VERSION 5.8 ;
BUSBITCHARS "[]" ;
DIVIDERCHAR "/" ;
UNITS
    DATABASE MICRONS 1000 ;
END UNITS

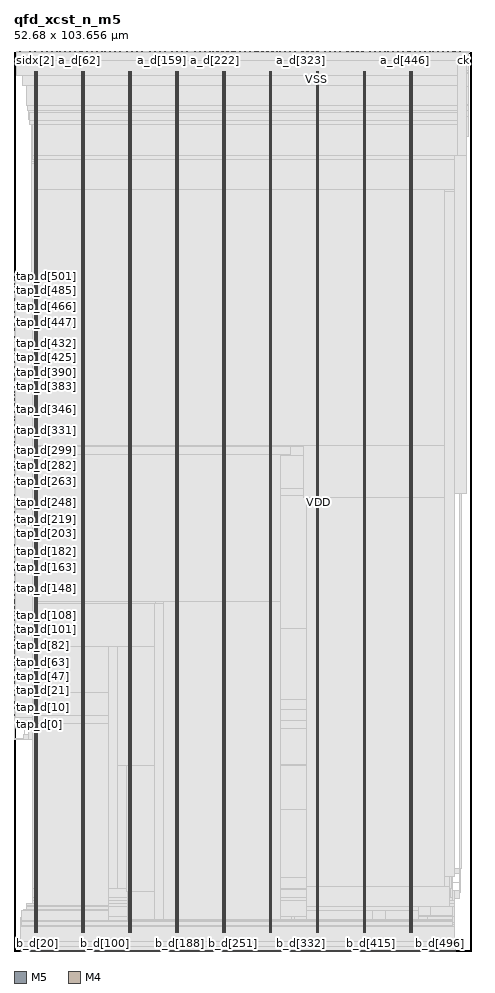
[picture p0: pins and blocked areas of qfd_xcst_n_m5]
MACRO qfd_xcst_n_m5
  FOREIGN qfd_xcst_n_m5 0 0 ;
  CLASS BLOCK ;
  SIZE 52.68 BY 103.656 ;
  PIN a_d[0]
    DIRECTION OUTPUT ;
    USE SIGNAL ;
    PORT
      LAYER M5 ;
        RECT  1.44 103.572 1.464 103.656 ;
    END
  END a_d[0]
  PIN a_d[100]
    DIRECTION OUTPUT ;
    USE SIGNAL ;
    PORT
      LAYER M5 ;
        RECT  11.232 103.572 11.256 103.656 ;
    END
  END a_d[100]
  PIN a_d[101]
    DIRECTION OUTPUT ;
    USE SIGNAL ;
    PORT
      LAYER M5 ;
        RECT  11.328 103.572 11.352 103.656 ;
    END
  END a_d[101]
  PIN a_d[102]
    DIRECTION OUTPUT ;
    USE SIGNAL ;
    PORT
      LAYER M5 ;
        RECT  11.424 103.572 11.448 103.656 ;
    END
  END a_d[102]
  PIN a_d[103]
    DIRECTION OUTPUT ;
    USE SIGNAL ;
    PORT
      LAYER M5 ;
        RECT  11.52 103.572 11.544 103.656 ;
    END
  END a_d[103]
  PIN a_d[104]
    DIRECTION OUTPUT ;
    USE SIGNAL ;
    PORT
      LAYER M5 ;
        RECT  11.616 103.572 11.64 103.656 ;
    END
  END a_d[104]
  PIN a_d[105]
    DIRECTION OUTPUT ;
    USE SIGNAL ;
    PORT
      LAYER M5 ;
        RECT  11.712 103.572 11.736 103.656 ;
    END
  END a_d[105]
  PIN a_d[106]
    DIRECTION OUTPUT ;
    USE SIGNAL ;
    PORT
      LAYER M5 ;
        RECT  11.808 103.572 11.832 103.656 ;
    END
  END a_d[106]
  PIN a_d[107]
    DIRECTION OUTPUT ;
    USE SIGNAL ;
    PORT
      LAYER M5 ;
        RECT  11.904 103.572 11.928 103.656 ;
    END
  END a_d[107]
  PIN a_d[108]
    DIRECTION OUTPUT ;
    USE SIGNAL ;
    PORT
      LAYER M5 ;
        RECT  12 103.572 12.024 103.656 ;
    END
  END a_d[108]
  PIN a_d[109]
    DIRECTION OUTPUT ;
    USE SIGNAL ;
    PORT
      LAYER M5 ;
        RECT  12.096 103.572 12.12 103.656 ;
    END
  END a_d[109]
  PIN a_d[10]
    DIRECTION OUTPUT ;
    USE SIGNAL ;
    PORT
      LAYER M5 ;
        RECT  2.4 103.572 2.424 103.656 ;
    END
  END a_d[10]
  PIN a_d[110]
    DIRECTION OUTPUT ;
    USE SIGNAL ;
    PORT
      LAYER M5 ;
        RECT  12.192 103.572 12.216 103.656 ;
    END
  END a_d[110]
  PIN a_d[111]
    DIRECTION OUTPUT ;
    USE SIGNAL ;
    PORT
      LAYER M5 ;
        RECT  12.288 103.572 12.312 103.656 ;
    END
  END a_d[111]
  PIN a_d[112]
    DIRECTION OUTPUT ;
    USE SIGNAL ;
    PORT
      LAYER M5 ;
        RECT  12.384 103.572 12.408 103.656 ;
    END
  END a_d[112]
  PIN a_d[113]
    DIRECTION OUTPUT ;
    USE SIGNAL ;
    PORT
      LAYER M5 ;
        RECT  12.48 103.572 12.504 103.656 ;
    END
  END a_d[113]
  PIN a_d[114]
    DIRECTION OUTPUT ;
    USE SIGNAL ;
    PORT
      LAYER M5 ;
        RECT  12.576 103.572 12.6 103.656 ;
    END
  END a_d[114]
  PIN a_d[115]
    DIRECTION OUTPUT ;
    USE SIGNAL ;
    PORT
      LAYER M5 ;
        RECT  12.672 103.572 12.696 103.656 ;
    END
  END a_d[115]
  PIN a_d[116]
    DIRECTION OUTPUT ;
    USE SIGNAL ;
    PORT
      LAYER M5 ;
        RECT  12.816 103.572 12.84 103.656 ;
    END
  END a_d[116]
  PIN a_d[117]
    DIRECTION OUTPUT ;
    USE SIGNAL ;
    PORT
      LAYER M5 ;
        RECT  12.912 103.572 12.936 103.656 ;
    END
  END a_d[117]
  PIN a_d[118]
    DIRECTION OUTPUT ;
    USE SIGNAL ;
    PORT
      LAYER M5 ;
        RECT  13.008 103.572 13.032 103.656 ;
    END
  END a_d[118]
  PIN a_d[119]
    DIRECTION OUTPUT ;
    USE SIGNAL ;
    PORT
      LAYER M5 ;
        RECT  13.104 103.572 13.128 103.656 ;
    END
  END a_d[119]
  PIN a_d[11]
    DIRECTION OUTPUT ;
    USE SIGNAL ;
    PORT
      LAYER M5 ;
        RECT  2.496 103.572 2.52 103.656 ;
    END
  END a_d[11]
  PIN a_d[120]
    DIRECTION OUTPUT ;
    USE SIGNAL ;
    PORT
      LAYER M5 ;
        RECT  13.2 103.572 13.224 103.656 ;
    END
  END a_d[120]
  PIN a_d[121]
    DIRECTION OUTPUT ;
    USE SIGNAL ;
    PORT
      LAYER M5 ;
        RECT  13.296 103.572 13.32 103.656 ;
    END
  END a_d[121]
  PIN a_d[122]
    DIRECTION OUTPUT ;
    USE SIGNAL ;
    PORT
      LAYER M5 ;
        RECT  13.392 103.572 13.416 103.656 ;
    END
  END a_d[122]
  PIN a_d[123]
    DIRECTION OUTPUT ;
    USE SIGNAL ;
    PORT
      LAYER M5 ;
        RECT  13.488 103.572 13.512 103.656 ;
    END
  END a_d[123]
  PIN a_d[124]
    DIRECTION OUTPUT ;
    USE SIGNAL ;
    PORT
      LAYER M5 ;
        RECT  13.584 103.572 13.608 103.656 ;
    END
  END a_d[124]
  PIN a_d[125]
    DIRECTION OUTPUT ;
    USE SIGNAL ;
    PORT
      LAYER M5 ;
        RECT  13.68 103.572 13.704 103.656 ;
    END
  END a_d[125]
  PIN a_d[126]
    DIRECTION OUTPUT ;
    USE SIGNAL ;
    PORT
      LAYER M5 ;
        RECT  13.776 103.572 13.8 103.656 ;
    END
  END a_d[126]
  PIN a_d[127]
    DIRECTION OUTPUT ;
    USE SIGNAL ;
    PORT
      LAYER M5 ;
        RECT  13.872 103.572 13.896 103.656 ;
    END
  END a_d[127]
  PIN a_d[128]
    DIRECTION OUTPUT ;
    USE SIGNAL ;
    PORT
      LAYER M5 ;
        RECT  13.968 103.572 13.992 103.656 ;
    END
  END a_d[128]
  PIN a_d[129]
    DIRECTION OUTPUT ;
    USE SIGNAL ;
    PORT
      LAYER M5 ;
        RECT  14.064 103.572 14.088 103.656 ;
    END
  END a_d[129]
  PIN a_d[12]
    DIRECTION OUTPUT ;
    USE SIGNAL ;
    PORT
      LAYER M5 ;
        RECT  2.592 103.572 2.616 103.656 ;
    END
  END a_d[12]
  PIN a_d[130]
    DIRECTION OUTPUT ;
    USE SIGNAL ;
    PORT
      LAYER M5 ;
        RECT  14.16 103.572 14.184 103.656 ;
    END
  END a_d[130]
  PIN a_d[131]
    DIRECTION OUTPUT ;
    USE SIGNAL ;
    PORT
      LAYER M5 ;
        RECT  14.256 103.572 14.28 103.656 ;
    END
  END a_d[131]
  PIN a_d[132]
    DIRECTION OUTPUT ;
    USE SIGNAL ;
    PORT
      LAYER M5 ;
        RECT  14.352 103.572 14.376 103.656 ;
    END
  END a_d[132]
  PIN a_d[133]
    DIRECTION OUTPUT ;
    USE SIGNAL ;
    PORT
      LAYER M5 ;
        RECT  14.448 103.572 14.472 103.656 ;
    END
  END a_d[133]
  PIN a_d[134]
    DIRECTION OUTPUT ;
    USE SIGNAL ;
    PORT
      LAYER M5 ;
        RECT  14.544 103.572 14.568 103.656 ;
    END
  END a_d[134]
  PIN a_d[135]
    DIRECTION OUTPUT ;
    USE SIGNAL ;
    PORT
      LAYER M5 ;
        RECT  14.64 103.572 14.664 103.656 ;
    END
  END a_d[135]
  PIN a_d[136]
    DIRECTION OUTPUT ;
    USE SIGNAL ;
    PORT
      LAYER M5 ;
        RECT  14.736 103.572 14.76 103.656 ;
    END
  END a_d[136]
  PIN a_d[137]
    DIRECTION OUTPUT ;
    USE SIGNAL ;
    PORT
      LAYER M5 ;
        RECT  14.832 103.572 14.856 103.656 ;
    END
  END a_d[137]
  PIN a_d[138]
    DIRECTION OUTPUT ;
    USE SIGNAL ;
    PORT
      LAYER M5 ;
        RECT  14.928 103.572 14.952 103.656 ;
    END
  END a_d[138]
  PIN a_d[139]
    DIRECTION OUTPUT ;
    USE SIGNAL ;
    PORT
      LAYER M5 ;
        RECT  15.024 103.572 15.048 103.656 ;
    END
  END a_d[139]
  PIN a_d[13]
    DIRECTION OUTPUT ;
    USE SIGNAL ;
    PORT
      LAYER M5 ;
        RECT  2.736 103.572 2.76 103.656 ;
    END
  END a_d[13]
  PIN a_d[140]
    DIRECTION OUTPUT ;
    USE SIGNAL ;
    PORT
      LAYER M5 ;
        RECT  15.12 103.572 15.144 103.656 ;
    END
  END a_d[140]
  PIN a_d[141]
    DIRECTION OUTPUT ;
    USE SIGNAL ;
    PORT
      LAYER M5 ;
        RECT  15.216 103.572 15.24 103.656 ;
    END
  END a_d[141]
  PIN a_d[142]
    DIRECTION OUTPUT ;
    USE SIGNAL ;
    PORT
      LAYER M5 ;
        RECT  15.36 103.572 15.384 103.656 ;
    END
  END a_d[142]
  PIN a_d[143]
    DIRECTION OUTPUT ;
    USE SIGNAL ;
    PORT
      LAYER M5 ;
        RECT  15.456 103.572 15.48 103.656 ;
    END
  END a_d[143]
  PIN a_d[144]
    DIRECTION OUTPUT ;
    USE SIGNAL ;
    PORT
      LAYER M5 ;
        RECT  15.552 103.572 15.576 103.656 ;
    END
  END a_d[144]
  PIN a_d[145]
    DIRECTION OUTPUT ;
    USE SIGNAL ;
    PORT
      LAYER M5 ;
        RECT  15.648 103.572 15.672 103.656 ;
    END
  END a_d[145]
  PIN a_d[146]
    DIRECTION OUTPUT ;
    USE SIGNAL ;
    PORT
      LAYER M5 ;
        RECT  15.744 103.572 15.768 103.656 ;
    END
  END a_d[146]
  PIN a_d[147]
    DIRECTION OUTPUT ;
    USE SIGNAL ;
    PORT
      LAYER M5 ;
        RECT  15.84 103.572 15.864 103.656 ;
    END
  END a_d[147]
  PIN a_d[148]
    DIRECTION OUTPUT ;
    USE SIGNAL ;
    PORT
      LAYER M5 ;
        RECT  15.936 103.572 15.96 103.656 ;
    END
  END a_d[148]
  PIN a_d[149]
    DIRECTION OUTPUT ;
    USE SIGNAL ;
    PORT
      LAYER M5 ;
        RECT  16.032 103.572 16.056 103.656 ;
    END
  END a_d[149]
  PIN a_d[14]
    DIRECTION OUTPUT ;
    USE SIGNAL ;
    PORT
      LAYER M5 ;
        RECT  2.832 103.572 2.856 103.656 ;
    END
  END a_d[14]
  PIN a_d[150]
    DIRECTION OUTPUT ;
    USE SIGNAL ;
    PORT
      LAYER M5 ;
        RECT  16.128 103.572 16.152 103.656 ;
    END
  END a_d[150]
  PIN a_d[151]
    DIRECTION OUTPUT ;
    USE SIGNAL ;
    PORT
      LAYER M5 ;
        RECT  16.224 103.572 16.248 103.656 ;
    END
  END a_d[151]
  PIN a_d[152]
    DIRECTION OUTPUT ;
    USE SIGNAL ;
    PORT
      LAYER M5 ;
        RECT  16.32 103.572 16.344 103.656 ;
    END
  END a_d[152]
  PIN a_d[153]
    DIRECTION OUTPUT ;
    USE SIGNAL ;
    PORT
      LAYER M5 ;
        RECT  16.416 103.572 16.44 103.656 ;
    END
  END a_d[153]
  PIN a_d[154]
    DIRECTION OUTPUT ;
    USE SIGNAL ;
    PORT
      LAYER M5 ;
        RECT  16.512 103.572 16.536 103.656 ;
    END
  END a_d[154]
  PIN a_d[155]
    DIRECTION OUTPUT ;
    USE SIGNAL ;
    PORT
      LAYER M5 ;
        RECT  16.608 103.572 16.632 103.656 ;
    END
  END a_d[155]
  PIN a_d[156]
    DIRECTION OUTPUT ;
    USE SIGNAL ;
    PORT
      LAYER M5 ;
        RECT  16.704 103.572 16.728 103.656 ;
    END
  END a_d[156]
  PIN a_d[157]
    DIRECTION OUTPUT ;
    USE SIGNAL ;
    PORT
      LAYER M5 ;
        RECT  16.8 103.572 16.824 103.656 ;
    END
  END a_d[157]
  PIN a_d[158]
    DIRECTION OUTPUT ;
    USE SIGNAL ;
    PORT
      LAYER M5 ;
        RECT  16.896 103.572 16.92 103.656 ;
    END
  END a_d[158]
  PIN a_d[159]
    DIRECTION OUTPUT ;
    USE SIGNAL ;
    PORT
      LAYER M5 ;
        RECT  16.992 103.572 17.016 103.656 ;
    END
  END a_d[159]
  PIN a_d[15]
    DIRECTION OUTPUT ;
    USE SIGNAL ;
    PORT
      LAYER M5 ;
        RECT  2.928 103.572 2.952 103.656 ;
    END
  END a_d[15]
  PIN a_d[160]
    DIRECTION OUTPUT ;
    USE SIGNAL ;
    PORT
      LAYER M5 ;
        RECT  17.088 103.572 17.112 103.656 ;
    END
  END a_d[160]
  PIN a_d[161]
    DIRECTION OUTPUT ;
    USE SIGNAL ;
    PORT
      LAYER M5 ;
        RECT  17.184 103.572 17.208 103.656 ;
    END
  END a_d[161]
  PIN a_d[162]
    DIRECTION OUTPUT ;
    USE SIGNAL ;
    PORT
      LAYER M5 ;
        RECT  17.28 103.572 17.304 103.656 ;
    END
  END a_d[162]
  PIN a_d[163]
    DIRECTION OUTPUT ;
    USE SIGNAL ;
    PORT
      LAYER M5 ;
        RECT  17.376 103.572 17.4 103.656 ;
    END
  END a_d[163]
  PIN a_d[164]
    DIRECTION OUTPUT ;
    USE SIGNAL ;
    PORT
      LAYER M5 ;
        RECT  17.472 103.572 17.496 103.656 ;
    END
  END a_d[164]
  PIN a_d[165]
    DIRECTION OUTPUT ;
    USE SIGNAL ;
    PORT
      LAYER M5 ;
        RECT  17.568 103.572 17.592 103.656 ;
    END
  END a_d[165]
  PIN a_d[166]
    DIRECTION OUTPUT ;
    USE SIGNAL ;
    PORT
      LAYER M5 ;
        RECT  17.664 103.572 17.688 103.656 ;
    END
  END a_d[166]
  PIN a_d[167]
    DIRECTION OUTPUT ;
    USE SIGNAL ;
    PORT
      LAYER M5 ;
        RECT  17.808 103.572 17.832 103.656 ;
    END
  END a_d[167]
  PIN a_d[168]
    DIRECTION OUTPUT ;
    USE SIGNAL ;
    PORT
      LAYER M5 ;
        RECT  17.904 103.572 17.928 103.656 ;
    END
  END a_d[168]
  PIN a_d[169]
    DIRECTION OUTPUT ;
    USE SIGNAL ;
    PORT
      LAYER M5 ;
        RECT  18 103.572 18.024 103.656 ;
    END
  END a_d[169]
  PIN a_d[16]
    DIRECTION OUTPUT ;
    USE SIGNAL ;
    PORT
      LAYER M5 ;
        RECT  3.024 103.572 3.048 103.656 ;
    END
  END a_d[16]
  PIN a_d[170]
    DIRECTION OUTPUT ;
    USE SIGNAL ;
    PORT
      LAYER M5 ;
        RECT  18.096 103.572 18.12 103.656 ;
    END
  END a_d[170]
  PIN a_d[171]
    DIRECTION OUTPUT ;
    USE SIGNAL ;
    PORT
      LAYER M5 ;
        RECT  18.192 103.572 18.216 103.656 ;
    END
  END a_d[171]
  PIN a_d[172]
    DIRECTION OUTPUT ;
    USE SIGNAL ;
    PORT
      LAYER M5 ;
        RECT  18.288 103.572 18.312 103.656 ;
    END
  END a_d[172]
  PIN a_d[173]
    DIRECTION OUTPUT ;
    USE SIGNAL ;
    PORT
      LAYER M5 ;
        RECT  18.384 103.572 18.408 103.656 ;
    END
  END a_d[173]
  PIN a_d[174]
    DIRECTION OUTPUT ;
    USE SIGNAL ;
    PORT
      LAYER M5 ;
        RECT  18.48 103.572 18.504 103.656 ;
    END
  END a_d[174]
  PIN a_d[175]
    DIRECTION OUTPUT ;
    USE SIGNAL ;
    PORT
      LAYER M5 ;
        RECT  18.576 103.572 18.6 103.656 ;
    END
  END a_d[175]
  PIN a_d[176]
    DIRECTION OUTPUT ;
    USE SIGNAL ;
    PORT
      LAYER M5 ;
        RECT  18.672 103.572 18.696 103.656 ;
    END
  END a_d[176]
  PIN a_d[177]
    DIRECTION OUTPUT ;
    USE SIGNAL ;
    PORT
      LAYER M5 ;
        RECT  18.768 103.572 18.792 103.656 ;
    END
  END a_d[177]
  PIN a_d[178]
    DIRECTION OUTPUT ;
    USE SIGNAL ;
    PORT
      LAYER M5 ;
        RECT  18.864 103.572 18.888 103.656 ;
    END
  END a_d[178]
  PIN a_d[179]
    DIRECTION OUTPUT ;
    USE SIGNAL ;
    PORT
      LAYER M5 ;
        RECT  18.96 103.572 18.984 103.656 ;
    END
  END a_d[179]
  PIN a_d[17]
    DIRECTION OUTPUT ;
    USE SIGNAL ;
    PORT
      LAYER M5 ;
        RECT  3.12 103.572 3.144 103.656 ;
    END
  END a_d[17]
  PIN a_d[180]
    DIRECTION OUTPUT ;
    USE SIGNAL ;
    PORT
      LAYER M5 ;
        RECT  19.056 103.572 19.08 103.656 ;
    END
  END a_d[180]
  PIN a_d[181]
    DIRECTION OUTPUT ;
    USE SIGNAL ;
    PORT
      LAYER M5 ;
        RECT  19.152 103.572 19.176 103.656 ;
    END
  END a_d[181]
  PIN a_d[182]
    DIRECTION OUTPUT ;
    USE SIGNAL ;
    PORT
      LAYER M5 ;
        RECT  19.248 103.572 19.272 103.656 ;
    END
  END a_d[182]
  PIN a_d[183]
    DIRECTION OUTPUT ;
    USE SIGNAL ;
    PORT
      LAYER M5 ;
        RECT  19.344 103.572 19.368 103.656 ;
    END
  END a_d[183]
  PIN a_d[184]
    DIRECTION OUTPUT ;
    USE SIGNAL ;
    PORT
      LAYER M5 ;
        RECT  19.44 103.572 19.464 103.656 ;
    END
  END a_d[184]
  PIN a_d[185]
    DIRECTION OUTPUT ;
    USE SIGNAL ;
    PORT
      LAYER M5 ;
        RECT  19.536 103.572 19.56 103.656 ;
    END
  END a_d[185]
  PIN a_d[186]
    DIRECTION OUTPUT ;
    USE SIGNAL ;
    PORT
      LAYER M5 ;
        RECT  19.632 103.572 19.656 103.656 ;
    END
  END a_d[186]
  PIN a_d[187]
    DIRECTION OUTPUT ;
    USE SIGNAL ;
    PORT
      LAYER M5 ;
        RECT  19.728 103.572 19.752 103.656 ;
    END
  END a_d[187]
  PIN a_d[188]
    DIRECTION OUTPUT ;
    USE SIGNAL ;
    PORT
      LAYER M5 ;
        RECT  19.824 103.572 19.848 103.656 ;
    END
  END a_d[188]
  PIN a_d[189]
    DIRECTION OUTPUT ;
    USE SIGNAL ;
    PORT
      LAYER M5 ;
        RECT  19.92 103.572 19.944 103.656 ;
    END
  END a_d[189]
  PIN a_d[18]
    DIRECTION OUTPUT ;
    USE SIGNAL ;
    PORT
      LAYER M5 ;
        RECT  3.216 103.572 3.24 103.656 ;
    END
  END a_d[18]
  PIN a_d[190]
    DIRECTION OUTPUT ;
    USE SIGNAL ;
    PORT
      LAYER M5 ;
        RECT  20.016 103.572 20.04 103.656 ;
    END
  END a_d[190]
  PIN a_d[191]
    DIRECTION OUTPUT ;
    USE SIGNAL ;
    PORT
      LAYER M5 ;
        RECT  20.112 103.572 20.136 103.656 ;
    END
  END a_d[191]
  PIN a_d[192]
    DIRECTION OUTPUT ;
    USE SIGNAL ;
    PORT
      LAYER M5 ;
        RECT  20.208 103.572 20.232 103.656 ;
    END
  END a_d[192]
  PIN a_d[193]
    DIRECTION OUTPUT ;
    USE SIGNAL ;
    PORT
      LAYER M5 ;
        RECT  20.352 103.572 20.376 103.656 ;
    END
  END a_d[193]
  PIN a_d[194]
    DIRECTION OUTPUT ;
    USE SIGNAL ;
    PORT
      LAYER M5 ;
        RECT  20.448 103.572 20.472 103.656 ;
    END
  END a_d[194]
  PIN a_d[195]
    DIRECTION OUTPUT ;
    USE SIGNAL ;
    PORT
      LAYER M5 ;
        RECT  20.544 103.572 20.568 103.656 ;
    END
  END a_d[195]
  PIN a_d[196]
    DIRECTION OUTPUT ;
    USE SIGNAL ;
    PORT
      LAYER M5 ;
        RECT  20.64 103.572 20.664 103.656 ;
    END
  END a_d[196]
  PIN a_d[197]
    DIRECTION OUTPUT ;
    USE SIGNAL ;
    PORT
      LAYER M5 ;
        RECT  20.736 103.572 20.76 103.656 ;
    END
  END a_d[197]
  PIN a_d[198]
    DIRECTION OUTPUT ;
    USE SIGNAL ;
    PORT
      LAYER M5 ;
        RECT  20.832 103.572 20.856 103.656 ;
    END
  END a_d[198]
  PIN a_d[199]
    DIRECTION OUTPUT ;
    USE SIGNAL ;
    PORT
      LAYER M5 ;
        RECT  20.928 103.572 20.952 103.656 ;
    END
  END a_d[199]
  PIN a_d[19]
    DIRECTION OUTPUT ;
    USE SIGNAL ;
    PORT
      LAYER M5 ;
        RECT  3.312 103.572 3.336 103.656 ;
    END
  END a_d[19]
  PIN a_d[1]
    DIRECTION OUTPUT ;
    USE SIGNAL ;
    PORT
      LAYER M5 ;
        RECT  1.536 103.572 1.56 103.656 ;
    END
  END a_d[1]
  PIN a_d[200]
    DIRECTION OUTPUT ;
    USE SIGNAL ;
    PORT
      LAYER M5 ;
        RECT  21.024 103.572 21.048 103.656 ;
    END
  END a_d[200]
  PIN a_d[201]
    DIRECTION OUTPUT ;
    USE SIGNAL ;
    PORT
      LAYER M5 ;
        RECT  21.12 103.572 21.144 103.656 ;
    END
  END a_d[201]
  PIN a_d[202]
    DIRECTION OUTPUT ;
    USE SIGNAL ;
    PORT
      LAYER M5 ;
        RECT  21.216 103.572 21.24 103.656 ;
    END
  END a_d[202]
  PIN a_d[203]
    DIRECTION OUTPUT ;
    USE SIGNAL ;
    PORT
      LAYER M5 ;
        RECT  21.312 103.572 21.336 103.656 ;
    END
  END a_d[203]
  PIN a_d[204]
    DIRECTION OUTPUT ;
    USE SIGNAL ;
    PORT
      LAYER M5 ;
        RECT  21.408 103.572 21.432 103.656 ;
    END
  END a_d[204]
  PIN a_d[205]
    DIRECTION OUTPUT ;
    USE SIGNAL ;
    PORT
      LAYER M5 ;
        RECT  21.504 103.572 21.528 103.656 ;
    END
  END a_d[205]
  PIN a_d[206]
    DIRECTION OUTPUT ;
    USE SIGNAL ;
    PORT
      LAYER M5 ;
        RECT  21.6 103.572 21.624 103.656 ;
    END
  END a_d[206]
  PIN a_d[207]
    DIRECTION OUTPUT ;
    USE SIGNAL ;
    PORT
      LAYER M5 ;
        RECT  21.696 103.572 21.72 103.656 ;
    END
  END a_d[207]
  PIN a_d[208]
    DIRECTION OUTPUT ;
    USE SIGNAL ;
    PORT
      LAYER M5 ;
        RECT  21.792 103.572 21.816 103.656 ;
    END
  END a_d[208]
  PIN a_d[209]
    DIRECTION OUTPUT ;
    USE SIGNAL ;
    PORT
      LAYER M5 ;
        RECT  21.888 103.572 21.912 103.656 ;
    END
  END a_d[209]
  PIN a_d[20]
    DIRECTION OUTPUT ;
    USE SIGNAL ;
    PORT
      LAYER M5 ;
        RECT  3.408 103.572 3.432 103.656 ;
    END
  END a_d[20]
  PIN a_d[210]
    DIRECTION OUTPUT ;
    USE SIGNAL ;
    PORT
      LAYER M5 ;
        RECT  21.984 103.572 22.008 103.656 ;
    END
  END a_d[210]
  PIN a_d[211]
    DIRECTION OUTPUT ;
    USE SIGNAL ;
    PORT
      LAYER M5 ;
        RECT  22.08 103.572 22.104 103.656 ;
    END
  END a_d[211]
  PIN a_d[212]
    DIRECTION OUTPUT ;
    USE SIGNAL ;
    PORT
      LAYER M5 ;
        RECT  22.176 103.572 22.2 103.656 ;
    END
  END a_d[212]
  PIN a_d[213]
    DIRECTION OUTPUT ;
    USE SIGNAL ;
    PORT
      LAYER M5 ;
        RECT  22.272 103.572 22.296 103.656 ;
    END
  END a_d[213]
  PIN a_d[214]
    DIRECTION OUTPUT ;
    USE SIGNAL ;
    PORT
      LAYER M5 ;
        RECT  22.368 103.572 22.392 103.656 ;
    END
  END a_d[214]
  PIN a_d[215]
    DIRECTION OUTPUT ;
    USE SIGNAL ;
    PORT
      LAYER M5 ;
        RECT  22.464 103.572 22.488 103.656 ;
    END
  END a_d[215]
  PIN a_d[216]
    DIRECTION OUTPUT ;
    USE SIGNAL ;
    PORT
      LAYER M5 ;
        RECT  22.56 103.572 22.584 103.656 ;
    END
  END a_d[216]
  PIN a_d[217]
    DIRECTION OUTPUT ;
    USE SIGNAL ;
    PORT
      LAYER M5 ;
        RECT  22.656 103.572 22.68 103.656 ;
    END
  END a_d[217]
  PIN a_d[218]
    DIRECTION OUTPUT ;
    USE SIGNAL ;
    PORT
      LAYER M5 ;
        RECT  22.752 103.572 22.776 103.656 ;
    END
  END a_d[218]
  PIN a_d[219]
    DIRECTION OUTPUT ;
    USE SIGNAL ;
    PORT
      LAYER M5 ;
        RECT  22.896 103.572 22.92 103.656 ;
    END
  END a_d[219]
  PIN a_d[21]
    DIRECTION OUTPUT ;
    USE SIGNAL ;
    PORT
      LAYER M5 ;
        RECT  3.504 103.572 3.528 103.656 ;
    END
  END a_d[21]
  PIN a_d[220]
    DIRECTION OUTPUT ;
    USE SIGNAL ;
    PORT
      LAYER M5 ;
        RECT  22.992 103.572 23.016 103.656 ;
    END
  END a_d[220]
  PIN a_d[221]
    DIRECTION OUTPUT ;
    USE SIGNAL ;
    PORT
      LAYER M5 ;
        RECT  23.088 103.572 23.112 103.656 ;
    END
  END a_d[221]
  PIN a_d[222]
    DIRECTION OUTPUT ;
    USE SIGNAL ;
    PORT
      LAYER M5 ;
        RECT  23.184 103.572 23.208 103.656 ;
    END
  END a_d[222]
  PIN a_d[223]
    DIRECTION OUTPUT ;
    USE SIGNAL ;
    PORT
      LAYER M5 ;
        RECT  23.28 103.572 23.304 103.656 ;
    END
  END a_d[223]
  PIN a_d[224]
    DIRECTION OUTPUT ;
    USE SIGNAL ;
    PORT
      LAYER M5 ;
        RECT  23.376 103.572 23.4 103.656 ;
    END
  END a_d[224]
  PIN a_d[225]
    DIRECTION OUTPUT ;
    USE SIGNAL ;
    PORT
      LAYER M5 ;
        RECT  23.472 103.572 23.496 103.656 ;
    END
  END a_d[225]
  PIN a_d[226]
    DIRECTION OUTPUT ;
    USE SIGNAL ;
    PORT
      LAYER M5 ;
        RECT  23.568 103.572 23.592 103.656 ;
    END
  END a_d[226]
  PIN a_d[227]
    DIRECTION OUTPUT ;
    USE SIGNAL ;
    PORT
      LAYER M5 ;
        RECT  23.664 103.572 23.688 103.656 ;
    END
  END a_d[227]
  PIN a_d[228]
    DIRECTION OUTPUT ;
    USE SIGNAL ;
    PORT
      LAYER M5 ;
        RECT  23.76 103.572 23.784 103.656 ;
    END
  END a_d[228]
  PIN a_d[229]
    DIRECTION OUTPUT ;
    USE SIGNAL ;
    PORT
      LAYER M5 ;
        RECT  23.856 103.572 23.88 103.656 ;
    END
  END a_d[229]
  PIN a_d[22]
    DIRECTION OUTPUT ;
    USE SIGNAL ;
    PORT
      LAYER M5 ;
        RECT  3.6 103.572 3.624 103.656 ;
    END
  END a_d[22]
  PIN a_d[230]
    DIRECTION OUTPUT ;
    USE SIGNAL ;
    PORT
      LAYER M5 ;
        RECT  23.952 103.572 23.976 103.656 ;
    END
  END a_d[230]
  PIN a_d[231]
    DIRECTION OUTPUT ;
    USE SIGNAL ;
    PORT
      LAYER M5 ;
        RECT  24.048 103.572 24.072 103.656 ;
    END
  END a_d[231]
  PIN a_d[232]
    DIRECTION OUTPUT ;
    USE SIGNAL ;
    PORT
      LAYER M5 ;
        RECT  24.144 103.572 24.168 103.656 ;
    END
  END a_d[232]
  PIN a_d[233]
    DIRECTION OUTPUT ;
    USE SIGNAL ;
    PORT
      LAYER M5 ;
        RECT  24.24 103.572 24.264 103.656 ;
    END
  END a_d[233]
  PIN a_d[234]
    DIRECTION OUTPUT ;
    USE SIGNAL ;
    PORT
      LAYER M5 ;
        RECT  24.336 103.572 24.36 103.656 ;
    END
  END a_d[234]
  PIN a_d[235]
    DIRECTION OUTPUT ;
    USE SIGNAL ;
    PORT
      LAYER M5 ;
        RECT  24.432 103.572 24.456 103.656 ;
    END
  END a_d[235]
  PIN a_d[236]
    DIRECTION OUTPUT ;
    USE SIGNAL ;
    PORT
      LAYER M5 ;
        RECT  24.528 103.572 24.552 103.656 ;
    END
  END a_d[236]
  PIN a_d[237]
    DIRECTION OUTPUT ;
    USE SIGNAL ;
    PORT
      LAYER M5 ;
        RECT  24.624 103.572 24.648 103.656 ;
    END
  END a_d[237]
  PIN a_d[238]
    DIRECTION OUTPUT ;
    USE SIGNAL ;
    PORT
      LAYER M5 ;
        RECT  24.72 103.572 24.744 103.656 ;
    END
  END a_d[238]
  PIN a_d[239]
    DIRECTION OUTPUT ;
    USE SIGNAL ;
    PORT
      LAYER M5 ;
        RECT  24.816 103.572 24.84 103.656 ;
    END
  END a_d[239]
  PIN a_d[23]
    DIRECTION OUTPUT ;
    USE SIGNAL ;
    PORT
      LAYER M5 ;
        RECT  3.696 103.572 3.72 103.656 ;
    END
  END a_d[23]
  PIN a_d[240]
    DIRECTION OUTPUT ;
    USE SIGNAL ;
    PORT
      LAYER M5 ;
        RECT  24.912 103.572 24.936 103.656 ;
    END
  END a_d[240]
  PIN a_d[241]
    DIRECTION OUTPUT ;
    USE SIGNAL ;
    PORT
      LAYER M5 ;
        RECT  25.008 103.572 25.032 103.656 ;
    END
  END a_d[241]
  PIN a_d[242]
    DIRECTION OUTPUT ;
    USE SIGNAL ;
    PORT
      LAYER M5 ;
        RECT  25.104 103.572 25.128 103.656 ;
    END
  END a_d[242]
  PIN a_d[243]
    DIRECTION OUTPUT ;
    USE SIGNAL ;
    PORT
      LAYER M5 ;
        RECT  25.2 103.572 25.224 103.656 ;
    END
  END a_d[243]
  PIN a_d[244]
    DIRECTION OUTPUT ;
    USE SIGNAL ;
    PORT
      LAYER M5 ;
        RECT  25.296 103.572 25.32 103.656 ;
    END
  END a_d[244]
  PIN a_d[245]
    DIRECTION OUTPUT ;
    USE SIGNAL ;
    PORT
      LAYER M5 ;
        RECT  25.44 103.572 25.464 103.656 ;
    END
  END a_d[245]
  PIN a_d[246]
    DIRECTION OUTPUT ;
    USE SIGNAL ;
    PORT
      LAYER M5 ;
        RECT  25.536 103.572 25.56 103.656 ;
    END
  END a_d[246]
  PIN a_d[247]
    DIRECTION OUTPUT ;
    USE SIGNAL ;
    PORT
      LAYER M5 ;
        RECT  25.632 103.572 25.656 103.656 ;
    END
  END a_d[247]
  PIN a_d[248]
    DIRECTION OUTPUT ;
    USE SIGNAL ;
    PORT
      LAYER M5 ;
        RECT  25.728 103.572 25.752 103.656 ;
    END
  END a_d[248]
  PIN a_d[249]
    DIRECTION OUTPUT ;
    USE SIGNAL ;
    PORT
      LAYER M5 ;
        RECT  25.824 103.572 25.848 103.656 ;
    END
  END a_d[249]
  PIN a_d[24]
    DIRECTION OUTPUT ;
    USE SIGNAL ;
    PORT
      LAYER M5 ;
        RECT  3.792 103.572 3.816 103.656 ;
    END
  END a_d[24]
  PIN a_d[250]
    DIRECTION OUTPUT ;
    USE SIGNAL ;
    PORT
      LAYER M5 ;
        RECT  25.92 103.572 25.944 103.656 ;
    END
  END a_d[250]
  PIN a_d[251]
    DIRECTION OUTPUT ;
    USE SIGNAL ;
    PORT
      LAYER M5 ;
        RECT  26.016 103.572 26.04 103.656 ;
    END
  END a_d[251]
  PIN a_d[252]
    DIRECTION OUTPUT ;
    USE SIGNAL ;
    PORT
      LAYER M5 ;
        RECT  26.112 103.572 26.136 103.656 ;
    END
  END a_d[252]
  PIN a_d[253]
    DIRECTION OUTPUT ;
    USE SIGNAL ;
    PORT
      LAYER M5 ;
        RECT  26.208 103.572 26.232 103.656 ;
    END
  END a_d[253]
  PIN a_d[254]
    DIRECTION OUTPUT ;
    USE SIGNAL ;
    PORT
      LAYER M5 ;
        RECT  26.304 103.572 26.328 103.656 ;
    END
  END a_d[254]
  PIN a_d[255]
    DIRECTION OUTPUT ;
    USE SIGNAL ;
    PORT
      LAYER M5 ;
        RECT  26.4 103.572 26.424 103.656 ;
    END
  END a_d[255]
  PIN a_d[256]
    DIRECTION OUTPUT ;
    USE SIGNAL ;
    PORT
      LAYER M5 ;
        RECT  26.496 103.572 26.52 103.656 ;
    END
  END a_d[256]
  PIN a_d[257]
    DIRECTION OUTPUT ;
    USE SIGNAL ;
    PORT
      LAYER M5 ;
        RECT  26.592 103.572 26.616 103.656 ;
    END
  END a_d[257]
  PIN a_d[258]
    DIRECTION OUTPUT ;
    USE SIGNAL ;
    PORT
      LAYER M5 ;
        RECT  26.688 103.572 26.712 103.656 ;
    END
  END a_d[258]
  PIN a_d[259]
    DIRECTION OUTPUT ;
    USE SIGNAL ;
    PORT
      LAYER M5 ;
        RECT  26.784 103.572 26.808 103.656 ;
    END
  END a_d[259]
  PIN a_d[25]
    DIRECTION OUTPUT ;
    USE SIGNAL ;
    PORT
      LAYER M5 ;
        RECT  3.888 103.572 3.912 103.656 ;
    END
  END a_d[25]
  PIN a_d[260]
    DIRECTION OUTPUT ;
    USE SIGNAL ;
    PORT
      LAYER M5 ;
        RECT  26.88 103.572 26.904 103.656 ;
    END
  END a_d[260]
  PIN a_d[261]
    DIRECTION OUTPUT ;
    USE SIGNAL ;
    PORT
      LAYER M5 ;
        RECT  26.976 103.572 27 103.656 ;
    END
  END a_d[261]
  PIN a_d[262]
    DIRECTION OUTPUT ;
    USE SIGNAL ;
    PORT
      LAYER M5 ;
        RECT  27.072 103.572 27.096 103.656 ;
    END
  END a_d[262]
  PIN a_d[263]
    DIRECTION OUTPUT ;
    USE SIGNAL ;
    PORT
      LAYER M5 ;
        RECT  27.168 103.572 27.192 103.656 ;
    END
  END a_d[263]
  PIN a_d[264]
    DIRECTION OUTPUT ;
    USE SIGNAL ;
    PORT
      LAYER M5 ;
        RECT  27.264 103.572 27.288 103.656 ;
    END
  END a_d[264]
  PIN a_d[265]
    DIRECTION OUTPUT ;
    USE SIGNAL ;
    PORT
      LAYER M5 ;
        RECT  27.36 103.572 27.384 103.656 ;
    END
  END a_d[265]
  PIN a_d[266]
    DIRECTION OUTPUT ;
    USE SIGNAL ;
    PORT
      LAYER M5 ;
        RECT  27.456 103.572 27.48 103.656 ;
    END
  END a_d[266]
  PIN a_d[267]
    DIRECTION OUTPUT ;
    USE SIGNAL ;
    PORT
      LAYER M5 ;
        RECT  27.552 103.572 27.576 103.656 ;
    END
  END a_d[267]
  PIN a_d[268]
    DIRECTION OUTPUT ;
    USE SIGNAL ;
    PORT
      LAYER M5 ;
        RECT  27.648 103.572 27.672 103.656 ;
    END
  END a_d[268]
  PIN a_d[269]
    DIRECTION OUTPUT ;
    USE SIGNAL ;
    PORT
      LAYER M5 ;
        RECT  27.744 103.572 27.768 103.656 ;
    END
  END a_d[269]
  PIN a_d[26]
    DIRECTION OUTPUT ;
    USE SIGNAL ;
    PORT
      LAYER M5 ;
        RECT  3.984 103.572 4.008 103.656 ;
    END
  END a_d[26]
  PIN a_d[270]
    DIRECTION OUTPUT ;
    USE SIGNAL ;
    PORT
      LAYER M5 ;
        RECT  27.84 103.572 27.864 103.656 ;
    END
  END a_d[270]
  PIN a_d[271]
    DIRECTION OUTPUT ;
    USE SIGNAL ;
    PORT
      LAYER M5 ;
        RECT  27.984 103.572 28.008 103.656 ;
    END
  END a_d[271]
  PIN a_d[272]
    DIRECTION OUTPUT ;
    USE SIGNAL ;
    PORT
      LAYER M5 ;
        RECT  28.08 103.572 28.104 103.656 ;
    END
  END a_d[272]
  PIN a_d[273]
    DIRECTION OUTPUT ;
    USE SIGNAL ;
    PORT
      LAYER M5 ;
        RECT  28.176 103.572 28.2 103.656 ;
    END
  END a_d[273]
  PIN a_d[274]
    DIRECTION OUTPUT ;
    USE SIGNAL ;
    PORT
      LAYER M5 ;
        RECT  28.272 103.572 28.296 103.656 ;
    END
  END a_d[274]
  PIN a_d[275]
    DIRECTION OUTPUT ;
    USE SIGNAL ;
    PORT
      LAYER M5 ;
        RECT  28.368 103.572 28.392 103.656 ;
    END
  END a_d[275]
  PIN a_d[276]
    DIRECTION OUTPUT ;
    USE SIGNAL ;
    PORT
      LAYER M5 ;
        RECT  28.464 103.572 28.488 103.656 ;
    END
  END a_d[276]
  PIN a_d[277]
    DIRECTION OUTPUT ;
    USE SIGNAL ;
    PORT
      LAYER M5 ;
        RECT  28.56 103.572 28.584 103.656 ;
    END
  END a_d[277]
  PIN a_d[278]
    DIRECTION OUTPUT ;
    USE SIGNAL ;
    PORT
      LAYER M5 ;
        RECT  28.656 103.572 28.68 103.656 ;
    END
  END a_d[278]
  PIN a_d[279]
    DIRECTION OUTPUT ;
    USE SIGNAL ;
    PORT
      LAYER M5 ;
        RECT  28.752 103.572 28.776 103.656 ;
    END
  END a_d[279]
  PIN a_d[27]
    DIRECTION OUTPUT ;
    USE SIGNAL ;
    PORT
      LAYER M5 ;
        RECT  4.08 103.572 4.104 103.656 ;
    END
  END a_d[27]
  PIN a_d[280]
    DIRECTION OUTPUT ;
    USE SIGNAL ;
    PORT
      LAYER M5 ;
        RECT  28.848 103.572 28.872 103.656 ;
    END
  END a_d[280]
  PIN a_d[281]
    DIRECTION OUTPUT ;
    USE SIGNAL ;
    PORT
      LAYER M5 ;
        RECT  28.944 103.572 28.968 103.656 ;
    END
  END a_d[281]
  PIN a_d[282]
    DIRECTION OUTPUT ;
    USE SIGNAL ;
    PORT
      LAYER M5 ;
        RECT  29.04 103.572 29.064 103.656 ;
    END
  END a_d[282]
  PIN a_d[283]
    DIRECTION OUTPUT ;
    USE SIGNAL ;
    PORT
      LAYER M5 ;
        RECT  29.136 103.572 29.16 103.656 ;
    END
  END a_d[283]
  PIN a_d[284]
    DIRECTION OUTPUT ;
    USE SIGNAL ;
    PORT
      LAYER M5 ;
        RECT  29.232 103.572 29.256 103.656 ;
    END
  END a_d[284]
  PIN a_d[285]
    DIRECTION OUTPUT ;
    USE SIGNAL ;
    PORT
      LAYER M5 ;
        RECT  29.328 103.572 29.352 103.656 ;
    END
  END a_d[285]
  PIN a_d[286]
    DIRECTION OUTPUT ;
    USE SIGNAL ;
    PORT
      LAYER M5 ;
        RECT  29.424 103.572 29.448 103.656 ;
    END
  END a_d[286]
  PIN a_d[287]
    DIRECTION OUTPUT ;
    USE SIGNAL ;
    PORT
      LAYER M5 ;
        RECT  29.52 103.572 29.544 103.656 ;
    END
  END a_d[287]
  PIN a_d[288]
    DIRECTION OUTPUT ;
    USE SIGNAL ;
    PORT
      LAYER M5 ;
        RECT  29.616 103.572 29.64 103.656 ;
    END
  END a_d[288]
  PIN a_d[289]
    DIRECTION OUTPUT ;
    USE SIGNAL ;
    PORT
      LAYER M5 ;
        RECT  29.712 103.572 29.736 103.656 ;
    END
  END a_d[289]
  PIN a_d[28]
    DIRECTION OUTPUT ;
    USE SIGNAL ;
    PORT
      LAYER M5 ;
        RECT  4.176 103.572 4.2 103.656 ;
    END
  END a_d[28]
  PIN a_d[290]
    DIRECTION OUTPUT ;
    USE SIGNAL ;
    PORT
      LAYER M5 ;
        RECT  29.808 103.572 29.832 103.656 ;
    END
  END a_d[290]
  PIN a_d[291]
    DIRECTION OUTPUT ;
    USE SIGNAL ;
    PORT
      LAYER M5 ;
        RECT  29.904 103.572 29.928 103.656 ;
    END
  END a_d[291]
  PIN a_d[292]
    DIRECTION OUTPUT ;
    USE SIGNAL ;
    PORT
      LAYER M5 ;
        RECT  30 103.572 30.024 103.656 ;
    END
  END a_d[292]
  PIN a_d[293]
    DIRECTION OUTPUT ;
    USE SIGNAL ;
    PORT
      LAYER M5 ;
        RECT  30.096 103.572 30.12 103.656 ;
    END
  END a_d[293]
  PIN a_d[294]
    DIRECTION OUTPUT ;
    USE SIGNAL ;
    PORT
      LAYER M5 ;
        RECT  30.192 103.572 30.216 103.656 ;
    END
  END a_d[294]
  PIN a_d[295]
    DIRECTION OUTPUT ;
    USE SIGNAL ;
    PORT
      LAYER M5 ;
        RECT  30.288 103.572 30.312 103.656 ;
    END
  END a_d[295]
  PIN a_d[296]
    DIRECTION OUTPUT ;
    USE SIGNAL ;
    PORT
      LAYER M5 ;
        RECT  30.432 103.572 30.456 103.656 ;
    END
  END a_d[296]
  PIN a_d[297]
    DIRECTION OUTPUT ;
    USE SIGNAL ;
    PORT
      LAYER M5 ;
        RECT  30.528 103.572 30.552 103.656 ;
    END
  END a_d[297]
  PIN a_d[298]
    DIRECTION OUTPUT ;
    USE SIGNAL ;
    PORT
      LAYER M5 ;
        RECT  30.624 103.572 30.648 103.656 ;
    END
  END a_d[298]
  PIN a_d[299]
    DIRECTION OUTPUT ;
    USE SIGNAL ;
    PORT
      LAYER M5 ;
        RECT  30.72 103.572 30.744 103.656 ;
    END
  END a_d[299]
  PIN a_d[29]
    DIRECTION OUTPUT ;
    USE SIGNAL ;
    PORT
      LAYER M5 ;
        RECT  4.272 103.572 4.296 103.656 ;
    END
  END a_d[29]
  PIN a_d[2]
    DIRECTION OUTPUT ;
    USE SIGNAL ;
    PORT
      LAYER M5 ;
        RECT  1.632 103.572 1.656 103.656 ;
    END
  END a_d[2]
  PIN a_d[300]
    DIRECTION OUTPUT ;
    USE SIGNAL ;
    PORT
      LAYER M5 ;
        RECT  30.816 103.572 30.84 103.656 ;
    END
  END a_d[300]
  PIN a_d[301]
    DIRECTION OUTPUT ;
    USE SIGNAL ;
    PORT
      LAYER M5 ;
        RECT  30.912 103.572 30.936 103.656 ;
    END
  END a_d[301]
  PIN a_d[302]
    DIRECTION OUTPUT ;
    USE SIGNAL ;
    PORT
      LAYER M5 ;
        RECT  31.008 103.572 31.032 103.656 ;
    END
  END a_d[302]
  PIN a_d[303]
    DIRECTION OUTPUT ;
    USE SIGNAL ;
    PORT
      LAYER M5 ;
        RECT  31.104 103.572 31.128 103.656 ;
    END
  END a_d[303]
  PIN a_d[304]
    DIRECTION OUTPUT ;
    USE SIGNAL ;
    PORT
      LAYER M5 ;
        RECT  31.2 103.572 31.224 103.656 ;
    END
  END a_d[304]
  PIN a_d[305]
    DIRECTION OUTPUT ;
    USE SIGNAL ;
    PORT
      LAYER M5 ;
        RECT  31.296 103.572 31.32 103.656 ;
    END
  END a_d[305]
  PIN a_d[306]
    DIRECTION OUTPUT ;
    USE SIGNAL ;
    PORT
      LAYER M5 ;
        RECT  31.392 103.572 31.416 103.656 ;
    END
  END a_d[306]
  PIN a_d[307]
    DIRECTION OUTPUT ;
    USE SIGNAL ;
    PORT
      LAYER M5 ;
        RECT  31.488 103.572 31.512 103.656 ;
    END
  END a_d[307]
  PIN a_d[308]
    DIRECTION OUTPUT ;
    USE SIGNAL ;
    PORT
      LAYER M5 ;
        RECT  31.584 103.572 31.608 103.656 ;
    END
  END a_d[308]
  PIN a_d[309]
    DIRECTION OUTPUT ;
    USE SIGNAL ;
    PORT
      LAYER M5 ;
        RECT  31.68 103.572 31.704 103.656 ;
    END
  END a_d[309]
  PIN a_d[30]
    DIRECTION OUTPUT ;
    USE SIGNAL ;
    PORT
      LAYER M5 ;
        RECT  4.368 103.572 4.392 103.656 ;
    END
  END a_d[30]
  PIN a_d[310]
    DIRECTION OUTPUT ;
    USE SIGNAL ;
    PORT
      LAYER M5 ;
        RECT  31.776 103.572 31.8 103.656 ;
    END
  END a_d[310]
  PIN a_d[311]
    DIRECTION OUTPUT ;
    USE SIGNAL ;
    PORT
      LAYER M5 ;
        RECT  31.872 103.572 31.896 103.656 ;
    END
  END a_d[311]
  PIN a_d[312]
    DIRECTION OUTPUT ;
    USE SIGNAL ;
    PORT
      LAYER M5 ;
        RECT  31.968 103.572 31.992 103.656 ;
    END
  END a_d[312]
  PIN a_d[313]
    DIRECTION OUTPUT ;
    USE SIGNAL ;
    PORT
      LAYER M5 ;
        RECT  32.064 103.572 32.088 103.656 ;
    END
  END a_d[313]
  PIN a_d[314]
    DIRECTION OUTPUT ;
    USE SIGNAL ;
    PORT
      LAYER M5 ;
        RECT  32.16 103.572 32.184 103.656 ;
    END
  END a_d[314]
  PIN a_d[315]
    DIRECTION OUTPUT ;
    USE SIGNAL ;
    PORT
      LAYER M5 ;
        RECT  32.256 103.572 32.28 103.656 ;
    END
  END a_d[315]
  PIN a_d[316]
    DIRECTION OUTPUT ;
    USE SIGNAL ;
    PORT
      LAYER M5 ;
        RECT  32.352 103.572 32.376 103.656 ;
    END
  END a_d[316]
  PIN a_d[317]
    DIRECTION OUTPUT ;
    USE SIGNAL ;
    PORT
      LAYER M5 ;
        RECT  32.448 103.572 32.472 103.656 ;
    END
  END a_d[317]
  PIN a_d[318]
    DIRECTION OUTPUT ;
    USE SIGNAL ;
    PORT
      LAYER M5 ;
        RECT  32.544 103.572 32.568 103.656 ;
    END
  END a_d[318]
  PIN a_d[319]
    DIRECTION OUTPUT ;
    USE SIGNAL ;
    PORT
      LAYER M5 ;
        RECT  32.64 103.572 32.664 103.656 ;
    END
  END a_d[319]
  PIN a_d[31]
    DIRECTION OUTPUT ;
    USE SIGNAL ;
    PORT
      LAYER M5 ;
        RECT  4.464 103.572 4.488 103.656 ;
    END
  END a_d[31]
  PIN a_d[320]
    DIRECTION OUTPUT ;
    USE SIGNAL ;
    PORT
      LAYER M5 ;
        RECT  32.736 103.572 32.76 103.656 ;
    END
  END a_d[320]
  PIN a_d[321]
    DIRECTION OUTPUT ;
    USE SIGNAL ;
    PORT
      LAYER M5 ;
        RECT  32.832 103.572 32.856 103.656 ;
    END
  END a_d[321]
  PIN a_d[322]
    DIRECTION OUTPUT ;
    USE SIGNAL ;
    PORT
      LAYER M5 ;
        RECT  32.976 103.572 33 103.656 ;
    END
  END a_d[322]
  PIN a_d[323]
    DIRECTION OUTPUT ;
    USE SIGNAL ;
    PORT
      LAYER M5 ;
        RECT  33.072 103.572 33.096 103.656 ;
    END
  END a_d[323]
  PIN a_d[324]
    DIRECTION OUTPUT ;
    USE SIGNAL ;
    PORT
      LAYER M5 ;
        RECT  33.168 103.572 33.192 103.656 ;
    END
  END a_d[324]
  PIN a_d[325]
    DIRECTION OUTPUT ;
    USE SIGNAL ;
    PORT
      LAYER M5 ;
        RECT  33.264 103.572 33.288 103.656 ;
    END
  END a_d[325]
  PIN a_d[326]
    DIRECTION OUTPUT ;
    USE SIGNAL ;
    PORT
      LAYER M5 ;
        RECT  33.36 103.572 33.384 103.656 ;
    END
  END a_d[326]
  PIN a_d[327]
    DIRECTION OUTPUT ;
    USE SIGNAL ;
    PORT
      LAYER M5 ;
        RECT  33.456 103.572 33.48 103.656 ;
    END
  END a_d[327]
  PIN a_d[328]
    DIRECTION OUTPUT ;
    USE SIGNAL ;
    PORT
      LAYER M5 ;
        RECT  33.552 103.572 33.576 103.656 ;
    END
  END a_d[328]
  PIN a_d[329]
    DIRECTION OUTPUT ;
    USE SIGNAL ;
    PORT
      LAYER M5 ;
        RECT  33.648 103.572 33.672 103.656 ;
    END
  END a_d[329]
  PIN a_d[32]
    DIRECTION OUTPUT ;
    USE SIGNAL ;
    PORT
      LAYER M5 ;
        RECT  4.56 103.572 4.584 103.656 ;
    END
  END a_d[32]
  PIN a_d[330]
    DIRECTION OUTPUT ;
    USE SIGNAL ;
    PORT
      LAYER M5 ;
        RECT  33.744 103.572 33.768 103.656 ;
    END
  END a_d[330]
  PIN a_d[331]
    DIRECTION OUTPUT ;
    USE SIGNAL ;
    PORT
      LAYER M5 ;
        RECT  33.84 103.572 33.864 103.656 ;
    END
  END a_d[331]
  PIN a_d[332]
    DIRECTION OUTPUT ;
    USE SIGNAL ;
    PORT
      LAYER M5 ;
        RECT  33.936 103.572 33.96 103.656 ;
    END
  END a_d[332]
  PIN a_d[333]
    DIRECTION OUTPUT ;
    USE SIGNAL ;
    PORT
      LAYER M5 ;
        RECT  34.032 103.572 34.056 103.656 ;
    END
  END a_d[333]
  PIN a_d[334]
    DIRECTION OUTPUT ;
    USE SIGNAL ;
    PORT
      LAYER M5 ;
        RECT  34.128 103.572 34.152 103.656 ;
    END
  END a_d[334]
  PIN a_d[335]
    DIRECTION OUTPUT ;
    USE SIGNAL ;
    PORT
      LAYER M5 ;
        RECT  34.224 103.572 34.248 103.656 ;
    END
  END a_d[335]
  PIN a_d[336]
    DIRECTION OUTPUT ;
    USE SIGNAL ;
    PORT
      LAYER M5 ;
        RECT  34.32 103.572 34.344 103.656 ;
    END
  END a_d[336]
  PIN a_d[337]
    DIRECTION OUTPUT ;
    USE SIGNAL ;
    PORT
      LAYER M5 ;
        RECT  34.416 103.572 34.44 103.656 ;
    END
  END a_d[337]
  PIN a_d[338]
    DIRECTION OUTPUT ;
    USE SIGNAL ;
    PORT
      LAYER M5 ;
        RECT  34.512 103.572 34.536 103.656 ;
    END
  END a_d[338]
  PIN a_d[339]
    DIRECTION OUTPUT ;
    USE SIGNAL ;
    PORT
      LAYER M5 ;
        RECT  34.608 103.572 34.632 103.656 ;
    END
  END a_d[339]
  PIN a_d[33]
    DIRECTION OUTPUT ;
    USE SIGNAL ;
    PORT
      LAYER M5 ;
        RECT  4.656 103.572 4.68 103.656 ;
    END
  END a_d[33]
  PIN a_d[340]
    DIRECTION OUTPUT ;
    USE SIGNAL ;
    PORT
      LAYER M5 ;
        RECT  34.704 103.572 34.728 103.656 ;
    END
  END a_d[340]
  PIN a_d[341]
    DIRECTION OUTPUT ;
    USE SIGNAL ;
    PORT
      LAYER M5 ;
        RECT  34.8 103.572 34.824 103.656 ;
    END
  END a_d[341]
  PIN a_d[342]
    DIRECTION OUTPUT ;
    USE SIGNAL ;
    PORT
      LAYER M5 ;
        RECT  34.896 103.572 34.92 103.656 ;
    END
  END a_d[342]
  PIN a_d[343]
    DIRECTION OUTPUT ;
    USE SIGNAL ;
    PORT
      LAYER M5 ;
        RECT  34.992 103.572 35.016 103.656 ;
    END
  END a_d[343]
  PIN a_d[344]
    DIRECTION OUTPUT ;
    USE SIGNAL ;
    PORT
      LAYER M5 ;
        RECT  35.088 103.572 35.112 103.656 ;
    END
  END a_d[344]
  PIN a_d[345]
    DIRECTION OUTPUT ;
    USE SIGNAL ;
    PORT
      LAYER M5 ;
        RECT  35.184 103.572 35.208 103.656 ;
    END
  END a_d[345]
  PIN a_d[346]
    DIRECTION OUTPUT ;
    USE SIGNAL ;
    PORT
      LAYER M5 ;
        RECT  35.28 103.572 35.304 103.656 ;
    END
  END a_d[346]
  PIN a_d[347]
    DIRECTION OUTPUT ;
    USE SIGNAL ;
    PORT
      LAYER M5 ;
        RECT  35.376 103.572 35.4 103.656 ;
    END
  END a_d[347]
  PIN a_d[348]
    DIRECTION OUTPUT ;
    USE SIGNAL ;
    PORT
      LAYER M5 ;
        RECT  35.52 103.572 35.544 103.656 ;
    END
  END a_d[348]
  PIN a_d[349]
    DIRECTION OUTPUT ;
    USE SIGNAL ;
    PORT
      LAYER M5 ;
        RECT  35.616 103.572 35.64 103.656 ;
    END
  END a_d[349]
  PIN a_d[34]
    DIRECTION OUTPUT ;
    USE SIGNAL ;
    PORT
      LAYER M5 ;
        RECT  4.752 103.572 4.776 103.656 ;
    END
  END a_d[34]
  PIN a_d[350]
    DIRECTION OUTPUT ;
    USE SIGNAL ;
    PORT
      LAYER M5 ;
        RECT  35.712 103.572 35.736 103.656 ;
    END
  END a_d[350]
  PIN a_d[351]
    DIRECTION OUTPUT ;
    USE SIGNAL ;
    PORT
      LAYER M5 ;
        RECT  35.808 103.572 35.832 103.656 ;
    END
  END a_d[351]
  PIN a_d[352]
    DIRECTION OUTPUT ;
    USE SIGNAL ;
    PORT
      LAYER M5 ;
        RECT  35.904 103.572 35.928 103.656 ;
    END
  END a_d[352]
  PIN a_d[353]
    DIRECTION OUTPUT ;
    USE SIGNAL ;
    PORT
      LAYER M5 ;
        RECT  36 103.572 36.024 103.656 ;
    END
  END a_d[353]
  PIN a_d[354]
    DIRECTION OUTPUT ;
    USE SIGNAL ;
    PORT
      LAYER M5 ;
        RECT  36.096 103.572 36.12 103.656 ;
    END
  END a_d[354]
  PIN a_d[355]
    DIRECTION OUTPUT ;
    USE SIGNAL ;
    PORT
      LAYER M5 ;
        RECT  36.192 103.572 36.216 103.656 ;
    END
  END a_d[355]
  PIN a_d[356]
    DIRECTION OUTPUT ;
    USE SIGNAL ;
    PORT
      LAYER M5 ;
        RECT  36.288 103.572 36.312 103.656 ;
    END
  END a_d[356]
  PIN a_d[357]
    DIRECTION OUTPUT ;
    USE SIGNAL ;
    PORT
      LAYER M5 ;
        RECT  36.384 103.572 36.408 103.656 ;
    END
  END a_d[357]
  PIN a_d[358]
    DIRECTION OUTPUT ;
    USE SIGNAL ;
    PORT
      LAYER M5 ;
        RECT  36.48 103.572 36.504 103.656 ;
    END
  END a_d[358]
  PIN a_d[359]
    DIRECTION OUTPUT ;
    USE SIGNAL ;
    PORT
      LAYER M5 ;
        RECT  36.576 103.572 36.6 103.656 ;
    END
  END a_d[359]
  PIN a_d[35]
    DIRECTION OUTPUT ;
    USE SIGNAL ;
    PORT
      LAYER M5 ;
        RECT  4.848 103.572 4.872 103.656 ;
    END
  END a_d[35]
  PIN a_d[360]
    DIRECTION OUTPUT ;
    USE SIGNAL ;
    PORT
      LAYER M5 ;
        RECT  36.672 103.572 36.696 103.656 ;
    END
  END a_d[360]
  PIN a_d[361]
    DIRECTION OUTPUT ;
    USE SIGNAL ;
    PORT
      LAYER M5 ;
        RECT  36.768 103.572 36.792 103.656 ;
    END
  END a_d[361]
  PIN a_d[362]
    DIRECTION OUTPUT ;
    USE SIGNAL ;
    PORT
      LAYER M5 ;
        RECT  36.864 103.572 36.888 103.656 ;
    END
  END a_d[362]
  PIN a_d[363]
    DIRECTION OUTPUT ;
    USE SIGNAL ;
    PORT
      LAYER M5 ;
        RECT  36.96 103.572 36.984 103.656 ;
    END
  END a_d[363]
  PIN a_d[364]
    DIRECTION OUTPUT ;
    USE SIGNAL ;
    PORT
      LAYER M5 ;
        RECT  37.056 103.572 37.08 103.656 ;
    END
  END a_d[364]
  PIN a_d[365]
    DIRECTION OUTPUT ;
    USE SIGNAL ;
    PORT
      LAYER M5 ;
        RECT  37.152 103.572 37.176 103.656 ;
    END
  END a_d[365]
  PIN a_d[366]
    DIRECTION OUTPUT ;
    USE SIGNAL ;
    PORT
      LAYER M5 ;
        RECT  37.248 103.572 37.272 103.656 ;
    END
  END a_d[366]
  PIN a_d[367]
    DIRECTION OUTPUT ;
    USE SIGNAL ;
    PORT
      LAYER M5 ;
        RECT  37.344 103.572 37.368 103.656 ;
    END
  END a_d[367]
  PIN a_d[368]
    DIRECTION OUTPUT ;
    USE SIGNAL ;
    PORT
      LAYER M5 ;
        RECT  37.44 103.572 37.464 103.656 ;
    END
  END a_d[368]
  PIN a_d[369]
    DIRECTION OUTPUT ;
    USE SIGNAL ;
    PORT
      LAYER M5 ;
        RECT  37.536 103.572 37.56 103.656 ;
    END
  END a_d[369]
  PIN a_d[36]
    DIRECTION OUTPUT ;
    USE SIGNAL ;
    PORT
      LAYER M5 ;
        RECT  4.944 103.572 4.968 103.656 ;
    END
  END a_d[36]
  PIN a_d[370]
    DIRECTION OUTPUT ;
    USE SIGNAL ;
    PORT
      LAYER M5 ;
        RECT  37.632 103.572 37.656 103.656 ;
    END
  END a_d[370]
  PIN a_d[371]
    DIRECTION OUTPUT ;
    USE SIGNAL ;
    PORT
      LAYER M5 ;
        RECT  37.728 103.572 37.752 103.656 ;
    END
  END a_d[371]
  PIN a_d[372]
    DIRECTION OUTPUT ;
    USE SIGNAL ;
    PORT
      LAYER M5 ;
        RECT  37.824 103.572 37.848 103.656 ;
    END
  END a_d[372]
  PIN a_d[373]
    DIRECTION OUTPUT ;
    USE SIGNAL ;
    PORT
      LAYER M5 ;
        RECT  37.92 103.572 37.944 103.656 ;
    END
  END a_d[373]
  PIN a_d[374]
    DIRECTION OUTPUT ;
    USE SIGNAL ;
    PORT
      LAYER M5 ;
        RECT  38.064 103.572 38.088 103.656 ;
    END
  END a_d[374]
  PIN a_d[375]
    DIRECTION OUTPUT ;
    USE SIGNAL ;
    PORT
      LAYER M5 ;
        RECT  38.16 103.572 38.184 103.656 ;
    END
  END a_d[375]
  PIN a_d[376]
    DIRECTION OUTPUT ;
    USE SIGNAL ;
    PORT
      LAYER M5 ;
        RECT  38.256 103.572 38.28 103.656 ;
    END
  END a_d[376]
  PIN a_d[377]
    DIRECTION OUTPUT ;
    USE SIGNAL ;
    PORT
      LAYER M5 ;
        RECT  38.352 103.572 38.376 103.656 ;
    END
  END a_d[377]
  PIN a_d[378]
    DIRECTION OUTPUT ;
    USE SIGNAL ;
    PORT
      LAYER M5 ;
        RECT  38.448 103.572 38.472 103.656 ;
    END
  END a_d[378]
  PIN a_d[379]
    DIRECTION OUTPUT ;
    USE SIGNAL ;
    PORT
      LAYER M5 ;
        RECT  38.544 103.572 38.568 103.656 ;
    END
  END a_d[379]
  PIN a_d[37]
    DIRECTION OUTPUT ;
    USE SIGNAL ;
    PORT
      LAYER M5 ;
        RECT  5.04 103.572 5.064 103.656 ;
    END
  END a_d[37]
  PIN a_d[380]
    DIRECTION OUTPUT ;
    USE SIGNAL ;
    PORT
      LAYER M5 ;
        RECT  38.64 103.572 38.664 103.656 ;
    END
  END a_d[380]
  PIN a_d[381]
    DIRECTION OUTPUT ;
    USE SIGNAL ;
    PORT
      LAYER M5 ;
        RECT  38.736 103.572 38.76 103.656 ;
    END
  END a_d[381]
  PIN a_d[382]
    DIRECTION OUTPUT ;
    USE SIGNAL ;
    PORT
      LAYER M5 ;
        RECT  38.832 103.572 38.856 103.656 ;
    END
  END a_d[382]
  PIN a_d[383]
    DIRECTION OUTPUT ;
    USE SIGNAL ;
    PORT
      LAYER M5 ;
        RECT  38.928 103.572 38.952 103.656 ;
    END
  END a_d[383]
  PIN a_d[384]
    DIRECTION OUTPUT ;
    USE SIGNAL ;
    PORT
      LAYER M5 ;
        RECT  39.024 103.572 39.048 103.656 ;
    END
  END a_d[384]
  PIN a_d[385]
    DIRECTION OUTPUT ;
    USE SIGNAL ;
    PORT
      LAYER M5 ;
        RECT  39.12 103.572 39.144 103.656 ;
    END
  END a_d[385]
  PIN a_d[386]
    DIRECTION OUTPUT ;
    USE SIGNAL ;
    PORT
      LAYER M5 ;
        RECT  39.216 103.572 39.24 103.656 ;
    END
  END a_d[386]
  PIN a_d[387]
    DIRECTION OUTPUT ;
    USE SIGNAL ;
    PORT
      LAYER M5 ;
        RECT  39.312 103.572 39.336 103.656 ;
    END
  END a_d[387]
  PIN a_d[388]
    DIRECTION OUTPUT ;
    USE SIGNAL ;
    PORT
      LAYER M5 ;
        RECT  39.408 103.572 39.432 103.656 ;
    END
  END a_d[388]
  PIN a_d[389]
    DIRECTION OUTPUT ;
    USE SIGNAL ;
    PORT
      LAYER M5 ;
        RECT  39.504 103.572 39.528 103.656 ;
    END
  END a_d[389]
  PIN a_d[38]
    DIRECTION OUTPUT ;
    USE SIGNAL ;
    PORT
      LAYER M5 ;
        RECT  5.184 103.572 5.208 103.656 ;
    END
  END a_d[38]
  PIN a_d[390]
    DIRECTION OUTPUT ;
    USE SIGNAL ;
    PORT
      LAYER M5 ;
        RECT  39.6 103.572 39.624 103.656 ;
    END
  END a_d[390]
  PIN a_d[391]
    DIRECTION OUTPUT ;
    USE SIGNAL ;
    PORT
      LAYER M5 ;
        RECT  39.696 103.572 39.72 103.656 ;
    END
  END a_d[391]
  PIN a_d[392]
    DIRECTION OUTPUT ;
    USE SIGNAL ;
    PORT
      LAYER M5 ;
        RECT  39.792 103.572 39.816 103.656 ;
    END
  END a_d[392]
  PIN a_d[393]
    DIRECTION OUTPUT ;
    USE SIGNAL ;
    PORT
      LAYER M5 ;
        RECT  39.888 103.572 39.912 103.656 ;
    END
  END a_d[393]
  PIN a_d[394]
    DIRECTION OUTPUT ;
    USE SIGNAL ;
    PORT
      LAYER M5 ;
        RECT  39.984 103.572 40.008 103.656 ;
    END
  END a_d[394]
  PIN a_d[395]
    DIRECTION OUTPUT ;
    USE SIGNAL ;
    PORT
      LAYER M5 ;
        RECT  40.08 103.572 40.104 103.656 ;
    END
  END a_d[395]
  PIN a_d[396]
    DIRECTION OUTPUT ;
    USE SIGNAL ;
    PORT
      LAYER M5 ;
        RECT  40.176 103.572 40.2 103.656 ;
    END
  END a_d[396]
  PIN a_d[397]
    DIRECTION OUTPUT ;
    USE SIGNAL ;
    PORT
      LAYER M5 ;
        RECT  40.272 103.572 40.296 103.656 ;
    END
  END a_d[397]
  PIN a_d[398]
    DIRECTION OUTPUT ;
    USE SIGNAL ;
    PORT
      LAYER M5 ;
        RECT  40.368 103.572 40.392 103.656 ;
    END
  END a_d[398]
  PIN a_d[399]
    DIRECTION OUTPUT ;
    USE SIGNAL ;
    PORT
      LAYER M5 ;
        RECT  40.464 103.572 40.488 103.656 ;
    END
  END a_d[399]
  PIN a_d[39]
    DIRECTION OUTPUT ;
    USE SIGNAL ;
    PORT
      LAYER M5 ;
        RECT  5.28 103.572 5.304 103.656 ;
    END
  END a_d[39]
  PIN a_d[3]
    DIRECTION OUTPUT ;
    USE SIGNAL ;
    PORT
      LAYER M5 ;
        RECT  1.728 103.572 1.752 103.656 ;
    END
  END a_d[3]
  PIN a_d[400]
    DIRECTION OUTPUT ;
    USE SIGNAL ;
    PORT
      LAYER M5 ;
        RECT  40.608 103.572 40.632 103.656 ;
    END
  END a_d[400]
  PIN a_d[401]
    DIRECTION OUTPUT ;
    USE SIGNAL ;
    PORT
      LAYER M5 ;
        RECT  40.704 103.572 40.728 103.656 ;
    END
  END a_d[401]
  PIN a_d[402]
    DIRECTION OUTPUT ;
    USE SIGNAL ;
    PORT
      LAYER M5 ;
        RECT  40.8 103.572 40.824 103.656 ;
    END
  END a_d[402]
  PIN a_d[403]
    DIRECTION OUTPUT ;
    USE SIGNAL ;
    PORT
      LAYER M5 ;
        RECT  40.896 103.572 40.92 103.656 ;
    END
  END a_d[403]
  PIN a_d[404]
    DIRECTION OUTPUT ;
    USE SIGNAL ;
    PORT
      LAYER M5 ;
        RECT  40.992 103.572 41.016 103.656 ;
    END
  END a_d[404]
  PIN a_d[405]
    DIRECTION OUTPUT ;
    USE SIGNAL ;
    PORT
      LAYER M5 ;
        RECT  41.088 103.572 41.112 103.656 ;
    END
  END a_d[405]
  PIN a_d[406]
    DIRECTION OUTPUT ;
    USE SIGNAL ;
    PORT
      LAYER M5 ;
        RECT  41.184 103.572 41.208 103.656 ;
    END
  END a_d[406]
  PIN a_d[407]
    DIRECTION OUTPUT ;
    USE SIGNAL ;
    PORT
      LAYER M5 ;
        RECT  41.28 103.572 41.304 103.656 ;
    END
  END a_d[407]
  PIN a_d[408]
    DIRECTION OUTPUT ;
    USE SIGNAL ;
    PORT
      LAYER M5 ;
        RECT  41.376 103.572 41.4 103.656 ;
    END
  END a_d[408]
  PIN a_d[409]
    DIRECTION OUTPUT ;
    USE SIGNAL ;
    PORT
      LAYER M5 ;
        RECT  41.472 103.572 41.496 103.656 ;
    END
  END a_d[409]
  PIN a_d[40]
    DIRECTION OUTPUT ;
    USE SIGNAL ;
    PORT
      LAYER M5 ;
        RECT  5.376 103.572 5.4 103.656 ;
    END
  END a_d[40]
  PIN a_d[410]
    DIRECTION OUTPUT ;
    USE SIGNAL ;
    PORT
      LAYER M5 ;
        RECT  41.568 103.572 41.592 103.656 ;
    END
  END a_d[410]
  PIN a_d[411]
    DIRECTION OUTPUT ;
    USE SIGNAL ;
    PORT
      LAYER M5 ;
        RECT  41.664 103.572 41.688 103.656 ;
    END
  END a_d[411]
  PIN a_d[412]
    DIRECTION OUTPUT ;
    USE SIGNAL ;
    PORT
      LAYER M5 ;
        RECT  41.76 103.572 41.784 103.656 ;
    END
  END a_d[412]
  PIN a_d[413]
    DIRECTION OUTPUT ;
    USE SIGNAL ;
    PORT
      LAYER M5 ;
        RECT  41.856 103.572 41.88 103.656 ;
    END
  END a_d[413]
  PIN a_d[414]
    DIRECTION OUTPUT ;
    USE SIGNAL ;
    PORT
      LAYER M5 ;
        RECT  41.952 103.572 41.976 103.656 ;
    END
  END a_d[414]
  PIN a_d[415]
    DIRECTION OUTPUT ;
    USE SIGNAL ;
    PORT
      LAYER M5 ;
        RECT  42.048 103.572 42.072 103.656 ;
    END
  END a_d[415]
  PIN a_d[416]
    DIRECTION OUTPUT ;
    USE SIGNAL ;
    PORT
      LAYER M5 ;
        RECT  42.144 103.572 42.168 103.656 ;
    END
  END a_d[416]
  PIN a_d[417]
    DIRECTION OUTPUT ;
    USE SIGNAL ;
    PORT
      LAYER M5 ;
        RECT  42.24 103.572 42.264 103.656 ;
    END
  END a_d[417]
  PIN a_d[418]
    DIRECTION OUTPUT ;
    USE SIGNAL ;
    PORT
      LAYER M5 ;
        RECT  42.336 103.572 42.36 103.656 ;
    END
  END a_d[418]
  PIN a_d[419]
    DIRECTION OUTPUT ;
    USE SIGNAL ;
    PORT
      LAYER M5 ;
        RECT  42.432 103.572 42.456 103.656 ;
    END
  END a_d[419]
  PIN a_d[41]
    DIRECTION OUTPUT ;
    USE SIGNAL ;
    PORT
      LAYER M5 ;
        RECT  5.472 103.572 5.496 103.656 ;
    END
  END a_d[41]
  PIN a_d[420]
    DIRECTION OUTPUT ;
    USE SIGNAL ;
    PORT
      LAYER M5 ;
        RECT  42.528 103.572 42.552 103.656 ;
    END
  END a_d[420]
  PIN a_d[421]
    DIRECTION OUTPUT ;
    USE SIGNAL ;
    PORT
      LAYER M5 ;
        RECT  42.624 103.572 42.648 103.656 ;
    END
  END a_d[421]
  PIN a_d[422]
    DIRECTION OUTPUT ;
    USE SIGNAL ;
    PORT
      LAYER M5 ;
        RECT  42.72 103.572 42.744 103.656 ;
    END
  END a_d[422]
  PIN a_d[423]
    DIRECTION OUTPUT ;
    USE SIGNAL ;
    PORT
      LAYER M5 ;
        RECT  42.816 103.572 42.84 103.656 ;
    END
  END a_d[423]
  PIN a_d[424]
    DIRECTION OUTPUT ;
    USE SIGNAL ;
    PORT
      LAYER M5 ;
        RECT  42.912 103.572 42.936 103.656 ;
    END
  END a_d[424]
  PIN a_d[425]
    DIRECTION OUTPUT ;
    USE SIGNAL ;
    PORT
      LAYER M5 ;
        RECT  43.056 103.572 43.08 103.656 ;
    END
  END a_d[425]
  PIN a_d[426]
    DIRECTION OUTPUT ;
    USE SIGNAL ;
    PORT
      LAYER M5 ;
        RECT  43.152 103.572 43.176 103.656 ;
    END
  END a_d[426]
  PIN a_d[427]
    DIRECTION OUTPUT ;
    USE SIGNAL ;
    PORT
      LAYER M5 ;
        RECT  43.248 103.572 43.272 103.656 ;
    END
  END a_d[427]
  PIN a_d[428]
    DIRECTION OUTPUT ;
    USE SIGNAL ;
    PORT
      LAYER M5 ;
        RECT  43.344 103.572 43.368 103.656 ;
    END
  END a_d[428]
  PIN a_d[429]
    DIRECTION OUTPUT ;
    USE SIGNAL ;
    PORT
      LAYER M5 ;
        RECT  43.44 103.572 43.464 103.656 ;
    END
  END a_d[429]
  PIN a_d[42]
    DIRECTION OUTPUT ;
    USE SIGNAL ;
    PORT
      LAYER M5 ;
        RECT  5.568 103.572 5.592 103.656 ;
    END
  END a_d[42]
  PIN a_d[430]
    DIRECTION OUTPUT ;
    USE SIGNAL ;
    PORT
      LAYER M5 ;
        RECT  43.536 103.572 43.56 103.656 ;
    END
  END a_d[430]
  PIN a_d[431]
    DIRECTION OUTPUT ;
    USE SIGNAL ;
    PORT
      LAYER M5 ;
        RECT  43.632 103.572 43.656 103.656 ;
    END
  END a_d[431]
  PIN a_d[432]
    DIRECTION OUTPUT ;
    USE SIGNAL ;
    PORT
      LAYER M5 ;
        RECT  43.728 103.572 43.752 103.656 ;
    END
  END a_d[432]
  PIN a_d[433]
    DIRECTION OUTPUT ;
    USE SIGNAL ;
    PORT
      LAYER M5 ;
        RECT  43.824 103.572 43.848 103.656 ;
    END
  END a_d[433]
  PIN a_d[434]
    DIRECTION OUTPUT ;
    USE SIGNAL ;
    PORT
      LAYER M5 ;
        RECT  43.92 103.572 43.944 103.656 ;
    END
  END a_d[434]
  PIN a_d[435]
    DIRECTION OUTPUT ;
    USE SIGNAL ;
    PORT
      LAYER M5 ;
        RECT  44.016 103.572 44.04 103.656 ;
    END
  END a_d[435]
  PIN a_d[436]
    DIRECTION OUTPUT ;
    USE SIGNAL ;
    PORT
      LAYER M5 ;
        RECT  44.112 103.572 44.136 103.656 ;
    END
  END a_d[436]
  PIN a_d[437]
    DIRECTION OUTPUT ;
    USE SIGNAL ;
    PORT
      LAYER M5 ;
        RECT  44.208 103.572 44.232 103.656 ;
    END
  END a_d[437]
  PIN a_d[438]
    DIRECTION OUTPUT ;
    USE SIGNAL ;
    PORT
      LAYER M5 ;
        RECT  44.304 103.572 44.328 103.656 ;
    END
  END a_d[438]
  PIN a_d[439]
    DIRECTION OUTPUT ;
    USE SIGNAL ;
    PORT
      LAYER M5 ;
        RECT  44.4 103.572 44.424 103.656 ;
    END
  END a_d[439]
  PIN a_d[43]
    DIRECTION OUTPUT ;
    USE SIGNAL ;
    PORT
      LAYER M5 ;
        RECT  5.664 103.572 5.688 103.656 ;
    END
  END a_d[43]
  PIN a_d[440]
    DIRECTION OUTPUT ;
    USE SIGNAL ;
    PORT
      LAYER M5 ;
        RECT  44.496 103.572 44.52 103.656 ;
    END
  END a_d[440]
  PIN a_d[441]
    DIRECTION OUTPUT ;
    USE SIGNAL ;
    PORT
      LAYER M5 ;
        RECT  44.592 103.572 44.616 103.656 ;
    END
  END a_d[441]
  PIN a_d[442]
    DIRECTION OUTPUT ;
    USE SIGNAL ;
    PORT
      LAYER M5 ;
        RECT  44.688 103.572 44.712 103.656 ;
    END
  END a_d[442]
  PIN a_d[443]
    DIRECTION OUTPUT ;
    USE SIGNAL ;
    PORT
      LAYER M5 ;
        RECT  44.784 103.572 44.808 103.656 ;
    END
  END a_d[443]
  PIN a_d[444]
    DIRECTION OUTPUT ;
    USE SIGNAL ;
    PORT
      LAYER M5 ;
        RECT  44.88 103.572 44.904 103.656 ;
    END
  END a_d[444]
  PIN a_d[445]
    DIRECTION OUTPUT ;
    USE SIGNAL ;
    PORT
      LAYER M5 ;
        RECT  44.976 103.572 45 103.656 ;
    END
  END a_d[445]
  PIN a_d[446]
    DIRECTION OUTPUT ;
    USE SIGNAL ;
    PORT
      LAYER M5 ;
        RECT  45.072 103.572 45.096 103.656 ;
    END
  END a_d[446]
  PIN a_d[447]
    DIRECTION OUTPUT ;
    USE SIGNAL ;
    PORT
      LAYER M5 ;
        RECT  45.168 103.572 45.192 103.656 ;
    END
  END a_d[447]
  PIN a_d[448]
    DIRECTION OUTPUT ;
    USE SIGNAL ;
    PORT
      LAYER M5 ;
        RECT  45.264 103.572 45.288 103.656 ;
    END
  END a_d[448]
  PIN a_d[449]
    DIRECTION OUTPUT ;
    USE SIGNAL ;
    PORT
      LAYER M5 ;
        RECT  45.36 103.572 45.384 103.656 ;
    END
  END a_d[449]
  PIN a_d[44]
    DIRECTION OUTPUT ;
    USE SIGNAL ;
    PORT
      LAYER M5 ;
        RECT  5.76 103.572 5.784 103.656 ;
    END
  END a_d[44]
  PIN a_d[450]
    DIRECTION OUTPUT ;
    USE SIGNAL ;
    PORT
      LAYER M5 ;
        RECT  45.456 103.572 45.48 103.656 ;
    END
  END a_d[450]
  PIN a_d[451]
    DIRECTION OUTPUT ;
    USE SIGNAL ;
    PORT
      LAYER M5 ;
        RECT  45.6 103.572 45.624 103.656 ;
    END
  END a_d[451]
  PIN a_d[452]
    DIRECTION OUTPUT ;
    USE SIGNAL ;
    PORT
      LAYER M5 ;
        RECT  45.696 103.572 45.72 103.656 ;
    END
  END a_d[452]
  PIN a_d[453]
    DIRECTION OUTPUT ;
    USE SIGNAL ;
    PORT
      LAYER M5 ;
        RECT  45.792 103.572 45.816 103.656 ;
    END
  END a_d[453]
  PIN a_d[454]
    DIRECTION OUTPUT ;
    USE SIGNAL ;
    PORT
      LAYER M5 ;
        RECT  45.888 103.572 45.912 103.656 ;
    END
  END a_d[454]
  PIN a_d[455]
    DIRECTION OUTPUT ;
    USE SIGNAL ;
    PORT
      LAYER M5 ;
        RECT  45.984 103.572 46.008 103.656 ;
    END
  END a_d[455]
  PIN a_d[456]
    DIRECTION OUTPUT ;
    USE SIGNAL ;
    PORT
      LAYER M5 ;
        RECT  46.08 103.572 46.104 103.656 ;
    END
  END a_d[456]
  PIN a_d[457]
    DIRECTION OUTPUT ;
    USE SIGNAL ;
    PORT
      LAYER M5 ;
        RECT  46.176 103.572 46.2 103.656 ;
    END
  END a_d[457]
  PIN a_d[458]
    DIRECTION OUTPUT ;
    USE SIGNAL ;
    PORT
      LAYER M5 ;
        RECT  46.272 103.572 46.296 103.656 ;
    END
  END a_d[458]
  PIN a_d[459]
    DIRECTION OUTPUT ;
    USE SIGNAL ;
    PORT
      LAYER M5 ;
        RECT  46.368 103.572 46.392 103.656 ;
    END
  END a_d[459]
  PIN a_d[45]
    DIRECTION OUTPUT ;
    USE SIGNAL ;
    PORT
      LAYER M5 ;
        RECT  5.856 103.572 5.88 103.656 ;
    END
  END a_d[45]
  PIN a_d[460]
    DIRECTION OUTPUT ;
    USE SIGNAL ;
    PORT
      LAYER M5 ;
        RECT  46.464 103.572 46.488 103.656 ;
    END
  END a_d[460]
  PIN a_d[461]
    DIRECTION OUTPUT ;
    USE SIGNAL ;
    PORT
      LAYER M5 ;
        RECT  46.56 103.572 46.584 103.656 ;
    END
  END a_d[461]
  PIN a_d[462]
    DIRECTION OUTPUT ;
    USE SIGNAL ;
    PORT
      LAYER M5 ;
        RECT  46.656 103.572 46.68 103.656 ;
    END
  END a_d[462]
  PIN a_d[463]
    DIRECTION OUTPUT ;
    USE SIGNAL ;
    PORT
      LAYER M5 ;
        RECT  46.752 103.572 46.776 103.656 ;
    END
  END a_d[463]
  PIN a_d[464]
    DIRECTION OUTPUT ;
    USE SIGNAL ;
    PORT
      LAYER M5 ;
        RECT  46.848 103.572 46.872 103.656 ;
    END
  END a_d[464]
  PIN a_d[465]
    DIRECTION OUTPUT ;
    USE SIGNAL ;
    PORT
      LAYER M5 ;
        RECT  46.944 103.572 46.968 103.656 ;
    END
  END a_d[465]
  PIN a_d[466]
    DIRECTION OUTPUT ;
    USE SIGNAL ;
    PORT
      LAYER M5 ;
        RECT  47.04 103.572 47.064 103.656 ;
    END
  END a_d[466]
  PIN a_d[467]
    DIRECTION OUTPUT ;
    USE SIGNAL ;
    PORT
      LAYER M5 ;
        RECT  47.136 103.572 47.16 103.656 ;
    END
  END a_d[467]
  PIN a_d[468]
    DIRECTION OUTPUT ;
    USE SIGNAL ;
    PORT
      LAYER M5 ;
        RECT  47.232 103.572 47.256 103.656 ;
    END
  END a_d[468]
  PIN a_d[469]
    DIRECTION OUTPUT ;
    USE SIGNAL ;
    PORT
      LAYER M5 ;
        RECT  47.328 103.572 47.352 103.656 ;
    END
  END a_d[469]
  PIN a_d[46]
    DIRECTION OUTPUT ;
    USE SIGNAL ;
    PORT
      LAYER M5 ;
        RECT  5.952 103.572 5.976 103.656 ;
    END
  END a_d[46]
  PIN a_d[470]
    DIRECTION OUTPUT ;
    USE SIGNAL ;
    PORT
      LAYER M5 ;
        RECT  47.424 103.572 47.448 103.656 ;
    END
  END a_d[470]
  PIN a_d[471]
    DIRECTION OUTPUT ;
    USE SIGNAL ;
    PORT
      LAYER M5 ;
        RECT  47.52 103.572 47.544 103.656 ;
    END
  END a_d[471]
  PIN a_d[472]
    DIRECTION OUTPUT ;
    USE SIGNAL ;
    PORT
      LAYER M5 ;
        RECT  47.616 103.572 47.64 103.656 ;
    END
  END a_d[472]
  PIN a_d[473]
    DIRECTION OUTPUT ;
    USE SIGNAL ;
    PORT
      LAYER M5 ;
        RECT  47.712 103.572 47.736 103.656 ;
    END
  END a_d[473]
  PIN a_d[474]
    DIRECTION OUTPUT ;
    USE SIGNAL ;
    PORT
      LAYER M5 ;
        RECT  47.808 103.572 47.832 103.656 ;
    END
  END a_d[474]
  PIN a_d[475]
    DIRECTION OUTPUT ;
    USE SIGNAL ;
    PORT
      LAYER M5 ;
        RECT  47.904 103.572 47.928 103.656 ;
    END
  END a_d[475]
  PIN a_d[476]
    DIRECTION OUTPUT ;
    USE SIGNAL ;
    PORT
      LAYER M5 ;
        RECT  48 103.572 48.024 103.656 ;
    END
  END a_d[476]
  PIN a_d[477]
    DIRECTION OUTPUT ;
    USE SIGNAL ;
    PORT
      LAYER M5 ;
        RECT  48.144 103.572 48.168 103.656 ;
    END
  END a_d[477]
  PIN a_d[478]
    DIRECTION OUTPUT ;
    USE SIGNAL ;
    PORT
      LAYER M5 ;
        RECT  48.24 103.572 48.264 103.656 ;
    END
  END a_d[478]
  PIN a_d[479]
    DIRECTION OUTPUT ;
    USE SIGNAL ;
    PORT
      LAYER M5 ;
        RECT  48.336 103.572 48.36 103.656 ;
    END
  END a_d[479]
  PIN a_d[47]
    DIRECTION OUTPUT ;
    USE SIGNAL ;
    PORT
      LAYER M5 ;
        RECT  6.048 103.572 6.072 103.656 ;
    END
  END a_d[47]
  PIN a_d[480]
    DIRECTION OUTPUT ;
    USE SIGNAL ;
    PORT
      LAYER M5 ;
        RECT  48.432 103.572 48.456 103.656 ;
    END
  END a_d[480]
  PIN a_d[481]
    DIRECTION OUTPUT ;
    USE SIGNAL ;
    PORT
      LAYER M5 ;
        RECT  48.528 103.572 48.552 103.656 ;
    END
  END a_d[481]
  PIN a_d[482]
    DIRECTION OUTPUT ;
    USE SIGNAL ;
    PORT
      LAYER M5 ;
        RECT  48.624 103.572 48.648 103.656 ;
    END
  END a_d[482]
  PIN a_d[483]
    DIRECTION OUTPUT ;
    USE SIGNAL ;
    PORT
      LAYER M5 ;
        RECT  48.72 103.572 48.744 103.656 ;
    END
  END a_d[483]
  PIN a_d[484]
    DIRECTION OUTPUT ;
    USE SIGNAL ;
    PORT
      LAYER M5 ;
        RECT  48.816 103.572 48.84 103.656 ;
    END
  END a_d[484]
  PIN a_d[485]
    DIRECTION OUTPUT ;
    USE SIGNAL ;
    PORT
      LAYER M5 ;
        RECT  48.912 103.572 48.936 103.656 ;
    END
  END a_d[485]
  PIN a_d[486]
    DIRECTION OUTPUT ;
    USE SIGNAL ;
    PORT
      LAYER M5 ;
        RECT  49.008 103.572 49.032 103.656 ;
    END
  END a_d[486]
  PIN a_d[487]
    DIRECTION OUTPUT ;
    USE SIGNAL ;
    PORT
      LAYER M5 ;
        RECT  49.104 103.572 49.128 103.656 ;
    END
  END a_d[487]
  PIN a_d[488]
    DIRECTION OUTPUT ;
    USE SIGNAL ;
    PORT
      LAYER M5 ;
        RECT  49.2 103.572 49.224 103.656 ;
    END
  END a_d[488]
  PIN a_d[489]
    DIRECTION OUTPUT ;
    USE SIGNAL ;
    PORT
      LAYER M5 ;
        RECT  49.296 103.572 49.32 103.656 ;
    END
  END a_d[489]
  PIN a_d[48]
    DIRECTION OUTPUT ;
    USE SIGNAL ;
    PORT
      LAYER M5 ;
        RECT  6.144 103.572 6.168 103.656 ;
    END
  END a_d[48]
  PIN a_d[490]
    DIRECTION OUTPUT ;
    USE SIGNAL ;
    PORT
      LAYER M5 ;
        RECT  49.392 103.572 49.416 103.656 ;
    END
  END a_d[490]
  PIN a_d[491]
    DIRECTION OUTPUT ;
    USE SIGNAL ;
    PORT
      LAYER M5 ;
        RECT  49.488 103.572 49.512 103.656 ;
    END
  END a_d[491]
  PIN a_d[492]
    DIRECTION OUTPUT ;
    USE SIGNAL ;
    PORT
      LAYER M5 ;
        RECT  49.584 103.572 49.608 103.656 ;
    END
  END a_d[492]
  PIN a_d[493]
    DIRECTION OUTPUT ;
    USE SIGNAL ;
    PORT
      LAYER M5 ;
        RECT  49.68 103.572 49.704 103.656 ;
    END
  END a_d[493]
  PIN a_d[494]
    DIRECTION OUTPUT ;
    USE SIGNAL ;
    PORT
      LAYER M5 ;
        RECT  49.776 103.572 49.8 103.656 ;
    END
  END a_d[494]
  PIN a_d[495]
    DIRECTION OUTPUT ;
    USE SIGNAL ;
    PORT
      LAYER M5 ;
        RECT  49.872 103.572 49.896 103.656 ;
    END
  END a_d[495]
  PIN a_d[496]
    DIRECTION OUTPUT ;
    USE SIGNAL ;
    PORT
      LAYER M5 ;
        RECT  49.968 103.572 49.992 103.656 ;
    END
  END a_d[496]
  PIN a_d[497]
    DIRECTION OUTPUT ;
    USE SIGNAL ;
    PORT
      LAYER M5 ;
        RECT  50.064 103.572 50.088 103.656 ;
    END
  END a_d[497]
  PIN a_d[498]
    DIRECTION OUTPUT ;
    USE SIGNAL ;
    PORT
      LAYER M5 ;
        RECT  50.16 103.572 50.184 103.656 ;
    END
  END a_d[498]
  PIN a_d[499]
    DIRECTION OUTPUT ;
    USE SIGNAL ;
    PORT
      LAYER M5 ;
        RECT  50.256 103.572 50.28 103.656 ;
    END
  END a_d[499]
  PIN a_d[49]
    DIRECTION OUTPUT ;
    USE SIGNAL ;
    PORT
      LAYER M5 ;
        RECT  6.24 103.572 6.264 103.656 ;
    END
  END a_d[49]
  PIN a_d[4]
    DIRECTION OUTPUT ;
    USE SIGNAL ;
    PORT
      LAYER M5 ;
        RECT  1.824 103.572 1.848 103.656 ;
    END
  END a_d[4]
  PIN a_d[500]
    DIRECTION OUTPUT ;
    USE SIGNAL ;
    PORT
      LAYER M5 ;
        RECT  50.352 103.572 50.376 103.656 ;
    END
  END a_d[500]
  PIN a_d[501]
    DIRECTION OUTPUT ;
    USE SIGNAL ;
    PORT
      LAYER M5 ;
        RECT  50.448 103.572 50.472 103.656 ;
    END
  END a_d[501]
  PIN a_d[502]
    DIRECTION OUTPUT ;
    USE SIGNAL ;
    PORT
      LAYER M5 ;
        RECT  50.544 103.572 50.568 103.656 ;
    END
  END a_d[502]
  PIN a_d[503]
    DIRECTION OUTPUT ;
    USE SIGNAL ;
    PORT
      LAYER M5 ;
        RECT  50.688 103.572 50.712 103.656 ;
    END
  END a_d[503]
  PIN a_d[504]
    DIRECTION OUTPUT ;
    USE SIGNAL ;
    PORT
      LAYER M5 ;
        RECT  50.784 103.572 50.808 103.656 ;
    END
  END a_d[504]
  PIN a_d[505]
    DIRECTION OUTPUT ;
    USE SIGNAL ;
    PORT
      LAYER M5 ;
        RECT  50.88 103.572 50.904 103.656 ;
    END
  END a_d[505]
  PIN a_d[506]
    DIRECTION OUTPUT ;
    USE SIGNAL ;
    PORT
      LAYER M5 ;
        RECT  50.976 103.572 51 103.656 ;
    END
  END a_d[506]
  PIN a_d[507]
    DIRECTION OUTPUT ;
    USE SIGNAL ;
    PORT
      LAYER M5 ;
        RECT  51.072 103.572 51.096 103.656 ;
    END
  END a_d[507]
  PIN a_d[508]
    DIRECTION OUTPUT ;
    USE SIGNAL ;
    PORT
      LAYER M5 ;
        RECT  51.168 103.572 51.192 103.656 ;
    END
  END a_d[508]
  PIN a_d[509]
    DIRECTION OUTPUT ;
    USE SIGNAL ;
    PORT
      LAYER M5 ;
        RECT  51.264 103.572 51.288 103.656 ;
    END
  END a_d[509]
  PIN a_d[50]
    DIRECTION OUTPUT ;
    USE SIGNAL ;
    PORT
      LAYER M5 ;
        RECT  6.336 103.572 6.36 103.656 ;
    END
  END a_d[50]
  PIN a_d[510]
    DIRECTION OUTPUT ;
    USE SIGNAL ;
    PORT
      LAYER M5 ;
        RECT  51.36 103.572 51.384 103.656 ;
    END
  END a_d[510]
  PIN a_d[511]
    DIRECTION OUTPUT ;
    USE SIGNAL ;
    PORT
      LAYER M5 ;
        RECT  51.456 103.572 51.48 103.656 ;
    END
  END a_d[511]
  PIN a_d[512]
    DIRECTION OUTPUT ;
    USE SIGNAL ;
    PORT
      LAYER M5 ;
        RECT  51.552 103.572 51.576 103.656 ;
    END
  END a_d[512]
  PIN a_d[513]
    DIRECTION OUTPUT ;
    USE SIGNAL ;
    PORT
      LAYER M5 ;
        RECT  51.648 103.572 51.672 103.656 ;
    END
  END a_d[513]
  PIN a_d[514]
    DIRECTION OUTPUT ;
    USE SIGNAL ;
    PORT
      LAYER M5 ;
        RECT  51.744 103.572 51.768 103.656 ;
    END
  END a_d[514]
  PIN a_d[515]
    DIRECTION OUTPUT ;
    USE SIGNAL ;
    PORT
      LAYER M5 ;
        RECT  51.84 103.572 51.864 103.656 ;
    END
  END a_d[515]
  PIN a_d[51]
    DIRECTION OUTPUT ;
    USE SIGNAL ;
    PORT
      LAYER M5 ;
        RECT  6.432 103.572 6.456 103.656 ;
    END
  END a_d[51]
  PIN a_d[52]
    DIRECTION OUTPUT ;
    USE SIGNAL ;
    PORT
      LAYER M5 ;
        RECT  6.528 103.572 6.552 103.656 ;
    END
  END a_d[52]
  PIN a_d[53]
    DIRECTION OUTPUT ;
    USE SIGNAL ;
    PORT
      LAYER M5 ;
        RECT  6.624 103.572 6.648 103.656 ;
    END
  END a_d[53]
  PIN a_d[54]
    DIRECTION OUTPUT ;
    USE SIGNAL ;
    PORT
      LAYER M5 ;
        RECT  6.72 103.572 6.744 103.656 ;
    END
  END a_d[54]
  PIN a_d[55]
    DIRECTION OUTPUT ;
    USE SIGNAL ;
    PORT
      LAYER M5 ;
        RECT  6.816 103.572 6.84 103.656 ;
    END
  END a_d[55]
  PIN a_d[56]
    DIRECTION OUTPUT ;
    USE SIGNAL ;
    PORT
      LAYER M5 ;
        RECT  6.912 103.572 6.936 103.656 ;
    END
  END a_d[56]
  PIN a_d[57]
    DIRECTION OUTPUT ;
    USE SIGNAL ;
    PORT
      LAYER M5 ;
        RECT  7.008 103.572 7.032 103.656 ;
    END
  END a_d[57]
  PIN a_d[58]
    DIRECTION OUTPUT ;
    USE SIGNAL ;
    PORT
      LAYER M5 ;
        RECT  7.104 103.572 7.128 103.656 ;
    END
  END a_d[58]
  PIN a_d[59]
    DIRECTION OUTPUT ;
    USE SIGNAL ;
    PORT
      LAYER M5 ;
        RECT  7.2 103.572 7.224 103.656 ;
    END
  END a_d[59]
  PIN a_d[5]
    DIRECTION OUTPUT ;
    USE SIGNAL ;
    PORT
      LAYER M5 ;
        RECT  1.92 103.572 1.944 103.656 ;
    END
  END a_d[5]
  PIN a_d[60]
    DIRECTION OUTPUT ;
    USE SIGNAL ;
    PORT
      LAYER M5 ;
        RECT  7.296 103.572 7.32 103.656 ;
    END
  END a_d[60]
  PIN a_d[61]
    DIRECTION OUTPUT ;
    USE SIGNAL ;
    PORT
      LAYER M5 ;
        RECT  7.392 103.572 7.416 103.656 ;
    END
  END a_d[61]
  PIN a_d[62]
    DIRECTION OUTPUT ;
    USE SIGNAL ;
    PORT
      LAYER M5 ;
        RECT  7.488 103.572 7.512 103.656 ;
    END
  END a_d[62]
  PIN a_d[63]
    DIRECTION OUTPUT ;
    USE SIGNAL ;
    PORT
      LAYER M5 ;
        RECT  7.584 103.572 7.608 103.656 ;
    END
  END a_d[63]
  PIN a_d[64]
    DIRECTION OUTPUT ;
    USE SIGNAL ;
    PORT
      LAYER M5 ;
        RECT  7.728 103.572 7.752 103.656 ;
    END
  END a_d[64]
  PIN a_d[65]
    DIRECTION OUTPUT ;
    USE SIGNAL ;
    PORT
      LAYER M5 ;
        RECT  7.824 103.572 7.848 103.656 ;
    END
  END a_d[65]
  PIN a_d[66]
    DIRECTION OUTPUT ;
    USE SIGNAL ;
    PORT
      LAYER M5 ;
        RECT  7.92 103.572 7.944 103.656 ;
    END
  END a_d[66]
  PIN a_d[67]
    DIRECTION OUTPUT ;
    USE SIGNAL ;
    PORT
      LAYER M5 ;
        RECT  8.016 103.572 8.04 103.656 ;
    END
  END a_d[67]
  PIN a_d[68]
    DIRECTION OUTPUT ;
    USE SIGNAL ;
    PORT
      LAYER M5 ;
        RECT  8.112 103.572 8.136 103.656 ;
    END
  END a_d[68]
  PIN a_d[69]
    DIRECTION OUTPUT ;
    USE SIGNAL ;
    PORT
      LAYER M5 ;
        RECT  8.208 103.572 8.232 103.656 ;
    END
  END a_d[69]
  PIN a_d[6]
    DIRECTION OUTPUT ;
    USE SIGNAL ;
    PORT
      LAYER M5 ;
        RECT  2.016 103.572 2.04 103.656 ;
    END
  END a_d[6]
  PIN a_d[70]
    DIRECTION OUTPUT ;
    USE SIGNAL ;
    PORT
      LAYER M5 ;
        RECT  8.304 103.572 8.328 103.656 ;
    END
  END a_d[70]
  PIN a_d[71]
    DIRECTION OUTPUT ;
    USE SIGNAL ;
    PORT
      LAYER M5 ;
        RECT  8.4 103.572 8.424 103.656 ;
    END
  END a_d[71]
  PIN a_d[72]
    DIRECTION OUTPUT ;
    USE SIGNAL ;
    PORT
      LAYER M5 ;
        RECT  8.496 103.572 8.52 103.656 ;
    END
  END a_d[72]
  PIN a_d[73]
    DIRECTION OUTPUT ;
    USE SIGNAL ;
    PORT
      LAYER M5 ;
        RECT  8.592 103.572 8.616 103.656 ;
    END
  END a_d[73]
  PIN a_d[74]
    DIRECTION OUTPUT ;
    USE SIGNAL ;
    PORT
      LAYER M5 ;
        RECT  8.688 103.572 8.712 103.656 ;
    END
  END a_d[74]
  PIN a_d[75]
    DIRECTION OUTPUT ;
    USE SIGNAL ;
    PORT
      LAYER M5 ;
        RECT  8.784 103.572 8.808 103.656 ;
    END
  END a_d[75]
  PIN a_d[76]
    DIRECTION OUTPUT ;
    USE SIGNAL ;
    PORT
      LAYER M5 ;
        RECT  8.88 103.572 8.904 103.656 ;
    END
  END a_d[76]
  PIN a_d[77]
    DIRECTION OUTPUT ;
    USE SIGNAL ;
    PORT
      LAYER M5 ;
        RECT  8.976 103.572 9 103.656 ;
    END
  END a_d[77]
  PIN a_d[78]
    DIRECTION OUTPUT ;
    USE SIGNAL ;
    PORT
      LAYER M5 ;
        RECT  9.072 103.572 9.096 103.656 ;
    END
  END a_d[78]
  PIN a_d[79]
    DIRECTION OUTPUT ;
    USE SIGNAL ;
    PORT
      LAYER M5 ;
        RECT  9.168 103.572 9.192 103.656 ;
    END
  END a_d[79]
  PIN a_d[7]
    DIRECTION OUTPUT ;
    USE SIGNAL ;
    PORT
      LAYER M5 ;
        RECT  2.112 103.572 2.136 103.656 ;
    END
  END a_d[7]
  PIN a_d[80]
    DIRECTION OUTPUT ;
    USE SIGNAL ;
    PORT
      LAYER M5 ;
        RECT  9.264 103.572 9.288 103.656 ;
    END
  END a_d[80]
  PIN a_d[81]
    DIRECTION OUTPUT ;
    USE SIGNAL ;
    PORT
      LAYER M5 ;
        RECT  9.36 103.572 9.384 103.656 ;
    END
  END a_d[81]
  PIN a_d[82]
    DIRECTION OUTPUT ;
    USE SIGNAL ;
    PORT
      LAYER M5 ;
        RECT  9.456 103.572 9.48 103.656 ;
    END
  END a_d[82]
  PIN a_d[83]
    DIRECTION OUTPUT ;
    USE SIGNAL ;
    PORT
      LAYER M5 ;
        RECT  9.552 103.572 9.576 103.656 ;
    END
  END a_d[83]
  PIN a_d[84]
    DIRECTION OUTPUT ;
    USE SIGNAL ;
    PORT
      LAYER M5 ;
        RECT  9.648 103.572 9.672 103.656 ;
    END
  END a_d[84]
  PIN a_d[85]
    DIRECTION OUTPUT ;
    USE SIGNAL ;
    PORT
      LAYER M5 ;
        RECT  9.744 103.572 9.768 103.656 ;
    END
  END a_d[85]
  PIN a_d[86]
    DIRECTION OUTPUT ;
    USE SIGNAL ;
    PORT
      LAYER M5 ;
        RECT  9.84 103.572 9.864 103.656 ;
    END
  END a_d[86]
  PIN a_d[87]
    DIRECTION OUTPUT ;
    USE SIGNAL ;
    PORT
      LAYER M5 ;
        RECT  9.936 103.572 9.96 103.656 ;
    END
  END a_d[87]
  PIN a_d[88]
    DIRECTION OUTPUT ;
    USE SIGNAL ;
    PORT
      LAYER M5 ;
        RECT  10.032 103.572 10.056 103.656 ;
    END
  END a_d[88]
  PIN a_d[89]
    DIRECTION OUTPUT ;
    USE SIGNAL ;
    PORT
      LAYER M5 ;
        RECT  10.128 103.572 10.152 103.656 ;
    END
  END a_d[89]
  PIN a_d[8]
    DIRECTION OUTPUT ;
    USE SIGNAL ;
    PORT
      LAYER M5 ;
        RECT  2.208 103.572 2.232 103.656 ;
    END
  END a_d[8]
  PIN a_d[90]
    DIRECTION OUTPUT ;
    USE SIGNAL ;
    PORT
      LAYER M5 ;
        RECT  10.272 103.572 10.296 103.656 ;
    END
  END a_d[90]
  PIN a_d[91]
    DIRECTION OUTPUT ;
    USE SIGNAL ;
    PORT
      LAYER M5 ;
        RECT  10.368 103.572 10.392 103.656 ;
    END
  END a_d[91]
  PIN a_d[92]
    DIRECTION OUTPUT ;
    USE SIGNAL ;
    PORT
      LAYER M5 ;
        RECT  10.464 103.572 10.488 103.656 ;
    END
  END a_d[92]
  PIN a_d[93]
    DIRECTION OUTPUT ;
    USE SIGNAL ;
    PORT
      LAYER M5 ;
        RECT  10.56 103.572 10.584 103.656 ;
    END
  END a_d[93]
  PIN a_d[94]
    DIRECTION OUTPUT ;
    USE SIGNAL ;
    PORT
      LAYER M5 ;
        RECT  10.656 103.572 10.68 103.656 ;
    END
  END a_d[94]
  PIN a_d[95]
    DIRECTION OUTPUT ;
    USE SIGNAL ;
    PORT
      LAYER M5 ;
        RECT  10.752 103.572 10.776 103.656 ;
    END
  END a_d[95]
  PIN a_d[96]
    DIRECTION OUTPUT ;
    USE SIGNAL ;
    PORT
      LAYER M5 ;
        RECT  10.848 103.572 10.872 103.656 ;
    END
  END a_d[96]
  PIN a_d[97]
    DIRECTION OUTPUT ;
    USE SIGNAL ;
    PORT
      LAYER M5 ;
        RECT  10.944 103.572 10.968 103.656 ;
    END
  END a_d[97]
  PIN a_d[98]
    DIRECTION OUTPUT ;
    USE SIGNAL ;
    PORT
      LAYER M5 ;
        RECT  11.04 103.572 11.064 103.656 ;
    END
  END a_d[98]
  PIN a_d[99]
    DIRECTION OUTPUT ;
    USE SIGNAL ;
    PORT
      LAYER M5 ;
        RECT  11.136 103.572 11.16 103.656 ;
    END
  END a_d[99]
  PIN a_d[9]
    DIRECTION OUTPUT ;
    USE SIGNAL ;
    PORT
      LAYER M5 ;
        RECT  2.304 103.572 2.328 103.656 ;
    END
  END a_d[9]
  PIN b_d[0]
    DIRECTION INPUT ;
    USE SIGNAL ;
    PORT
      LAYER M5 ;
        RECT  0.768 0 0.792 0.084 ;
    END
  END b_d[0]
  PIN b_d[100]
    DIRECTION INPUT ;
    USE SIGNAL ;
    PORT
      LAYER M5 ;
        RECT  10.512 0 10.536 0.084 ;
    END
  END b_d[100]
  PIN b_d[101]
    DIRECTION INPUT ;
    USE SIGNAL ;
    PORT
      LAYER M5 ;
        RECT  10.608 0 10.632 0.084 ;
    END
  END b_d[101]
  PIN b_d[102]
    DIRECTION INPUT ;
    USE SIGNAL ;
    PORT
      LAYER M5 ;
        RECT  10.704 0 10.728 0.084 ;
    END
  END b_d[102]
  PIN b_d[103]
    DIRECTION INPUT ;
    USE SIGNAL ;
    PORT
      LAYER M5 ;
        RECT  10.8 0 10.824 0.084 ;
    END
  END b_d[103]
  PIN b_d[104]
    DIRECTION INPUT ;
    USE SIGNAL ;
    PORT
      LAYER M5 ;
        RECT  10.896 0 10.92 0.084 ;
    END
  END b_d[104]
  PIN b_d[105]
    DIRECTION INPUT ;
    USE SIGNAL ;
    PORT
      LAYER M5 ;
        RECT  10.992 0 11.016 0.084 ;
    END
  END b_d[105]
  PIN b_d[106]
    DIRECTION INPUT ;
    USE SIGNAL ;
    PORT
      LAYER M5 ;
        RECT  11.088 0 11.112 0.084 ;
    END
  END b_d[106]
  PIN b_d[107]
    DIRECTION INPUT ;
    USE SIGNAL ;
    PORT
      LAYER M5 ;
        RECT  11.184 0 11.208 0.084 ;
    END
  END b_d[107]
  PIN b_d[108]
    DIRECTION INPUT ;
    USE SIGNAL ;
    PORT
      LAYER M5 ;
        RECT  11.28 0 11.304 0.084 ;
    END
  END b_d[108]
  PIN b_d[109]
    DIRECTION INPUT ;
    USE SIGNAL ;
    PORT
      LAYER M5 ;
        RECT  11.376 0 11.4 0.084 ;
    END
  END b_d[109]
  PIN b_d[10]
    DIRECTION INPUT ;
    USE SIGNAL ;
    PORT
      LAYER M5 ;
        RECT  1.728 0 1.752 0.084 ;
    END
  END b_d[10]
  PIN b_d[110]
    DIRECTION INPUT ;
    USE SIGNAL ;
    PORT
      LAYER M5 ;
        RECT  11.472 0 11.496 0.084 ;
    END
  END b_d[110]
  PIN b_d[111]
    DIRECTION INPUT ;
    USE SIGNAL ;
    PORT
      LAYER M5 ;
        RECT  11.568 0 11.592 0.084 ;
    END
  END b_d[111]
  PIN b_d[112]
    DIRECTION INPUT ;
    USE SIGNAL ;
    PORT
      LAYER M5 ;
        RECT  11.664 0 11.688 0.084 ;
    END
  END b_d[112]
  PIN b_d[113]
    DIRECTION INPUT ;
    USE SIGNAL ;
    PORT
      LAYER M5 ;
        RECT  11.76 0 11.784 0.084 ;
    END
  END b_d[113]
  PIN b_d[114]
    DIRECTION INPUT ;
    USE SIGNAL ;
    PORT
      LAYER M5 ;
        RECT  11.856 0 11.88 0.084 ;
    END
  END b_d[114]
  PIN b_d[115]
    DIRECTION INPUT ;
    USE SIGNAL ;
    PORT
      LAYER M5 ;
        RECT  11.952 0 11.976 0.084 ;
    END
  END b_d[115]
  PIN b_d[116]
    DIRECTION INPUT ;
    USE SIGNAL ;
    PORT
      LAYER M5 ;
        RECT  12.048 0 12.072 0.084 ;
    END
  END b_d[116]
  PIN b_d[117]
    DIRECTION INPUT ;
    USE SIGNAL ;
    PORT
      LAYER M5 ;
        RECT  12.144 0 12.168 0.084 ;
    END
  END b_d[117]
  PIN b_d[118]
    DIRECTION INPUT ;
    USE SIGNAL ;
    PORT
      LAYER M5 ;
        RECT  12.24 0 12.264 0.084 ;
    END
  END b_d[118]
  PIN b_d[119]
    DIRECTION INPUT ;
    USE SIGNAL ;
    PORT
      LAYER M5 ;
        RECT  12.336 0 12.36 0.084 ;
    END
  END b_d[119]
  PIN b_d[11]
    DIRECTION INPUT ;
    USE SIGNAL ;
    PORT
      LAYER M5 ;
        RECT  1.824 0 1.848 0.084 ;
    END
  END b_d[11]
  PIN b_d[120]
    DIRECTION INPUT ;
    USE SIGNAL ;
    PORT
      LAYER M5 ;
        RECT  12.432 0 12.456 0.084 ;
    END
  END b_d[120]
  PIN b_d[121]
    DIRECTION INPUT ;
    USE SIGNAL ;
    PORT
      LAYER M5 ;
        RECT  12.528 0 12.552 0.084 ;
    END
  END b_d[121]
  PIN b_d[122]
    DIRECTION INPUT ;
    USE SIGNAL ;
    PORT
      LAYER M5 ;
        RECT  12.624 0 12.648 0.084 ;
    END
  END b_d[122]
  PIN b_d[123]
    DIRECTION INPUT ;
    USE SIGNAL ;
    PORT
      LAYER M5 ;
        RECT  12.72 0 12.744 0.084 ;
    END
  END b_d[123]
  PIN b_d[124]
    DIRECTION INPUT ;
    USE SIGNAL ;
    PORT
      LAYER M5 ;
        RECT  12.816 0 12.84 0.084 ;
    END
  END b_d[124]
  PIN b_d[125]
    DIRECTION INPUT ;
    USE SIGNAL ;
    PORT
      LAYER M5 ;
        RECT  12.912 0 12.936 0.084 ;
    END
  END b_d[125]
  PIN b_d[126]
    DIRECTION INPUT ;
    USE SIGNAL ;
    PORT
      LAYER M5 ;
        RECT  13.008 0 13.032 0.084 ;
    END
  END b_d[126]
  PIN b_d[127]
    DIRECTION INPUT ;
    USE SIGNAL ;
    PORT
      LAYER M5 ;
        RECT  13.104 0 13.128 0.084 ;
    END
  END b_d[127]
  PIN b_d[128]
    DIRECTION INPUT ;
    USE SIGNAL ;
    PORT
      LAYER M5 ;
        RECT  13.2 0 13.224 0.084 ;
    END
  END b_d[128]
  PIN b_d[129]
    DIRECTION INPUT ;
    USE SIGNAL ;
    PORT
      LAYER M5 ;
        RECT  13.344 0 13.368 0.084 ;
    END
  END b_d[129]
  PIN b_d[12]
    DIRECTION INPUT ;
    USE SIGNAL ;
    PORT
      LAYER M5 ;
        RECT  1.92 0 1.944 0.084 ;
    END
  END b_d[12]
  PIN b_d[130]
    DIRECTION INPUT ;
    USE SIGNAL ;
    PORT
      LAYER M5 ;
        RECT  13.44 0 13.464 0.084 ;
    END
  END b_d[130]
  PIN b_d[131]
    DIRECTION INPUT ;
    USE SIGNAL ;
    PORT
      LAYER M5 ;
        RECT  13.536 0 13.56 0.084 ;
    END
  END b_d[131]
  PIN b_d[132]
    DIRECTION INPUT ;
    USE SIGNAL ;
    PORT
      LAYER M5 ;
        RECT  13.632 0 13.656 0.084 ;
    END
  END b_d[132]
  PIN b_d[133]
    DIRECTION INPUT ;
    USE SIGNAL ;
    PORT
      LAYER M5 ;
        RECT  13.728 0 13.752 0.084 ;
    END
  END b_d[133]
  PIN b_d[134]
    DIRECTION INPUT ;
    USE SIGNAL ;
    PORT
      LAYER M5 ;
        RECT  13.824 0 13.848 0.084 ;
    END
  END b_d[134]
  PIN b_d[135]
    DIRECTION INPUT ;
    USE SIGNAL ;
    PORT
      LAYER M5 ;
        RECT  13.92 0 13.944 0.084 ;
    END
  END b_d[135]
  PIN b_d[136]
    DIRECTION INPUT ;
    USE SIGNAL ;
    PORT
      LAYER M5 ;
        RECT  14.016 0 14.04 0.084 ;
    END
  END b_d[136]
  PIN b_d[137]
    DIRECTION INPUT ;
    USE SIGNAL ;
    PORT
      LAYER M5 ;
        RECT  14.112 0 14.136 0.084 ;
    END
  END b_d[137]
  PIN b_d[138]
    DIRECTION INPUT ;
    USE SIGNAL ;
    PORT
      LAYER M5 ;
        RECT  14.208 0 14.232 0.084 ;
    END
  END b_d[138]
  PIN b_d[139]
    DIRECTION INPUT ;
    USE SIGNAL ;
    PORT
      LAYER M5 ;
        RECT  14.304 0 14.328 0.084 ;
    END
  END b_d[139]
  PIN b_d[13]
    DIRECTION INPUT ;
    USE SIGNAL ;
    PORT
      LAYER M5 ;
        RECT  2.016 0 2.04 0.084 ;
    END
  END b_d[13]
  PIN b_d[140]
    DIRECTION INPUT ;
    USE SIGNAL ;
    PORT
      LAYER M5 ;
        RECT  14.4 0 14.424 0.084 ;
    END
  END b_d[140]
  PIN b_d[141]
    DIRECTION INPUT ;
    USE SIGNAL ;
    PORT
      LAYER M5 ;
        RECT  14.496 0 14.52 0.084 ;
    END
  END b_d[141]
  PIN b_d[142]
    DIRECTION INPUT ;
    USE SIGNAL ;
    PORT
      LAYER M5 ;
        RECT  14.592 0 14.616 0.084 ;
    END
  END b_d[142]
  PIN b_d[143]
    DIRECTION INPUT ;
    USE SIGNAL ;
    PORT
      LAYER M5 ;
        RECT  14.688 0 14.712 0.084 ;
    END
  END b_d[143]
  PIN b_d[144]
    DIRECTION INPUT ;
    USE SIGNAL ;
    PORT
      LAYER M5 ;
        RECT  14.784 0 14.808 0.084 ;
    END
  END b_d[144]
  PIN b_d[145]
    DIRECTION INPUT ;
    USE SIGNAL ;
    PORT
      LAYER M5 ;
        RECT  14.88 0 14.904 0.084 ;
    END
  END b_d[145]
  PIN b_d[146]
    DIRECTION INPUT ;
    USE SIGNAL ;
    PORT
      LAYER M5 ;
        RECT  14.976 0 15 0.084 ;
    END
  END b_d[146]
  PIN b_d[147]
    DIRECTION INPUT ;
    USE SIGNAL ;
    PORT
      LAYER M5 ;
        RECT  15.072 0 15.096 0.084 ;
    END
  END b_d[147]
  PIN b_d[148]
    DIRECTION INPUT ;
    USE SIGNAL ;
    PORT
      LAYER M5 ;
        RECT  15.168 0 15.192 0.084 ;
    END
  END b_d[148]
  PIN b_d[149]
    DIRECTION INPUT ;
    USE SIGNAL ;
    PORT
      LAYER M5 ;
        RECT  15.264 0 15.288 0.084 ;
    END
  END b_d[149]
  PIN b_d[14]
    DIRECTION INPUT ;
    USE SIGNAL ;
    PORT
      LAYER M5 ;
        RECT  2.112 0 2.136 0.084 ;
    END
  END b_d[14]
  PIN b_d[150]
    DIRECTION INPUT ;
    USE SIGNAL ;
    PORT
      LAYER M5 ;
        RECT  15.36 0 15.384 0.084 ;
    END
  END b_d[150]
  PIN b_d[151]
    DIRECTION INPUT ;
    USE SIGNAL ;
    PORT
      LAYER M5 ;
        RECT  15.456 0 15.48 0.084 ;
    END
  END b_d[151]
  PIN b_d[152]
    DIRECTION INPUT ;
    USE SIGNAL ;
    PORT
      LAYER M5 ;
        RECT  15.552 0 15.576 0.084 ;
    END
  END b_d[152]
  PIN b_d[153]
    DIRECTION INPUT ;
    USE SIGNAL ;
    PORT
      LAYER M5 ;
        RECT  15.648 0 15.672 0.084 ;
    END
  END b_d[153]
  PIN b_d[154]
    DIRECTION INPUT ;
    USE SIGNAL ;
    PORT
      LAYER M5 ;
        RECT  15.744 0 15.768 0.084 ;
    END
  END b_d[154]
  PIN b_d[155]
    DIRECTION INPUT ;
    USE SIGNAL ;
    PORT
      LAYER M5 ;
        RECT  15.84 0 15.864 0.084 ;
    END
  END b_d[155]
  PIN b_d[156]
    DIRECTION INPUT ;
    USE SIGNAL ;
    PORT
      LAYER M5 ;
        RECT  15.936 0 15.96 0.084 ;
    END
  END b_d[156]
  PIN b_d[157]
    DIRECTION INPUT ;
    USE SIGNAL ;
    PORT
      LAYER M5 ;
        RECT  16.032 0 16.056 0.084 ;
    END
  END b_d[157]
  PIN b_d[158]
    DIRECTION INPUT ;
    USE SIGNAL ;
    PORT
      LAYER M5 ;
        RECT  16.128 0 16.152 0.084 ;
    END
  END b_d[158]
  PIN b_d[159]
    DIRECTION INPUT ;
    USE SIGNAL ;
    PORT
      LAYER M5 ;
        RECT  16.224 0 16.248 0.084 ;
    END
  END b_d[159]
  PIN b_d[15]
    DIRECTION INPUT ;
    USE SIGNAL ;
    PORT
      LAYER M5 ;
        RECT  2.208 0 2.232 0.084 ;
    END
  END b_d[15]
  PIN b_d[160]
    DIRECTION INPUT ;
    USE SIGNAL ;
    PORT
      LAYER M5 ;
        RECT  16.32 0 16.344 0.084 ;
    END
  END b_d[160]
  PIN b_d[161]
    DIRECTION INPUT ;
    USE SIGNAL ;
    PORT
      LAYER M5 ;
        RECT  16.416 0 16.44 0.084 ;
    END
  END b_d[161]
  PIN b_d[162]
    DIRECTION INPUT ;
    USE SIGNAL ;
    PORT
      LAYER M5 ;
        RECT  16.512 0 16.536 0.084 ;
    END
  END b_d[162]
  PIN b_d[163]
    DIRECTION INPUT ;
    USE SIGNAL ;
    PORT
      LAYER M5 ;
        RECT  16.608 0 16.632 0.084 ;
    END
  END b_d[163]
  PIN b_d[164]
    DIRECTION INPUT ;
    USE SIGNAL ;
    PORT
      LAYER M5 ;
        RECT  16.704 0 16.728 0.084 ;
    END
  END b_d[164]
  PIN b_d[165]
    DIRECTION INPUT ;
    USE SIGNAL ;
    PORT
      LAYER M5 ;
        RECT  16.848 0 16.872 0.084 ;
    END
  END b_d[165]
  PIN b_d[166]
    DIRECTION INPUT ;
    USE SIGNAL ;
    PORT
      LAYER M5 ;
        RECT  16.944 0 16.968 0.084 ;
    END
  END b_d[166]
  PIN b_d[167]
    DIRECTION INPUT ;
    USE SIGNAL ;
    PORT
      LAYER M5 ;
        RECT  17.04 0 17.064 0.084 ;
    END
  END b_d[167]
  PIN b_d[168]
    DIRECTION INPUT ;
    USE SIGNAL ;
    PORT
      LAYER M5 ;
        RECT  17.136 0 17.16 0.084 ;
    END
  END b_d[168]
  PIN b_d[169]
    DIRECTION INPUT ;
    USE SIGNAL ;
    PORT
      LAYER M5 ;
        RECT  17.232 0 17.256 0.084 ;
    END
  END b_d[169]
  PIN b_d[16]
    DIRECTION INPUT ;
    USE SIGNAL ;
    PORT
      LAYER M5 ;
        RECT  2.304 0 2.328 0.084 ;
    END
  END b_d[16]
  PIN b_d[170]
    DIRECTION INPUT ;
    USE SIGNAL ;
    PORT
      LAYER M5 ;
        RECT  17.328 0 17.352 0.084 ;
    END
  END b_d[170]
  PIN b_d[171]
    DIRECTION INPUT ;
    USE SIGNAL ;
    PORT
      LAYER M5 ;
        RECT  17.424 0 17.448 0.084 ;
    END
  END b_d[171]
  PIN b_d[172]
    DIRECTION INPUT ;
    USE SIGNAL ;
    PORT
      LAYER M5 ;
        RECT  17.52 0 17.544 0.084 ;
    END
  END b_d[172]
  PIN b_d[173]
    DIRECTION INPUT ;
    USE SIGNAL ;
    PORT
      LAYER M5 ;
        RECT  17.616 0 17.64 0.084 ;
    END
  END b_d[173]
  PIN b_d[174]
    DIRECTION INPUT ;
    USE SIGNAL ;
    PORT
      LAYER M5 ;
        RECT  17.712 0 17.736 0.084 ;
    END
  END b_d[174]
  PIN b_d[175]
    DIRECTION INPUT ;
    USE SIGNAL ;
    PORT
      LAYER M5 ;
        RECT  17.808 0 17.832 0.084 ;
    END
  END b_d[175]
  PIN b_d[176]
    DIRECTION INPUT ;
    USE SIGNAL ;
    PORT
      LAYER M5 ;
        RECT  17.904 0 17.928 0.084 ;
    END
  END b_d[176]
  PIN b_d[177]
    DIRECTION INPUT ;
    USE SIGNAL ;
    PORT
      LAYER M5 ;
        RECT  18 0 18.024 0.084 ;
    END
  END b_d[177]
  PIN b_d[178]
    DIRECTION INPUT ;
    USE SIGNAL ;
    PORT
      LAYER M5 ;
        RECT  18.096 0 18.12 0.084 ;
    END
  END b_d[178]
  PIN b_d[179]
    DIRECTION INPUT ;
    USE SIGNAL ;
    PORT
      LAYER M5 ;
        RECT  18.192 0 18.216 0.084 ;
    END
  END b_d[179]
  PIN b_d[17]
    DIRECTION INPUT ;
    USE SIGNAL ;
    PORT
      LAYER M5 ;
        RECT  2.4 0 2.424 0.084 ;
    END
  END b_d[17]
  PIN b_d[180]
    DIRECTION INPUT ;
    USE SIGNAL ;
    PORT
      LAYER M5 ;
        RECT  18.288 0 18.312 0.084 ;
    END
  END b_d[180]
  PIN b_d[181]
    DIRECTION INPUT ;
    USE SIGNAL ;
    PORT
      LAYER M5 ;
        RECT  18.384 0 18.408 0.084 ;
    END
  END b_d[181]
  PIN b_d[182]
    DIRECTION INPUT ;
    USE SIGNAL ;
    PORT
      LAYER M5 ;
        RECT  18.48 0 18.504 0.084 ;
    END
  END b_d[182]
  PIN b_d[183]
    DIRECTION INPUT ;
    USE SIGNAL ;
    PORT
      LAYER M5 ;
        RECT  18.576 0 18.6 0.084 ;
    END
  END b_d[183]
  PIN b_d[184]
    DIRECTION INPUT ;
    USE SIGNAL ;
    PORT
      LAYER M5 ;
        RECT  18.672 0 18.696 0.084 ;
    END
  END b_d[184]
  PIN b_d[185]
    DIRECTION INPUT ;
    USE SIGNAL ;
    PORT
      LAYER M5 ;
        RECT  18.768 0 18.792 0.084 ;
    END
  END b_d[185]
  PIN b_d[186]
    DIRECTION INPUT ;
    USE SIGNAL ;
    PORT
      LAYER M5 ;
        RECT  18.864 0 18.888 0.084 ;
    END
  END b_d[186]
  PIN b_d[187]
    DIRECTION INPUT ;
    USE SIGNAL ;
    PORT
      LAYER M5 ;
        RECT  18.96 0 18.984 0.084 ;
    END
  END b_d[187]
  PIN b_d[188]
    DIRECTION INPUT ;
    USE SIGNAL ;
    PORT
      LAYER M5 ;
        RECT  19.056 0 19.08 0.084 ;
    END
  END b_d[188]
  PIN b_d[189]
    DIRECTION INPUT ;
    USE SIGNAL ;
    PORT
      LAYER M5 ;
        RECT  19.152 0 19.176 0.084 ;
    END
  END b_d[189]
  PIN b_d[18]
    DIRECTION INPUT ;
    USE SIGNAL ;
    PORT
      LAYER M5 ;
        RECT  2.544 0 2.568 0.084 ;
    END
  END b_d[18]
  PIN b_d[190]
    DIRECTION INPUT ;
    USE SIGNAL ;
    PORT
      LAYER M5 ;
        RECT  19.248 0 19.272 0.084 ;
    END
  END b_d[190]
  PIN b_d[191]
    DIRECTION INPUT ;
    USE SIGNAL ;
    PORT
      LAYER M5 ;
        RECT  19.344 0 19.368 0.084 ;
    END
  END b_d[191]
  PIN b_d[192]
    DIRECTION INPUT ;
    USE SIGNAL ;
    PORT
      LAYER M5 ;
        RECT  19.44 0 19.464 0.084 ;
    END
  END b_d[192]
  PIN b_d[193]
    DIRECTION INPUT ;
    USE SIGNAL ;
    PORT
      LAYER M5 ;
        RECT  19.536 0 19.56 0.084 ;
    END
  END b_d[193]
  PIN b_d[194]
    DIRECTION INPUT ;
    USE SIGNAL ;
    PORT
      LAYER M5 ;
        RECT  19.632 0 19.656 0.084 ;
    END
  END b_d[194]
  PIN b_d[195]
    DIRECTION INPUT ;
    USE SIGNAL ;
    PORT
      LAYER M5 ;
        RECT  19.728 0 19.752 0.084 ;
    END
  END b_d[195]
  PIN b_d[196]
    DIRECTION INPUT ;
    USE SIGNAL ;
    PORT
      LAYER M5 ;
        RECT  19.824 0 19.848 0.084 ;
    END
  END b_d[196]
  PIN b_d[197]
    DIRECTION INPUT ;
    USE SIGNAL ;
    PORT
      LAYER M5 ;
        RECT  19.92 0 19.944 0.084 ;
    END
  END b_d[197]
  PIN b_d[198]
    DIRECTION INPUT ;
    USE SIGNAL ;
    PORT
      LAYER M5 ;
        RECT  20.016 0 20.04 0.084 ;
    END
  END b_d[198]
  PIN b_d[199]
    DIRECTION INPUT ;
    USE SIGNAL ;
    PORT
      LAYER M5 ;
        RECT  20.112 0 20.136 0.084 ;
    END
  END b_d[199]
  PIN b_d[19]
    DIRECTION INPUT ;
    USE SIGNAL ;
    PORT
      LAYER M5 ;
        RECT  2.64 0 2.664 0.084 ;
    END
  END b_d[19]
  PIN b_d[1]
    DIRECTION INPUT ;
    USE SIGNAL ;
    PORT
      LAYER M5 ;
        RECT  0.864 0 0.888 0.084 ;
    END
  END b_d[1]
  PIN b_d[200]
    DIRECTION INPUT ;
    USE SIGNAL ;
    PORT
      LAYER M5 ;
        RECT  20.208 0 20.232 0.084 ;
    END
  END b_d[200]
  PIN b_d[201]
    DIRECTION INPUT ;
    USE SIGNAL ;
    PORT
      LAYER M5 ;
        RECT  20.304 0 20.328 0.084 ;
    END
  END b_d[201]
  PIN b_d[202]
    DIRECTION INPUT ;
    USE SIGNAL ;
    PORT
      LAYER M5 ;
        RECT  20.448 0 20.472 0.084 ;
    END
  END b_d[202]
  PIN b_d[203]
    DIRECTION INPUT ;
    USE SIGNAL ;
    PORT
      LAYER M5 ;
        RECT  20.544 0 20.568 0.084 ;
    END
  END b_d[203]
  PIN b_d[204]
    DIRECTION INPUT ;
    USE SIGNAL ;
    PORT
      LAYER M5 ;
        RECT  20.64 0 20.664 0.084 ;
    END
  END b_d[204]
  PIN b_d[205]
    DIRECTION INPUT ;
    USE SIGNAL ;
    PORT
      LAYER M5 ;
        RECT  20.736 0 20.76 0.084 ;
    END
  END b_d[205]
  PIN b_d[206]
    DIRECTION INPUT ;
    USE SIGNAL ;
    PORT
      LAYER M5 ;
        RECT  20.832 0 20.856 0.084 ;
    END
  END b_d[206]
  PIN b_d[207]
    DIRECTION INPUT ;
    USE SIGNAL ;
    PORT
      LAYER M5 ;
        RECT  20.928 0 20.952 0.084 ;
    END
  END b_d[207]
  PIN b_d[208]
    DIRECTION INPUT ;
    USE SIGNAL ;
    PORT
      LAYER M5 ;
        RECT  21.024 0 21.048 0.084 ;
    END
  END b_d[208]
  PIN b_d[209]
    DIRECTION INPUT ;
    USE SIGNAL ;
    PORT
      LAYER M5 ;
        RECT  21.12 0 21.144 0.084 ;
    END
  END b_d[209]
  PIN b_d[20]
    DIRECTION INPUT ;
    USE SIGNAL ;
    PORT
      LAYER M5 ;
        RECT  2.736 0 2.76 0.084 ;
    END
  END b_d[20]
  PIN b_d[210]
    DIRECTION INPUT ;
    USE SIGNAL ;
    PORT
      LAYER M5 ;
        RECT  21.216 0 21.24 0.084 ;
    END
  END b_d[210]
  PIN b_d[211]
    DIRECTION INPUT ;
    USE SIGNAL ;
    PORT
      LAYER M5 ;
        RECT  21.312 0 21.336 0.084 ;
    END
  END b_d[211]
  PIN b_d[212]
    DIRECTION INPUT ;
    USE SIGNAL ;
    PORT
      LAYER M5 ;
        RECT  21.408 0 21.432 0.084 ;
    END
  END b_d[212]
  PIN b_d[213]
    DIRECTION INPUT ;
    USE SIGNAL ;
    PORT
      LAYER M5 ;
        RECT  21.504 0 21.528 0.084 ;
    END
  END b_d[213]
  PIN b_d[214]
    DIRECTION INPUT ;
    USE SIGNAL ;
    PORT
      LAYER M5 ;
        RECT  21.6 0 21.624 0.084 ;
    END
  END b_d[214]
  PIN b_d[215]
    DIRECTION INPUT ;
    USE SIGNAL ;
    PORT
      LAYER M5 ;
        RECT  21.696 0 21.72 0.084 ;
    END
  END b_d[215]
  PIN b_d[216]
    DIRECTION INPUT ;
    USE SIGNAL ;
    PORT
      LAYER M5 ;
        RECT  21.792 0 21.816 0.084 ;
    END
  END b_d[216]
  PIN b_d[217]
    DIRECTION INPUT ;
    USE SIGNAL ;
    PORT
      LAYER M5 ;
        RECT  21.888 0 21.912 0.084 ;
    END
  END b_d[217]
  PIN b_d[218]
    DIRECTION INPUT ;
    USE SIGNAL ;
    PORT
      LAYER M5 ;
        RECT  21.984 0 22.008 0.084 ;
    END
  END b_d[218]
  PIN b_d[219]
    DIRECTION INPUT ;
    USE SIGNAL ;
    PORT
      LAYER M5 ;
        RECT  22.08 0 22.104 0.084 ;
    END
  END b_d[219]
  PIN b_d[21]
    DIRECTION INPUT ;
    USE SIGNAL ;
    PORT
      LAYER M5 ;
        RECT  2.832 0 2.856 0.084 ;
    END
  END b_d[21]
  PIN b_d[220]
    DIRECTION INPUT ;
    USE SIGNAL ;
    PORT
      LAYER M5 ;
        RECT  22.176 0 22.2 0.084 ;
    END
  END b_d[220]
  PIN b_d[221]
    DIRECTION INPUT ;
    USE SIGNAL ;
    PORT
      LAYER M5 ;
        RECT  22.272 0 22.296 0.084 ;
    END
  END b_d[221]
  PIN b_d[222]
    DIRECTION INPUT ;
    USE SIGNAL ;
    PORT
      LAYER M5 ;
        RECT  22.368 0 22.392 0.084 ;
    END
  END b_d[222]
  PIN b_d[223]
    DIRECTION INPUT ;
    USE SIGNAL ;
    PORT
      LAYER M5 ;
        RECT  22.464 0 22.488 0.084 ;
    END
  END b_d[223]
  PIN b_d[224]
    DIRECTION INPUT ;
    USE SIGNAL ;
    PORT
      LAYER M5 ;
        RECT  22.56 0 22.584 0.084 ;
    END
  END b_d[224]
  PIN b_d[225]
    DIRECTION INPUT ;
    USE SIGNAL ;
    PORT
      LAYER M5 ;
        RECT  22.656 0 22.68 0.084 ;
    END
  END b_d[225]
  PIN b_d[226]
    DIRECTION INPUT ;
    USE SIGNAL ;
    PORT
      LAYER M5 ;
        RECT  22.752 0 22.776 0.084 ;
    END
  END b_d[226]
  PIN b_d[227]
    DIRECTION INPUT ;
    USE SIGNAL ;
    PORT
      LAYER M5 ;
        RECT  22.848 0 22.872 0.084 ;
    END
  END b_d[227]
  PIN b_d[228]
    DIRECTION INPUT ;
    USE SIGNAL ;
    PORT
      LAYER M5 ;
        RECT  22.944 0 22.968 0.084 ;
    END
  END b_d[228]
  PIN b_d[229]
    DIRECTION INPUT ;
    USE SIGNAL ;
    PORT
      LAYER M5 ;
        RECT  23.04 0 23.064 0.084 ;
    END
  END b_d[229]
  PIN b_d[22]
    DIRECTION INPUT ;
    USE SIGNAL ;
    PORT
      LAYER M5 ;
        RECT  2.928 0 2.952 0.084 ;
    END
  END b_d[22]
  PIN b_d[230]
    DIRECTION INPUT ;
    USE SIGNAL ;
    PORT
      LAYER M5 ;
        RECT  23.136 0 23.16 0.084 ;
    END
  END b_d[230]
  PIN b_d[231]
    DIRECTION INPUT ;
    USE SIGNAL ;
    PORT
      LAYER M5 ;
        RECT  23.232 0 23.256 0.084 ;
    END
  END b_d[231]
  PIN b_d[232]
    DIRECTION INPUT ;
    USE SIGNAL ;
    PORT
      LAYER M5 ;
        RECT  23.328 0 23.352 0.084 ;
    END
  END b_d[232]
  PIN b_d[233]
    DIRECTION INPUT ;
    USE SIGNAL ;
    PORT
      LAYER M5 ;
        RECT  23.424 0 23.448 0.084 ;
    END
  END b_d[233]
  PIN b_d[234]
    DIRECTION INPUT ;
    USE SIGNAL ;
    PORT
      LAYER M5 ;
        RECT  23.52 0 23.544 0.084 ;
    END
  END b_d[234]
  PIN b_d[235]
    DIRECTION INPUT ;
    USE SIGNAL ;
    PORT
      LAYER M5 ;
        RECT  23.616 0 23.64 0.084 ;
    END
  END b_d[235]
  PIN b_d[236]
    DIRECTION INPUT ;
    USE SIGNAL ;
    PORT
      LAYER M5 ;
        RECT  23.712 0 23.736 0.084 ;
    END
  END b_d[236]
  PIN b_d[237]
    DIRECTION INPUT ;
    USE SIGNAL ;
    PORT
      LAYER M5 ;
        RECT  23.808 0 23.832 0.084 ;
    END
  END b_d[237]
  PIN b_d[238]
    DIRECTION INPUT ;
    USE SIGNAL ;
    PORT
      LAYER M5 ;
        RECT  23.904 0 23.928 0.084 ;
    END
  END b_d[238]
  PIN b_d[239]
    DIRECTION INPUT ;
    USE SIGNAL ;
    PORT
      LAYER M5 ;
        RECT  24.048 0 24.072 0.084 ;
    END
  END b_d[239]
  PIN b_d[23]
    DIRECTION INPUT ;
    USE SIGNAL ;
    PORT
      LAYER M5 ;
        RECT  3.024 0 3.048 0.084 ;
    END
  END b_d[23]
  PIN b_d[240]
    DIRECTION INPUT ;
    USE SIGNAL ;
    PORT
      LAYER M5 ;
        RECT  24.144 0 24.168 0.084 ;
    END
  END b_d[240]
  PIN b_d[241]
    DIRECTION INPUT ;
    USE SIGNAL ;
    PORT
      LAYER M5 ;
        RECT  24.24 0 24.264 0.084 ;
    END
  END b_d[241]
  PIN b_d[242]
    DIRECTION INPUT ;
    USE SIGNAL ;
    PORT
      LAYER M5 ;
        RECT  24.336 0 24.36 0.084 ;
    END
  END b_d[242]
  PIN b_d[243]
    DIRECTION INPUT ;
    USE SIGNAL ;
    PORT
      LAYER M5 ;
        RECT  24.432 0 24.456 0.084 ;
    END
  END b_d[243]
  PIN b_d[244]
    DIRECTION INPUT ;
    USE SIGNAL ;
    PORT
      LAYER M5 ;
        RECT  24.528 0 24.552 0.084 ;
    END
  END b_d[244]
  PIN b_d[245]
    DIRECTION INPUT ;
    USE SIGNAL ;
    PORT
      LAYER M5 ;
        RECT  24.624 0 24.648 0.084 ;
    END
  END b_d[245]
  PIN b_d[246]
    DIRECTION INPUT ;
    USE SIGNAL ;
    PORT
      LAYER M5 ;
        RECT  24.72 0 24.744 0.084 ;
    END
  END b_d[246]
  PIN b_d[247]
    DIRECTION INPUT ;
    USE SIGNAL ;
    PORT
      LAYER M5 ;
        RECT  24.816 0 24.84 0.084 ;
    END
  END b_d[247]
  PIN b_d[248]
    DIRECTION INPUT ;
    USE SIGNAL ;
    PORT
      LAYER M5 ;
        RECT  24.912 0 24.936 0.084 ;
    END
  END b_d[248]
  PIN b_d[249]
    DIRECTION INPUT ;
    USE SIGNAL ;
    PORT
      LAYER M5 ;
        RECT  25.008 0 25.032 0.084 ;
    END
  END b_d[249]
  PIN b_d[24]
    DIRECTION INPUT ;
    USE SIGNAL ;
    PORT
      LAYER M5 ;
        RECT  3.12 0 3.144 0.084 ;
    END
  END b_d[24]
  PIN b_d[250]
    DIRECTION INPUT ;
    USE SIGNAL ;
    PORT
      LAYER M5 ;
        RECT  25.104 0 25.128 0.084 ;
    END
  END b_d[250]
  PIN b_d[251]
    DIRECTION INPUT ;
    USE SIGNAL ;
    PORT
      LAYER M5 ;
        RECT  25.2 0 25.224 0.084 ;
    END
  END b_d[251]
  PIN b_d[252]
    DIRECTION INPUT ;
    USE SIGNAL ;
    PORT
      LAYER M5 ;
        RECT  25.296 0 25.32 0.084 ;
    END
  END b_d[252]
  PIN b_d[253]
    DIRECTION INPUT ;
    USE SIGNAL ;
    PORT
      LAYER M5 ;
        RECT  25.392 0 25.416 0.084 ;
    END
  END b_d[253]
  PIN b_d[254]
    DIRECTION INPUT ;
    USE SIGNAL ;
    PORT
      LAYER M5 ;
        RECT  25.488 0 25.512 0.084 ;
    END
  END b_d[254]
  PIN b_d[255]
    DIRECTION INPUT ;
    USE SIGNAL ;
    PORT
      LAYER M5 ;
        RECT  25.584 0 25.608 0.084 ;
    END
  END b_d[255]
  PIN b_d[256]
    DIRECTION INPUT ;
    USE SIGNAL ;
    PORT
      LAYER M5 ;
        RECT  25.68 0 25.704 0.084 ;
    END
  END b_d[256]
  PIN b_d[257]
    DIRECTION INPUT ;
    USE SIGNAL ;
    PORT
      LAYER M5 ;
        RECT  25.776 0 25.8 0.084 ;
    END
  END b_d[257]
  PIN b_d[258]
    DIRECTION INPUT ;
    USE SIGNAL ;
    PORT
      LAYER M5 ;
        RECT  25.872 0 25.896 0.084 ;
    END
  END b_d[258]
  PIN b_d[259]
    DIRECTION INPUT ;
    USE SIGNAL ;
    PORT
      LAYER M5 ;
        RECT  25.968 0 25.992 0.084 ;
    END
  END b_d[259]
  PIN b_d[25]
    DIRECTION INPUT ;
    USE SIGNAL ;
    PORT
      LAYER M5 ;
        RECT  3.216 0 3.24 0.084 ;
    END
  END b_d[25]
  PIN b_d[260]
    DIRECTION INPUT ;
    USE SIGNAL ;
    PORT
      LAYER M5 ;
        RECT  26.064 0 26.088 0.084 ;
    END
  END b_d[260]
  PIN b_d[261]
    DIRECTION INPUT ;
    USE SIGNAL ;
    PORT
      LAYER M5 ;
        RECT  26.16 0 26.184 0.084 ;
    END
  END b_d[261]
  PIN b_d[262]
    DIRECTION INPUT ;
    USE SIGNAL ;
    PORT
      LAYER M5 ;
        RECT  26.256 0 26.28 0.084 ;
    END
  END b_d[262]
  PIN b_d[263]
    DIRECTION INPUT ;
    USE SIGNAL ;
    PORT
      LAYER M5 ;
        RECT  26.352 0 26.376 0.084 ;
    END
  END b_d[263]
  PIN b_d[264]
    DIRECTION INPUT ;
    USE SIGNAL ;
    PORT
      LAYER M5 ;
        RECT  26.448 0 26.472 0.084 ;
    END
  END b_d[264]
  PIN b_d[265]
    DIRECTION INPUT ;
    USE SIGNAL ;
    PORT
      LAYER M5 ;
        RECT  26.544 0 26.568 0.084 ;
    END
  END b_d[265]
  PIN b_d[266]
    DIRECTION INPUT ;
    USE SIGNAL ;
    PORT
      LAYER M5 ;
        RECT  26.64 0 26.664 0.084 ;
    END
  END b_d[266]
  PIN b_d[267]
    DIRECTION INPUT ;
    USE SIGNAL ;
    PORT
      LAYER M5 ;
        RECT  26.736 0 26.76 0.084 ;
    END
  END b_d[267]
  PIN b_d[268]
    DIRECTION INPUT ;
    USE SIGNAL ;
    PORT
      LAYER M5 ;
        RECT  26.832 0 26.856 0.084 ;
    END
  END b_d[268]
  PIN b_d[269]
    DIRECTION INPUT ;
    USE SIGNAL ;
    PORT
      LAYER M5 ;
        RECT  26.928 0 26.952 0.084 ;
    END
  END b_d[269]
  PIN b_d[26]
    DIRECTION INPUT ;
    USE SIGNAL ;
    PORT
      LAYER M5 ;
        RECT  3.312 0 3.336 0.084 ;
    END
  END b_d[26]
  PIN b_d[270]
    DIRECTION INPUT ;
    USE SIGNAL ;
    PORT
      LAYER M5 ;
        RECT  27.024 0 27.048 0.084 ;
    END
  END b_d[270]
  PIN b_d[271]
    DIRECTION INPUT ;
    USE SIGNAL ;
    PORT
      LAYER M5 ;
        RECT  27.12 0 27.144 0.084 ;
    END
  END b_d[271]
  PIN b_d[272]
    DIRECTION INPUT ;
    USE SIGNAL ;
    PORT
      LAYER M5 ;
        RECT  27.216 0 27.24 0.084 ;
    END
  END b_d[272]
  PIN b_d[273]
    DIRECTION INPUT ;
    USE SIGNAL ;
    PORT
      LAYER M5 ;
        RECT  27.312 0 27.336 0.084 ;
    END
  END b_d[273]
  PIN b_d[274]
    DIRECTION INPUT ;
    USE SIGNAL ;
    PORT
      LAYER M5 ;
        RECT  27.408 0 27.432 0.084 ;
    END
  END b_d[274]
  PIN b_d[275]
    DIRECTION INPUT ;
    USE SIGNAL ;
    PORT
      LAYER M5 ;
        RECT  27.504 0 27.528 0.084 ;
    END
  END b_d[275]
  PIN b_d[276]
    DIRECTION INPUT ;
    USE SIGNAL ;
    PORT
      LAYER M5 ;
        RECT  27.648 0 27.672 0.084 ;
    END
  END b_d[276]
  PIN b_d[277]
    DIRECTION INPUT ;
    USE SIGNAL ;
    PORT
      LAYER M5 ;
        RECT  27.744 0 27.768 0.084 ;
    END
  END b_d[277]
  PIN b_d[278]
    DIRECTION INPUT ;
    USE SIGNAL ;
    PORT
      LAYER M5 ;
        RECT  27.84 0 27.864 0.084 ;
    END
  END b_d[278]
  PIN b_d[279]
    DIRECTION INPUT ;
    USE SIGNAL ;
    PORT
      LAYER M5 ;
        RECT  27.936 0 27.96 0.084 ;
    END
  END b_d[279]
  PIN b_d[27]
    DIRECTION INPUT ;
    USE SIGNAL ;
    PORT
      LAYER M5 ;
        RECT  3.408 0 3.432 0.084 ;
    END
  END b_d[27]
  PIN b_d[280]
    DIRECTION INPUT ;
    USE SIGNAL ;
    PORT
      LAYER M5 ;
        RECT  28.032 0 28.056 0.084 ;
    END
  END b_d[280]
  PIN b_d[281]
    DIRECTION INPUT ;
    USE SIGNAL ;
    PORT
      LAYER M5 ;
        RECT  28.128 0 28.152 0.084 ;
    END
  END b_d[281]
  PIN b_d[282]
    DIRECTION INPUT ;
    USE SIGNAL ;
    PORT
      LAYER M5 ;
        RECT  28.224 0 28.248 0.084 ;
    END
  END b_d[282]
  PIN b_d[283]
    DIRECTION INPUT ;
    USE SIGNAL ;
    PORT
      LAYER M5 ;
        RECT  28.32 0 28.344 0.084 ;
    END
  END b_d[283]
  PIN b_d[284]
    DIRECTION INPUT ;
    USE SIGNAL ;
    PORT
      LAYER M5 ;
        RECT  28.416 0 28.44 0.084 ;
    END
  END b_d[284]
  PIN b_d[285]
    DIRECTION INPUT ;
    USE SIGNAL ;
    PORT
      LAYER M5 ;
        RECT  28.512 0 28.536 0.084 ;
    END
  END b_d[285]
  PIN b_d[286]
    DIRECTION INPUT ;
    USE SIGNAL ;
    PORT
      LAYER M5 ;
        RECT  28.608 0 28.632 0.084 ;
    END
  END b_d[286]
  PIN b_d[287]
    DIRECTION INPUT ;
    USE SIGNAL ;
    PORT
      LAYER M5 ;
        RECT  28.704 0 28.728 0.084 ;
    END
  END b_d[287]
  PIN b_d[288]
    DIRECTION INPUT ;
    USE SIGNAL ;
    PORT
      LAYER M5 ;
        RECT  28.8 0 28.824 0.084 ;
    END
  END b_d[288]
  PIN b_d[289]
    DIRECTION INPUT ;
    USE SIGNAL ;
    PORT
      LAYER M5 ;
        RECT  28.896 0 28.92 0.084 ;
    END
  END b_d[289]
  PIN b_d[28]
    DIRECTION INPUT ;
    USE SIGNAL ;
    PORT
      LAYER M5 ;
        RECT  3.504 0 3.528 0.084 ;
    END
  END b_d[28]
  PIN b_d[290]
    DIRECTION INPUT ;
    USE SIGNAL ;
    PORT
      LAYER M5 ;
        RECT  28.992 0 29.016 0.084 ;
    END
  END b_d[290]
  PIN b_d[291]
    DIRECTION INPUT ;
    USE SIGNAL ;
    PORT
      LAYER M5 ;
        RECT  29.088 0 29.112 0.084 ;
    END
  END b_d[291]
  PIN b_d[292]
    DIRECTION INPUT ;
    USE SIGNAL ;
    PORT
      LAYER M5 ;
        RECT  29.184 0 29.208 0.084 ;
    END
  END b_d[292]
  PIN b_d[293]
    DIRECTION INPUT ;
    USE SIGNAL ;
    PORT
      LAYER M5 ;
        RECT  29.28 0 29.304 0.084 ;
    END
  END b_d[293]
  PIN b_d[294]
    DIRECTION INPUT ;
    USE SIGNAL ;
    PORT
      LAYER M5 ;
        RECT  29.376 0 29.4 0.084 ;
    END
  END b_d[294]
  PIN b_d[295]
    DIRECTION INPUT ;
    USE SIGNAL ;
    PORT
      LAYER M5 ;
        RECT  29.472 0 29.496 0.084 ;
    END
  END b_d[295]
  PIN b_d[296]
    DIRECTION INPUT ;
    USE SIGNAL ;
    PORT
      LAYER M5 ;
        RECT  29.568 0 29.592 0.084 ;
    END
  END b_d[296]
  PIN b_d[297]
    DIRECTION INPUT ;
    USE SIGNAL ;
    PORT
      LAYER M5 ;
        RECT  29.664 0 29.688 0.084 ;
    END
  END b_d[297]
  PIN b_d[298]
    DIRECTION INPUT ;
    USE SIGNAL ;
    PORT
      LAYER M5 ;
        RECT  29.76 0 29.784 0.084 ;
    END
  END b_d[298]
  PIN b_d[299]
    DIRECTION INPUT ;
    USE SIGNAL ;
    PORT
      LAYER M5 ;
        RECT  29.856 0 29.88 0.084 ;
    END
  END b_d[299]
  PIN b_d[29]
    DIRECTION INPUT ;
    USE SIGNAL ;
    PORT
      LAYER M5 ;
        RECT  3.6 0 3.624 0.084 ;
    END
  END b_d[29]
  PIN b_d[2]
    DIRECTION INPUT ;
    USE SIGNAL ;
    PORT
      LAYER M5 ;
        RECT  0.96 0 0.984 0.084 ;
    END
  END b_d[2]
  PIN b_d[300]
    DIRECTION INPUT ;
    USE SIGNAL ;
    PORT
      LAYER M5 ;
        RECT  29.952 0 29.976 0.084 ;
    END
  END b_d[300]
  PIN b_d[301]
    DIRECTION INPUT ;
    USE SIGNAL ;
    PORT
      LAYER M5 ;
        RECT  30.048 0 30.072 0.084 ;
    END
  END b_d[301]
  PIN b_d[302]
    DIRECTION INPUT ;
    USE SIGNAL ;
    PORT
      LAYER M5 ;
        RECT  30.144 0 30.168 0.084 ;
    END
  END b_d[302]
  PIN b_d[303]
    DIRECTION INPUT ;
    USE SIGNAL ;
    PORT
      LAYER M5 ;
        RECT  30.24 0 30.264 0.084 ;
    END
  END b_d[303]
  PIN b_d[304]
    DIRECTION INPUT ;
    USE SIGNAL ;
    PORT
      LAYER M5 ;
        RECT  30.336 0 30.36 0.084 ;
    END
  END b_d[304]
  PIN b_d[305]
    DIRECTION INPUT ;
    USE SIGNAL ;
    PORT
      LAYER M5 ;
        RECT  30.432 0 30.456 0.084 ;
    END
  END b_d[305]
  PIN b_d[306]
    DIRECTION INPUT ;
    USE SIGNAL ;
    PORT
      LAYER M5 ;
        RECT  30.528 0 30.552 0.084 ;
    END
  END b_d[306]
  PIN b_d[307]
    DIRECTION INPUT ;
    USE SIGNAL ;
    PORT
      LAYER M5 ;
        RECT  30.624 0 30.648 0.084 ;
    END
  END b_d[307]
  PIN b_d[308]
    DIRECTION INPUT ;
    USE SIGNAL ;
    PORT
      LAYER M5 ;
        RECT  30.72 0 30.744 0.084 ;
    END
  END b_d[308]
  PIN b_d[309]
    DIRECTION INPUT ;
    USE SIGNAL ;
    PORT
      LAYER M5 ;
        RECT  30.816 0 30.84 0.084 ;
    END
  END b_d[309]
  PIN b_d[30]
    DIRECTION INPUT ;
    USE SIGNAL ;
    PORT
      LAYER M5 ;
        RECT  3.696 0 3.72 0.084 ;
    END
  END b_d[30]
  PIN b_d[310]
    DIRECTION INPUT ;
    USE SIGNAL ;
    PORT
      LAYER M5 ;
        RECT  30.912 0 30.936 0.084 ;
    END
  END b_d[310]
  PIN b_d[311]
    DIRECTION INPUT ;
    USE SIGNAL ;
    PORT
      LAYER M5 ;
        RECT  31.008 0 31.032 0.084 ;
    END
  END b_d[311]
  PIN b_d[312]
    DIRECTION INPUT ;
    USE SIGNAL ;
    PORT
      LAYER M5 ;
        RECT  31.104 0 31.128 0.084 ;
    END
  END b_d[312]
  PIN b_d[313]
    DIRECTION INPUT ;
    USE SIGNAL ;
    PORT
      LAYER M5 ;
        RECT  31.248 0 31.272 0.084 ;
    END
  END b_d[313]
  PIN b_d[314]
    DIRECTION INPUT ;
    USE SIGNAL ;
    PORT
      LAYER M5 ;
        RECT  31.344 0 31.368 0.084 ;
    END
  END b_d[314]
  PIN b_d[315]
    DIRECTION INPUT ;
    USE SIGNAL ;
    PORT
      LAYER M5 ;
        RECT  31.44 0 31.464 0.084 ;
    END
  END b_d[315]
  PIN b_d[316]
    DIRECTION INPUT ;
    USE SIGNAL ;
    PORT
      LAYER M5 ;
        RECT  31.536 0 31.56 0.084 ;
    END
  END b_d[316]
  PIN b_d[317]
    DIRECTION INPUT ;
    USE SIGNAL ;
    PORT
      LAYER M5 ;
        RECT  31.632 0 31.656 0.084 ;
    END
  END b_d[317]
  PIN b_d[318]
    DIRECTION INPUT ;
    USE SIGNAL ;
    PORT
      LAYER M5 ;
        RECT  31.728 0 31.752 0.084 ;
    END
  END b_d[318]
  PIN b_d[319]
    DIRECTION INPUT ;
    USE SIGNAL ;
    PORT
      LAYER M5 ;
        RECT  31.824 0 31.848 0.084 ;
    END
  END b_d[319]
  PIN b_d[31]
    DIRECTION INPUT ;
    USE SIGNAL ;
    PORT
      LAYER M5 ;
        RECT  3.792 0 3.816 0.084 ;
    END
  END b_d[31]
  PIN b_d[320]
    DIRECTION INPUT ;
    USE SIGNAL ;
    PORT
      LAYER M5 ;
        RECT  31.92 0 31.944 0.084 ;
    END
  END b_d[320]
  PIN b_d[321]
    DIRECTION INPUT ;
    USE SIGNAL ;
    PORT
      LAYER M5 ;
        RECT  32.016 0 32.04 0.084 ;
    END
  END b_d[321]
  PIN b_d[322]
    DIRECTION INPUT ;
    USE SIGNAL ;
    PORT
      LAYER M5 ;
        RECT  32.112 0 32.136 0.084 ;
    END
  END b_d[322]
  PIN b_d[323]
    DIRECTION INPUT ;
    USE SIGNAL ;
    PORT
      LAYER M5 ;
        RECT  32.208 0 32.232 0.084 ;
    END
  END b_d[323]
  PIN b_d[324]
    DIRECTION INPUT ;
    USE SIGNAL ;
    PORT
      LAYER M5 ;
        RECT  32.304 0 32.328 0.084 ;
    END
  END b_d[324]
  PIN b_d[325]
    DIRECTION INPUT ;
    USE SIGNAL ;
    PORT
      LAYER M5 ;
        RECT  32.4 0 32.424 0.084 ;
    END
  END b_d[325]
  PIN b_d[326]
    DIRECTION INPUT ;
    USE SIGNAL ;
    PORT
      LAYER M5 ;
        RECT  32.496 0 32.52 0.084 ;
    END
  END b_d[326]
  PIN b_d[327]
    DIRECTION INPUT ;
    USE SIGNAL ;
    PORT
      LAYER M5 ;
        RECT  32.592 0 32.616 0.084 ;
    END
  END b_d[327]
  PIN b_d[328]
    DIRECTION INPUT ;
    USE SIGNAL ;
    PORT
      LAYER M5 ;
        RECT  32.688 0 32.712 0.084 ;
    END
  END b_d[328]
  PIN b_d[329]
    DIRECTION INPUT ;
    USE SIGNAL ;
    PORT
      LAYER M5 ;
        RECT  32.784 0 32.808 0.084 ;
    END
  END b_d[329]
  PIN b_d[32]
    DIRECTION INPUT ;
    USE SIGNAL ;
    PORT
      LAYER M5 ;
        RECT  3.888 0 3.912 0.084 ;
    END
  END b_d[32]
  PIN b_d[330]
    DIRECTION INPUT ;
    USE SIGNAL ;
    PORT
      LAYER M5 ;
        RECT  32.88 0 32.904 0.084 ;
    END
  END b_d[330]
  PIN b_d[331]
    DIRECTION INPUT ;
    USE SIGNAL ;
    PORT
      LAYER M5 ;
        RECT  32.976 0 33 0.084 ;
    END
  END b_d[331]
  PIN b_d[332]
    DIRECTION INPUT ;
    USE SIGNAL ;
    PORT
      LAYER M5 ;
        RECT  33.072 0 33.096 0.084 ;
    END
  END b_d[332]
  PIN b_d[333]
    DIRECTION INPUT ;
    USE SIGNAL ;
    PORT
      LAYER M5 ;
        RECT  33.168 0 33.192 0.084 ;
    END
  END b_d[333]
  PIN b_d[334]
    DIRECTION INPUT ;
    USE SIGNAL ;
    PORT
      LAYER M5 ;
        RECT  33.264 0 33.288 0.084 ;
    END
  END b_d[334]
  PIN b_d[335]
    DIRECTION INPUT ;
    USE SIGNAL ;
    PORT
      LAYER M5 ;
        RECT  33.36 0 33.384 0.084 ;
    END
  END b_d[335]
  PIN b_d[336]
    DIRECTION INPUT ;
    USE SIGNAL ;
    PORT
      LAYER M5 ;
        RECT  33.456 0 33.48 0.084 ;
    END
  END b_d[336]
  PIN b_d[337]
    DIRECTION INPUT ;
    USE SIGNAL ;
    PORT
      LAYER M5 ;
        RECT  33.552 0 33.576 0.084 ;
    END
  END b_d[337]
  PIN b_d[338]
    DIRECTION INPUT ;
    USE SIGNAL ;
    PORT
      LAYER M5 ;
        RECT  33.648 0 33.672 0.084 ;
    END
  END b_d[338]
  PIN b_d[339]
    DIRECTION INPUT ;
    USE SIGNAL ;
    PORT
      LAYER M5 ;
        RECT  33.744 0 33.768 0.084 ;
    END
  END b_d[339]
  PIN b_d[33]
    DIRECTION INPUT ;
    USE SIGNAL ;
    PORT
      LAYER M5 ;
        RECT  3.984 0 4.008 0.084 ;
    END
  END b_d[33]
  PIN b_d[340]
    DIRECTION INPUT ;
    USE SIGNAL ;
    PORT
      LAYER M5 ;
        RECT  33.84 0 33.864 0.084 ;
    END
  END b_d[340]
  PIN b_d[341]
    DIRECTION INPUT ;
    USE SIGNAL ;
    PORT
      LAYER M5 ;
        RECT  33.936 0 33.96 0.084 ;
    END
  END b_d[341]
  PIN b_d[342]
    DIRECTION INPUT ;
    USE SIGNAL ;
    PORT
      LAYER M5 ;
        RECT  34.032 0 34.056 0.084 ;
    END
  END b_d[342]
  PIN b_d[343]
    DIRECTION INPUT ;
    USE SIGNAL ;
    PORT
      LAYER M5 ;
        RECT  34.128 0 34.152 0.084 ;
    END
  END b_d[343]
  PIN b_d[344]
    DIRECTION INPUT ;
    USE SIGNAL ;
    PORT
      LAYER M5 ;
        RECT  34.224 0 34.248 0.084 ;
    END
  END b_d[344]
  PIN b_d[345]
    DIRECTION INPUT ;
    USE SIGNAL ;
    PORT
      LAYER M5 ;
        RECT  34.32 0 34.344 0.084 ;
    END
  END b_d[345]
  PIN b_d[346]
    DIRECTION INPUT ;
    USE SIGNAL ;
    PORT
      LAYER M5 ;
        RECT  34.416 0 34.44 0.084 ;
    END
  END b_d[346]
  PIN b_d[347]
    DIRECTION INPUT ;
    USE SIGNAL ;
    PORT
      LAYER M5 ;
        RECT  34.512 0 34.536 0.084 ;
    END
  END b_d[347]
  PIN b_d[348]
    DIRECTION INPUT ;
    USE SIGNAL ;
    PORT
      LAYER M5 ;
        RECT  34.608 0 34.632 0.084 ;
    END
  END b_d[348]
  PIN b_d[349]
    DIRECTION INPUT ;
    USE SIGNAL ;
    PORT
      LAYER M5 ;
        RECT  34.704 0 34.728 0.084 ;
    END
  END b_d[349]
  PIN b_d[34]
    DIRECTION INPUT ;
    USE SIGNAL ;
    PORT
      LAYER M5 ;
        RECT  4.08 0 4.104 0.084 ;
    END
  END b_d[34]
  PIN b_d[350]
    DIRECTION INPUT ;
    USE SIGNAL ;
    PORT
      LAYER M5 ;
        RECT  34.848 0 34.872 0.084 ;
    END
  END b_d[350]
  PIN b_d[351]
    DIRECTION INPUT ;
    USE SIGNAL ;
    PORT
      LAYER M5 ;
        RECT  34.944 0 34.968 0.084 ;
    END
  END b_d[351]
  PIN b_d[352]
    DIRECTION INPUT ;
    USE SIGNAL ;
    PORT
      LAYER M5 ;
        RECT  35.04 0 35.064 0.084 ;
    END
  END b_d[352]
  PIN b_d[353]
    DIRECTION INPUT ;
    USE SIGNAL ;
    PORT
      LAYER M5 ;
        RECT  35.136 0 35.16 0.084 ;
    END
  END b_d[353]
  PIN b_d[354]
    DIRECTION INPUT ;
    USE SIGNAL ;
    PORT
      LAYER M5 ;
        RECT  35.232 0 35.256 0.084 ;
    END
  END b_d[354]
  PIN b_d[355]
    DIRECTION INPUT ;
    USE SIGNAL ;
    PORT
      LAYER M5 ;
        RECT  35.328 0 35.352 0.084 ;
    END
  END b_d[355]
  PIN b_d[356]
    DIRECTION INPUT ;
    USE SIGNAL ;
    PORT
      LAYER M5 ;
        RECT  35.424 0 35.448 0.084 ;
    END
  END b_d[356]
  PIN b_d[357]
    DIRECTION INPUT ;
    USE SIGNAL ;
    PORT
      LAYER M5 ;
        RECT  35.52 0 35.544 0.084 ;
    END
  END b_d[357]
  PIN b_d[358]
    DIRECTION INPUT ;
    USE SIGNAL ;
    PORT
      LAYER M5 ;
        RECT  35.616 0 35.64 0.084 ;
    END
  END b_d[358]
  PIN b_d[359]
    DIRECTION INPUT ;
    USE SIGNAL ;
    PORT
      LAYER M5 ;
        RECT  35.712 0 35.736 0.084 ;
    END
  END b_d[359]
  PIN b_d[35]
    DIRECTION INPUT ;
    USE SIGNAL ;
    PORT
      LAYER M5 ;
        RECT  4.176 0 4.2 0.084 ;
    END
  END b_d[35]
  PIN b_d[360]
    DIRECTION INPUT ;
    USE SIGNAL ;
    PORT
      LAYER M5 ;
        RECT  35.808 0 35.832 0.084 ;
    END
  END b_d[360]
  PIN b_d[361]
    DIRECTION INPUT ;
    USE SIGNAL ;
    PORT
      LAYER M5 ;
        RECT  35.904 0 35.928 0.084 ;
    END
  END b_d[361]
  PIN b_d[362]
    DIRECTION INPUT ;
    USE SIGNAL ;
    PORT
      LAYER M5 ;
        RECT  36 0 36.024 0.084 ;
    END
  END b_d[362]
  PIN b_d[363]
    DIRECTION INPUT ;
    USE SIGNAL ;
    PORT
      LAYER M5 ;
        RECT  36.096 0 36.12 0.084 ;
    END
  END b_d[363]
  PIN b_d[364]
    DIRECTION INPUT ;
    USE SIGNAL ;
    PORT
      LAYER M5 ;
        RECT  36.192 0 36.216 0.084 ;
    END
  END b_d[364]
  PIN b_d[365]
    DIRECTION INPUT ;
    USE SIGNAL ;
    PORT
      LAYER M5 ;
        RECT  36.288 0 36.312 0.084 ;
    END
  END b_d[365]
  PIN b_d[366]
    DIRECTION INPUT ;
    USE SIGNAL ;
    PORT
      LAYER M5 ;
        RECT  36.384 0 36.408 0.084 ;
    END
  END b_d[366]
  PIN b_d[367]
    DIRECTION INPUT ;
    USE SIGNAL ;
    PORT
      LAYER M5 ;
        RECT  36.48 0 36.504 0.084 ;
    END
  END b_d[367]
  PIN b_d[368]
    DIRECTION INPUT ;
    USE SIGNAL ;
    PORT
      LAYER M5 ;
        RECT  36.576 0 36.6 0.084 ;
    END
  END b_d[368]
  PIN b_d[369]
    DIRECTION INPUT ;
    USE SIGNAL ;
    PORT
      LAYER M5 ;
        RECT  36.672 0 36.696 0.084 ;
    END
  END b_d[369]
  PIN b_d[36]
    DIRECTION INPUT ;
    USE SIGNAL ;
    PORT
      LAYER M5 ;
        RECT  4.272 0 4.296 0.084 ;
    END
  END b_d[36]
  PIN b_d[370]
    DIRECTION INPUT ;
    USE SIGNAL ;
    PORT
      LAYER M5 ;
        RECT  36.768 0 36.792 0.084 ;
    END
  END b_d[370]
  PIN b_d[371]
    DIRECTION INPUT ;
    USE SIGNAL ;
    PORT
      LAYER M5 ;
        RECT  36.864 0 36.888 0.084 ;
    END
  END b_d[371]
  PIN b_d[372]
    DIRECTION INPUT ;
    USE SIGNAL ;
    PORT
      LAYER M5 ;
        RECT  36.96 0 36.984 0.084 ;
    END
  END b_d[372]
  PIN b_d[373]
    DIRECTION INPUT ;
    USE SIGNAL ;
    PORT
      LAYER M5 ;
        RECT  37.056 0 37.08 0.084 ;
    END
  END b_d[373]
  PIN b_d[374]
    DIRECTION INPUT ;
    USE SIGNAL ;
    PORT
      LAYER M5 ;
        RECT  37.152 0 37.176 0.084 ;
    END
  END b_d[374]
  PIN b_d[375]
    DIRECTION INPUT ;
    USE SIGNAL ;
    PORT
      LAYER M5 ;
        RECT  37.248 0 37.272 0.084 ;
    END
  END b_d[375]
  PIN b_d[376]
    DIRECTION INPUT ;
    USE SIGNAL ;
    PORT
      LAYER M5 ;
        RECT  37.344 0 37.368 0.084 ;
    END
  END b_d[376]
  PIN b_d[377]
    DIRECTION INPUT ;
    USE SIGNAL ;
    PORT
      LAYER M5 ;
        RECT  37.44 0 37.464 0.084 ;
    END
  END b_d[377]
  PIN b_d[378]
    DIRECTION INPUT ;
    USE SIGNAL ;
    PORT
      LAYER M5 ;
        RECT  37.536 0 37.56 0.084 ;
    END
  END b_d[378]
  PIN b_d[379]
    DIRECTION INPUT ;
    USE SIGNAL ;
    PORT
      LAYER M5 ;
        RECT  37.632 0 37.656 0.084 ;
    END
  END b_d[379]
  PIN b_d[37]
    DIRECTION INPUT ;
    USE SIGNAL ;
    PORT
      LAYER M5 ;
        RECT  4.368 0 4.392 0.084 ;
    END
  END b_d[37]
  PIN b_d[380]
    DIRECTION INPUT ;
    USE SIGNAL ;
    PORT
      LAYER M5 ;
        RECT  37.728 0 37.752 0.084 ;
    END
  END b_d[380]
  PIN b_d[381]
    DIRECTION INPUT ;
    USE SIGNAL ;
    PORT
      LAYER M5 ;
        RECT  37.824 0 37.848 0.084 ;
    END
  END b_d[381]
  PIN b_d[382]
    DIRECTION INPUT ;
    USE SIGNAL ;
    PORT
      LAYER M5 ;
        RECT  37.92 0 37.944 0.084 ;
    END
  END b_d[382]
  PIN b_d[383]
    DIRECTION INPUT ;
    USE SIGNAL ;
    PORT
      LAYER M5 ;
        RECT  38.016 0 38.04 0.084 ;
    END
  END b_d[383]
  PIN b_d[384]
    DIRECTION INPUT ;
    USE SIGNAL ;
    PORT
      LAYER M5 ;
        RECT  38.112 0 38.136 0.084 ;
    END
  END b_d[384]
  PIN b_d[385]
    DIRECTION INPUT ;
    USE SIGNAL ;
    PORT
      LAYER M5 ;
        RECT  38.208 0 38.232 0.084 ;
    END
  END b_d[385]
  PIN b_d[386]
    DIRECTION INPUT ;
    USE SIGNAL ;
    PORT
      LAYER M5 ;
        RECT  38.304 0 38.328 0.084 ;
    END
  END b_d[386]
  PIN b_d[387]
    DIRECTION INPUT ;
    USE SIGNAL ;
    PORT
      LAYER M5 ;
        RECT  38.448 0 38.472 0.084 ;
    END
  END b_d[387]
  PIN b_d[388]
    DIRECTION INPUT ;
    USE SIGNAL ;
    PORT
      LAYER M5 ;
        RECT  38.544 0 38.568 0.084 ;
    END
  END b_d[388]
  PIN b_d[389]
    DIRECTION INPUT ;
    USE SIGNAL ;
    PORT
      LAYER M5 ;
        RECT  38.64 0 38.664 0.084 ;
    END
  END b_d[389]
  PIN b_d[38]
    DIRECTION INPUT ;
    USE SIGNAL ;
    PORT
      LAYER M5 ;
        RECT  4.464 0 4.488 0.084 ;
    END
  END b_d[38]
  PIN b_d[390]
    DIRECTION INPUT ;
    USE SIGNAL ;
    PORT
      LAYER M5 ;
        RECT  38.736 0 38.76 0.084 ;
    END
  END b_d[390]
  PIN b_d[391]
    DIRECTION INPUT ;
    USE SIGNAL ;
    PORT
      LAYER M5 ;
        RECT  38.832 0 38.856 0.084 ;
    END
  END b_d[391]
  PIN b_d[392]
    DIRECTION INPUT ;
    USE SIGNAL ;
    PORT
      LAYER M5 ;
        RECT  38.928 0 38.952 0.084 ;
    END
  END b_d[392]
  PIN b_d[393]
    DIRECTION INPUT ;
    USE SIGNAL ;
    PORT
      LAYER M5 ;
        RECT  39.024 0 39.048 0.084 ;
    END
  END b_d[393]
  PIN b_d[394]
    DIRECTION INPUT ;
    USE SIGNAL ;
    PORT
      LAYER M5 ;
        RECT  39.12 0 39.144 0.084 ;
    END
  END b_d[394]
  PIN b_d[395]
    DIRECTION INPUT ;
    USE SIGNAL ;
    PORT
      LAYER M5 ;
        RECT  39.216 0 39.24 0.084 ;
    END
  END b_d[395]
  PIN b_d[396]
    DIRECTION INPUT ;
    USE SIGNAL ;
    PORT
      LAYER M5 ;
        RECT  39.312 0 39.336 0.084 ;
    END
  END b_d[396]
  PIN b_d[397]
    DIRECTION INPUT ;
    USE SIGNAL ;
    PORT
      LAYER M5 ;
        RECT  39.408 0 39.432 0.084 ;
    END
  END b_d[397]
  PIN b_d[398]
    DIRECTION INPUT ;
    USE SIGNAL ;
    PORT
      LAYER M5 ;
        RECT  39.504 0 39.528 0.084 ;
    END
  END b_d[398]
  PIN b_d[399]
    DIRECTION INPUT ;
    USE SIGNAL ;
    PORT
      LAYER M5 ;
        RECT  39.6 0 39.624 0.084 ;
    END
  END b_d[399]
  PIN b_d[39]
    DIRECTION INPUT ;
    USE SIGNAL ;
    PORT
      LAYER M5 ;
        RECT  4.56 0 4.584 0.084 ;
    END
  END b_d[39]
  PIN b_d[3]
    DIRECTION INPUT ;
    USE SIGNAL ;
    PORT
      LAYER M5 ;
        RECT  1.056 0 1.08 0.084 ;
    END
  END b_d[3]
  PIN b_d[400]
    DIRECTION INPUT ;
    USE SIGNAL ;
    PORT
      LAYER M5 ;
        RECT  39.696 0 39.72 0.084 ;
    END
  END b_d[400]
  PIN b_d[401]
    DIRECTION INPUT ;
    USE SIGNAL ;
    PORT
      LAYER M5 ;
        RECT  39.792 0 39.816 0.084 ;
    END
  END b_d[401]
  PIN b_d[402]
    DIRECTION INPUT ;
    USE SIGNAL ;
    PORT
      LAYER M5 ;
        RECT  39.888 0 39.912 0.084 ;
    END
  END b_d[402]
  PIN b_d[403]
    DIRECTION INPUT ;
    USE SIGNAL ;
    PORT
      LAYER M5 ;
        RECT  39.984 0 40.008 0.084 ;
    END
  END b_d[403]
  PIN b_d[404]
    DIRECTION INPUT ;
    USE SIGNAL ;
    PORT
      LAYER M5 ;
        RECT  40.08 0 40.104 0.084 ;
    END
  END b_d[404]
  PIN b_d[405]
    DIRECTION INPUT ;
    USE SIGNAL ;
    PORT
      LAYER M5 ;
        RECT  40.176 0 40.2 0.084 ;
    END
  END b_d[405]
  PIN b_d[406]
    DIRECTION INPUT ;
    USE SIGNAL ;
    PORT
      LAYER M5 ;
        RECT  40.272 0 40.296 0.084 ;
    END
  END b_d[406]
  PIN b_d[407]
    DIRECTION INPUT ;
    USE SIGNAL ;
    PORT
      LAYER M5 ;
        RECT  40.368 0 40.392 0.084 ;
    END
  END b_d[407]
  PIN b_d[408]
    DIRECTION INPUT ;
    USE SIGNAL ;
    PORT
      LAYER M5 ;
        RECT  40.464 0 40.488 0.084 ;
    END
  END b_d[408]
  PIN b_d[409]
    DIRECTION INPUT ;
    USE SIGNAL ;
    PORT
      LAYER M5 ;
        RECT  40.56 0 40.584 0.084 ;
    END
  END b_d[409]
  PIN b_d[40]
    DIRECTION INPUT ;
    USE SIGNAL ;
    PORT
      LAYER M5 ;
        RECT  4.656 0 4.68 0.084 ;
    END
  END b_d[40]
  PIN b_d[410]
    DIRECTION INPUT ;
    USE SIGNAL ;
    PORT
      LAYER M5 ;
        RECT  40.656 0 40.68 0.084 ;
    END
  END b_d[410]
  PIN b_d[411]
    DIRECTION INPUT ;
    USE SIGNAL ;
    PORT
      LAYER M5 ;
        RECT  40.752 0 40.776 0.084 ;
    END
  END b_d[411]
  PIN b_d[412]
    DIRECTION INPUT ;
    USE SIGNAL ;
    PORT
      LAYER M5 ;
        RECT  40.848 0 40.872 0.084 ;
    END
  END b_d[412]
  PIN b_d[413]
    DIRECTION INPUT ;
    USE SIGNAL ;
    PORT
      LAYER M5 ;
        RECT  40.944 0 40.968 0.084 ;
    END
  END b_d[413]
  PIN b_d[414]
    DIRECTION INPUT ;
    USE SIGNAL ;
    PORT
      LAYER M5 ;
        RECT  41.04 0 41.064 0.084 ;
    END
  END b_d[414]
  PIN b_d[415]
    DIRECTION INPUT ;
    USE SIGNAL ;
    PORT
      LAYER M5 ;
        RECT  41.136 0 41.16 0.084 ;
    END
  END b_d[415]
  PIN b_d[416]
    DIRECTION INPUT ;
    USE SIGNAL ;
    PORT
      LAYER M5 ;
        RECT  41.232 0 41.256 0.084 ;
    END
  END b_d[416]
  PIN b_d[417]
    DIRECTION INPUT ;
    USE SIGNAL ;
    PORT
      LAYER M5 ;
        RECT  41.328 0 41.352 0.084 ;
    END
  END b_d[417]
  PIN b_d[418]
    DIRECTION INPUT ;
    USE SIGNAL ;
    PORT
      LAYER M5 ;
        RECT  41.424 0 41.448 0.084 ;
    END
  END b_d[418]
  PIN b_d[419]
    DIRECTION INPUT ;
    USE SIGNAL ;
    PORT
      LAYER M5 ;
        RECT  41.52 0 41.544 0.084 ;
    END
  END b_d[419]
  PIN b_d[41]
    DIRECTION INPUT ;
    USE SIGNAL ;
    PORT
      LAYER M5 ;
        RECT  4.752 0 4.776 0.084 ;
    END
  END b_d[41]
  PIN b_d[420]
    DIRECTION INPUT ;
    USE SIGNAL ;
    PORT
      LAYER M5 ;
        RECT  41.616 0 41.64 0.084 ;
    END
  END b_d[420]
  PIN b_d[421]
    DIRECTION INPUT ;
    USE SIGNAL ;
    PORT
      LAYER M5 ;
        RECT  41.712 0 41.736 0.084 ;
    END
  END b_d[421]
  PIN b_d[422]
    DIRECTION INPUT ;
    USE SIGNAL ;
    PORT
      LAYER M5 ;
        RECT  41.808 0 41.832 0.084 ;
    END
  END b_d[422]
  PIN b_d[423]
    DIRECTION INPUT ;
    USE SIGNAL ;
    PORT
      LAYER M5 ;
        RECT  41.952 0 41.976 0.084 ;
    END
  END b_d[423]
  PIN b_d[424]
    DIRECTION INPUT ;
    USE SIGNAL ;
    PORT
      LAYER M5 ;
        RECT  42.048 0 42.072 0.084 ;
    END
  END b_d[424]
  PIN b_d[425]
    DIRECTION INPUT ;
    USE SIGNAL ;
    PORT
      LAYER M5 ;
        RECT  42.144 0 42.168 0.084 ;
    END
  END b_d[425]
  PIN b_d[426]
    DIRECTION INPUT ;
    USE SIGNAL ;
    PORT
      LAYER M5 ;
        RECT  42.24 0 42.264 0.084 ;
    END
  END b_d[426]
  PIN b_d[427]
    DIRECTION INPUT ;
    USE SIGNAL ;
    PORT
      LAYER M5 ;
        RECT  42.336 0 42.36 0.084 ;
    END
  END b_d[427]
  PIN b_d[428]
    DIRECTION INPUT ;
    USE SIGNAL ;
    PORT
      LAYER M5 ;
        RECT  42.432 0 42.456 0.084 ;
    END
  END b_d[428]
  PIN b_d[429]
    DIRECTION INPUT ;
    USE SIGNAL ;
    PORT
      LAYER M5 ;
        RECT  42.528 0 42.552 0.084 ;
    END
  END b_d[429]
  PIN b_d[42]
    DIRECTION INPUT ;
    USE SIGNAL ;
    PORT
      LAYER M5 ;
        RECT  4.848 0 4.872 0.084 ;
    END
  END b_d[42]
  PIN b_d[430]
    DIRECTION INPUT ;
    USE SIGNAL ;
    PORT
      LAYER M5 ;
        RECT  42.624 0 42.648 0.084 ;
    END
  END b_d[430]
  PIN b_d[431]
    DIRECTION INPUT ;
    USE SIGNAL ;
    PORT
      LAYER M5 ;
        RECT  42.72 0 42.744 0.084 ;
    END
  END b_d[431]
  PIN b_d[432]
    DIRECTION INPUT ;
    USE SIGNAL ;
    PORT
      LAYER M5 ;
        RECT  42.816 0 42.84 0.084 ;
    END
  END b_d[432]
  PIN b_d[433]
    DIRECTION INPUT ;
    USE SIGNAL ;
    PORT
      LAYER M5 ;
        RECT  42.912 0 42.936 0.084 ;
    END
  END b_d[433]
  PIN b_d[434]
    DIRECTION INPUT ;
    USE SIGNAL ;
    PORT
      LAYER M5 ;
        RECT  43.008 0 43.032 0.084 ;
    END
  END b_d[434]
  PIN b_d[435]
    DIRECTION INPUT ;
    USE SIGNAL ;
    PORT
      LAYER M5 ;
        RECT  43.104 0 43.128 0.084 ;
    END
  END b_d[435]
  PIN b_d[436]
    DIRECTION INPUT ;
    USE SIGNAL ;
    PORT
      LAYER M5 ;
        RECT  43.2 0 43.224 0.084 ;
    END
  END b_d[436]
  PIN b_d[437]
    DIRECTION INPUT ;
    USE SIGNAL ;
    PORT
      LAYER M5 ;
        RECT  43.296 0 43.32 0.084 ;
    END
  END b_d[437]
  PIN b_d[438]
    DIRECTION INPUT ;
    USE SIGNAL ;
    PORT
      LAYER M5 ;
        RECT  43.392 0 43.416 0.084 ;
    END
  END b_d[438]
  PIN b_d[439]
    DIRECTION INPUT ;
    USE SIGNAL ;
    PORT
      LAYER M5 ;
        RECT  43.488 0 43.512 0.084 ;
    END
  END b_d[439]
  PIN b_d[43]
    DIRECTION INPUT ;
    USE SIGNAL ;
    PORT
      LAYER M5 ;
        RECT  4.944 0 4.968 0.084 ;
    END
  END b_d[43]
  PIN b_d[440]
    DIRECTION INPUT ;
    USE SIGNAL ;
    PORT
      LAYER M5 ;
        RECT  43.584 0 43.608 0.084 ;
    END
  END b_d[440]
  PIN b_d[441]
    DIRECTION INPUT ;
    USE SIGNAL ;
    PORT
      LAYER M5 ;
        RECT  43.68 0 43.704 0.084 ;
    END
  END b_d[441]
  PIN b_d[442]
    DIRECTION INPUT ;
    USE SIGNAL ;
    PORT
      LAYER M5 ;
        RECT  43.776 0 43.8 0.084 ;
    END
  END b_d[442]
  PIN b_d[443]
    DIRECTION INPUT ;
    USE SIGNAL ;
    PORT
      LAYER M5 ;
        RECT  43.872 0 43.896 0.084 ;
    END
  END b_d[443]
  PIN b_d[444]
    DIRECTION INPUT ;
    USE SIGNAL ;
    PORT
      LAYER M5 ;
        RECT  43.968 0 43.992 0.084 ;
    END
  END b_d[444]
  PIN b_d[445]
    DIRECTION INPUT ;
    USE SIGNAL ;
    PORT
      LAYER M5 ;
        RECT  44.064 0 44.088 0.084 ;
    END
  END b_d[445]
  PIN b_d[446]
    DIRECTION INPUT ;
    USE SIGNAL ;
    PORT
      LAYER M5 ;
        RECT  44.16 0 44.184 0.084 ;
    END
  END b_d[446]
  PIN b_d[447]
    DIRECTION INPUT ;
    USE SIGNAL ;
    PORT
      LAYER M5 ;
        RECT  44.256 0 44.28 0.084 ;
    END
  END b_d[447]
  PIN b_d[448]
    DIRECTION INPUT ;
    USE SIGNAL ;
    PORT
      LAYER M5 ;
        RECT  44.352 0 44.376 0.084 ;
    END
  END b_d[448]
  PIN b_d[449]
    DIRECTION INPUT ;
    USE SIGNAL ;
    PORT
      LAYER M5 ;
        RECT  44.448 0 44.472 0.084 ;
    END
  END b_d[449]
  PIN b_d[44]
    DIRECTION INPUT ;
    USE SIGNAL ;
    PORT
      LAYER M5 ;
        RECT  5.04 0 5.064 0.084 ;
    END
  END b_d[44]
  PIN b_d[450]
    DIRECTION INPUT ;
    USE SIGNAL ;
    PORT
      LAYER M5 ;
        RECT  44.544 0 44.568 0.084 ;
    END
  END b_d[450]
  PIN b_d[451]
    DIRECTION INPUT ;
    USE SIGNAL ;
    PORT
      LAYER M5 ;
        RECT  44.64 0 44.664 0.084 ;
    END
  END b_d[451]
  PIN b_d[452]
    DIRECTION INPUT ;
    USE SIGNAL ;
    PORT
      LAYER M5 ;
        RECT  44.736 0 44.76 0.084 ;
    END
  END b_d[452]
  PIN b_d[453]
    DIRECTION INPUT ;
    USE SIGNAL ;
    PORT
      LAYER M5 ;
        RECT  44.832 0 44.856 0.084 ;
    END
  END b_d[453]
  PIN b_d[454]
    DIRECTION INPUT ;
    USE SIGNAL ;
    PORT
      LAYER M5 ;
        RECT  44.928 0 44.952 0.084 ;
    END
  END b_d[454]
  PIN b_d[455]
    DIRECTION INPUT ;
    USE SIGNAL ;
    PORT
      LAYER M5 ;
        RECT  45.024 0 45.048 0.084 ;
    END
  END b_d[455]
  PIN b_d[456]
    DIRECTION INPUT ;
    USE SIGNAL ;
    PORT
      LAYER M5 ;
        RECT  45.12 0 45.144 0.084 ;
    END
  END b_d[456]
  PIN b_d[457]
    DIRECTION INPUT ;
    USE SIGNAL ;
    PORT
      LAYER M5 ;
        RECT  45.216 0 45.24 0.084 ;
    END
  END b_d[457]
  PIN b_d[458]
    DIRECTION INPUT ;
    USE SIGNAL ;
    PORT
      LAYER M5 ;
        RECT  45.312 0 45.336 0.084 ;
    END
  END b_d[458]
  PIN b_d[459]
    DIRECTION INPUT ;
    USE SIGNAL ;
    PORT
      LAYER M5 ;
        RECT  45.408 0 45.432 0.084 ;
    END
  END b_d[459]
  PIN b_d[45]
    DIRECTION INPUT ;
    USE SIGNAL ;
    PORT
      LAYER M5 ;
        RECT  5.136 0 5.16 0.084 ;
    END
  END b_d[45]
  PIN b_d[460]
    DIRECTION INPUT ;
    USE SIGNAL ;
    PORT
      LAYER M5 ;
        RECT  45.552 0 45.576 0.084 ;
    END
  END b_d[460]
  PIN b_d[461]
    DIRECTION INPUT ;
    USE SIGNAL ;
    PORT
      LAYER M5 ;
        RECT  45.648 0 45.672 0.084 ;
    END
  END b_d[461]
  PIN b_d[462]
    DIRECTION INPUT ;
    USE SIGNAL ;
    PORT
      LAYER M5 ;
        RECT  45.744 0 45.768 0.084 ;
    END
  END b_d[462]
  PIN b_d[463]
    DIRECTION INPUT ;
    USE SIGNAL ;
    PORT
      LAYER M5 ;
        RECT  45.84 0 45.864 0.084 ;
    END
  END b_d[463]
  PIN b_d[464]
    DIRECTION INPUT ;
    USE SIGNAL ;
    PORT
      LAYER M5 ;
        RECT  45.936 0 45.96 0.084 ;
    END
  END b_d[464]
  PIN b_d[465]
    DIRECTION INPUT ;
    USE SIGNAL ;
    PORT
      LAYER M5 ;
        RECT  46.032 0 46.056 0.084 ;
    END
  END b_d[465]
  PIN b_d[466]
    DIRECTION INPUT ;
    USE SIGNAL ;
    PORT
      LAYER M5 ;
        RECT  46.128 0 46.152 0.084 ;
    END
  END b_d[466]
  PIN b_d[467]
    DIRECTION INPUT ;
    USE SIGNAL ;
    PORT
      LAYER M5 ;
        RECT  46.224 0 46.248 0.084 ;
    END
  END b_d[467]
  PIN b_d[468]
    DIRECTION INPUT ;
    USE SIGNAL ;
    PORT
      LAYER M5 ;
        RECT  46.32 0 46.344 0.084 ;
    END
  END b_d[468]
  PIN b_d[469]
    DIRECTION INPUT ;
    USE SIGNAL ;
    PORT
      LAYER M5 ;
        RECT  46.416 0 46.44 0.084 ;
    END
  END b_d[469]
  PIN b_d[46]
    DIRECTION INPUT ;
    USE SIGNAL ;
    PORT
      LAYER M5 ;
        RECT  5.232 0 5.256 0.084 ;
    END
  END b_d[46]
  PIN b_d[470]
    DIRECTION INPUT ;
    USE SIGNAL ;
    PORT
      LAYER M5 ;
        RECT  46.512 0 46.536 0.084 ;
    END
  END b_d[470]
  PIN b_d[471]
    DIRECTION INPUT ;
    USE SIGNAL ;
    PORT
      LAYER M5 ;
        RECT  46.608 0 46.632 0.084 ;
    END
  END b_d[471]
  PIN b_d[472]
    DIRECTION INPUT ;
    USE SIGNAL ;
    PORT
      LAYER M5 ;
        RECT  46.704 0 46.728 0.084 ;
    END
  END b_d[472]
  PIN b_d[473]
    DIRECTION INPUT ;
    USE SIGNAL ;
    PORT
      LAYER M5 ;
        RECT  46.8 0 46.824 0.084 ;
    END
  END b_d[473]
  PIN b_d[474]
    DIRECTION INPUT ;
    USE SIGNAL ;
    PORT
      LAYER M5 ;
        RECT  46.896 0 46.92 0.084 ;
    END
  END b_d[474]
  PIN b_d[475]
    DIRECTION INPUT ;
    USE SIGNAL ;
    PORT
      LAYER M5 ;
        RECT  46.992 0 47.016 0.084 ;
    END
  END b_d[475]
  PIN b_d[476]
    DIRECTION INPUT ;
    USE SIGNAL ;
    PORT
      LAYER M5 ;
        RECT  47.088 0 47.112 0.084 ;
    END
  END b_d[476]
  PIN b_d[477]
    DIRECTION INPUT ;
    USE SIGNAL ;
    PORT
      LAYER M5 ;
        RECT  47.184 0 47.208 0.084 ;
    END
  END b_d[477]
  PIN b_d[478]
    DIRECTION INPUT ;
    USE SIGNAL ;
    PORT
      LAYER M5 ;
        RECT  47.28 0 47.304 0.084 ;
    END
  END b_d[478]
  PIN b_d[479]
    DIRECTION INPUT ;
    USE SIGNAL ;
    PORT
      LAYER M5 ;
        RECT  47.376 0 47.4 0.084 ;
    END
  END b_d[479]
  PIN b_d[47]
    DIRECTION INPUT ;
    USE SIGNAL ;
    PORT
      LAYER M5 ;
        RECT  5.328 0 5.352 0.084 ;
    END
  END b_d[47]
  PIN b_d[480]
    DIRECTION INPUT ;
    USE SIGNAL ;
    PORT
      LAYER M5 ;
        RECT  47.472 0 47.496 0.084 ;
    END
  END b_d[480]
  PIN b_d[481]
    DIRECTION INPUT ;
    USE SIGNAL ;
    PORT
      LAYER M5 ;
        RECT  47.568 0 47.592 0.084 ;
    END
  END b_d[481]
  PIN b_d[482]
    DIRECTION INPUT ;
    USE SIGNAL ;
    PORT
      LAYER M5 ;
        RECT  47.664 0 47.688 0.084 ;
    END
  END b_d[482]
  PIN b_d[483]
    DIRECTION INPUT ;
    USE SIGNAL ;
    PORT
      LAYER M5 ;
        RECT  47.76 0 47.784 0.084 ;
    END
  END b_d[483]
  PIN b_d[484]
    DIRECTION INPUT ;
    USE SIGNAL ;
    PORT
      LAYER M5 ;
        RECT  47.856 0 47.88 0.084 ;
    END
  END b_d[484]
  PIN b_d[485]
    DIRECTION INPUT ;
    USE SIGNAL ;
    PORT
      LAYER M5 ;
        RECT  47.952 0 47.976 0.084 ;
    END
  END b_d[485]
  PIN b_d[486]
    DIRECTION INPUT ;
    USE SIGNAL ;
    PORT
      LAYER M5 ;
        RECT  48.048 0 48.072 0.084 ;
    END
  END b_d[486]
  PIN b_d[487]
    DIRECTION INPUT ;
    USE SIGNAL ;
    PORT
      LAYER M5 ;
        RECT  48.144 0 48.168 0.084 ;
    END
  END b_d[487]
  PIN b_d[488]
    DIRECTION INPUT ;
    USE SIGNAL ;
    PORT
      LAYER M5 ;
        RECT  48.24 0 48.264 0.084 ;
    END
  END b_d[488]
  PIN b_d[489]
    DIRECTION INPUT ;
    USE SIGNAL ;
    PORT
      LAYER M5 ;
        RECT  48.336 0 48.36 0.084 ;
    END
  END b_d[489]
  PIN b_d[48]
    DIRECTION INPUT ;
    USE SIGNAL ;
    PORT
      LAYER M5 ;
        RECT  5.424 0 5.448 0.084 ;
    END
  END b_d[48]
  PIN b_d[490]
    DIRECTION INPUT ;
    USE SIGNAL ;
    PORT
      LAYER M5 ;
        RECT  48.432 0 48.456 0.084 ;
    END
  END b_d[490]
  PIN b_d[491]
    DIRECTION INPUT ;
    USE SIGNAL ;
    PORT
      LAYER M5 ;
        RECT  48.528 0 48.552 0.084 ;
    END
  END b_d[491]
  PIN b_d[492]
    DIRECTION INPUT ;
    USE SIGNAL ;
    PORT
      LAYER M5 ;
        RECT  48.624 0 48.648 0.084 ;
    END
  END b_d[492]
  PIN b_d[493]
    DIRECTION INPUT ;
    USE SIGNAL ;
    PORT
      LAYER M5 ;
        RECT  48.72 0 48.744 0.084 ;
    END
  END b_d[493]
  PIN b_d[494]
    DIRECTION INPUT ;
    USE SIGNAL ;
    PORT
      LAYER M5 ;
        RECT  48.816 0 48.84 0.084 ;
    END
  END b_d[494]
  PIN b_d[495]
    DIRECTION INPUT ;
    USE SIGNAL ;
    PORT
      LAYER M5 ;
        RECT  48.912 0 48.936 0.084 ;
    END
  END b_d[495]
  PIN b_d[496]
    DIRECTION INPUT ;
    USE SIGNAL ;
    PORT
      LAYER M5 ;
        RECT  49.008 0 49.032 0.084 ;
    END
  END b_d[496]
  PIN b_d[497]
    DIRECTION INPUT ;
    USE SIGNAL ;
    PORT
      LAYER M5 ;
        RECT  49.152 0 49.176 0.084 ;
    END
  END b_d[497]
  PIN b_d[498]
    DIRECTION INPUT ;
    USE SIGNAL ;
    PORT
      LAYER M5 ;
        RECT  49.248 0 49.272 0.084 ;
    END
  END b_d[498]
  PIN b_d[499]
    DIRECTION INPUT ;
    USE SIGNAL ;
    PORT
      LAYER M5 ;
        RECT  49.344 0 49.368 0.084 ;
    END
  END b_d[499]
  PIN b_d[49]
    DIRECTION INPUT ;
    USE SIGNAL ;
    PORT
      LAYER M5 ;
        RECT  5.52 0 5.544 0.084 ;
    END
  END b_d[49]
  PIN b_d[4]
    DIRECTION INPUT ;
    USE SIGNAL ;
    PORT
      LAYER M5 ;
        RECT  1.152 0 1.176 0.084 ;
    END
  END b_d[4]
  PIN b_d[500]
    DIRECTION INPUT ;
    USE SIGNAL ;
    PORT
      LAYER M5 ;
        RECT  49.44 0 49.464 0.084 ;
    END
  END b_d[500]
  PIN b_d[501]
    DIRECTION INPUT ;
    USE SIGNAL ;
    PORT
      LAYER M5 ;
        RECT  49.536 0 49.56 0.084 ;
    END
  END b_d[501]
  PIN b_d[502]
    DIRECTION INPUT ;
    USE SIGNAL ;
    PORT
      LAYER M5 ;
        RECT  49.632 0 49.656 0.084 ;
    END
  END b_d[502]
  PIN b_d[503]
    DIRECTION INPUT ;
    USE SIGNAL ;
    PORT
      LAYER M5 ;
        RECT  49.728 0 49.752 0.084 ;
    END
  END b_d[503]
  PIN b_d[504]
    DIRECTION INPUT ;
    USE SIGNAL ;
    PORT
      LAYER M5 ;
        RECT  49.824 0 49.848 0.084 ;
    END
  END b_d[504]
  PIN b_d[505]
    DIRECTION INPUT ;
    USE SIGNAL ;
    PORT
      LAYER M5 ;
        RECT  49.92 0 49.944 0.084 ;
    END
  END b_d[505]
  PIN b_d[506]
    DIRECTION INPUT ;
    USE SIGNAL ;
    PORT
      LAYER M5 ;
        RECT  50.016 0 50.04 0.084 ;
    END
  END b_d[506]
  PIN b_d[507]
    DIRECTION INPUT ;
    USE SIGNAL ;
    PORT
      LAYER M5 ;
        RECT  50.112 0 50.136 0.084 ;
    END
  END b_d[507]
  PIN b_d[508]
    DIRECTION INPUT ;
    USE SIGNAL ;
    PORT
      LAYER M5 ;
        RECT  50.208 0 50.232 0.084 ;
    END
  END b_d[508]
  PIN b_d[509]
    DIRECTION INPUT ;
    USE SIGNAL ;
    PORT
      LAYER M5 ;
        RECT  50.304 0 50.328 0.084 ;
    END
  END b_d[509]
  PIN b_d[50]
    DIRECTION INPUT ;
    USE SIGNAL ;
    PORT
      LAYER M5 ;
        RECT  5.616 0 5.64 0.084 ;
    END
  END b_d[50]
  PIN b_d[510]
    DIRECTION INPUT ;
    USE SIGNAL ;
    PORT
      LAYER M5 ;
        RECT  50.4 0 50.424 0.084 ;
    END
  END b_d[510]
  PIN b_d[511]
    DIRECTION INPUT ;
    USE SIGNAL ;
    PORT
      LAYER M5 ;
        RECT  50.496 0 50.52 0.084 ;
    END
  END b_d[511]
  PIN b_d[512]
    DIRECTION INPUT ;
    USE SIGNAL ;
    PORT
      LAYER M5 ;
        RECT  50.592 0 50.616 0.084 ;
    END
  END b_d[512]
  PIN b_d[513]
    DIRECTION INPUT ;
    USE SIGNAL ;
    PORT
      LAYER M5 ;
        RECT  50.688 0 50.712 0.084 ;
    END
  END b_d[513]
  PIN b_d[514]
    DIRECTION INPUT ;
    USE SIGNAL ;
    PORT
      LAYER M5 ;
        RECT  50.784 0 50.808 0.084 ;
    END
  END b_d[514]
  PIN b_d[515]
    DIRECTION INPUT ;
    USE SIGNAL ;
    PORT
      LAYER M5 ;
        RECT  50.88 0 50.904 0.084 ;
    END
  END b_d[515]
  PIN b_d[51]
    DIRECTION INPUT ;
    USE SIGNAL ;
    PORT
      LAYER M5 ;
        RECT  5.712 0 5.736 0.084 ;
    END
  END b_d[51]
  PIN b_d[52]
    DIRECTION INPUT ;
    USE SIGNAL ;
    PORT
      LAYER M5 ;
        RECT  5.808 0 5.832 0.084 ;
    END
  END b_d[52]
  PIN b_d[53]
    DIRECTION INPUT ;
    USE SIGNAL ;
    PORT
      LAYER M5 ;
        RECT  5.904 0 5.928 0.084 ;
    END
  END b_d[53]
  PIN b_d[54]
    DIRECTION INPUT ;
    USE SIGNAL ;
    PORT
      LAYER M5 ;
        RECT  6 0 6.024 0.084 ;
    END
  END b_d[54]
  PIN b_d[55]
    DIRECTION INPUT ;
    USE SIGNAL ;
    PORT
      LAYER M5 ;
        RECT  6.144 0 6.168 0.084 ;
    END
  END b_d[55]
  PIN b_d[56]
    DIRECTION INPUT ;
    USE SIGNAL ;
    PORT
      LAYER M5 ;
        RECT  6.24 0 6.264 0.084 ;
    END
  END b_d[56]
  PIN b_d[57]
    DIRECTION INPUT ;
    USE SIGNAL ;
    PORT
      LAYER M5 ;
        RECT  6.336 0 6.36 0.084 ;
    END
  END b_d[57]
  PIN b_d[58]
    DIRECTION INPUT ;
    USE SIGNAL ;
    PORT
      LAYER M5 ;
        RECT  6.432 0 6.456 0.084 ;
    END
  END b_d[58]
  PIN b_d[59]
    DIRECTION INPUT ;
    USE SIGNAL ;
    PORT
      LAYER M5 ;
        RECT  6.528 0 6.552 0.084 ;
    END
  END b_d[59]
  PIN b_d[5]
    DIRECTION INPUT ;
    USE SIGNAL ;
    PORT
      LAYER M5 ;
        RECT  1.248 0 1.272 0.084 ;
    END
  END b_d[5]
  PIN b_d[60]
    DIRECTION INPUT ;
    USE SIGNAL ;
    PORT
      LAYER M5 ;
        RECT  6.624 0 6.648 0.084 ;
    END
  END b_d[60]
  PIN b_d[61]
    DIRECTION INPUT ;
    USE SIGNAL ;
    PORT
      LAYER M5 ;
        RECT  6.72 0 6.744 0.084 ;
    END
  END b_d[61]
  PIN b_d[62]
    DIRECTION INPUT ;
    USE SIGNAL ;
    PORT
      LAYER M5 ;
        RECT  6.816 0 6.84 0.084 ;
    END
  END b_d[62]
  PIN b_d[63]
    DIRECTION INPUT ;
    USE SIGNAL ;
    PORT
      LAYER M5 ;
        RECT  6.912 0 6.936 0.084 ;
    END
  END b_d[63]
  PIN b_d[64]
    DIRECTION INPUT ;
    USE SIGNAL ;
    PORT
      LAYER M5 ;
        RECT  7.008 0 7.032 0.084 ;
    END
  END b_d[64]
  PIN b_d[65]
    DIRECTION INPUT ;
    USE SIGNAL ;
    PORT
      LAYER M5 ;
        RECT  7.104 0 7.128 0.084 ;
    END
  END b_d[65]
  PIN b_d[66]
    DIRECTION INPUT ;
    USE SIGNAL ;
    PORT
      LAYER M5 ;
        RECT  7.2 0 7.224 0.084 ;
    END
  END b_d[66]
  PIN b_d[67]
    DIRECTION INPUT ;
    USE SIGNAL ;
    PORT
      LAYER M5 ;
        RECT  7.296 0 7.32 0.084 ;
    END
  END b_d[67]
  PIN b_d[68]
    DIRECTION INPUT ;
    USE SIGNAL ;
    PORT
      LAYER M5 ;
        RECT  7.392 0 7.416 0.084 ;
    END
  END b_d[68]
  PIN b_d[69]
    DIRECTION INPUT ;
    USE SIGNAL ;
    PORT
      LAYER M5 ;
        RECT  7.488 0 7.512 0.084 ;
    END
  END b_d[69]
  PIN b_d[6]
    DIRECTION INPUT ;
    USE SIGNAL ;
    PORT
      LAYER M5 ;
        RECT  1.344 0 1.368 0.084 ;
    END
  END b_d[6]
  PIN b_d[70]
    DIRECTION INPUT ;
    USE SIGNAL ;
    PORT
      LAYER M5 ;
        RECT  7.584 0 7.608 0.084 ;
    END
  END b_d[70]
  PIN b_d[71]
    DIRECTION INPUT ;
    USE SIGNAL ;
    PORT
      LAYER M5 ;
        RECT  7.68 0 7.704 0.084 ;
    END
  END b_d[71]
  PIN b_d[72]
    DIRECTION INPUT ;
    USE SIGNAL ;
    PORT
      LAYER M5 ;
        RECT  7.776 0 7.8 0.084 ;
    END
  END b_d[72]
  PIN b_d[73]
    DIRECTION INPUT ;
    USE SIGNAL ;
    PORT
      LAYER M5 ;
        RECT  7.872 0 7.896 0.084 ;
    END
  END b_d[73]
  PIN b_d[74]
    DIRECTION INPUT ;
    USE SIGNAL ;
    PORT
      LAYER M5 ;
        RECT  7.968 0 7.992 0.084 ;
    END
  END b_d[74]
  PIN b_d[75]
    DIRECTION INPUT ;
    USE SIGNAL ;
    PORT
      LAYER M5 ;
        RECT  8.064 0 8.088 0.084 ;
    END
  END b_d[75]
  PIN b_d[76]
    DIRECTION INPUT ;
    USE SIGNAL ;
    PORT
      LAYER M5 ;
        RECT  8.16 0 8.184 0.084 ;
    END
  END b_d[76]
  PIN b_d[77]
    DIRECTION INPUT ;
    USE SIGNAL ;
    PORT
      LAYER M5 ;
        RECT  8.256 0 8.28 0.084 ;
    END
  END b_d[77]
  PIN b_d[78]
    DIRECTION INPUT ;
    USE SIGNAL ;
    PORT
      LAYER M5 ;
        RECT  8.352 0 8.376 0.084 ;
    END
  END b_d[78]
  PIN b_d[79]
    DIRECTION INPUT ;
    USE SIGNAL ;
    PORT
      LAYER M5 ;
        RECT  8.448 0 8.472 0.084 ;
    END
  END b_d[79]
  PIN b_d[7]
    DIRECTION INPUT ;
    USE SIGNAL ;
    PORT
      LAYER M5 ;
        RECT  1.44 0 1.464 0.084 ;
    END
  END b_d[7]
  PIN b_d[80]
    DIRECTION INPUT ;
    USE SIGNAL ;
    PORT
      LAYER M5 ;
        RECT  8.544 0 8.568 0.084 ;
    END
  END b_d[80]
  PIN b_d[81]
    DIRECTION INPUT ;
    USE SIGNAL ;
    PORT
      LAYER M5 ;
        RECT  8.64 0 8.664 0.084 ;
    END
  END b_d[81]
  PIN b_d[82]
    DIRECTION INPUT ;
    USE SIGNAL ;
    PORT
      LAYER M5 ;
        RECT  8.736 0 8.76 0.084 ;
    END
  END b_d[82]
  PIN b_d[83]
    DIRECTION INPUT ;
    USE SIGNAL ;
    PORT
      LAYER M5 ;
        RECT  8.832 0 8.856 0.084 ;
    END
  END b_d[83]
  PIN b_d[84]
    DIRECTION INPUT ;
    USE SIGNAL ;
    PORT
      LAYER M5 ;
        RECT  8.928 0 8.952 0.084 ;
    END
  END b_d[84]
  PIN b_d[85]
    DIRECTION INPUT ;
    USE SIGNAL ;
    PORT
      LAYER M5 ;
        RECT  9.024 0 9.048 0.084 ;
    END
  END b_d[85]
  PIN b_d[86]
    DIRECTION INPUT ;
    USE SIGNAL ;
    PORT
      LAYER M5 ;
        RECT  9.12 0 9.144 0.084 ;
    END
  END b_d[86]
  PIN b_d[87]
    DIRECTION INPUT ;
    USE SIGNAL ;
    PORT
      LAYER M5 ;
        RECT  9.216 0 9.24 0.084 ;
    END
  END b_d[87]
  PIN b_d[88]
    DIRECTION INPUT ;
    USE SIGNAL ;
    PORT
      LAYER M5 ;
        RECT  9.312 0 9.336 0.084 ;
    END
  END b_d[88]
  PIN b_d[89]
    DIRECTION INPUT ;
    USE SIGNAL ;
    PORT
      LAYER M5 ;
        RECT  9.408 0 9.432 0.084 ;
    END
  END b_d[89]
  PIN b_d[8]
    DIRECTION INPUT ;
    USE SIGNAL ;
    PORT
      LAYER M5 ;
        RECT  1.536 0 1.56 0.084 ;
    END
  END b_d[8]
  PIN b_d[90]
    DIRECTION INPUT ;
    USE SIGNAL ;
    PORT
      LAYER M5 ;
        RECT  9.504 0 9.528 0.084 ;
    END
  END b_d[90]
  PIN b_d[91]
    DIRECTION INPUT ;
    USE SIGNAL ;
    PORT
      LAYER M5 ;
        RECT  9.6 0 9.624 0.084 ;
    END
  END b_d[91]
  PIN b_d[92]
    DIRECTION INPUT ;
    USE SIGNAL ;
    PORT
      LAYER M5 ;
        RECT  9.744 0 9.768 0.084 ;
    END
  END b_d[92]
  PIN b_d[93]
    DIRECTION INPUT ;
    USE SIGNAL ;
    PORT
      LAYER M5 ;
        RECT  9.84 0 9.864 0.084 ;
    END
  END b_d[93]
  PIN b_d[94]
    DIRECTION INPUT ;
    USE SIGNAL ;
    PORT
      LAYER M5 ;
        RECT  9.936 0 9.96 0.084 ;
    END
  END b_d[94]
  PIN b_d[95]
    DIRECTION INPUT ;
    USE SIGNAL ;
    PORT
      LAYER M5 ;
        RECT  10.032 0 10.056 0.084 ;
    END
  END b_d[95]
  PIN b_d[96]
    DIRECTION INPUT ;
    USE SIGNAL ;
    PORT
      LAYER M5 ;
        RECT  10.128 0 10.152 0.084 ;
    END
  END b_d[96]
  PIN b_d[97]
    DIRECTION INPUT ;
    USE SIGNAL ;
    PORT
      LAYER M5 ;
        RECT  10.224 0 10.248 0.084 ;
    END
  END b_d[97]
  PIN b_d[98]
    DIRECTION INPUT ;
    USE SIGNAL ;
    PORT
      LAYER M5 ;
        RECT  10.32 0 10.344 0.084 ;
    END
  END b_d[98]
  PIN b_d[99]
    DIRECTION INPUT ;
    USE SIGNAL ;
    PORT
      LAYER M5 ;
        RECT  10.416 0 10.44 0.084 ;
    END
  END b_d[99]
  PIN b_d[9]
    DIRECTION INPUT ;
    USE SIGNAL ;
    PORT
      LAYER M5 ;
        RECT  1.632 0 1.656 0.084 ;
    END
  END b_d[9]
  PIN ck
    DIRECTION INPUT ;
    USE SIGNAL ;
    PORT
      LAYER M5 ;
        RECT  52.08 103.572 52.104 103.656 ;
    END
  END ck
  PIN rst_n
    DIRECTION INPUT ;
    USE SIGNAL ;
    PORT
      LAYER M5 ;
        RECT  52.368 103.572 52.392 103.656 ;
    END
  END rst_n
  PIN sidx[0]
    DIRECTION INPUT ;
    USE SIGNAL ;
    PORT
      LAYER M5 ;
        RECT  0.288 103.572 0.312 103.656 ;
    END
  END sidx[0]
  PIN sidx[1]
    DIRECTION INPUT ;
    USE SIGNAL ;
    PORT
      LAYER M5 ;
        RECT  0.48 103.572 0.504 103.656 ;
    END
  END sidx[1]
  PIN sidx[2]
    DIRECTION INPUT ;
    USE SIGNAL ;
    PORT
      LAYER M5 ;
        RECT  0.672 103.572 0.696 103.656 ;
    END
  END sidx[2]
  PIN tap_d[0]
    DIRECTION OUTPUT ;
    USE SIGNAL ;
    PORT
      LAYER M4 ;
        RECT  0 26.976 0.084 27 ;
    END
  END tap_d[0]
  PIN tap_d[100]
    DIRECTION OUTPUT ;
    USE SIGNAL ;
    PORT
      LAYER M4 ;
        RECT  0 36.912 0.084 36.936 ;
    END
  END tap_d[100]
  PIN tap_d[101]
    DIRECTION OUTPUT ;
    USE SIGNAL ;
    PORT
      LAYER M4 ;
        RECT  0 37.008 0.084 37.032 ;
    END
  END tap_d[101]
  PIN tap_d[102]
    DIRECTION OUTPUT ;
    USE SIGNAL ;
    PORT
      LAYER M4 ;
        RECT  0 37.104 0.084 37.128 ;
    END
  END tap_d[102]
  PIN tap_d[103]
    DIRECTION OUTPUT ;
    USE SIGNAL ;
    PORT
      LAYER M4 ;
        RECT  0 37.2 0.084 37.224 ;
    END
  END tap_d[103]
  PIN tap_d[104]
    DIRECTION OUTPUT ;
    USE SIGNAL ;
    PORT
      LAYER M4 ;
        RECT  0 37.296 0.084 37.32 ;
    END
  END tap_d[104]
  PIN tap_d[105]
    DIRECTION OUTPUT ;
    USE SIGNAL ;
    PORT
      LAYER M4 ;
        RECT  0 37.392 0.084 37.416 ;
    END
  END tap_d[105]
  PIN tap_d[106]
    DIRECTION OUTPUT ;
    USE SIGNAL ;
    PORT
      LAYER M4 ;
        RECT  0 37.536 0.084 37.56 ;
    END
  END tap_d[106]
  PIN tap_d[107]
    DIRECTION OUTPUT ;
    USE SIGNAL ;
    PORT
      LAYER M4 ;
        RECT  0 37.632 0.084 37.656 ;
    END
  END tap_d[107]
  PIN tap_d[108]
    DIRECTION OUTPUT ;
    USE SIGNAL ;
    PORT
      LAYER M4 ;
        RECT  0 37.728 0.084 37.752 ;
    END
  END tap_d[108]
  PIN tap_d[109]
    DIRECTION OUTPUT ;
    USE SIGNAL ;
    PORT
      LAYER M4 ;
        RECT  0 37.824 0.084 37.848 ;
    END
  END tap_d[109]
  PIN tap_d[10]
    DIRECTION OUTPUT ;
    USE SIGNAL ;
    PORT
      LAYER M4 ;
        RECT  0 27.984 0.084 28.008 ;
    END
  END tap_d[10]
  PIN tap_d[110]
    DIRECTION OUTPUT ;
    USE SIGNAL ;
    PORT
      LAYER M4 ;
        RECT  0 37.92 0.084 37.944 ;
    END
  END tap_d[110]
  PIN tap_d[111]
    DIRECTION OUTPUT ;
    USE SIGNAL ;
    PORT
      LAYER M4 ;
        RECT  0 38.016 0.084 38.04 ;
    END
  END tap_d[111]
  PIN tap_d[112]
    DIRECTION OUTPUT ;
    USE SIGNAL ;
    PORT
      LAYER M4 ;
        RECT  0 38.112 0.084 38.136 ;
    END
  END tap_d[112]
  PIN tap_d[113]
    DIRECTION OUTPUT ;
    USE SIGNAL ;
    PORT
      LAYER M4 ;
        RECT  0 38.208 0.084 38.232 ;
    END
  END tap_d[113]
  PIN tap_d[114]
    DIRECTION OUTPUT ;
    USE SIGNAL ;
    PORT
      LAYER M4 ;
        RECT  0 38.304 0.084 38.328 ;
    END
  END tap_d[114]
  PIN tap_d[115]
    DIRECTION OUTPUT ;
    USE SIGNAL ;
    PORT
      LAYER M4 ;
        RECT  0 38.4 0.084 38.424 ;
    END
  END tap_d[115]
  PIN tap_d[116]
    DIRECTION OUTPUT ;
    USE SIGNAL ;
    PORT
      LAYER M4 ;
        RECT  0 38.496 0.084 38.52 ;
    END
  END tap_d[116]
  PIN tap_d[117]
    DIRECTION OUTPUT ;
    USE SIGNAL ;
    PORT
      LAYER M4 ;
        RECT  0 38.592 0.084 38.616 ;
    END
  END tap_d[117]
  PIN tap_d[118]
    DIRECTION OUTPUT ;
    USE SIGNAL ;
    PORT
      LAYER M4 ;
        RECT  0 38.688 0.084 38.712 ;
    END
  END tap_d[118]
  PIN tap_d[119]
    DIRECTION OUTPUT ;
    USE SIGNAL ;
    PORT
      LAYER M4 ;
        RECT  0 38.784 0.084 38.808 ;
    END
  END tap_d[119]
  PIN tap_d[11]
    DIRECTION OUTPUT ;
    USE SIGNAL ;
    PORT
      LAYER M4 ;
        RECT  0 28.08 0.084 28.104 ;
    END
  END tap_d[11]
  PIN tap_d[120]
    DIRECTION OUTPUT ;
    USE SIGNAL ;
    PORT
      LAYER M4 ;
        RECT  0 38.928 0.084 38.952 ;
    END
  END tap_d[120]
  PIN tap_d[121]
    DIRECTION OUTPUT ;
    USE SIGNAL ;
    PORT
      LAYER M4 ;
        RECT  0 39.024 0.084 39.048 ;
    END
  END tap_d[121]
  PIN tap_d[122]
    DIRECTION OUTPUT ;
    USE SIGNAL ;
    PORT
      LAYER M4 ;
        RECT  0 39.12 0.084 39.144 ;
    END
  END tap_d[122]
  PIN tap_d[123]
    DIRECTION OUTPUT ;
    USE SIGNAL ;
    PORT
      LAYER M4 ;
        RECT  0 39.216 0.084 39.24 ;
    END
  END tap_d[123]
  PIN tap_d[124]
    DIRECTION OUTPUT ;
    USE SIGNAL ;
    PORT
      LAYER M4 ;
        RECT  0 39.312 0.084 39.336 ;
    END
  END tap_d[124]
  PIN tap_d[125]
    DIRECTION OUTPUT ;
    USE SIGNAL ;
    PORT
      LAYER M4 ;
        RECT  0 39.408 0.084 39.432 ;
    END
  END tap_d[125]
  PIN tap_d[126]
    DIRECTION OUTPUT ;
    USE SIGNAL ;
    PORT
      LAYER M4 ;
        RECT  0 39.504 0.084 39.528 ;
    END
  END tap_d[126]
  PIN tap_d[127]
    DIRECTION OUTPUT ;
    USE SIGNAL ;
    PORT
      LAYER M4 ;
        RECT  0 39.6 0.084 39.624 ;
    END
  END tap_d[127]
  PIN tap_d[128]
    DIRECTION OUTPUT ;
    USE SIGNAL ;
    PORT
      LAYER M4 ;
        RECT  0 39.696 0.084 39.72 ;
    END
  END tap_d[128]
  PIN tap_d[129]
    DIRECTION OUTPUT ;
    USE SIGNAL ;
    PORT
      LAYER M4 ;
        RECT  0 39.792 0.084 39.816 ;
    END
  END tap_d[129]
  PIN tap_d[12]
    DIRECTION OUTPUT ;
    USE SIGNAL ;
    PORT
      LAYER M4 ;
        RECT  0 28.176 0.084 28.2 ;
    END
  END tap_d[12]
  PIN tap_d[130]
    DIRECTION OUTPUT ;
    USE SIGNAL ;
    PORT
      LAYER M4 ;
        RECT  0 39.888 0.084 39.912 ;
    END
  END tap_d[130]
  PIN tap_d[131]
    DIRECTION OUTPUT ;
    USE SIGNAL ;
    PORT
      LAYER M4 ;
        RECT  0 39.984 0.084 40.008 ;
    END
  END tap_d[131]
  PIN tap_d[132]
    DIRECTION OUTPUT ;
    USE SIGNAL ;
    PORT
      LAYER M4 ;
        RECT  0 40.08 0.084 40.104 ;
    END
  END tap_d[132]
  PIN tap_d[133]
    DIRECTION OUTPUT ;
    USE SIGNAL ;
    PORT
      LAYER M4 ;
        RECT  0 40.176 0.084 40.2 ;
    END
  END tap_d[133]
  PIN tap_d[134]
    DIRECTION OUTPUT ;
    USE SIGNAL ;
    PORT
      LAYER M4 ;
        RECT  0 40.32 0.084 40.344 ;
    END
  END tap_d[134]
  PIN tap_d[135]
    DIRECTION OUTPUT ;
    USE SIGNAL ;
    PORT
      LAYER M4 ;
        RECT  0 40.416 0.084 40.44 ;
    END
  END tap_d[135]
  PIN tap_d[136]
    DIRECTION OUTPUT ;
    USE SIGNAL ;
    PORT
      LAYER M4 ;
        RECT  0 40.512 0.084 40.536 ;
    END
  END tap_d[136]
  PIN tap_d[137]
    DIRECTION OUTPUT ;
    USE SIGNAL ;
    PORT
      LAYER M4 ;
        RECT  0 40.608 0.084 40.632 ;
    END
  END tap_d[137]
  PIN tap_d[138]
    DIRECTION OUTPUT ;
    USE SIGNAL ;
    PORT
      LAYER M4 ;
        RECT  0 40.704 0.084 40.728 ;
    END
  END tap_d[138]
  PIN tap_d[139]
    DIRECTION OUTPUT ;
    USE SIGNAL ;
    PORT
      LAYER M4 ;
        RECT  0 40.8 0.084 40.824 ;
    END
  END tap_d[139]
  PIN tap_d[13]
    DIRECTION OUTPUT ;
    USE SIGNAL ;
    PORT
      LAYER M4 ;
        RECT  0 28.272 0.084 28.296 ;
    END
  END tap_d[13]
  PIN tap_d[140]
    DIRECTION OUTPUT ;
    USE SIGNAL ;
    PORT
      LAYER M4 ;
        RECT  0 40.896 0.084 40.92 ;
    END
  END tap_d[140]
  PIN tap_d[141]
    DIRECTION OUTPUT ;
    USE SIGNAL ;
    PORT
      LAYER M4 ;
        RECT  0 40.992 0.084 41.016 ;
    END
  END tap_d[141]
  PIN tap_d[142]
    DIRECTION OUTPUT ;
    USE SIGNAL ;
    PORT
      LAYER M4 ;
        RECT  0 41.088 0.084 41.112 ;
    END
  END tap_d[142]
  PIN tap_d[143]
    DIRECTION OUTPUT ;
    USE SIGNAL ;
    PORT
      LAYER M4 ;
        RECT  0 41.184 0.084 41.208 ;
    END
  END tap_d[143]
  PIN tap_d[144]
    DIRECTION OUTPUT ;
    USE SIGNAL ;
    PORT
      LAYER M4 ;
        RECT  0 41.28 0.084 41.304 ;
    END
  END tap_d[144]
  PIN tap_d[145]
    DIRECTION OUTPUT ;
    USE SIGNAL ;
    PORT
      LAYER M4 ;
        RECT  0 41.376 0.084 41.4 ;
    END
  END tap_d[145]
  PIN tap_d[146]
    DIRECTION OUTPUT ;
    USE SIGNAL ;
    PORT
      LAYER M4 ;
        RECT  0 41.472 0.084 41.496 ;
    END
  END tap_d[146]
  PIN tap_d[147]
    DIRECTION OUTPUT ;
    USE SIGNAL ;
    PORT
      LAYER M4 ;
        RECT  0 41.568 0.084 41.592 ;
    END
  END tap_d[147]
  PIN tap_d[148]
    DIRECTION OUTPUT ;
    USE SIGNAL ;
    PORT
      LAYER M4 ;
        RECT  0 41.712 0.084 41.736 ;
    END
  END tap_d[148]
  PIN tap_d[149]
    DIRECTION OUTPUT ;
    USE SIGNAL ;
    PORT
      LAYER M4 ;
        RECT  0 41.808 0.084 41.832 ;
    END
  END tap_d[149]
  PIN tap_d[14]
    DIRECTION OUTPUT ;
    USE SIGNAL ;
    PORT
      LAYER M4 ;
        RECT  0 28.368 0.084 28.392 ;
    END
  END tap_d[14]
  PIN tap_d[150]
    DIRECTION OUTPUT ;
    USE SIGNAL ;
    PORT
      LAYER M4 ;
        RECT  0 41.904 0.084 41.928 ;
    END
  END tap_d[150]
  PIN tap_d[151]
    DIRECTION OUTPUT ;
    USE SIGNAL ;
    PORT
      LAYER M4 ;
        RECT  0 42 0.084 42.024 ;
    END
  END tap_d[151]
  PIN tap_d[152]
    DIRECTION OUTPUT ;
    USE SIGNAL ;
    PORT
      LAYER M4 ;
        RECT  0 42.096 0.084 42.12 ;
    END
  END tap_d[152]
  PIN tap_d[153]
    DIRECTION OUTPUT ;
    USE SIGNAL ;
    PORT
      LAYER M4 ;
        RECT  0 42.192 0.084 42.216 ;
    END
  END tap_d[153]
  PIN tap_d[154]
    DIRECTION OUTPUT ;
    USE SIGNAL ;
    PORT
      LAYER M4 ;
        RECT  0 42.288 0.084 42.312 ;
    END
  END tap_d[154]
  PIN tap_d[155]
    DIRECTION OUTPUT ;
    USE SIGNAL ;
    PORT
      LAYER M4 ;
        RECT  0 42.384 0.084 42.408 ;
    END
  END tap_d[155]
  PIN tap_d[156]
    DIRECTION OUTPUT ;
    USE SIGNAL ;
    PORT
      LAYER M4 ;
        RECT  0 42.48 0.084 42.504 ;
    END
  END tap_d[156]
  PIN tap_d[157]
    DIRECTION OUTPUT ;
    USE SIGNAL ;
    PORT
      LAYER M4 ;
        RECT  0 42.576 0.084 42.6 ;
    END
  END tap_d[157]
  PIN tap_d[158]
    DIRECTION OUTPUT ;
    USE SIGNAL ;
    PORT
      LAYER M4 ;
        RECT  0 42.672 0.084 42.696 ;
    END
  END tap_d[158]
  PIN tap_d[159]
    DIRECTION OUTPUT ;
    USE SIGNAL ;
    PORT
      LAYER M4 ;
        RECT  0 42.768 0.084 42.792 ;
    END
  END tap_d[159]
  PIN tap_d[15]
    DIRECTION OUTPUT ;
    USE SIGNAL ;
    PORT
      LAYER M4 ;
        RECT  0 28.464 0.084 28.488 ;
    END
  END tap_d[15]
  PIN tap_d[160]
    DIRECTION OUTPUT ;
    USE SIGNAL ;
    PORT
      LAYER M4 ;
        RECT  0 42.864 0.084 42.888 ;
    END
  END tap_d[160]
  PIN tap_d[161]
    DIRECTION OUTPUT ;
    USE SIGNAL ;
    PORT
      LAYER M4 ;
        RECT  0 42.96 0.084 42.984 ;
    END
  END tap_d[161]
  PIN tap_d[162]
    DIRECTION OUTPUT ;
    USE SIGNAL ;
    PORT
      LAYER M4 ;
        RECT  0 43.104 0.084 43.128 ;
    END
  END tap_d[162]
  PIN tap_d[163]
    DIRECTION OUTPUT ;
    USE SIGNAL ;
    PORT
      LAYER M4 ;
        RECT  0 43.2 0.084 43.224 ;
    END
  END tap_d[163]
  PIN tap_d[164]
    DIRECTION OUTPUT ;
    USE SIGNAL ;
    PORT
      LAYER M4 ;
        RECT  0 43.296 0.084 43.32 ;
    END
  END tap_d[164]
  PIN tap_d[165]
    DIRECTION OUTPUT ;
    USE SIGNAL ;
    PORT
      LAYER M4 ;
        RECT  0 43.392 0.084 43.416 ;
    END
  END tap_d[165]
  PIN tap_d[166]
    DIRECTION OUTPUT ;
    USE SIGNAL ;
    PORT
      LAYER M4 ;
        RECT  0 43.488 0.084 43.512 ;
    END
  END tap_d[166]
  PIN tap_d[167]
    DIRECTION OUTPUT ;
    USE SIGNAL ;
    PORT
      LAYER M4 ;
        RECT  0 43.584 0.084 43.608 ;
    END
  END tap_d[167]
  PIN tap_d[168]
    DIRECTION OUTPUT ;
    USE SIGNAL ;
    PORT
      LAYER M4 ;
        RECT  0 43.68 0.084 43.704 ;
    END
  END tap_d[168]
  PIN tap_d[169]
    DIRECTION OUTPUT ;
    USE SIGNAL ;
    PORT
      LAYER M4 ;
        RECT  0 43.776 0.084 43.8 ;
    END
  END tap_d[169]
  PIN tap_d[16]
    DIRECTION OUTPUT ;
    USE SIGNAL ;
    PORT
      LAYER M4 ;
        RECT  0 28.56 0.084 28.584 ;
    END
  END tap_d[16]
  PIN tap_d[170]
    DIRECTION OUTPUT ;
    USE SIGNAL ;
    PORT
      LAYER M4 ;
        RECT  0 43.872 0.084 43.896 ;
    END
  END tap_d[170]
  PIN tap_d[171]
    DIRECTION OUTPUT ;
    USE SIGNAL ;
    PORT
      LAYER M4 ;
        RECT  0 43.968 0.084 43.992 ;
    END
  END tap_d[171]
  PIN tap_d[172]
    DIRECTION OUTPUT ;
    USE SIGNAL ;
    PORT
      LAYER M4 ;
        RECT  0 44.064 0.084 44.088 ;
    END
  END tap_d[172]
  PIN tap_d[173]
    DIRECTION OUTPUT ;
    USE SIGNAL ;
    PORT
      LAYER M4 ;
        RECT  0 44.16 0.084 44.184 ;
    END
  END tap_d[173]
  PIN tap_d[174]
    DIRECTION OUTPUT ;
    USE SIGNAL ;
    PORT
      LAYER M4 ;
        RECT  0 44.256 0.084 44.28 ;
    END
  END tap_d[174]
  PIN tap_d[175]
    DIRECTION OUTPUT ;
    USE SIGNAL ;
    PORT
      LAYER M4 ;
        RECT  0 44.352 0.084 44.376 ;
    END
  END tap_d[175]
  PIN tap_d[176]
    DIRECTION OUTPUT ;
    USE SIGNAL ;
    PORT
      LAYER M4 ;
        RECT  0 44.496 0.084 44.52 ;
    END
  END tap_d[176]
  PIN tap_d[177]
    DIRECTION OUTPUT ;
    USE SIGNAL ;
    PORT
      LAYER M4 ;
        RECT  0 44.592 0.084 44.616 ;
    END
  END tap_d[177]
  PIN tap_d[178]
    DIRECTION OUTPUT ;
    USE SIGNAL ;
    PORT
      LAYER M4 ;
        RECT  0 44.688 0.084 44.712 ;
    END
  END tap_d[178]
  PIN tap_d[179]
    DIRECTION OUTPUT ;
    USE SIGNAL ;
    PORT
      LAYER M4 ;
        RECT  0 44.784 0.084 44.808 ;
    END
  END tap_d[179]
  PIN tap_d[17]
    DIRECTION OUTPUT ;
    USE SIGNAL ;
    PORT
      LAYER M4 ;
        RECT  0 28.656 0.084 28.68 ;
    END
  END tap_d[17]
  PIN tap_d[180]
    DIRECTION OUTPUT ;
    USE SIGNAL ;
    PORT
      LAYER M4 ;
        RECT  0 44.88 0.084 44.904 ;
    END
  END tap_d[180]
  PIN tap_d[181]
    DIRECTION OUTPUT ;
    USE SIGNAL ;
    PORT
      LAYER M4 ;
        RECT  0 44.976 0.084 45 ;
    END
  END tap_d[181]
  PIN tap_d[182]
    DIRECTION OUTPUT ;
    USE SIGNAL ;
    PORT
      LAYER M4 ;
        RECT  0 45.072 0.084 45.096 ;
    END
  END tap_d[182]
  PIN tap_d[183]
    DIRECTION OUTPUT ;
    USE SIGNAL ;
    PORT
      LAYER M4 ;
        RECT  0 45.168 0.084 45.192 ;
    END
  END tap_d[183]
  PIN tap_d[184]
    DIRECTION OUTPUT ;
    USE SIGNAL ;
    PORT
      LAYER M4 ;
        RECT  0 45.264 0.084 45.288 ;
    END
  END tap_d[184]
  PIN tap_d[185]
    DIRECTION OUTPUT ;
    USE SIGNAL ;
    PORT
      LAYER M4 ;
        RECT  0 45.36 0.084 45.384 ;
    END
  END tap_d[185]
  PIN tap_d[186]
    DIRECTION OUTPUT ;
    USE SIGNAL ;
    PORT
      LAYER M4 ;
        RECT  0 45.456 0.084 45.48 ;
    END
  END tap_d[186]
  PIN tap_d[187]
    DIRECTION OUTPUT ;
    USE SIGNAL ;
    PORT
      LAYER M4 ;
        RECT  0 45.552 0.084 45.576 ;
    END
  END tap_d[187]
  PIN tap_d[188]
    DIRECTION OUTPUT ;
    USE SIGNAL ;
    PORT
      LAYER M4 ;
        RECT  0 45.648 0.084 45.672 ;
    END
  END tap_d[188]
  PIN tap_d[189]
    DIRECTION OUTPUT ;
    USE SIGNAL ;
    PORT
      LAYER M4 ;
        RECT  0 45.744 0.084 45.768 ;
    END
  END tap_d[189]
  PIN tap_d[18]
    DIRECTION OUTPUT ;
    USE SIGNAL ;
    PORT
      LAYER M4 ;
        RECT  0 28.752 0.084 28.776 ;
    END
  END tap_d[18]
  PIN tap_d[190]
    DIRECTION OUTPUT ;
    USE SIGNAL ;
    PORT
      LAYER M4 ;
        RECT  0 45.888 0.084 45.912 ;
    END
  END tap_d[190]
  PIN tap_d[191]
    DIRECTION OUTPUT ;
    USE SIGNAL ;
    PORT
      LAYER M4 ;
        RECT  0 45.984 0.084 46.008 ;
    END
  END tap_d[191]
  PIN tap_d[192]
    DIRECTION OUTPUT ;
    USE SIGNAL ;
    PORT
      LAYER M4 ;
        RECT  0 46.08 0.084 46.104 ;
    END
  END tap_d[192]
  PIN tap_d[193]
    DIRECTION OUTPUT ;
    USE SIGNAL ;
    PORT
      LAYER M4 ;
        RECT  0 46.176 0.084 46.2 ;
    END
  END tap_d[193]
  PIN tap_d[194]
    DIRECTION OUTPUT ;
    USE SIGNAL ;
    PORT
      LAYER M4 ;
        RECT  0 46.272 0.084 46.296 ;
    END
  END tap_d[194]
  PIN tap_d[195]
    DIRECTION OUTPUT ;
    USE SIGNAL ;
    PORT
      LAYER M4 ;
        RECT  0 46.368 0.084 46.392 ;
    END
  END tap_d[195]
  PIN tap_d[196]
    DIRECTION OUTPUT ;
    USE SIGNAL ;
    PORT
      LAYER M4 ;
        RECT  0 46.464 0.084 46.488 ;
    END
  END tap_d[196]
  PIN tap_d[197]
    DIRECTION OUTPUT ;
    USE SIGNAL ;
    PORT
      LAYER M4 ;
        RECT  0 46.56 0.084 46.584 ;
    END
  END tap_d[197]
  PIN tap_d[198]
    DIRECTION OUTPUT ;
    USE SIGNAL ;
    PORT
      LAYER M4 ;
        RECT  0 46.656 0.084 46.68 ;
    END
  END tap_d[198]
  PIN tap_d[199]
    DIRECTION OUTPUT ;
    USE SIGNAL ;
    PORT
      LAYER M4 ;
        RECT  0 46.752 0.084 46.776 ;
    END
  END tap_d[199]
  PIN tap_d[19]
    DIRECTION OUTPUT ;
    USE SIGNAL ;
    PORT
      LAYER M4 ;
        RECT  0 28.848 0.084 28.872 ;
    END
  END tap_d[19]
  PIN tap_d[1]
    DIRECTION OUTPUT ;
    USE SIGNAL ;
    PORT
      LAYER M4 ;
        RECT  0 27.072 0.084 27.096 ;
    END
  END tap_d[1]
  PIN tap_d[200]
    DIRECTION OUTPUT ;
    USE SIGNAL ;
    PORT
      LAYER M4 ;
        RECT  0 46.848 0.084 46.872 ;
    END
  END tap_d[200]
  PIN tap_d[201]
    DIRECTION OUTPUT ;
    USE SIGNAL ;
    PORT
      LAYER M4 ;
        RECT  0 46.944 0.084 46.968 ;
    END
  END tap_d[201]
  PIN tap_d[202]
    DIRECTION OUTPUT ;
    USE SIGNAL ;
    PORT
      LAYER M4 ;
        RECT  0 47.04 0.084 47.064 ;
    END
  END tap_d[202]
  PIN tap_d[203]
    DIRECTION OUTPUT ;
    USE SIGNAL ;
    PORT
      LAYER M4 ;
        RECT  0 47.136 0.084 47.16 ;
    END
  END tap_d[203]
  PIN tap_d[204]
    DIRECTION OUTPUT ;
    USE SIGNAL ;
    PORT
      LAYER M4 ;
        RECT  0 47.28 0.084 47.304 ;
    END
  END tap_d[204]
  PIN tap_d[205]
    DIRECTION OUTPUT ;
    USE SIGNAL ;
    PORT
      LAYER M4 ;
        RECT  0 47.376 0.084 47.4 ;
    END
  END tap_d[205]
  PIN tap_d[206]
    DIRECTION OUTPUT ;
    USE SIGNAL ;
    PORT
      LAYER M4 ;
        RECT  0 47.472 0.084 47.496 ;
    END
  END tap_d[206]
  PIN tap_d[207]
    DIRECTION OUTPUT ;
    USE SIGNAL ;
    PORT
      LAYER M4 ;
        RECT  0 47.568 0.084 47.592 ;
    END
  END tap_d[207]
  PIN tap_d[208]
    DIRECTION OUTPUT ;
    USE SIGNAL ;
    PORT
      LAYER M4 ;
        RECT  0 47.664 0.084 47.688 ;
    END
  END tap_d[208]
  PIN tap_d[209]
    DIRECTION OUTPUT ;
    USE SIGNAL ;
    PORT
      LAYER M4 ;
        RECT  0 47.76 0.084 47.784 ;
    END
  END tap_d[209]
  PIN tap_d[20]
    DIRECTION OUTPUT ;
    USE SIGNAL ;
    PORT
      LAYER M4 ;
        RECT  0 28.944 0.084 28.968 ;
    END
  END tap_d[20]
  PIN tap_d[210]
    DIRECTION OUTPUT ;
    USE SIGNAL ;
    PORT
      LAYER M4 ;
        RECT  0 47.856 0.084 47.88 ;
    END
  END tap_d[210]
  PIN tap_d[211]
    DIRECTION OUTPUT ;
    USE SIGNAL ;
    PORT
      LAYER M4 ;
        RECT  0 47.952 0.084 47.976 ;
    END
  END tap_d[211]
  PIN tap_d[212]
    DIRECTION OUTPUT ;
    USE SIGNAL ;
    PORT
      LAYER M4 ;
        RECT  0 48.048 0.084 48.072 ;
    END
  END tap_d[212]
  PIN tap_d[213]
    DIRECTION OUTPUT ;
    USE SIGNAL ;
    PORT
      LAYER M4 ;
        RECT  0 48.144 0.084 48.168 ;
    END
  END tap_d[213]
  PIN tap_d[214]
    DIRECTION OUTPUT ;
    USE SIGNAL ;
    PORT
      LAYER M4 ;
        RECT  0 48.24 0.084 48.264 ;
    END
  END tap_d[214]
  PIN tap_d[215]
    DIRECTION OUTPUT ;
    USE SIGNAL ;
    PORT
      LAYER M4 ;
        RECT  0 48.336 0.084 48.36 ;
    END
  END tap_d[215]
  PIN tap_d[216]
    DIRECTION OUTPUT ;
    USE SIGNAL ;
    PORT
      LAYER M4 ;
        RECT  0 48.432 0.084 48.456 ;
    END
  END tap_d[216]
  PIN tap_d[217]
    DIRECTION OUTPUT ;
    USE SIGNAL ;
    PORT
      LAYER M4 ;
        RECT  0 48.528 0.084 48.552 ;
    END
  END tap_d[217]
  PIN tap_d[218]
    DIRECTION OUTPUT ;
    USE SIGNAL ;
    PORT
      LAYER M4 ;
        RECT  0 48.624 0.084 48.648 ;
    END
  END tap_d[218]
  PIN tap_d[219]
    DIRECTION OUTPUT ;
    USE SIGNAL ;
    PORT
      LAYER M4 ;
        RECT  0 48.768 0.084 48.792 ;
    END
  END tap_d[219]
  PIN tap_d[21]
    DIRECTION OUTPUT ;
    USE SIGNAL ;
    PORT
      LAYER M4 ;
        RECT  0 29.088 0.084 29.112 ;
    END
  END tap_d[21]
  PIN tap_d[220]
    DIRECTION OUTPUT ;
    USE SIGNAL ;
    PORT
      LAYER M4 ;
        RECT  0 48.864 0.084 48.888 ;
    END
  END tap_d[220]
  PIN tap_d[221]
    DIRECTION OUTPUT ;
    USE SIGNAL ;
    PORT
      LAYER M4 ;
        RECT  0 48.96 0.084 48.984 ;
    END
  END tap_d[221]
  PIN tap_d[222]
    DIRECTION OUTPUT ;
    USE SIGNAL ;
    PORT
      LAYER M4 ;
        RECT  0 49.056 0.084 49.08 ;
    END
  END tap_d[222]
  PIN tap_d[223]
    DIRECTION OUTPUT ;
    USE SIGNAL ;
    PORT
      LAYER M4 ;
        RECT  0 49.152 0.084 49.176 ;
    END
  END tap_d[223]
  PIN tap_d[224]
    DIRECTION OUTPUT ;
    USE SIGNAL ;
    PORT
      LAYER M4 ;
        RECT  0 49.248 0.084 49.272 ;
    END
  END tap_d[224]
  PIN tap_d[225]
    DIRECTION OUTPUT ;
    USE SIGNAL ;
    PORT
      LAYER M4 ;
        RECT  0 49.344 0.084 49.368 ;
    END
  END tap_d[225]
  PIN tap_d[226]
    DIRECTION OUTPUT ;
    USE SIGNAL ;
    PORT
      LAYER M4 ;
        RECT  0 49.44 0.084 49.464 ;
    END
  END tap_d[226]
  PIN tap_d[227]
    DIRECTION OUTPUT ;
    USE SIGNAL ;
    PORT
      LAYER M4 ;
        RECT  0 49.536 0.084 49.56 ;
    END
  END tap_d[227]
  PIN tap_d[228]
    DIRECTION OUTPUT ;
    USE SIGNAL ;
    PORT
      LAYER M4 ;
        RECT  0 49.632 0.084 49.656 ;
    END
  END tap_d[228]
  PIN tap_d[229]
    DIRECTION OUTPUT ;
    USE SIGNAL ;
    PORT
      LAYER M4 ;
        RECT  0 49.728 0.084 49.752 ;
    END
  END tap_d[229]
  PIN tap_d[22]
    DIRECTION OUTPUT ;
    USE SIGNAL ;
    PORT
      LAYER M4 ;
        RECT  0 29.184 0.084 29.208 ;
    END
  END tap_d[22]
  PIN tap_d[230]
    DIRECTION OUTPUT ;
    USE SIGNAL ;
    PORT
      LAYER M4 ;
        RECT  0 49.824 0.084 49.848 ;
    END
  END tap_d[230]
  PIN tap_d[231]
    DIRECTION OUTPUT ;
    USE SIGNAL ;
    PORT
      LAYER M4 ;
        RECT  0 49.92 0.084 49.944 ;
    END
  END tap_d[231]
  PIN tap_d[232]
    DIRECTION OUTPUT ;
    USE SIGNAL ;
    PORT
      LAYER M4 ;
        RECT  0 50.016 0.084 50.04 ;
    END
  END tap_d[232]
  PIN tap_d[233]
    DIRECTION OUTPUT ;
    USE SIGNAL ;
    PORT
      LAYER M4 ;
        RECT  0 50.16 0.084 50.184 ;
    END
  END tap_d[233]
  PIN tap_d[234]
    DIRECTION OUTPUT ;
    USE SIGNAL ;
    PORT
      LAYER M4 ;
        RECT  0 50.256 0.084 50.28 ;
    END
  END tap_d[234]
  PIN tap_d[235]
    DIRECTION OUTPUT ;
    USE SIGNAL ;
    PORT
      LAYER M4 ;
        RECT  0 50.352 0.084 50.376 ;
    END
  END tap_d[235]
  PIN tap_d[236]
    DIRECTION OUTPUT ;
    USE SIGNAL ;
    PORT
      LAYER M4 ;
        RECT  0 50.448 0.084 50.472 ;
    END
  END tap_d[236]
  PIN tap_d[237]
    DIRECTION OUTPUT ;
    USE SIGNAL ;
    PORT
      LAYER M4 ;
        RECT  0 50.544 0.084 50.568 ;
    END
  END tap_d[237]
  PIN tap_d[238]
    DIRECTION OUTPUT ;
    USE SIGNAL ;
    PORT
      LAYER M4 ;
        RECT  0 50.64 0.084 50.664 ;
    END
  END tap_d[238]
  PIN tap_d[239]
    DIRECTION OUTPUT ;
    USE SIGNAL ;
    PORT
      LAYER M4 ;
        RECT  0 50.736 0.084 50.76 ;
    END
  END tap_d[239]
  PIN tap_d[23]
    DIRECTION OUTPUT ;
    USE SIGNAL ;
    PORT
      LAYER M4 ;
        RECT  0 29.28 0.084 29.304 ;
    END
  END tap_d[23]
  PIN tap_d[240]
    DIRECTION OUTPUT ;
    USE SIGNAL ;
    PORT
      LAYER M4 ;
        RECT  0 50.832 0.084 50.856 ;
    END
  END tap_d[240]
  PIN tap_d[241]
    DIRECTION OUTPUT ;
    USE SIGNAL ;
    PORT
      LAYER M4 ;
        RECT  0 50.928 0.084 50.952 ;
    END
  END tap_d[241]
  PIN tap_d[242]
    DIRECTION OUTPUT ;
    USE SIGNAL ;
    PORT
      LAYER M4 ;
        RECT  0 51.024 0.084 51.048 ;
    END
  END tap_d[242]
  PIN tap_d[243]
    DIRECTION OUTPUT ;
    USE SIGNAL ;
    PORT
      LAYER M4 ;
        RECT  0 51.12 0.084 51.144 ;
    END
  END tap_d[243]
  PIN tap_d[244]
    DIRECTION OUTPUT ;
    USE SIGNAL ;
    PORT
      LAYER M4 ;
        RECT  0 51.216 0.084 51.24 ;
    END
  END tap_d[244]
  PIN tap_d[245]
    DIRECTION OUTPUT ;
    USE SIGNAL ;
    PORT
      LAYER M4 ;
        RECT  0 51.312 0.084 51.336 ;
    END
  END tap_d[245]
  PIN tap_d[246]
    DIRECTION OUTPUT ;
    USE SIGNAL ;
    PORT
      LAYER M4 ;
        RECT  0 51.408 0.084 51.432 ;
    END
  END tap_d[246]
  PIN tap_d[247]
    DIRECTION OUTPUT ;
    USE SIGNAL ;
    PORT
      LAYER M4 ;
        RECT  0 51.552 0.084 51.576 ;
    END
  END tap_d[247]
  PIN tap_d[248]
    DIRECTION OUTPUT ;
    USE SIGNAL ;
    PORT
      LAYER M4 ;
        RECT  0 51.648 0.084 51.672 ;
    END
  END tap_d[248]
  PIN tap_d[249]
    DIRECTION OUTPUT ;
    USE SIGNAL ;
    PORT
      LAYER M4 ;
        RECT  0 51.744 0.084 51.768 ;
    END
  END tap_d[249]
  PIN tap_d[24]
    DIRECTION OUTPUT ;
    USE SIGNAL ;
    PORT
      LAYER M4 ;
        RECT  0 29.376 0.084 29.4 ;
    END
  END tap_d[24]
  PIN tap_d[250]
    DIRECTION OUTPUT ;
    USE SIGNAL ;
    PORT
      LAYER M4 ;
        RECT  0 51.84 0.084 51.864 ;
    END
  END tap_d[250]
  PIN tap_d[251]
    DIRECTION OUTPUT ;
    USE SIGNAL ;
    PORT
      LAYER M4 ;
        RECT  0 51.936 0.084 51.96 ;
    END
  END tap_d[251]
  PIN tap_d[252]
    DIRECTION OUTPUT ;
    USE SIGNAL ;
    PORT
      LAYER M4 ;
        RECT  0 52.032 0.084 52.056 ;
    END
  END tap_d[252]
  PIN tap_d[253]
    DIRECTION OUTPUT ;
    USE SIGNAL ;
    PORT
      LAYER M4 ;
        RECT  0 52.128 0.084 52.152 ;
    END
  END tap_d[253]
  PIN tap_d[254]
    DIRECTION OUTPUT ;
    USE SIGNAL ;
    PORT
      LAYER M4 ;
        RECT  0 52.224 0.084 52.248 ;
    END
  END tap_d[254]
  PIN tap_d[255]
    DIRECTION OUTPUT ;
    USE SIGNAL ;
    PORT
      LAYER M4 ;
        RECT  0 52.32 0.084 52.344 ;
    END
  END tap_d[255]
  PIN tap_d[256]
    DIRECTION OUTPUT ;
    USE SIGNAL ;
    PORT
      LAYER M4 ;
        RECT  0 52.416 0.084 52.44 ;
    END
  END tap_d[256]
  PIN tap_d[257]
    DIRECTION OUTPUT ;
    USE SIGNAL ;
    PORT
      LAYER M4 ;
        RECT  0 52.512 0.084 52.536 ;
    END
  END tap_d[257]
  PIN tap_d[258]
    DIRECTION OUTPUT ;
    USE SIGNAL ;
    PORT
      LAYER M4 ;
        RECT  0 52.608 0.084 52.632 ;
    END
  END tap_d[258]
  PIN tap_d[259]
    DIRECTION OUTPUT ;
    USE SIGNAL ;
    PORT
      LAYER M4 ;
        RECT  0 52.704 0.084 52.728 ;
    END
  END tap_d[259]
  PIN tap_d[25]
    DIRECTION OUTPUT ;
    USE SIGNAL ;
    PORT
      LAYER M4 ;
        RECT  0 29.472 0.084 29.496 ;
    END
  END tap_d[25]
  PIN tap_d[260]
    DIRECTION OUTPUT ;
    USE SIGNAL ;
    PORT
      LAYER M4 ;
        RECT  0 52.8 0.084 52.824 ;
    END
  END tap_d[260]
  PIN tap_d[261]
    DIRECTION OUTPUT ;
    USE SIGNAL ;
    PORT
      LAYER M4 ;
        RECT  0 52.944 0.084 52.968 ;
    END
  END tap_d[261]
  PIN tap_d[262]
    DIRECTION OUTPUT ;
    USE SIGNAL ;
    PORT
      LAYER M4 ;
        RECT  0 53.04 0.084 53.064 ;
    END
  END tap_d[262]
  PIN tap_d[263]
    DIRECTION OUTPUT ;
    USE SIGNAL ;
    PORT
      LAYER M4 ;
        RECT  0 53.136 0.084 53.16 ;
    END
  END tap_d[263]
  PIN tap_d[264]
    DIRECTION OUTPUT ;
    USE SIGNAL ;
    PORT
      LAYER M4 ;
        RECT  0 53.232 0.084 53.256 ;
    END
  END tap_d[264]
  PIN tap_d[265]
    DIRECTION OUTPUT ;
    USE SIGNAL ;
    PORT
      LAYER M4 ;
        RECT  0 53.328 0.084 53.352 ;
    END
  END tap_d[265]
  PIN tap_d[266]
    DIRECTION OUTPUT ;
    USE SIGNAL ;
    PORT
      LAYER M4 ;
        RECT  0 53.424 0.084 53.448 ;
    END
  END tap_d[266]
  PIN tap_d[267]
    DIRECTION OUTPUT ;
    USE SIGNAL ;
    PORT
      LAYER M4 ;
        RECT  0 53.52 0.084 53.544 ;
    END
  END tap_d[267]
  PIN tap_d[268]
    DIRECTION OUTPUT ;
    USE SIGNAL ;
    PORT
      LAYER M4 ;
        RECT  0 53.616 0.084 53.64 ;
    END
  END tap_d[268]
  PIN tap_d[269]
    DIRECTION OUTPUT ;
    USE SIGNAL ;
    PORT
      LAYER M4 ;
        RECT  0 53.712 0.084 53.736 ;
    END
  END tap_d[269]
  PIN tap_d[26]
    DIRECTION OUTPUT ;
    USE SIGNAL ;
    PORT
      LAYER M4 ;
        RECT  0 29.568 0.084 29.592 ;
    END
  END tap_d[26]
  PIN tap_d[270]
    DIRECTION OUTPUT ;
    USE SIGNAL ;
    PORT
      LAYER M4 ;
        RECT  0 53.808 0.084 53.832 ;
    END
  END tap_d[270]
  PIN tap_d[271]
    DIRECTION OUTPUT ;
    USE SIGNAL ;
    PORT
      LAYER M4 ;
        RECT  0 53.904 0.084 53.928 ;
    END
  END tap_d[271]
  PIN tap_d[272]
    DIRECTION OUTPUT ;
    USE SIGNAL ;
    PORT
      LAYER M4 ;
        RECT  0 54 0.084 54.024 ;
    END
  END tap_d[272]
  PIN tap_d[273]
    DIRECTION OUTPUT ;
    USE SIGNAL ;
    PORT
      LAYER M4 ;
        RECT  0 54.096 0.084 54.12 ;
    END
  END tap_d[273]
  PIN tap_d[274]
    DIRECTION OUTPUT ;
    USE SIGNAL ;
    PORT
      LAYER M4 ;
        RECT  0 54.192 0.084 54.216 ;
    END
  END tap_d[274]
  PIN tap_d[275]
    DIRECTION OUTPUT ;
    USE SIGNAL ;
    PORT
      LAYER M4 ;
        RECT  0 54.336 0.084 54.36 ;
    END
  END tap_d[275]
  PIN tap_d[276]
    DIRECTION OUTPUT ;
    USE SIGNAL ;
    PORT
      LAYER M4 ;
        RECT  0 54.432 0.084 54.456 ;
    END
  END tap_d[276]
  PIN tap_d[277]
    DIRECTION OUTPUT ;
    USE SIGNAL ;
    PORT
      LAYER M4 ;
        RECT  0 54.528 0.084 54.552 ;
    END
  END tap_d[277]
  PIN tap_d[278]
    DIRECTION OUTPUT ;
    USE SIGNAL ;
    PORT
      LAYER M4 ;
        RECT  0 54.624 0.084 54.648 ;
    END
  END tap_d[278]
  PIN tap_d[279]
    DIRECTION OUTPUT ;
    USE SIGNAL ;
    PORT
      LAYER M4 ;
        RECT  0 54.72 0.084 54.744 ;
    END
  END tap_d[279]
  PIN tap_d[27]
    DIRECTION OUTPUT ;
    USE SIGNAL ;
    PORT
      LAYER M4 ;
        RECT  0 29.664 0.084 29.688 ;
    END
  END tap_d[27]
  PIN tap_d[280]
    DIRECTION OUTPUT ;
    USE SIGNAL ;
    PORT
      LAYER M4 ;
        RECT  0 54.816 0.084 54.84 ;
    END
  END tap_d[280]
  PIN tap_d[281]
    DIRECTION OUTPUT ;
    USE SIGNAL ;
    PORT
      LAYER M4 ;
        RECT  0 54.912 0.084 54.936 ;
    END
  END tap_d[281]
  PIN tap_d[282]
    DIRECTION OUTPUT ;
    USE SIGNAL ;
    PORT
      LAYER M4 ;
        RECT  0 55.008 0.084 55.032 ;
    END
  END tap_d[282]
  PIN tap_d[283]
    DIRECTION OUTPUT ;
    USE SIGNAL ;
    PORT
      LAYER M4 ;
        RECT  0 55.104 0.084 55.128 ;
    END
  END tap_d[283]
  PIN tap_d[284]
    DIRECTION OUTPUT ;
    USE SIGNAL ;
    PORT
      LAYER M4 ;
        RECT  0 55.2 0.084 55.224 ;
    END
  END tap_d[284]
  PIN tap_d[285]
    DIRECTION OUTPUT ;
    USE SIGNAL ;
    PORT
      LAYER M4 ;
        RECT  0 55.296 0.084 55.32 ;
    END
  END tap_d[285]
  PIN tap_d[286]
    DIRECTION OUTPUT ;
    USE SIGNAL ;
    PORT
      LAYER M4 ;
        RECT  0 55.392 0.084 55.416 ;
    END
  END tap_d[286]
  PIN tap_d[287]
    DIRECTION OUTPUT ;
    USE SIGNAL ;
    PORT
      LAYER M4 ;
        RECT  0 55.488 0.084 55.512 ;
    END
  END tap_d[287]
  PIN tap_d[288]
    DIRECTION OUTPUT ;
    USE SIGNAL ;
    PORT
      LAYER M4 ;
        RECT  0 55.584 0.084 55.608 ;
    END
  END tap_d[288]
  PIN tap_d[289]
    DIRECTION OUTPUT ;
    USE SIGNAL ;
    PORT
      LAYER M4 ;
        RECT  0 55.728 0.084 55.752 ;
    END
  END tap_d[289]
  PIN tap_d[28]
    DIRECTION OUTPUT ;
    USE SIGNAL ;
    PORT
      LAYER M4 ;
        RECT  0 29.76 0.084 29.784 ;
    END
  END tap_d[28]
  PIN tap_d[290]
    DIRECTION OUTPUT ;
    USE SIGNAL ;
    PORT
      LAYER M4 ;
        RECT  0 55.824 0.084 55.848 ;
    END
  END tap_d[290]
  PIN tap_d[291]
    DIRECTION OUTPUT ;
    USE SIGNAL ;
    PORT
      LAYER M4 ;
        RECT  0 55.92 0.084 55.944 ;
    END
  END tap_d[291]
  PIN tap_d[292]
    DIRECTION OUTPUT ;
    USE SIGNAL ;
    PORT
      LAYER M4 ;
        RECT  0 56.016 0.084 56.04 ;
    END
  END tap_d[292]
  PIN tap_d[293]
    DIRECTION OUTPUT ;
    USE SIGNAL ;
    PORT
      LAYER M4 ;
        RECT  0 56.112 0.084 56.136 ;
    END
  END tap_d[293]
  PIN tap_d[294]
    DIRECTION OUTPUT ;
    USE SIGNAL ;
    PORT
      LAYER M4 ;
        RECT  0 56.208 0.084 56.232 ;
    END
  END tap_d[294]
  PIN tap_d[295]
    DIRECTION OUTPUT ;
    USE SIGNAL ;
    PORT
      LAYER M4 ;
        RECT  0 56.304 0.084 56.328 ;
    END
  END tap_d[295]
  PIN tap_d[296]
    DIRECTION OUTPUT ;
    USE SIGNAL ;
    PORT
      LAYER M4 ;
        RECT  0 56.4 0.084 56.424 ;
    END
  END tap_d[296]
  PIN tap_d[297]
    DIRECTION OUTPUT ;
    USE SIGNAL ;
    PORT
      LAYER M4 ;
        RECT  0 56.496 0.084 56.52 ;
    END
  END tap_d[297]
  PIN tap_d[298]
    DIRECTION OUTPUT ;
    USE SIGNAL ;
    PORT
      LAYER M4 ;
        RECT  0 56.592 0.084 56.616 ;
    END
  END tap_d[298]
  PIN tap_d[299]
    DIRECTION OUTPUT ;
    USE SIGNAL ;
    PORT
      LAYER M4 ;
        RECT  0 56.688 0.084 56.712 ;
    END
  END tap_d[299]
  PIN tap_d[29]
    DIRECTION OUTPUT ;
    USE SIGNAL ;
    PORT
      LAYER M4 ;
        RECT  0 29.856 0.084 29.88 ;
    END
  END tap_d[29]
  PIN tap_d[2]
    DIRECTION OUTPUT ;
    USE SIGNAL ;
    PORT
      LAYER M4 ;
        RECT  0 27.168 0.084 27.192 ;
    END
  END tap_d[2]
  PIN tap_d[300]
    DIRECTION OUTPUT ;
    USE SIGNAL ;
    PORT
      LAYER M4 ;
        RECT  0 56.784 0.084 56.808 ;
    END
  END tap_d[300]
  PIN tap_d[301]
    DIRECTION OUTPUT ;
    USE SIGNAL ;
    PORT
      LAYER M4 ;
        RECT  0 56.88 0.084 56.904 ;
    END
  END tap_d[301]
  PIN tap_d[302]
    DIRECTION OUTPUT ;
    USE SIGNAL ;
    PORT
      LAYER M4 ;
        RECT  0 56.976 0.084 57 ;
    END
  END tap_d[302]
  PIN tap_d[303]
    DIRECTION OUTPUT ;
    USE SIGNAL ;
    PORT
      LAYER M4 ;
        RECT  0 57.12 0.084 57.144 ;
    END
  END tap_d[303]
  PIN tap_d[304]
    DIRECTION OUTPUT ;
    USE SIGNAL ;
    PORT
      LAYER M4 ;
        RECT  0 57.216 0.084 57.24 ;
    END
  END tap_d[304]
  PIN tap_d[305]
    DIRECTION OUTPUT ;
    USE SIGNAL ;
    PORT
      LAYER M4 ;
        RECT  0 57.312 0.084 57.336 ;
    END
  END tap_d[305]
  PIN tap_d[306]
    DIRECTION OUTPUT ;
    USE SIGNAL ;
    PORT
      LAYER M4 ;
        RECT  0 57.408 0.084 57.432 ;
    END
  END tap_d[306]
  PIN tap_d[307]
    DIRECTION OUTPUT ;
    USE SIGNAL ;
    PORT
      LAYER M4 ;
        RECT  0 57.504 0.084 57.528 ;
    END
  END tap_d[307]
  PIN tap_d[308]
    DIRECTION OUTPUT ;
    USE SIGNAL ;
    PORT
      LAYER M4 ;
        RECT  0 57.6 0.084 57.624 ;
    END
  END tap_d[308]
  PIN tap_d[309]
    DIRECTION OUTPUT ;
    USE SIGNAL ;
    PORT
      LAYER M4 ;
        RECT  0 57.696 0.084 57.72 ;
    END
  END tap_d[309]
  PIN tap_d[30]
    DIRECTION OUTPUT ;
    USE SIGNAL ;
    PORT
      LAYER M4 ;
        RECT  0 29.952 0.084 29.976 ;
    END
  END tap_d[30]
  PIN tap_d[310]
    DIRECTION OUTPUT ;
    USE SIGNAL ;
    PORT
      LAYER M4 ;
        RECT  0 57.792 0.084 57.816 ;
    END
  END tap_d[310]
  PIN tap_d[311]
    DIRECTION OUTPUT ;
    USE SIGNAL ;
    PORT
      LAYER M4 ;
        RECT  0 57.888 0.084 57.912 ;
    END
  END tap_d[311]
  PIN tap_d[312]
    DIRECTION OUTPUT ;
    USE SIGNAL ;
    PORT
      LAYER M4 ;
        RECT  0 57.984 0.084 58.008 ;
    END
  END tap_d[312]
  PIN tap_d[313]
    DIRECTION OUTPUT ;
    USE SIGNAL ;
    PORT
      LAYER M4 ;
        RECT  0 58.08 0.084 58.104 ;
    END
  END tap_d[313]
  PIN tap_d[314]
    DIRECTION OUTPUT ;
    USE SIGNAL ;
    PORT
      LAYER M4 ;
        RECT  0 58.176 0.084 58.2 ;
    END
  END tap_d[314]
  PIN tap_d[315]
    DIRECTION OUTPUT ;
    USE SIGNAL ;
    PORT
      LAYER M4 ;
        RECT  0 58.272 0.084 58.296 ;
    END
  END tap_d[315]
  PIN tap_d[316]
    DIRECTION OUTPUT ;
    USE SIGNAL ;
    PORT
      LAYER M4 ;
        RECT  0 58.368 0.084 58.392 ;
    END
  END tap_d[316]
  PIN tap_d[317]
    DIRECTION OUTPUT ;
    USE SIGNAL ;
    PORT
      LAYER M4 ;
        RECT  0 58.512 0.084 58.536 ;
    END
  END tap_d[317]
  PIN tap_d[318]
    DIRECTION OUTPUT ;
    USE SIGNAL ;
    PORT
      LAYER M4 ;
        RECT  0 58.608 0.084 58.632 ;
    END
  END tap_d[318]
  PIN tap_d[319]
    DIRECTION OUTPUT ;
    USE SIGNAL ;
    PORT
      LAYER M4 ;
        RECT  0 58.704 0.084 58.728 ;
    END
  END tap_d[319]
  PIN tap_d[31]
    DIRECTION OUTPUT ;
    USE SIGNAL ;
    PORT
      LAYER M4 ;
        RECT  0 30.048 0.084 30.072 ;
    END
  END tap_d[31]
  PIN tap_d[320]
    DIRECTION OUTPUT ;
    USE SIGNAL ;
    PORT
      LAYER M4 ;
        RECT  0 58.8 0.084 58.824 ;
    END
  END tap_d[320]
  PIN tap_d[321]
    DIRECTION OUTPUT ;
    USE SIGNAL ;
    PORT
      LAYER M4 ;
        RECT  0 58.896 0.084 58.92 ;
    END
  END tap_d[321]
  PIN tap_d[322]
    DIRECTION OUTPUT ;
    USE SIGNAL ;
    PORT
      LAYER M4 ;
        RECT  0 58.992 0.084 59.016 ;
    END
  END tap_d[322]
  PIN tap_d[323]
    DIRECTION OUTPUT ;
    USE SIGNAL ;
    PORT
      LAYER M4 ;
        RECT  0 59.088 0.084 59.112 ;
    END
  END tap_d[323]
  PIN tap_d[324]
    DIRECTION OUTPUT ;
    USE SIGNAL ;
    PORT
      LAYER M4 ;
        RECT  0 59.184 0.084 59.208 ;
    END
  END tap_d[324]
  PIN tap_d[325]
    DIRECTION OUTPUT ;
    USE SIGNAL ;
    PORT
      LAYER M4 ;
        RECT  0 59.28 0.084 59.304 ;
    END
  END tap_d[325]
  PIN tap_d[326]
    DIRECTION OUTPUT ;
    USE SIGNAL ;
    PORT
      LAYER M4 ;
        RECT  0 59.376 0.084 59.4 ;
    END
  END tap_d[326]
  PIN tap_d[327]
    DIRECTION OUTPUT ;
    USE SIGNAL ;
    PORT
      LAYER M4 ;
        RECT  0 59.472 0.084 59.496 ;
    END
  END tap_d[327]
  PIN tap_d[328]
    DIRECTION OUTPUT ;
    USE SIGNAL ;
    PORT
      LAYER M4 ;
        RECT  0 59.568 0.084 59.592 ;
    END
  END tap_d[328]
  PIN tap_d[329]
    DIRECTION OUTPUT ;
    USE SIGNAL ;
    PORT
      LAYER M4 ;
        RECT  0 59.664 0.084 59.688 ;
    END
  END tap_d[329]
  PIN tap_d[32]
    DIRECTION OUTPUT ;
    USE SIGNAL ;
    PORT
      LAYER M4 ;
        RECT  0 30.144 0.084 30.168 ;
    END
  END tap_d[32]
  PIN tap_d[330]
    DIRECTION OUTPUT ;
    USE SIGNAL ;
    PORT
      LAYER M4 ;
        RECT  0 59.76 0.084 59.784 ;
    END
  END tap_d[330]
  PIN tap_d[331]
    DIRECTION OUTPUT ;
    USE SIGNAL ;
    PORT
      LAYER M4 ;
        RECT  0 59.904 0.084 59.928 ;
    END
  END tap_d[331]
  PIN tap_d[332]
    DIRECTION OUTPUT ;
    USE SIGNAL ;
    PORT
      LAYER M4 ;
        RECT  0 60 0.084 60.024 ;
    END
  END tap_d[332]
  PIN tap_d[333]
    DIRECTION OUTPUT ;
    USE SIGNAL ;
    PORT
      LAYER M4 ;
        RECT  0 60.096 0.084 60.12 ;
    END
  END tap_d[333]
  PIN tap_d[334]
    DIRECTION OUTPUT ;
    USE SIGNAL ;
    PORT
      LAYER M4 ;
        RECT  0 60.192 0.084 60.216 ;
    END
  END tap_d[334]
  PIN tap_d[335]
    DIRECTION OUTPUT ;
    USE SIGNAL ;
    PORT
      LAYER M4 ;
        RECT  0 60.288 0.084 60.312 ;
    END
  END tap_d[335]
  PIN tap_d[336]
    DIRECTION OUTPUT ;
    USE SIGNAL ;
    PORT
      LAYER M4 ;
        RECT  0 60.384 0.084 60.408 ;
    END
  END tap_d[336]
  PIN tap_d[337]
    DIRECTION OUTPUT ;
    USE SIGNAL ;
    PORT
      LAYER M4 ;
        RECT  0 60.48 0.084 60.504 ;
    END
  END tap_d[337]
  PIN tap_d[338]
    DIRECTION OUTPUT ;
    USE SIGNAL ;
    PORT
      LAYER M4 ;
        RECT  0 60.576 0.084 60.6 ;
    END
  END tap_d[338]
  PIN tap_d[339]
    DIRECTION OUTPUT ;
    USE SIGNAL ;
    PORT
      LAYER M4 ;
        RECT  0 60.672 0.084 60.696 ;
    END
  END tap_d[339]
  PIN tap_d[33]
    DIRECTION OUTPUT ;
    USE SIGNAL ;
    PORT
      LAYER M4 ;
        RECT  0 30.24 0.084 30.264 ;
    END
  END tap_d[33]
  PIN tap_d[340]
    DIRECTION OUTPUT ;
    USE SIGNAL ;
    PORT
      LAYER M4 ;
        RECT  0 60.768 0.084 60.792 ;
    END
  END tap_d[340]
  PIN tap_d[341]
    DIRECTION OUTPUT ;
    USE SIGNAL ;
    PORT
      LAYER M4 ;
        RECT  0 60.864 0.084 60.888 ;
    END
  END tap_d[341]
  PIN tap_d[342]
    DIRECTION OUTPUT ;
    USE SIGNAL ;
    PORT
      LAYER M4 ;
        RECT  0 60.96 0.084 60.984 ;
    END
  END tap_d[342]
  PIN tap_d[343]
    DIRECTION OUTPUT ;
    USE SIGNAL ;
    PORT
      LAYER M4 ;
        RECT  0 61.056 0.084 61.08 ;
    END
  END tap_d[343]
  PIN tap_d[344]
    DIRECTION OUTPUT ;
    USE SIGNAL ;
    PORT
      LAYER M4 ;
        RECT  0 61.152 0.084 61.176 ;
    END
  END tap_d[344]
  PIN tap_d[345]
    DIRECTION OUTPUT ;
    USE SIGNAL ;
    PORT
      LAYER M4 ;
        RECT  0 61.248 0.084 61.272 ;
    END
  END tap_d[345]
  PIN tap_d[346]
    DIRECTION OUTPUT ;
    USE SIGNAL ;
    PORT
      LAYER M4 ;
        RECT  0 61.392 0.084 61.416 ;
    END
  END tap_d[346]
  PIN tap_d[347]
    DIRECTION OUTPUT ;
    USE SIGNAL ;
    PORT
      LAYER M4 ;
        RECT  0 61.488 0.084 61.512 ;
    END
  END tap_d[347]
  PIN tap_d[348]
    DIRECTION OUTPUT ;
    USE SIGNAL ;
    PORT
      LAYER M4 ;
        RECT  0 61.584 0.084 61.608 ;
    END
  END tap_d[348]
  PIN tap_d[349]
    DIRECTION OUTPUT ;
    USE SIGNAL ;
    PORT
      LAYER M4 ;
        RECT  0 61.68 0.084 61.704 ;
    END
  END tap_d[349]
  PIN tap_d[34]
    DIRECTION OUTPUT ;
    USE SIGNAL ;
    PORT
      LAYER M4 ;
        RECT  0 30.336 0.084 30.36 ;
    END
  END tap_d[34]
  PIN tap_d[350]
    DIRECTION OUTPUT ;
    USE SIGNAL ;
    PORT
      LAYER M4 ;
        RECT  0 61.776 0.084 61.8 ;
    END
  END tap_d[350]
  PIN tap_d[351]
    DIRECTION OUTPUT ;
    USE SIGNAL ;
    PORT
      LAYER M4 ;
        RECT  0 61.872 0.084 61.896 ;
    END
  END tap_d[351]
  PIN tap_d[352]
    DIRECTION OUTPUT ;
    USE SIGNAL ;
    PORT
      LAYER M4 ;
        RECT  0 61.968 0.084 61.992 ;
    END
  END tap_d[352]
  PIN tap_d[353]
    DIRECTION OUTPUT ;
    USE SIGNAL ;
    PORT
      LAYER M4 ;
        RECT  0 62.064 0.084 62.088 ;
    END
  END tap_d[353]
  PIN tap_d[354]
    DIRECTION OUTPUT ;
    USE SIGNAL ;
    PORT
      LAYER M4 ;
        RECT  0 62.16 0.084 62.184 ;
    END
  END tap_d[354]
  PIN tap_d[355]
    DIRECTION OUTPUT ;
    USE SIGNAL ;
    PORT
      LAYER M4 ;
        RECT  0 62.256 0.084 62.28 ;
    END
  END tap_d[355]
  PIN tap_d[356]
    DIRECTION OUTPUT ;
    USE SIGNAL ;
    PORT
      LAYER M4 ;
        RECT  0 62.352 0.084 62.376 ;
    END
  END tap_d[356]
  PIN tap_d[357]
    DIRECTION OUTPUT ;
    USE SIGNAL ;
    PORT
      LAYER M4 ;
        RECT  0 62.448 0.084 62.472 ;
    END
  END tap_d[357]
  PIN tap_d[358]
    DIRECTION OUTPUT ;
    USE SIGNAL ;
    PORT
      LAYER M4 ;
        RECT  0 62.544 0.084 62.568 ;
    END
  END tap_d[358]
  PIN tap_d[359]
    DIRECTION OUTPUT ;
    USE SIGNAL ;
    PORT
      LAYER M4 ;
        RECT  0 62.64 0.084 62.664 ;
    END
  END tap_d[359]
  PIN tap_d[35]
    DIRECTION OUTPUT ;
    USE SIGNAL ;
    PORT
      LAYER M4 ;
        RECT  0 30.48 0.084 30.504 ;
    END
  END tap_d[35]
  PIN tap_d[360]
    DIRECTION OUTPUT ;
    USE SIGNAL ;
    PORT
      LAYER M4 ;
        RECT  0 62.784 0.084 62.808 ;
    END
  END tap_d[360]
  PIN tap_d[361]
    DIRECTION OUTPUT ;
    USE SIGNAL ;
    PORT
      LAYER M4 ;
        RECT  0 62.88 0.084 62.904 ;
    END
  END tap_d[361]
  PIN tap_d[362]
    DIRECTION OUTPUT ;
    USE SIGNAL ;
    PORT
      LAYER M4 ;
        RECT  0 62.976 0.084 63 ;
    END
  END tap_d[362]
  PIN tap_d[363]
    DIRECTION OUTPUT ;
    USE SIGNAL ;
    PORT
      LAYER M4 ;
        RECT  0 63.072 0.084 63.096 ;
    END
  END tap_d[363]
  PIN tap_d[364]
    DIRECTION OUTPUT ;
    USE SIGNAL ;
    PORT
      LAYER M4 ;
        RECT  0 63.168 0.084 63.192 ;
    END
  END tap_d[364]
  PIN tap_d[365]
    DIRECTION OUTPUT ;
    USE SIGNAL ;
    PORT
      LAYER M4 ;
        RECT  0 63.264 0.084 63.288 ;
    END
  END tap_d[365]
  PIN tap_d[366]
    DIRECTION OUTPUT ;
    USE SIGNAL ;
    PORT
      LAYER M4 ;
        RECT  0 63.36 0.084 63.384 ;
    END
  END tap_d[366]
  PIN tap_d[367]
    DIRECTION OUTPUT ;
    USE SIGNAL ;
    PORT
      LAYER M4 ;
        RECT  0 63.456 0.084 63.48 ;
    END
  END tap_d[367]
  PIN tap_d[368]
    DIRECTION OUTPUT ;
    USE SIGNAL ;
    PORT
      LAYER M4 ;
        RECT  0 63.552 0.084 63.576 ;
    END
  END tap_d[368]
  PIN tap_d[369]
    DIRECTION OUTPUT ;
    USE SIGNAL ;
    PORT
      LAYER M4 ;
        RECT  0 63.648 0.084 63.672 ;
    END
  END tap_d[369]
  PIN tap_d[36]
    DIRECTION OUTPUT ;
    USE SIGNAL ;
    PORT
      LAYER M4 ;
        RECT  0 30.576 0.084 30.6 ;
    END
  END tap_d[36]
  PIN tap_d[370]
    DIRECTION OUTPUT ;
    USE SIGNAL ;
    PORT
      LAYER M4 ;
        RECT  0 63.744 0.084 63.768 ;
    END
  END tap_d[370]
  PIN tap_d[371]
    DIRECTION OUTPUT ;
    USE SIGNAL ;
    PORT
      LAYER M4 ;
        RECT  0 63.84 0.084 63.864 ;
    END
  END tap_d[371]
  PIN tap_d[372]
    DIRECTION OUTPUT ;
    USE SIGNAL ;
    PORT
      LAYER M4 ;
        RECT  0 63.936 0.084 63.96 ;
    END
  END tap_d[372]
  PIN tap_d[373]
    DIRECTION OUTPUT ;
    USE SIGNAL ;
    PORT
      LAYER M4 ;
        RECT  0 64.032 0.084 64.056 ;
    END
  END tap_d[373]
  PIN tap_d[374]
    DIRECTION OUTPUT ;
    USE SIGNAL ;
    PORT
      LAYER M4 ;
        RECT  0 64.176 0.084 64.2 ;
    END
  END tap_d[374]
  PIN tap_d[375]
    DIRECTION OUTPUT ;
    USE SIGNAL ;
    PORT
      LAYER M4 ;
        RECT  0 64.272 0.084 64.296 ;
    END
  END tap_d[375]
  PIN tap_d[376]
    DIRECTION OUTPUT ;
    USE SIGNAL ;
    PORT
      LAYER M4 ;
        RECT  0 64.368 0.084 64.392 ;
    END
  END tap_d[376]
  PIN tap_d[377]
    DIRECTION OUTPUT ;
    USE SIGNAL ;
    PORT
      LAYER M4 ;
        RECT  0 64.464 0.084 64.488 ;
    END
  END tap_d[377]
  PIN tap_d[378]
    DIRECTION OUTPUT ;
    USE SIGNAL ;
    PORT
      LAYER M4 ;
        RECT  0 64.56 0.084 64.584 ;
    END
  END tap_d[378]
  PIN tap_d[379]
    DIRECTION OUTPUT ;
    USE SIGNAL ;
    PORT
      LAYER M4 ;
        RECT  0 64.656 0.084 64.68 ;
    END
  END tap_d[379]
  PIN tap_d[37]
    DIRECTION OUTPUT ;
    USE SIGNAL ;
    PORT
      LAYER M4 ;
        RECT  0 30.672 0.084 30.696 ;
    END
  END tap_d[37]
  PIN tap_d[380]
    DIRECTION OUTPUT ;
    USE SIGNAL ;
    PORT
      LAYER M4 ;
        RECT  0 64.752 0.084 64.776 ;
    END
  END tap_d[380]
  PIN tap_d[381]
    DIRECTION OUTPUT ;
    USE SIGNAL ;
    PORT
      LAYER M4 ;
        RECT  0 64.848 0.084 64.872 ;
    END
  END tap_d[381]
  PIN tap_d[382]
    DIRECTION OUTPUT ;
    USE SIGNAL ;
    PORT
      LAYER M4 ;
        RECT  0 64.944 0.084 64.968 ;
    END
  END tap_d[382]
  PIN tap_d[383]
    DIRECTION OUTPUT ;
    USE SIGNAL ;
    PORT
      LAYER M4 ;
        RECT  0 65.04 0.084 65.064 ;
    END
  END tap_d[383]
  PIN tap_d[384]
    DIRECTION OUTPUT ;
    USE SIGNAL ;
    PORT
      LAYER M4 ;
        RECT  0 65.136 0.084 65.16 ;
    END
  END tap_d[384]
  PIN tap_d[385]
    DIRECTION OUTPUT ;
    USE SIGNAL ;
    PORT
      LAYER M4 ;
        RECT  0 65.232 0.084 65.256 ;
    END
  END tap_d[385]
  PIN tap_d[386]
    DIRECTION OUTPUT ;
    USE SIGNAL ;
    PORT
      LAYER M4 ;
        RECT  0 65.328 0.084 65.352 ;
    END
  END tap_d[386]
  PIN tap_d[387]
    DIRECTION OUTPUT ;
    USE SIGNAL ;
    PORT
      LAYER M4 ;
        RECT  0 65.424 0.084 65.448 ;
    END
  END tap_d[387]
  PIN tap_d[388]
    DIRECTION OUTPUT ;
    USE SIGNAL ;
    PORT
      LAYER M4 ;
        RECT  0 65.568 0.084 65.592 ;
    END
  END tap_d[388]
  PIN tap_d[389]
    DIRECTION OUTPUT ;
    USE SIGNAL ;
    PORT
      LAYER M4 ;
        RECT  0 65.664 0.084 65.688 ;
    END
  END tap_d[389]
  PIN tap_d[38]
    DIRECTION OUTPUT ;
    USE SIGNAL ;
    PORT
      LAYER M4 ;
        RECT  0 30.768 0.084 30.792 ;
    END
  END tap_d[38]
  PIN tap_d[390]
    DIRECTION OUTPUT ;
    USE SIGNAL ;
    PORT
      LAYER M4 ;
        RECT  0 65.76 0.084 65.784 ;
    END
  END tap_d[390]
  PIN tap_d[391]
    DIRECTION OUTPUT ;
    USE SIGNAL ;
    PORT
      LAYER M4 ;
        RECT  0 65.856 0.084 65.88 ;
    END
  END tap_d[391]
  PIN tap_d[392]
    DIRECTION OUTPUT ;
    USE SIGNAL ;
    PORT
      LAYER M4 ;
        RECT  0 65.952 0.084 65.976 ;
    END
  END tap_d[392]
  PIN tap_d[393]
    DIRECTION OUTPUT ;
    USE SIGNAL ;
    PORT
      LAYER M4 ;
        RECT  0 66.048 0.084 66.072 ;
    END
  END tap_d[393]
  PIN tap_d[394]
    DIRECTION OUTPUT ;
    USE SIGNAL ;
    PORT
      LAYER M4 ;
        RECT  0 66.144 0.084 66.168 ;
    END
  END tap_d[394]
  PIN tap_d[395]
    DIRECTION OUTPUT ;
    USE SIGNAL ;
    PORT
      LAYER M4 ;
        RECT  0 66.24 0.084 66.264 ;
    END
  END tap_d[395]
  PIN tap_d[396]
    DIRECTION OUTPUT ;
    USE SIGNAL ;
    PORT
      LAYER M4 ;
        RECT  0 66.336 0.084 66.36 ;
    END
  END tap_d[396]
  PIN tap_d[397]
    DIRECTION OUTPUT ;
    USE SIGNAL ;
    PORT
      LAYER M4 ;
        RECT  0 66.432 0.084 66.456 ;
    END
  END tap_d[397]
  PIN tap_d[398]
    DIRECTION OUTPUT ;
    USE SIGNAL ;
    PORT
      LAYER M4 ;
        RECT  0 66.528 0.084 66.552 ;
    END
  END tap_d[398]
  PIN tap_d[399]
    DIRECTION OUTPUT ;
    USE SIGNAL ;
    PORT
      LAYER M4 ;
        RECT  0 66.624 0.084 66.648 ;
    END
  END tap_d[399]
  PIN tap_d[39]
    DIRECTION OUTPUT ;
    USE SIGNAL ;
    PORT
      LAYER M4 ;
        RECT  0 30.864 0.084 30.888 ;
    END
  END tap_d[39]
  PIN tap_d[3]
    DIRECTION OUTPUT ;
    USE SIGNAL ;
    PORT
      LAYER M4 ;
        RECT  0 27.264 0.084 27.288 ;
    END
  END tap_d[3]
  PIN tap_d[400]
    DIRECTION OUTPUT ;
    USE SIGNAL ;
    PORT
      LAYER M4 ;
        RECT  0 66.72 0.084 66.744 ;
    END
  END tap_d[400]
  PIN tap_d[401]
    DIRECTION OUTPUT ;
    USE SIGNAL ;
    PORT
      LAYER M4 ;
        RECT  0 66.816 0.084 66.84 ;
    END
  END tap_d[401]
  PIN tap_d[402]
    DIRECTION OUTPUT ;
    USE SIGNAL ;
    PORT
      LAYER M4 ;
        RECT  0 66.96 0.084 66.984 ;
    END
  END tap_d[402]
  PIN tap_d[403]
    DIRECTION OUTPUT ;
    USE SIGNAL ;
    PORT
      LAYER M4 ;
        RECT  0 67.056 0.084 67.08 ;
    END
  END tap_d[403]
  PIN tap_d[404]
    DIRECTION OUTPUT ;
    USE SIGNAL ;
    PORT
      LAYER M4 ;
        RECT  0 67.152 0.084 67.176 ;
    END
  END tap_d[404]
  PIN tap_d[405]
    DIRECTION OUTPUT ;
    USE SIGNAL ;
    PORT
      LAYER M4 ;
        RECT  0 67.248 0.084 67.272 ;
    END
  END tap_d[405]
  PIN tap_d[406]
    DIRECTION OUTPUT ;
    USE SIGNAL ;
    PORT
      LAYER M4 ;
        RECT  0 67.344 0.084 67.368 ;
    END
  END tap_d[406]
  PIN tap_d[407]
    DIRECTION OUTPUT ;
    USE SIGNAL ;
    PORT
      LAYER M4 ;
        RECT  0 67.44 0.084 67.464 ;
    END
  END tap_d[407]
  PIN tap_d[408]
    DIRECTION OUTPUT ;
    USE SIGNAL ;
    PORT
      LAYER M4 ;
        RECT  0 67.536 0.084 67.56 ;
    END
  END tap_d[408]
  PIN tap_d[409]
    DIRECTION OUTPUT ;
    USE SIGNAL ;
    PORT
      LAYER M4 ;
        RECT  0 67.632 0.084 67.656 ;
    END
  END tap_d[409]
  PIN tap_d[40]
    DIRECTION OUTPUT ;
    USE SIGNAL ;
    PORT
      LAYER M4 ;
        RECT  0 30.96 0.084 30.984 ;
    END
  END tap_d[40]
  PIN tap_d[410]
    DIRECTION OUTPUT ;
    USE SIGNAL ;
    PORT
      LAYER M4 ;
        RECT  0 67.728 0.084 67.752 ;
    END
  END tap_d[410]
  PIN tap_d[411]
    DIRECTION OUTPUT ;
    USE SIGNAL ;
    PORT
      LAYER M4 ;
        RECT  0 67.824 0.084 67.848 ;
    END
  END tap_d[411]
  PIN tap_d[412]
    DIRECTION OUTPUT ;
    USE SIGNAL ;
    PORT
      LAYER M4 ;
        RECT  0 67.92 0.084 67.944 ;
    END
  END tap_d[412]
  PIN tap_d[413]
    DIRECTION OUTPUT ;
    USE SIGNAL ;
    PORT
      LAYER M4 ;
        RECT  0 68.016 0.084 68.04 ;
    END
  END tap_d[413]
  PIN tap_d[414]
    DIRECTION OUTPUT ;
    USE SIGNAL ;
    PORT
      LAYER M4 ;
        RECT  0 68.112 0.084 68.136 ;
    END
  END tap_d[414]
  PIN tap_d[415]
    DIRECTION OUTPUT ;
    USE SIGNAL ;
    PORT
      LAYER M4 ;
        RECT  0 68.208 0.084 68.232 ;
    END
  END tap_d[415]
  PIN tap_d[416]
    DIRECTION OUTPUT ;
    USE SIGNAL ;
    PORT
      LAYER M4 ;
        RECT  0 68.352 0.084 68.376 ;
    END
  END tap_d[416]
  PIN tap_d[417]
    DIRECTION OUTPUT ;
    USE SIGNAL ;
    PORT
      LAYER M4 ;
        RECT  0 68.448 0.084 68.472 ;
    END
  END tap_d[417]
  PIN tap_d[418]
    DIRECTION OUTPUT ;
    USE SIGNAL ;
    PORT
      LAYER M4 ;
        RECT  0 68.544 0.084 68.568 ;
    END
  END tap_d[418]
  PIN tap_d[419]
    DIRECTION OUTPUT ;
    USE SIGNAL ;
    PORT
      LAYER M4 ;
        RECT  0 68.64 0.084 68.664 ;
    END
  END tap_d[419]
  PIN tap_d[41]
    DIRECTION OUTPUT ;
    USE SIGNAL ;
    PORT
      LAYER M4 ;
        RECT  0 31.056 0.084 31.08 ;
    END
  END tap_d[41]
  PIN tap_d[420]
    DIRECTION OUTPUT ;
    USE SIGNAL ;
    PORT
      LAYER M4 ;
        RECT  0 68.736 0.084 68.76 ;
    END
  END tap_d[420]
  PIN tap_d[421]
    DIRECTION OUTPUT ;
    USE SIGNAL ;
    PORT
      LAYER M4 ;
        RECT  0 68.832 0.084 68.856 ;
    END
  END tap_d[421]
  PIN tap_d[422]
    DIRECTION OUTPUT ;
    USE SIGNAL ;
    PORT
      LAYER M4 ;
        RECT  0 68.928 0.084 68.952 ;
    END
  END tap_d[422]
  PIN tap_d[423]
    DIRECTION OUTPUT ;
    USE SIGNAL ;
    PORT
      LAYER M4 ;
        RECT  0 69.024 0.084 69.048 ;
    END
  END tap_d[423]
  PIN tap_d[424]
    DIRECTION OUTPUT ;
    USE SIGNAL ;
    PORT
      LAYER M4 ;
        RECT  0 69.12 0.084 69.144 ;
    END
  END tap_d[424]
  PIN tap_d[425]
    DIRECTION OUTPUT ;
    USE SIGNAL ;
    PORT
      LAYER M4 ;
        RECT  0 69.216 0.084 69.24 ;
    END
  END tap_d[425]
  PIN tap_d[426]
    DIRECTION OUTPUT ;
    USE SIGNAL ;
    PORT
      LAYER M4 ;
        RECT  0 69.312 0.084 69.336 ;
    END
  END tap_d[426]
  PIN tap_d[427]
    DIRECTION OUTPUT ;
    USE SIGNAL ;
    PORT
      LAYER M4 ;
        RECT  0 69.408 0.084 69.432 ;
    END
  END tap_d[427]
  PIN tap_d[428]
    DIRECTION OUTPUT ;
    USE SIGNAL ;
    PORT
      LAYER M4 ;
        RECT  0 69.504 0.084 69.528 ;
    END
  END tap_d[428]
  PIN tap_d[429]
    DIRECTION OUTPUT ;
    USE SIGNAL ;
    PORT
      LAYER M4 ;
        RECT  0 69.6 0.084 69.624 ;
    END
  END tap_d[429]
  PIN tap_d[42]
    DIRECTION OUTPUT ;
    USE SIGNAL ;
    PORT
      LAYER M4 ;
        RECT  0 31.152 0.084 31.176 ;
    END
  END tap_d[42]
  PIN tap_d[430]
    DIRECTION OUTPUT ;
    USE SIGNAL ;
    PORT
      LAYER M4 ;
        RECT  0 69.744 0.084 69.768 ;
    END
  END tap_d[430]
  PIN tap_d[431]
    DIRECTION OUTPUT ;
    USE SIGNAL ;
    PORT
      LAYER M4 ;
        RECT  0 69.84 0.084 69.864 ;
    END
  END tap_d[431]
  PIN tap_d[432]
    DIRECTION OUTPUT ;
    USE SIGNAL ;
    PORT
      LAYER M4 ;
        RECT  0 69.936 0.084 69.96 ;
    END
  END tap_d[432]
  PIN tap_d[433]
    DIRECTION OUTPUT ;
    USE SIGNAL ;
    PORT
      LAYER M4 ;
        RECT  0 70.032 0.084 70.056 ;
    END
  END tap_d[433]
  PIN tap_d[434]
    DIRECTION OUTPUT ;
    USE SIGNAL ;
    PORT
      LAYER M4 ;
        RECT  0 70.128 0.084 70.152 ;
    END
  END tap_d[434]
  PIN tap_d[435]
    DIRECTION OUTPUT ;
    USE SIGNAL ;
    PORT
      LAYER M4 ;
        RECT  0 70.224 0.084 70.248 ;
    END
  END tap_d[435]
  PIN tap_d[436]
    DIRECTION OUTPUT ;
    USE SIGNAL ;
    PORT
      LAYER M4 ;
        RECT  0 70.32 0.084 70.344 ;
    END
  END tap_d[436]
  PIN tap_d[437]
    DIRECTION OUTPUT ;
    USE SIGNAL ;
    PORT
      LAYER M4 ;
        RECT  0 70.416 0.084 70.44 ;
    END
  END tap_d[437]
  PIN tap_d[438]
    DIRECTION OUTPUT ;
    USE SIGNAL ;
    PORT
      LAYER M4 ;
        RECT  0 70.512 0.084 70.536 ;
    END
  END tap_d[438]
  PIN tap_d[439]
    DIRECTION OUTPUT ;
    USE SIGNAL ;
    PORT
      LAYER M4 ;
        RECT  0 70.608 0.084 70.632 ;
    END
  END tap_d[439]
  PIN tap_d[43]
    DIRECTION OUTPUT ;
    USE SIGNAL ;
    PORT
      LAYER M4 ;
        RECT  0 31.248 0.084 31.272 ;
    END
  END tap_d[43]
  PIN tap_d[440]
    DIRECTION OUTPUT ;
    USE SIGNAL ;
    PORT
      LAYER M4 ;
        RECT  0 70.704 0.084 70.728 ;
    END
  END tap_d[440]
  PIN tap_d[441]
    DIRECTION OUTPUT ;
    USE SIGNAL ;
    PORT
      LAYER M4 ;
        RECT  0 70.8 0.084 70.824 ;
    END
  END tap_d[441]
  PIN tap_d[442]
    DIRECTION OUTPUT ;
    USE SIGNAL ;
    PORT
      LAYER M4 ;
        RECT  0 70.896 0.084 70.92 ;
    END
  END tap_d[442]
  PIN tap_d[443]
    DIRECTION OUTPUT ;
    USE SIGNAL ;
    PORT
      LAYER M4 ;
        RECT  0 70.992 0.084 71.016 ;
    END
  END tap_d[443]
  PIN tap_d[444]
    DIRECTION OUTPUT ;
    USE SIGNAL ;
    PORT
      LAYER M4 ;
        RECT  0 71.136 0.084 71.16 ;
    END
  END tap_d[444]
  PIN tap_d[445]
    DIRECTION OUTPUT ;
    USE SIGNAL ;
    PORT
      LAYER M4 ;
        RECT  0 71.232 0.084 71.256 ;
    END
  END tap_d[445]
  PIN tap_d[446]
    DIRECTION OUTPUT ;
    USE SIGNAL ;
    PORT
      LAYER M4 ;
        RECT  0 71.328 0.084 71.352 ;
    END
  END tap_d[446]
  PIN tap_d[447]
    DIRECTION OUTPUT ;
    USE SIGNAL ;
    PORT
      LAYER M4 ;
        RECT  0 71.424 0.084 71.448 ;
    END
  END tap_d[447]
  PIN tap_d[448]
    DIRECTION OUTPUT ;
    USE SIGNAL ;
    PORT
      LAYER M4 ;
        RECT  0 71.52 0.084 71.544 ;
    END
  END tap_d[448]
  PIN tap_d[449]
    DIRECTION OUTPUT ;
    USE SIGNAL ;
    PORT
      LAYER M4 ;
        RECT  0 71.616 0.084 71.64 ;
    END
  END tap_d[449]
  PIN tap_d[44]
    DIRECTION OUTPUT ;
    USE SIGNAL ;
    PORT
      LAYER M4 ;
        RECT  0 31.344 0.084 31.368 ;
    END
  END tap_d[44]
  PIN tap_d[450]
    DIRECTION OUTPUT ;
    USE SIGNAL ;
    PORT
      LAYER M4 ;
        RECT  0 71.712 0.084 71.736 ;
    END
  END tap_d[450]
  PIN tap_d[451]
    DIRECTION OUTPUT ;
    USE SIGNAL ;
    PORT
      LAYER M4 ;
        RECT  0 71.808 0.084 71.832 ;
    END
  END tap_d[451]
  PIN tap_d[452]
    DIRECTION OUTPUT ;
    USE SIGNAL ;
    PORT
      LAYER M4 ;
        RECT  0 71.904 0.084 71.928 ;
    END
  END tap_d[452]
  PIN tap_d[453]
    DIRECTION OUTPUT ;
    USE SIGNAL ;
    PORT
      LAYER M4 ;
        RECT  0 72 0.084 72.024 ;
    END
  END tap_d[453]
  PIN tap_d[454]
    DIRECTION OUTPUT ;
    USE SIGNAL ;
    PORT
      LAYER M4 ;
        RECT  0 72.096 0.084 72.12 ;
    END
  END tap_d[454]
  PIN tap_d[455]
    DIRECTION OUTPUT ;
    USE SIGNAL ;
    PORT
      LAYER M4 ;
        RECT  0 72.192 0.084 72.216 ;
    END
  END tap_d[455]
  PIN tap_d[456]
    DIRECTION OUTPUT ;
    USE SIGNAL ;
    PORT
      LAYER M4 ;
        RECT  0 72.288 0.084 72.312 ;
    END
  END tap_d[456]
  PIN tap_d[457]
    DIRECTION OUTPUT ;
    USE SIGNAL ;
    PORT
      LAYER M4 ;
        RECT  0 72.384 0.084 72.408 ;
    END
  END tap_d[457]
  PIN tap_d[458]
    DIRECTION OUTPUT ;
    USE SIGNAL ;
    PORT
      LAYER M4 ;
        RECT  0 72.528 0.084 72.552 ;
    END
  END tap_d[458]
  PIN tap_d[459]
    DIRECTION OUTPUT ;
    USE SIGNAL ;
    PORT
      LAYER M4 ;
        RECT  0 72.624 0.084 72.648 ;
    END
  END tap_d[459]
  PIN tap_d[45]
    DIRECTION OUTPUT ;
    USE SIGNAL ;
    PORT
      LAYER M4 ;
        RECT  0 31.44 0.084 31.464 ;
    END
  END tap_d[45]
  PIN tap_d[460]
    DIRECTION OUTPUT ;
    USE SIGNAL ;
    PORT
      LAYER M4 ;
        RECT  0 72.72 0.084 72.744 ;
    END
  END tap_d[460]
  PIN tap_d[461]
    DIRECTION OUTPUT ;
    USE SIGNAL ;
    PORT
      LAYER M4 ;
        RECT  0 72.816 0.084 72.84 ;
    END
  END tap_d[461]
  PIN tap_d[462]
    DIRECTION OUTPUT ;
    USE SIGNAL ;
    PORT
      LAYER M4 ;
        RECT  0 72.912 0.084 72.936 ;
    END
  END tap_d[462]
  PIN tap_d[463]
    DIRECTION OUTPUT ;
    USE SIGNAL ;
    PORT
      LAYER M4 ;
        RECT  0 73.008 0.084 73.032 ;
    END
  END tap_d[463]
  PIN tap_d[464]
    DIRECTION OUTPUT ;
    USE SIGNAL ;
    PORT
      LAYER M4 ;
        RECT  0 73.104 0.084 73.128 ;
    END
  END tap_d[464]
  PIN tap_d[465]
    DIRECTION OUTPUT ;
    USE SIGNAL ;
    PORT
      LAYER M4 ;
        RECT  0 73.2 0.084 73.224 ;
    END
  END tap_d[465]
  PIN tap_d[466]
    DIRECTION OUTPUT ;
    USE SIGNAL ;
    PORT
      LAYER M4 ;
        RECT  0 73.296 0.084 73.32 ;
    END
  END tap_d[466]
  PIN tap_d[467]
    DIRECTION OUTPUT ;
    USE SIGNAL ;
    PORT
      LAYER M4 ;
        RECT  0 73.392 0.084 73.416 ;
    END
  END tap_d[467]
  PIN tap_d[468]
    DIRECTION OUTPUT ;
    USE SIGNAL ;
    PORT
      LAYER M4 ;
        RECT  0 73.488 0.084 73.512 ;
    END
  END tap_d[468]
  PIN tap_d[469]
    DIRECTION OUTPUT ;
    USE SIGNAL ;
    PORT
      LAYER M4 ;
        RECT  0 73.584 0.084 73.608 ;
    END
  END tap_d[469]
  PIN tap_d[46]
    DIRECTION OUTPUT ;
    USE SIGNAL ;
    PORT
      LAYER M4 ;
        RECT  0 31.536 0.084 31.56 ;
    END
  END tap_d[46]
  PIN tap_d[470]
    DIRECTION OUTPUT ;
    USE SIGNAL ;
    PORT
      LAYER M4 ;
        RECT  0 73.68 0.084 73.704 ;
    END
  END tap_d[470]
  PIN tap_d[471]
    DIRECTION OUTPUT ;
    USE SIGNAL ;
    PORT
      LAYER M4 ;
        RECT  0 73.776 0.084 73.8 ;
    END
  END tap_d[471]
  PIN tap_d[472]
    DIRECTION OUTPUT ;
    USE SIGNAL ;
    PORT
      LAYER M4 ;
        RECT  0 73.872 0.084 73.896 ;
    END
  END tap_d[472]
  PIN tap_d[473]
    DIRECTION OUTPUT ;
    USE SIGNAL ;
    PORT
      LAYER M4 ;
        RECT  0 74.016 0.084 74.04 ;
    END
  END tap_d[473]
  PIN tap_d[474]
    DIRECTION OUTPUT ;
    USE SIGNAL ;
    PORT
      LAYER M4 ;
        RECT  0 74.112 0.084 74.136 ;
    END
  END tap_d[474]
  PIN tap_d[475]
    DIRECTION OUTPUT ;
    USE SIGNAL ;
    PORT
      LAYER M4 ;
        RECT  0 74.208 0.084 74.232 ;
    END
  END tap_d[475]
  PIN tap_d[476]
    DIRECTION OUTPUT ;
    USE SIGNAL ;
    PORT
      LAYER M4 ;
        RECT  0 74.304 0.084 74.328 ;
    END
  END tap_d[476]
  PIN tap_d[477]
    DIRECTION OUTPUT ;
    USE SIGNAL ;
    PORT
      LAYER M4 ;
        RECT  0 74.4 0.084 74.424 ;
    END
  END tap_d[477]
  PIN tap_d[478]
    DIRECTION OUTPUT ;
    USE SIGNAL ;
    PORT
      LAYER M4 ;
        RECT  0 74.496 0.084 74.52 ;
    END
  END tap_d[478]
  PIN tap_d[479]
    DIRECTION OUTPUT ;
    USE SIGNAL ;
    PORT
      LAYER M4 ;
        RECT  0 74.592 0.084 74.616 ;
    END
  END tap_d[479]
  PIN tap_d[47]
    DIRECTION OUTPUT ;
    USE SIGNAL ;
    PORT
      LAYER M4 ;
        RECT  0 31.632 0.084 31.656 ;
    END
  END tap_d[47]
  PIN tap_d[480]
    DIRECTION OUTPUT ;
    USE SIGNAL ;
    PORT
      LAYER M4 ;
        RECT  0 74.688 0.084 74.712 ;
    END
  END tap_d[480]
  PIN tap_d[481]
    DIRECTION OUTPUT ;
    USE SIGNAL ;
    PORT
      LAYER M4 ;
        RECT  0 74.784 0.084 74.808 ;
    END
  END tap_d[481]
  PIN tap_d[482]
    DIRECTION OUTPUT ;
    USE SIGNAL ;
    PORT
      LAYER M4 ;
        RECT  0 74.88 0.084 74.904 ;
    END
  END tap_d[482]
  PIN tap_d[483]
    DIRECTION OUTPUT ;
    USE SIGNAL ;
    PORT
      LAYER M4 ;
        RECT  0 74.976 0.084 75 ;
    END
  END tap_d[483]
  PIN tap_d[484]
    DIRECTION OUTPUT ;
    USE SIGNAL ;
    PORT
      LAYER M4 ;
        RECT  0 75.072 0.084 75.096 ;
    END
  END tap_d[484]
  PIN tap_d[485]
    DIRECTION OUTPUT ;
    USE SIGNAL ;
    PORT
      LAYER M4 ;
        RECT  0 75.168 0.084 75.192 ;
    END
  END tap_d[485]
  PIN tap_d[486]
    DIRECTION OUTPUT ;
    USE SIGNAL ;
    PORT
      LAYER M4 ;
        RECT  0 75.264 0.084 75.288 ;
    END
  END tap_d[486]
  PIN tap_d[487]
    DIRECTION OUTPUT ;
    USE SIGNAL ;
    PORT
      LAYER M4 ;
        RECT  0 75.408 0.084 75.432 ;
    END
  END tap_d[487]
  PIN tap_d[488]
    DIRECTION OUTPUT ;
    USE SIGNAL ;
    PORT
      LAYER M4 ;
        RECT  0 75.504 0.084 75.528 ;
    END
  END tap_d[488]
  PIN tap_d[489]
    DIRECTION OUTPUT ;
    USE SIGNAL ;
    PORT
      LAYER M4 ;
        RECT  0 75.6 0.084 75.624 ;
    END
  END tap_d[489]
  PIN tap_d[48]
    DIRECTION OUTPUT ;
    USE SIGNAL ;
    PORT
      LAYER M4 ;
        RECT  0 31.728 0.084 31.752 ;
    END
  END tap_d[48]
  PIN tap_d[490]
    DIRECTION OUTPUT ;
    USE SIGNAL ;
    PORT
      LAYER M4 ;
        RECT  0 75.696 0.084 75.72 ;
    END
  END tap_d[490]
  PIN tap_d[491]
    DIRECTION OUTPUT ;
    USE SIGNAL ;
    PORT
      LAYER M4 ;
        RECT  0 75.792 0.084 75.816 ;
    END
  END tap_d[491]
  PIN tap_d[492]
    DIRECTION OUTPUT ;
    USE SIGNAL ;
    PORT
      LAYER M4 ;
        RECT  0 75.888 0.084 75.912 ;
    END
  END tap_d[492]
  PIN tap_d[493]
    DIRECTION OUTPUT ;
    USE SIGNAL ;
    PORT
      LAYER M4 ;
        RECT  0 75.984 0.084 76.008 ;
    END
  END tap_d[493]
  PIN tap_d[494]
    DIRECTION OUTPUT ;
    USE SIGNAL ;
    PORT
      LAYER M4 ;
        RECT  0 76.08 0.084 76.104 ;
    END
  END tap_d[494]
  PIN tap_d[495]
    DIRECTION OUTPUT ;
    USE SIGNAL ;
    PORT
      LAYER M4 ;
        RECT  0 76.176 0.084 76.2 ;
    END
  END tap_d[495]
  PIN tap_d[496]
    DIRECTION OUTPUT ;
    USE SIGNAL ;
    PORT
      LAYER M4 ;
        RECT  0 76.272 0.084 76.296 ;
    END
  END tap_d[496]
  PIN tap_d[497]
    DIRECTION OUTPUT ;
    USE SIGNAL ;
    PORT
      LAYER M4 ;
        RECT  0 76.368 0.084 76.392 ;
    END
  END tap_d[497]
  PIN tap_d[498]
    DIRECTION OUTPUT ;
    USE SIGNAL ;
    PORT
      LAYER M4 ;
        RECT  0 76.464 0.084 76.488 ;
    END
  END tap_d[498]
  PIN tap_d[499]
    DIRECTION OUTPUT ;
    USE SIGNAL ;
    PORT
      LAYER M4 ;
        RECT  0 76.56 0.084 76.584 ;
    END
  END tap_d[499]
  PIN tap_d[49]
    DIRECTION OUTPUT ;
    USE SIGNAL ;
    PORT
      LAYER M4 ;
        RECT  0 31.872 0.084 31.896 ;
    END
  END tap_d[49]
  PIN tap_d[4]
    DIRECTION OUTPUT ;
    USE SIGNAL ;
    PORT
      LAYER M4 ;
        RECT  0 27.36 0.084 27.384 ;
    END
  END tap_d[4]
  PIN tap_d[500]
    DIRECTION OUTPUT ;
    USE SIGNAL ;
    PORT
      LAYER M4 ;
        RECT  0 76.656 0.084 76.68 ;
    END
  END tap_d[500]
  PIN tap_d[501]
    DIRECTION OUTPUT ;
    USE SIGNAL ;
    PORT
      LAYER M4 ;
        RECT  0 76.8 0.084 76.824 ;
    END
  END tap_d[501]
  PIN tap_d[502]
    DIRECTION OUTPUT ;
    USE SIGNAL ;
    PORT
      LAYER M4 ;
        RECT  0 76.896 0.084 76.92 ;
    END
  END tap_d[502]
  PIN tap_d[503]
    DIRECTION OUTPUT ;
    USE SIGNAL ;
    PORT
      LAYER M4 ;
        RECT  0 76.992 0.084 77.016 ;
    END
  END tap_d[503]
  PIN tap_d[504]
    DIRECTION OUTPUT ;
    USE SIGNAL ;
    PORT
      LAYER M4 ;
        RECT  0 77.088 0.084 77.112 ;
    END
  END tap_d[504]
  PIN tap_d[505]
    DIRECTION OUTPUT ;
    USE SIGNAL ;
    PORT
      LAYER M4 ;
        RECT  0 77.184 0.084 77.208 ;
    END
  END tap_d[505]
  PIN tap_d[506]
    DIRECTION OUTPUT ;
    USE SIGNAL ;
    PORT
      LAYER M4 ;
        RECT  0 77.28 0.084 77.304 ;
    END
  END tap_d[506]
  PIN tap_d[507]
    DIRECTION OUTPUT ;
    USE SIGNAL ;
    PORT
      LAYER M4 ;
        RECT  0 77.376 0.084 77.4 ;
    END
  END tap_d[507]
  PIN tap_d[50]
    DIRECTION OUTPUT ;
    USE SIGNAL ;
    PORT
      LAYER M4 ;
        RECT  0 31.968 0.084 31.992 ;
    END
  END tap_d[50]
  PIN tap_d[51]
    DIRECTION OUTPUT ;
    USE SIGNAL ;
    PORT
      LAYER M4 ;
        RECT  0 32.064 0.084 32.088 ;
    END
  END tap_d[51]
  PIN tap_d[52]
    DIRECTION OUTPUT ;
    USE SIGNAL ;
    PORT
      LAYER M4 ;
        RECT  0 32.16 0.084 32.184 ;
    END
  END tap_d[52]
  PIN tap_d[53]
    DIRECTION OUTPUT ;
    USE SIGNAL ;
    PORT
      LAYER M4 ;
        RECT  0 32.256 0.084 32.28 ;
    END
  END tap_d[53]
  PIN tap_d[54]
    DIRECTION OUTPUT ;
    USE SIGNAL ;
    PORT
      LAYER M4 ;
        RECT  0 32.352 0.084 32.376 ;
    END
  END tap_d[54]
  PIN tap_d[55]
    DIRECTION OUTPUT ;
    USE SIGNAL ;
    PORT
      LAYER M4 ;
        RECT  0 32.448 0.084 32.472 ;
    END
  END tap_d[55]
  PIN tap_d[56]
    DIRECTION OUTPUT ;
    USE SIGNAL ;
    PORT
      LAYER M4 ;
        RECT  0 32.544 0.084 32.568 ;
    END
  END tap_d[56]
  PIN tap_d[57]
    DIRECTION OUTPUT ;
    USE SIGNAL ;
    PORT
      LAYER M4 ;
        RECT  0 32.64 0.084 32.664 ;
    END
  END tap_d[57]
  PIN tap_d[58]
    DIRECTION OUTPUT ;
    USE SIGNAL ;
    PORT
      LAYER M4 ;
        RECT  0 32.736 0.084 32.76 ;
    END
  END tap_d[58]
  PIN tap_d[59]
    DIRECTION OUTPUT ;
    USE SIGNAL ;
    PORT
      LAYER M4 ;
        RECT  0 32.832 0.084 32.856 ;
    END
  END tap_d[59]
  PIN tap_d[5]
    DIRECTION OUTPUT ;
    USE SIGNAL ;
    PORT
      LAYER M4 ;
        RECT  0 27.456 0.084 27.48 ;
    END
  END tap_d[5]
  PIN tap_d[60]
    DIRECTION OUTPUT ;
    USE SIGNAL ;
    PORT
      LAYER M4 ;
        RECT  0 32.928 0.084 32.952 ;
    END
  END tap_d[60]
  PIN tap_d[61]
    DIRECTION OUTPUT ;
    USE SIGNAL ;
    PORT
      LAYER M4 ;
        RECT  0 33.024 0.084 33.048 ;
    END
  END tap_d[61]
  PIN tap_d[62]
    DIRECTION OUTPUT ;
    USE SIGNAL ;
    PORT
      LAYER M4 ;
        RECT  0 33.12 0.084 33.144 ;
    END
  END tap_d[62]
  PIN tap_d[63]
    DIRECTION OUTPUT ;
    USE SIGNAL ;
    PORT
      LAYER M4 ;
        RECT  0 33.264 0.084 33.288 ;
    END
  END tap_d[63]
  PIN tap_d[64]
    DIRECTION OUTPUT ;
    USE SIGNAL ;
    PORT
      LAYER M4 ;
        RECT  0 33.36 0.084 33.384 ;
    END
  END tap_d[64]
  PIN tap_d[65]
    DIRECTION OUTPUT ;
    USE SIGNAL ;
    PORT
      LAYER M4 ;
        RECT  0 33.456 0.084 33.48 ;
    END
  END tap_d[65]
  PIN tap_d[66]
    DIRECTION OUTPUT ;
    USE SIGNAL ;
    PORT
      LAYER M4 ;
        RECT  0 33.552 0.084 33.576 ;
    END
  END tap_d[66]
  PIN tap_d[67]
    DIRECTION OUTPUT ;
    USE SIGNAL ;
    PORT
      LAYER M4 ;
        RECT  0 33.648 0.084 33.672 ;
    END
  END tap_d[67]
  PIN tap_d[68]
    DIRECTION OUTPUT ;
    USE SIGNAL ;
    PORT
      LAYER M4 ;
        RECT  0 33.744 0.084 33.768 ;
    END
  END tap_d[68]
  PIN tap_d[69]
    DIRECTION OUTPUT ;
    USE SIGNAL ;
    PORT
      LAYER M4 ;
        RECT  0 33.84 0.084 33.864 ;
    END
  END tap_d[69]
  PIN tap_d[6]
    DIRECTION OUTPUT ;
    USE SIGNAL ;
    PORT
      LAYER M4 ;
        RECT  0 27.552 0.084 27.576 ;
    END
  END tap_d[6]
  PIN tap_d[70]
    DIRECTION OUTPUT ;
    USE SIGNAL ;
    PORT
      LAYER M4 ;
        RECT  0 33.936 0.084 33.96 ;
    END
  END tap_d[70]
  PIN tap_d[71]
    DIRECTION OUTPUT ;
    USE SIGNAL ;
    PORT
      LAYER M4 ;
        RECT  0 34.032 0.084 34.056 ;
    END
  END tap_d[71]
  PIN tap_d[72]
    DIRECTION OUTPUT ;
    USE SIGNAL ;
    PORT
      LAYER M4 ;
        RECT  0 34.128 0.084 34.152 ;
    END
  END tap_d[72]
  PIN tap_d[73]
    DIRECTION OUTPUT ;
    USE SIGNAL ;
    PORT
      LAYER M4 ;
        RECT  0 34.224 0.084 34.248 ;
    END
  END tap_d[73]
  PIN tap_d[74]
    DIRECTION OUTPUT ;
    USE SIGNAL ;
    PORT
      LAYER M4 ;
        RECT  0 34.32 0.084 34.344 ;
    END
  END tap_d[74]
  PIN tap_d[75]
    DIRECTION OUTPUT ;
    USE SIGNAL ;
    PORT
      LAYER M4 ;
        RECT  0 34.416 0.084 34.44 ;
    END
  END tap_d[75]
  PIN tap_d[76]
    DIRECTION OUTPUT ;
    USE SIGNAL ;
    PORT
      LAYER M4 ;
        RECT  0 34.512 0.084 34.536 ;
    END
  END tap_d[76]
  PIN tap_d[77]
    DIRECTION OUTPUT ;
    USE SIGNAL ;
    PORT
      LAYER M4 ;
        RECT  0 34.656 0.084 34.68 ;
    END
  END tap_d[77]
  PIN tap_d[78]
    DIRECTION OUTPUT ;
    USE SIGNAL ;
    PORT
      LAYER M4 ;
        RECT  0 34.752 0.084 34.776 ;
    END
  END tap_d[78]
  PIN tap_d[79]
    DIRECTION OUTPUT ;
    USE SIGNAL ;
    PORT
      LAYER M4 ;
        RECT  0 34.848 0.084 34.872 ;
    END
  END tap_d[79]
  PIN tap_d[7]
    DIRECTION OUTPUT ;
    USE SIGNAL ;
    PORT
      LAYER M4 ;
        RECT  0 27.696 0.084 27.72 ;
    END
  END tap_d[7]
  PIN tap_d[80]
    DIRECTION OUTPUT ;
    USE SIGNAL ;
    PORT
      LAYER M4 ;
        RECT  0 34.944 0.084 34.968 ;
    END
  END tap_d[80]
  PIN tap_d[81]
    DIRECTION OUTPUT ;
    USE SIGNAL ;
    PORT
      LAYER M4 ;
        RECT  0 35.04 0.084 35.064 ;
    END
  END tap_d[81]
  PIN tap_d[82]
    DIRECTION OUTPUT ;
    USE SIGNAL ;
    PORT
      LAYER M4 ;
        RECT  0 35.136 0.084 35.16 ;
    END
  END tap_d[82]
  PIN tap_d[83]
    DIRECTION OUTPUT ;
    USE SIGNAL ;
    PORT
      LAYER M4 ;
        RECT  0 35.232 0.084 35.256 ;
    END
  END tap_d[83]
  PIN tap_d[84]
    DIRECTION OUTPUT ;
    USE SIGNAL ;
    PORT
      LAYER M4 ;
        RECT  0 35.328 0.084 35.352 ;
    END
  END tap_d[84]
  PIN tap_d[85]
    DIRECTION OUTPUT ;
    USE SIGNAL ;
    PORT
      LAYER M4 ;
        RECT  0 35.424 0.084 35.448 ;
    END
  END tap_d[85]
  PIN tap_d[86]
    DIRECTION OUTPUT ;
    USE SIGNAL ;
    PORT
      LAYER M4 ;
        RECT  0 35.52 0.084 35.544 ;
    END
  END tap_d[86]
  PIN tap_d[87]
    DIRECTION OUTPUT ;
    USE SIGNAL ;
    PORT
      LAYER M4 ;
        RECT  0 35.616 0.084 35.64 ;
    END
  END tap_d[87]
  PIN tap_d[88]
    DIRECTION OUTPUT ;
    USE SIGNAL ;
    PORT
      LAYER M4 ;
        RECT  0 35.712 0.084 35.736 ;
    END
  END tap_d[88]
  PIN tap_d[89]
    DIRECTION OUTPUT ;
    USE SIGNAL ;
    PORT
      LAYER M4 ;
        RECT  0 35.808 0.084 35.832 ;
    END
  END tap_d[89]
  PIN tap_d[8]
    DIRECTION OUTPUT ;
    USE SIGNAL ;
    PORT
      LAYER M4 ;
        RECT  0 27.792 0.084 27.816 ;
    END
  END tap_d[8]
  PIN tap_d[90]
    DIRECTION OUTPUT ;
    USE SIGNAL ;
    PORT
      LAYER M4 ;
        RECT  0 35.904 0.084 35.928 ;
    END
  END tap_d[90]
  PIN tap_d[91]
    DIRECTION OUTPUT ;
    USE SIGNAL ;
    PORT
      LAYER M4 ;
        RECT  0 36 0.084 36.024 ;
    END
  END tap_d[91]
  PIN tap_d[92]
    DIRECTION OUTPUT ;
    USE SIGNAL ;
    PORT
      LAYER M4 ;
        RECT  0 36.144 0.084 36.168 ;
    END
  END tap_d[92]
  PIN tap_d[93]
    DIRECTION OUTPUT ;
    USE SIGNAL ;
    PORT
      LAYER M4 ;
        RECT  0 36.24 0.084 36.264 ;
    END
  END tap_d[93]
  PIN tap_d[94]
    DIRECTION OUTPUT ;
    USE SIGNAL ;
    PORT
      LAYER M4 ;
        RECT  0 36.336 0.084 36.36 ;
    END
  END tap_d[94]
  PIN tap_d[95]
    DIRECTION OUTPUT ;
    USE SIGNAL ;
    PORT
      LAYER M4 ;
        RECT  0 36.432 0.084 36.456 ;
    END
  END tap_d[95]
  PIN tap_d[96]
    DIRECTION OUTPUT ;
    USE SIGNAL ;
    PORT
      LAYER M4 ;
        RECT  0 36.528 0.084 36.552 ;
    END
  END tap_d[96]
  PIN tap_d[97]
    DIRECTION OUTPUT ;
    USE SIGNAL ;
    PORT
      LAYER M4 ;
        RECT  0 36.624 0.084 36.648 ;
    END
  END tap_d[97]
  PIN tap_d[98]
    DIRECTION OUTPUT ;
    USE SIGNAL ;
    PORT
      LAYER M4 ;
        RECT  0 36.72 0.084 36.744 ;
    END
  END tap_d[98]
  PIN tap_d[99]
    DIRECTION OUTPUT ;
    USE SIGNAL ;
    PORT
      LAYER M4 ;
        RECT  0 36.816 0.084 36.84 ;
    END
  END tap_d[99]
  PIN tap_d[9]
    DIRECTION OUTPUT ;
    USE SIGNAL ;
    PORT
      LAYER M4 ;
        RECT  0 27.888 0.084 27.912 ;
    END
  END tap_d[9]
  PIN tie_hi
    DIRECTION OUTPUT ;
    USE SIGNAL ;
    PORT
      LAYER M5 ;
        RECT  0.96 103.572 0.984 103.656 ;
    END
  END tie_hi
  PIN tie_lo
    DIRECTION OUTPUT ;
    USE SIGNAL ;
    PORT
      LAYER M5 ;
        RECT  1.2 103.572 1.224 103.656 ;
    END
  END tie_lo
  PIN VDD
    DIRECTION INOUT ;
    USE POWER ;
    PORT
      LAYER M5 ;
        RECT  45.792 2.151 45.912 101.273 ;
        RECT  40.392 2.151 40.512 101.273 ;
        RECT  34.992 2.151 35.112 101.273 ;
        RECT  29.592 2.151 29.712 101.273 ;
        RECT  24.192 2.151 24.312 101.273 ;
        RECT  18.792 2.151 18.912 101.273 ;
        RECT  13.392 2.151 13.512 101.273 ;
        RECT  7.992 2.151 8.112 101.273 ;
        RECT  2.592 2.151 2.712 101.273 ;
    END
  END VDD
  PIN VSS
    DIRECTION INOUT ;
    USE GROUND ;
    PORT
      LAYER M5 ;
        RECT  45.6 2.137 45.72 101.259 ;
        RECT  40.2 2.137 40.32 101.259 ;
        RECT  34.8 2.137 34.92 101.259 ;
        RECT  29.4 2.137 29.52 101.259 ;
        RECT  24 2.137 24.12 101.259 ;
        RECT  18.6 2.137 18.72 101.259 ;
        RECT  13.2 2.137 13.32 101.259 ;
        RECT  7.8 2.137 7.92 101.259 ;
        RECT  2.4 2.137 2.52 101.259 ;
    END
  END VSS
  # OT_OBS_CLOSED layer=M5 d_um=1.536 added=26
  OBS
    LAYER RVTN ;
     RECT  2.16 2.16 50.49 2.295 ;
     RECT  2.16 2.565 50.49 2.835 ;
     RECT  2.16 3.105 50.49 3.375 ;
     RECT  2.16 3.645 50.49 3.915 ;
     RECT  2.16 4.185 50.49 4.455 ;
     RECT  2.16 4.725 50.49 4.995 ;
     RECT  2.16 5.265 50.49 5.535 ;
     RECT  2.16 5.805 50.49 6.075 ;
     RECT  2.16 6.345 50.49 6.615 ;
     RECT  2.16 6.885 50.49 7.155 ;
     RECT  2.16 7.425 50.49 7.695 ;
     RECT  2.16 7.965 50.49 8.235 ;
     RECT  2.16 8.505 50.49 8.775 ;
     RECT  2.16 9.045 50.49 9.315 ;
     RECT  2.16 9.585 50.49 9.855 ;
     RECT  2.16 10.125 50.49 10.395 ;
     RECT  2.16 10.665 50.49 10.935 ;
     RECT  2.16 11.205 50.49 11.475 ;
     RECT  2.16 11.745 50.49 12.015 ;
     RECT  2.16 12.285 50.49 12.555 ;
     RECT  2.16 12.825 50.49 13.095 ;
     RECT  2.16 13.365 50.49 13.635 ;
     RECT  2.16 13.905 50.49 14.175 ;
     RECT  2.16 14.445 50.49 14.715 ;
     RECT  2.16 14.985 50.49 15.255 ;
     RECT  2.16 15.525 50.49 15.795 ;
     RECT  2.16 16.065 50.49 16.335 ;
     RECT  2.16 16.605 50.49 16.875 ;
     RECT  2.16 17.145 50.49 17.415 ;
     RECT  2.16 17.685 50.49 17.955 ;
     RECT  2.16 18.225 50.49 18.495 ;
     RECT  2.16 18.765 50.49 19.035 ;
     RECT  2.16 19.305 50.49 19.575 ;
     RECT  2.16 19.845 50.49 20.115 ;
     RECT  2.16 20.385 50.49 20.655 ;
     RECT  2.16 20.925 50.49 21.195 ;
     RECT  2.16 21.465 50.49 21.735 ;
     RECT  2.16 22.005 50.49 22.275 ;
     RECT  2.16 22.545 50.49 22.815 ;
     RECT  2.16 23.085 50.49 23.355 ;
     RECT  2.16 23.625 50.49 23.895 ;
     RECT  2.16 24.165 50.49 24.435 ;
     RECT  2.16 24.705 50.49 24.975 ;
     RECT  2.16 25.245 50.49 25.515 ;
     RECT  2.16 25.785 50.49 26.055 ;
     RECT  2.16 26.325 50.49 26.595 ;
     RECT  2.16 26.865 50.49 27.135 ;
     RECT  2.16 27.405 50.49 27.675 ;
     RECT  2.16 27.945 50.49 28.215 ;
     RECT  2.16 28.485 50.49 28.755 ;
     RECT  2.16 29.025 50.49 29.295 ;
     RECT  2.16 29.565 50.49 29.835 ;
     RECT  2.16 30.105 50.49 30.375 ;
     RECT  2.16 30.645 50.49 30.915 ;
     RECT  2.16 31.185 50.49 31.455 ;
     RECT  2.16 31.725 50.49 31.995 ;
     RECT  2.16 32.265 50.49 32.535 ;
     RECT  2.16 32.805 50.49 33.075 ;
     RECT  2.16 33.345 50.49 33.615 ;
     RECT  2.16 33.885 50.49 34.155 ;
     RECT  2.16 34.425 50.49 34.695 ;
     RECT  2.16 34.965 50.49 35.235 ;
     RECT  2.16 35.505 50.49 35.775 ;
     RECT  2.16 36.045 50.49 36.315 ;
     RECT  2.16 36.585 50.49 36.855 ;
     RECT  2.16 37.125 50.49 37.395 ;
     RECT  2.16 37.665 50.49 37.935 ;
     RECT  2.16 38.205 50.49 38.475 ;
     RECT  2.16 38.745 50.49 39.015 ;
     RECT  2.16 39.285 50.49 39.555 ;
     RECT  2.16 39.825 50.49 40.095 ;
     RECT  2.16 40.365 50.49 40.635 ;
     RECT  2.16 40.905 50.49 41.175 ;
     RECT  2.16 41.445 50.49 41.715 ;
     RECT  2.16 41.985 50.49 42.255 ;
     RECT  2.16 42.525 50.49 42.795 ;
     RECT  2.16 43.065 50.49 43.335 ;
     RECT  2.16 43.605 50.49 43.875 ;
     RECT  2.16 44.145 50.49 44.415 ;
     RECT  2.16 44.685 50.49 44.955 ;
     RECT  2.16 45.225 50.49 45.495 ;
     RECT  2.16 45.765 50.49 46.035 ;
     RECT  2.16 46.305 50.49 46.575 ;
     RECT  2.16 46.845 50.49 47.115 ;
     RECT  2.16 47.385 50.49 47.655 ;
     RECT  2.16 47.925 50.49 48.195 ;
     RECT  2.16 48.465 50.49 48.735 ;
     RECT  2.16 49.005 50.49 49.275 ;
     RECT  2.16 49.545 50.49 49.815 ;
     RECT  2.16 50.085 50.49 50.355 ;
     RECT  2.16 50.625 50.49 50.895 ;
     RECT  2.16 51.165 50.49 51.435 ;
     RECT  2.16 51.705 50.49 51.975 ;
     RECT  2.16 52.245 50.49 52.515 ;
     RECT  2.16 52.785 50.49 53.055 ;
     RECT  2.16 53.325 50.49 53.595 ;
     RECT  2.16 53.865 50.49 54.135 ;
     RECT  2.16 54.405 50.49 54.675 ;
     RECT  2.16 54.945 50.49 55.215 ;
     RECT  2.16 55.485 50.49 55.755 ;
     RECT  2.16 56.025 50.49 56.295 ;
     RECT  2.16 56.565 50.49 56.835 ;
     RECT  2.16 57.105 50.49 57.375 ;
     RECT  2.16 57.645 50.49 57.915 ;
     RECT  2.16 58.185 50.49 58.455 ;
     RECT  2.16 58.725 50.49 58.995 ;
     RECT  2.16 59.265 50.49 59.535 ;
     RECT  2.16 59.805 50.49 60.075 ;
     RECT  2.16 60.345 50.49 60.615 ;
     RECT  2.16 60.885 50.49 61.155 ;
     RECT  2.16 61.425 50.49 61.695 ;
     RECT  2.16 61.965 50.49 62.235 ;
     RECT  2.16 62.505 50.49 62.775 ;
     RECT  2.16 63.045 50.49 63.315 ;
     RECT  2.16 63.585 50.49 63.855 ;
     RECT  2.16 64.125 50.49 64.395 ;
     RECT  2.16 64.665 50.49 64.935 ;
     RECT  2.16 65.205 50.49 65.475 ;
     RECT  2.16 65.745 50.49 66.015 ;
     RECT  2.16 66.285 50.49 66.555 ;
     RECT  2.16 66.825 50.49 67.095 ;
     RECT  2.16 67.365 50.49 67.635 ;
     RECT  2.16 67.905 50.49 68.175 ;
     RECT  2.16 68.445 50.49 68.715 ;
     RECT  2.16 68.985 50.49 69.255 ;
     RECT  2.16 69.525 50.49 69.795 ;
     RECT  2.16 70.065 50.49 70.335 ;
     RECT  2.16 70.605 50.49 70.875 ;
     RECT  2.16 71.145 50.49 71.415 ;
     RECT  2.16 71.685 50.49 71.955 ;
     RECT  2.16 72.225 50.49 72.495 ;
     RECT  2.16 72.765 50.49 73.035 ;
     RECT  2.16 73.305 50.49 73.575 ;
     RECT  2.16 73.845 50.49 74.115 ;
     RECT  2.16 74.385 50.49 74.655 ;
     RECT  2.16 74.925 50.49 75.195 ;
     RECT  2.16 75.465 50.49 75.735 ;
     RECT  2.16 76.005 50.49 76.275 ;
     RECT  2.16 76.545 50.49 76.815 ;
     RECT  2.16 77.085 50.49 77.355 ;
     RECT  2.16 77.625 50.49 77.895 ;
     RECT  2.16 78.165 50.49 78.435 ;
     RECT  2.16 78.705 50.49 78.975 ;
     RECT  2.16 79.245 50.49 79.515 ;
     RECT  2.16 79.785 50.49 80.055 ;
     RECT  2.16 80.325 50.49 80.595 ;
     RECT  2.16 80.865 50.49 81.135 ;
     RECT  2.16 81.405 50.49 81.675 ;
     RECT  2.16 81.945 50.49 82.215 ;
     RECT  2.16 82.485 50.49 82.755 ;
     RECT  2.16 83.025 50.49 83.295 ;
     RECT  2.16 83.565 50.49 83.835 ;
     RECT  2.16 84.105 50.49 84.375 ;
     RECT  2.16 84.645 50.49 84.915 ;
     RECT  2.16 85.185 50.49 85.455 ;
     RECT  2.16 85.725 50.49 85.995 ;
     RECT  2.16 86.265 50.49 86.535 ;
     RECT  2.16 86.805 50.49 87.075 ;
     RECT  2.16 87.345 50.49 87.615 ;
     RECT  2.16 87.885 50.49 88.155 ;
     RECT  2.16 88.425 50.49 88.695 ;
     RECT  2.16 88.965 50.49 89.235 ;
     RECT  2.16 89.505 50.49 89.775 ;
     RECT  2.16 90.045 50.49 90.315 ;
     RECT  2.16 90.585 50.49 90.855 ;
     RECT  2.16 91.125 50.49 91.395 ;
     RECT  2.16 91.665 50.49 91.935 ;
     RECT  2.16 92.205 50.49 92.475 ;
     RECT  2.16 92.745 50.49 93.015 ;
     RECT  2.16 93.285 50.49 93.555 ;
     RECT  2.16 93.825 50.49 94.095 ;
     RECT  2.16 94.365 50.49 94.635 ;
     RECT  2.16 94.905 50.49 95.175 ;
     RECT  2.16 95.445 50.49 95.715 ;
     RECT  2.16 95.985 50.49 96.255 ;
     RECT  2.16 96.525 50.49 96.795 ;
     RECT  2.16 97.065 50.49 97.335 ;
     RECT  2.16 97.605 50.49 97.875 ;
     RECT  2.16 98.145 50.49 98.415 ;
     RECT  2.16 98.685 50.49 98.955 ;
     RECT  2.16 99.225 50.49 99.495 ;
     RECT  2.16 99.765 50.49 100.035 ;
     RECT  2.16 100.305 50.49 100.575 ;
     RECT  2.16 100.845 50.49 101.115 ;
    LAYER RVTP ;
     RECT  2.16 2.295 50.49 2.565 ;
     RECT  2.16 2.835 50.49 3.105 ;
     RECT  2.16 3.375 50.49 3.645 ;
     RECT  2.16 3.915 50.49 4.185 ;
     RECT  2.16 4.455 50.49 4.725 ;
     RECT  2.16 4.995 50.49 5.265 ;
     RECT  2.16 5.535 50.49 5.805 ;
     RECT  2.16 6.075 50.49 6.345 ;
     RECT  2.16 6.615 50.49 6.885 ;
     RECT  2.16 7.155 50.49 7.425 ;
     RECT  2.16 7.695 50.49 7.965 ;
     RECT  2.16 8.235 50.49 8.505 ;
     RECT  2.16 8.775 50.49 9.045 ;
     RECT  2.16 9.315 50.49 9.585 ;
     RECT  2.16 9.855 50.49 10.125 ;
     RECT  2.16 10.395 50.49 10.665 ;
     RECT  2.16 10.935 50.49 11.205 ;
     RECT  2.16 11.475 50.49 11.745 ;
     RECT  2.16 12.015 50.49 12.285 ;
     RECT  2.16 12.555 50.49 12.825 ;
     RECT  2.16 13.095 50.49 13.365 ;
     RECT  2.16 13.635 50.49 13.905 ;
     RECT  2.16 14.175 50.49 14.445 ;
     RECT  2.16 14.715 50.49 14.985 ;
     RECT  2.16 15.255 50.49 15.525 ;
     RECT  2.16 15.795 50.49 16.065 ;
     RECT  2.16 16.335 50.49 16.605 ;
     RECT  2.16 16.875 50.49 17.145 ;
     RECT  2.16 17.415 50.49 17.685 ;
     RECT  2.16 17.955 50.49 18.225 ;
     RECT  2.16 18.495 50.49 18.765 ;
     RECT  2.16 19.035 50.49 19.305 ;
     RECT  2.16 19.575 50.49 19.845 ;
     RECT  2.16 20.115 50.49 20.385 ;
     RECT  2.16 20.655 50.49 20.925 ;
     RECT  2.16 21.195 50.49 21.465 ;
     RECT  2.16 21.735 50.49 22.005 ;
     RECT  2.16 22.275 50.49 22.545 ;
     RECT  2.16 22.815 50.49 23.085 ;
     RECT  2.16 23.355 50.49 23.625 ;
     RECT  2.16 23.895 50.49 24.165 ;
     RECT  2.16 24.435 50.49 24.705 ;
     RECT  2.16 24.975 50.49 25.245 ;
     RECT  2.16 25.515 50.49 25.785 ;
     RECT  2.16 26.055 50.49 26.325 ;
     RECT  2.16 26.595 50.49 26.865 ;
     RECT  2.16 27.135 50.49 27.405 ;
     RECT  2.16 27.675 50.49 27.945 ;
     RECT  2.16 28.215 50.49 28.485 ;
     RECT  2.16 28.755 50.49 29.025 ;
     RECT  2.16 29.295 50.49 29.565 ;
     RECT  2.16 29.835 50.49 30.105 ;
     RECT  2.16 30.375 50.49 30.645 ;
     RECT  2.16 30.915 50.49 31.185 ;
     RECT  2.16 31.455 50.49 31.725 ;
     RECT  2.16 31.995 50.49 32.265 ;
     RECT  2.16 32.535 50.49 32.805 ;
     RECT  2.16 33.075 50.49 33.345 ;
     RECT  2.16 33.615 50.49 33.885 ;
     RECT  2.16 34.155 50.49 34.425 ;
     RECT  2.16 34.695 50.49 34.965 ;
     RECT  2.16 35.235 50.49 35.505 ;
     RECT  2.16 35.775 50.49 36.045 ;
     RECT  2.16 36.315 50.49 36.585 ;
     RECT  2.16 36.855 50.49 37.125 ;
     RECT  2.16 37.395 50.49 37.665 ;
     RECT  2.16 37.935 50.49 38.205 ;
     RECT  2.16 38.475 50.49 38.745 ;
     RECT  2.16 39.015 50.49 39.285 ;
     RECT  2.16 39.555 50.49 39.825 ;
     RECT  2.16 40.095 50.49 40.365 ;
     RECT  2.16 40.635 50.49 40.905 ;
     RECT  2.16 41.175 50.49 41.445 ;
     RECT  2.16 41.715 50.49 41.985 ;
     RECT  2.16 42.255 50.49 42.525 ;
     RECT  2.16 42.795 50.49 43.065 ;
     RECT  2.16 43.335 50.49 43.605 ;
     RECT  2.16 43.875 50.49 44.145 ;
     RECT  2.16 44.415 50.49 44.685 ;
     RECT  2.16 44.955 50.49 45.225 ;
     RECT  2.16 45.495 50.49 45.765 ;
     RECT  2.16 46.035 50.49 46.305 ;
     RECT  2.16 46.575 50.49 46.845 ;
     RECT  2.16 47.115 50.49 47.385 ;
     RECT  2.16 47.655 50.49 47.925 ;
     RECT  2.16 48.195 50.49 48.465 ;
     RECT  2.16 48.735 50.49 49.005 ;
     RECT  2.16 49.275 50.49 49.545 ;
     RECT  2.16 49.815 50.49 50.085 ;
     RECT  2.16 50.355 50.49 50.625 ;
     RECT  2.16 50.895 50.49 51.165 ;
     RECT  2.16 51.435 50.49 51.705 ;
     RECT  2.16 51.975 50.49 52.245 ;
     RECT  2.16 52.515 50.49 52.785 ;
     RECT  2.16 53.055 50.49 53.325 ;
     RECT  2.16 53.595 50.49 53.865 ;
     RECT  2.16 54.135 50.49 54.405 ;
     RECT  2.16 54.675 50.49 54.945 ;
     RECT  2.16 55.215 50.49 55.485 ;
     RECT  2.16 55.755 50.49 56.025 ;
     RECT  2.16 56.295 50.49 56.565 ;
     RECT  2.16 56.835 50.49 57.105 ;
     RECT  2.16 57.375 50.49 57.645 ;
     RECT  2.16 57.915 50.49 58.185 ;
     RECT  2.16 58.455 50.49 58.725 ;
     RECT  2.16 58.995 50.49 59.265 ;
     RECT  2.16 59.535 50.49 59.805 ;
     RECT  2.16 60.075 50.49 60.345 ;
     RECT  2.16 60.615 50.49 60.885 ;
     RECT  2.16 61.155 50.49 61.425 ;
     RECT  2.16 61.695 50.49 61.965 ;
     RECT  2.16 62.235 50.49 62.505 ;
     RECT  2.16 62.775 50.49 63.045 ;
     RECT  2.16 63.315 50.49 63.585 ;
     RECT  2.16 63.855 50.49 64.125 ;
     RECT  2.16 64.395 50.49 64.665 ;
     RECT  2.16 64.935 50.49 65.205 ;
     RECT  2.16 65.475 50.49 65.745 ;
     RECT  2.16 66.015 50.49 66.285 ;
     RECT  2.16 66.555 50.49 66.825 ;
     RECT  2.16 67.095 50.49 67.365 ;
     RECT  2.16 67.635 50.49 67.905 ;
     RECT  2.16 68.175 50.49 68.445 ;
     RECT  2.16 68.715 50.49 68.985 ;
     RECT  2.16 69.255 50.49 69.525 ;
     RECT  2.16 69.795 50.49 70.065 ;
     RECT  2.16 70.335 50.49 70.605 ;
     RECT  2.16 70.875 50.49 71.145 ;
     RECT  2.16 71.415 50.49 71.685 ;
     RECT  2.16 71.955 50.49 72.225 ;
     RECT  2.16 72.495 50.49 72.765 ;
     RECT  2.16 73.035 50.49 73.305 ;
     RECT  2.16 73.575 50.49 73.845 ;
     RECT  2.16 74.115 50.49 74.385 ;
     RECT  2.16 74.655 50.49 74.925 ;
     RECT  2.16 75.195 50.49 75.465 ;
     RECT  2.16 75.735 50.49 76.005 ;
     RECT  2.16 76.275 50.49 76.545 ;
     RECT  2.16 76.815 50.49 77.085 ;
     RECT  2.16 77.355 50.49 77.625 ;
     RECT  2.16 77.895 50.49 78.165 ;
     RECT  2.16 78.435 50.49 78.705 ;
     RECT  2.16 78.975 50.49 79.245 ;
     RECT  2.16 79.515 50.49 79.785 ;
     RECT  2.16 80.055 50.49 80.325 ;
     RECT  2.16 80.595 50.49 80.865 ;
     RECT  2.16 81.135 50.49 81.405 ;
     RECT  2.16 81.675 50.49 81.945 ;
     RECT  2.16 82.215 50.49 82.485 ;
     RECT  2.16 82.755 50.49 83.025 ;
     RECT  2.16 83.295 50.49 83.565 ;
     RECT  2.16 83.835 50.49 84.105 ;
     RECT  2.16 84.375 50.49 84.645 ;
     RECT  2.16 84.915 50.49 85.185 ;
     RECT  2.16 85.455 50.49 85.725 ;
     RECT  2.16 85.995 50.49 86.265 ;
     RECT  2.16 86.535 50.49 86.805 ;
     RECT  2.16 87.075 50.49 87.345 ;
     RECT  2.16 87.615 50.49 87.885 ;
     RECT  2.16 88.155 50.49 88.425 ;
     RECT  2.16 88.695 50.49 88.965 ;
     RECT  2.16 89.235 50.49 89.505 ;
     RECT  2.16 89.775 50.49 90.045 ;
     RECT  2.16 90.315 50.49 90.585 ;
     RECT  2.16 90.855 50.49 91.125 ;
     RECT  2.16 91.395 50.49 91.665 ;
     RECT  2.16 91.935 50.49 92.205 ;
     RECT  2.16 92.475 50.49 92.745 ;
     RECT  2.16 93.015 50.49 93.285 ;
     RECT  2.16 93.555 50.49 93.825 ;
     RECT  2.16 94.095 50.49 94.365 ;
     RECT  2.16 94.635 50.49 94.905 ;
     RECT  2.16 95.175 50.49 95.445 ;
     RECT  2.16 95.715 50.49 95.985 ;
     RECT  2.16 96.255 50.49 96.525 ;
     RECT  2.16 96.795 50.49 97.065 ;
     RECT  2.16 97.335 50.49 97.605 ;
     RECT  2.16 97.875 50.49 98.145 ;
     RECT  2.16 98.415 50.49 98.685 ;
     RECT  2.16 98.955 50.49 99.225 ;
     RECT  2.16 99.495 50.49 99.765 ;
     RECT  2.16 100.035 50.49 100.305 ;
     RECT  2.16 100.575 50.49 100.845 ;
     RECT  2.16 101.115 50.49 101.25 ;
    LAYER M1 ;
     RECT  2.16 2.151 50.49 101.259 ;
    LAYER M2 ;
     RECT  0.031 28.152 0.131 28.17 ;
     RECT  0.103 28.998 0.139 29.754 ;
     RECT  0.103 30.654 0.139 30.672 ;
     RECT  0.103 32.976 0.139 32.994 ;
     RECT  0.103 37.44 0.139 37.458 ;
     RECT  0.103 49.248 0.139 49.266 ;
     RECT  0.139 32.274 0.175 32.994 ;
     RECT  0.139 37.44 0.175 38.034 ;
     RECT  0.103 40.338 0.175 40.86 ;
     RECT  0.175 40.266 0.203 40.86 ;
     RECT  0.103 42.696 0.203 45.054 ;
     RECT  0.103 55.341 0.203 56.394 ;
     RECT  0.103 60.66 0.203 61.299 ;
     RECT  0.103 64.368 0.203 64.386 ;
     RECT  0.103 70.38 0.203 70.398 ;
     RECT  0.103 72.936 0.203 73.674 ;
     RECT  0.103 48.276 0.211 48.294 ;
     RECT  0.139 49.05 0.211 49.266 ;
     RECT  0.103 54.414 0.211 54.432 ;
     RECT  0.103 50.868 0.239 51.264 ;
     RECT  0.203 61.236 0.239 61.254 ;
     RECT  0.103 26.334 0.247 27.054 ;
     RECT  0.203 40.266 0.247 40.356 ;
     RECT  0.103 46.161 0.275 47.304 ;
     RECT  0.175 67.338 0.275 67.356 ;
     RECT  0.103 33.93 0.347 33.948 ;
     RECT  0.211 54.306 0.347 54.432 ;
     RECT  0.247 39.996 0.383 40.356 ;
     RECT  0.103 58.464 0.463 58.482 ;
     RECT  0.463 58.464 0.499 58.518 ;
     RECT  0.463 68.454 0.499 68.472 ;
     RECT  0.175 32.076 0.535 32.994 ;
     RECT  0.103 35.856 0.535 35.874 ;
     RECT  0.175 37.026 0.535 38.034 ;
     RECT  0.383 39.996 0.535 40.284 ;
     RECT  0.203 42.696 0.535 44.442 ;
     RECT  0.275 46.476 0.535 47.304 ;
     RECT  0.211 48.276 0.535 49.266 ;
     RECT  0.239 51.246 0.535 51.264 ;
     RECT  0.499 52.218 0.535 52.236 ;
     RECT  0.347 54.306 0.535 54.324 ;
     RECT  0.499 58.428 0.535 58.518 ;
     RECT  0.499 68.256 0.535 68.706 ;
     RECT  0.535 46.476 0.563 49.464 ;
     RECT  0.535 51.246 0.635 52.614 ;
     RECT  0.031 24.408 1.147 24.426 ;
     RECT  0.139 28.998 1.147 30.672 ;
     RECT  1.147 28.926 1.183 30.672 ;
     RECT  0.535 31.626 1.183 32.994 ;
     RECT  0.635 51.246 1.219 52.344 ;
     RECT  1.183 28.188 1.283 30.672 ;
     RECT  1.219 50.868 1.319 52.344 ;
     RECT  1.471 5.472 1.543 5.49 ;
     RECT  1.147 24.408 1.687 24.966 ;
     RECT  0.247 26.334 1.687 27.324 ;
     RECT  1.687 97.416 1.723 97.434 ;
     RECT  1.543 5.274 1.939 5.49 ;
     RECT  0.787 3.852 2.083 3.87 ;
     RECT  2.083 3.276 2.16 4.248 ;
     RECT  1.939 5.004 2.16 5.49 ;
     RECT  1.687 24.408 2.16 27.324 ;
     RECT  1.283 28.926 2.16 30.672 ;
     RECT  1.183 31.536 2.16 32.994 ;
     RECT  0.535 34.668 2.16 34.686 ;
     RECT  0.535 35.856 2.16 38.034 ;
     RECT  0.211 38.916 2.16 38.934 ;
     RECT  0.535 39.798 2.16 40.284 ;
     RECT  0.535 41.958 2.16 44.442 ;
     RECT  0.535 45.576 2.16 45.594 ;
     RECT  0.563 46.476 2.16 46.494 ;
     RECT  0.563 47.286 2.16 49.464 ;
     RECT  1.319 51.246 2.16 52.344 ;
     RECT  0.535 54.108 2.16 54.324 ;
     RECT  0.203 55.656 2.16 56.394 ;
     RECT  0.535 57.996 2.16 58.518 ;
     RECT  0.103 59.616 2.16 59.634 ;
     RECT  0.535 62.046 2.16 62.064 ;
     RECT  0.535 63.756 2.16 63.774 ;
     RECT  0.535 66.636 2.16 66.654 ;
     RECT  0.535 68.256 2.16 68.814 ;
     RECT  0.203 72.936 2.16 72.954 ;
     RECT  0.535 74.016 2.16 74.646 ;
     RECT  0.535 76.248 2.16 76.266 ;
     RECT  2.155 91.746 2.16 91.764 ;
     RECT  1.939 96.066 2.16 96.084 ;
     RECT  1.723 96.876 2.16 97.434 ;
     RECT  2.047 99.576 2.16 99.594 ;
     RECT  2.875 1.152 2.975 1.17 ;
     RECT  2.16 2.151 41.179 101.259 ;
     RECT  41.179 2.151 42.719 101.304 ;
     RECT  42.719 2.151 43.339 101.259 ;
     RECT  43.339 2.106 43.835 101.259 ;
     RECT  43.835 2.151 50.49 101.259 ;
     RECT  50.49 86.616 50.495 92.772 ;
     RECT  50.49 99.846 50.495 100.674 ;
     RECT  50.495 86.616 50.531 92.196 ;
     RECT  50.49 95.076 50.531 95.634 ;
     RECT  50.531 95.616 50.603 95.634 ;
     RECT  50.531 87.696 50.639 92.196 ;
     RECT  50.49 5.508 50.747 6.984 ;
     RECT  50.639 87.696 50.783 91.692 ;
     RECT  50.783 89.478 50.819 91.692 ;
     RECT  50.819 89.478 50.855 90.774 ;
     RECT  50.819 91.674 50.891 91.692 ;
     RECT  50.855 90.756 51.215 90.774 ;
     RECT  50.783 87.696 51.287 88.722 ;
     RECT  50.747 6.048 51.323 6.984 ;
     RECT  50.495 100.656 51.323 100.674 ;
     RECT  51.323 6.048 51.359 6.714 ;
     RECT  50.49 98.496 51.359 99.054 ;
     RECT  51.359 6.696 51.395 6.714 ;
     RECT  51.359 99.036 51.395 99.054 ;
     RECT  50.49 8.946 51.431 9.504 ;
     RECT  50.495 99.846 51.431 99.864 ;
     RECT  50.49 7.866 51.467 7.884 ;
     RECT  50.49 96.57 51.467 97.128 ;
     RECT  51.431 9.486 51.503 9.504 ;
     RECT  51.467 97.11 51.503 97.128 ;
     RECT  50.531 86.616 51.539 86.904 ;
     RECT  51.539 86.886 51.575 86.904 ;
     RECT  51.287 87.696 51.611 88.182 ;
     RECT  51.611 87.696 51.683 87.714 ;
     RECT  50.855 89.478 51.791 89.964 ;
     RECT  51.791 89.478 51.863 89.496 ;
     RECT  50.49 93.87 52.403 93.888 ;
    LAYER M3 ;
     RECT  35.244 0.091 35.622 0.269 ;
     RECT  19.08 0.091 19.494 0.317 ;
     RECT  35.244 0.269 35.55 0.317 ;
     RECT  40.068 0.091 40.086 0.317 ;
     RECT  35.424 0.317 35.55 0.365 ;
     RECT  24.408 0.091 24.426 0.461 ;
     RECT  35.532 0.365 35.55 0.461 ;
     RECT  46.296 0.235 46.314 0.571 ;
     RECT  50.22 0.091 50.634 0.955 ;
     RECT  49.896 0.955 50.634 1.003 ;
     RECT  19.476 0.317 19.494 1.099 ;
     RECT  35.856 1.003 35.874 1.099 ;
     RECT  49.356 1.003 50.634 1.099 ;
     RECT  2.952 1.099 2.97 1.147 ;
     RECT  49.356 1.099 50.742 1.627 ;
     RECT  2.88 1.147 2.97 1.723 ;
     RECT  13.608 0.091 13.626 1.723 ;
     RECT  19.404 1.099 19.494 1.723 ;
     RECT  35.856 1.099 35.91 1.723 ;
     RECT  46.296 0.571 46.926 1.723 ;
     RECT  2.556 1.723 3.006 1.771 ;
     RECT  4.176 1.723 4.194 1.771 ;
     RECT  5.04 1.723 7.326 1.771 ;
     RECT  8.568 1.723 9.054 1.771 ;
     RECT  9.9 1.723 15.822 1.771 ;
     RECT  16.704 1.723 16.902 1.771 ;
     RECT  17.64 1.723 18.234 1.771 ;
     RECT  19.26 1.723 24.858 1.771 ;
     RECT  25.596 1.723 30.474 1.771 ;
     RECT  31.284 1.723 31.77 1.771 ;
     RECT  32.616 1.723 34.974 1.771 ;
     RECT  35.712 1.723 39.654 1.771 ;
     RECT  40.752 1.723 41.31 1.771 ;
     RECT  42.084 1.723 47.79 1.771 ;
     RECT  48.888 1.627 50.742 1.771 ;
     RECT  32.616 1.771 39.654 2.011 ;
     RECT  40.536 1.771 47.79 2.011 ;
     RECT  2.556 1.771 18.414 2.143 ;
     RECT  19.26 1.771 31.842 2.143 ;
     RECT  2.415 2.143 31.842 2.191 ;
     RECT  32.616 2.011 47.79 2.191 ;
     RECT  48.636 1.771 50.742 2.191 ;
     RECT  2.376 2.191 50.742 2.641 ;
     RECT  2.268 2.641 50.742 3.001 ;
     RECT  2.196 3.001 50.742 3.271 ;
     RECT  0.792 2.875 0.81 3.875 ;
     RECT  2.088 3.271 50.742 4.027 ;
     RECT  1.944 4.027 50.742 5.131 ;
     RECT  1.476 5.131 50.742 5.495 ;
     RECT  2.124 5.495 50.742 5.837 ;
     RECT  2.124 5.837 50.454 6.143 ;
     RECT  51.336 6.043 51.354 6.691 ;
     RECT  51.336 6.691 51.39 6.961 ;
     RECT  2.124 6.143 50.274 7.231 ;
     RECT  51.3 6.961 51.39 7.861 ;
     RECT  51.3 7.861 51.462 9.481 ;
     RECT  1.152 24.943 1.17 25.591 ;
     RECT  2.124 7.231 50.346 25.591 ;
     RECT  0.036 24.403 0.054 26.329 ;
     RECT  0.036 26.329 0.126 26.563 ;
     RECT  1.152 25.591 50.346 26.563 ;
     RECT  0.036 26.563 50.346 27.821 ;
     RECT  0.036 27.821 0.342 28.175 ;
     RECT  0.108 28.175 0.342 28.205 ;
     RECT  1.188 27.821 50.346 28.921 ;
     RECT  1.152 28.921 50.346 28.973 ;
     RECT  0.216 28.205 0.306 28.993 ;
     RECT  1.152 28.973 1.17 29.021 ;
     RECT  0.108 28.993 0.306 29.083 ;
     RECT  0.108 29.083 0.342 29.309 ;
     RECT  0.108 29.309 0.306 30.109 ;
     RECT  1.152 30.001 1.17 30.109 ;
     RECT  0.108 30.109 1.17 30.443 ;
     RECT  0.108 30.443 0.558 30.509 ;
     RECT  1.152 31.435 1.17 31.531 ;
     RECT  0.108 30.509 0.342 31.565 ;
     RECT  0.144 31.565 0.342 31.621 ;
     RECT  1.152 31.531 1.206 31.621 ;
     RECT  0.144 31.621 1.206 31.649 ;
     RECT  0.144 31.649 1.17 31.709 ;
     RECT  0.144 31.709 0.558 31.997 ;
     RECT  1.188 32.728 1.206 32.737 ;
     RECT  1.188 32.737 1.278 32.765 ;
     RECT  1.26 32.765 1.278 32.813 ;
     RECT  0.144 31.997 0.342 32.971 ;
     RECT  0.108 32.971 0.342 33.953 ;
     RECT  0.216 33.953 0.342 33.965 ;
     RECT  0.54 34.663 0.558 34.877 ;
     RECT  0.144 35.611 0.162 35.851 ;
     RECT  0.108 35.851 0.162 35.933 ;
     RECT  0.144 35.933 0.162 36.589 ;
     RECT  0.144 36.589 0.558 37.133 ;
     RECT  0.144 37.133 0.342 37.435 ;
     RECT  0.108 37.435 0.342 37.939 ;
     RECT  0.108 37.939 0.558 37.949 ;
     RECT  0.144 37.949 0.558 38.957 ;
     RECT  0.144 38.957 0.234 39.793 ;
     RECT  0.144 39.793 0.558 39.917 ;
     RECT  0.144 39.917 0.378 40.315 ;
     RECT  0.108 40.315 0.378 40.445 ;
     RECT  0.108 40.445 0.27 40.637 ;
     RECT  0.108 40.637 0.198 40.973 ;
     RECT  0.108 40.973 0.162 41.021 ;
     RECT  0.144 41.021 0.162 41.453 ;
     RECT  0.54 41.953 0.558 42.221 ;
     RECT  0.144 42.235 0.162 42.691 ;
     RECT  0.108 42.691 0.162 43.033 ;
     RECT  0.108 43.033 0.558 43.613 ;
     RECT  0.108 43.613 0.522 43.997 ;
     RECT  0.108 43.997 0.306 44.525 ;
     RECT  0.108 44.525 0.198 45.059 ;
     RECT  0.144 45.059 0.198 45.571 ;
     RECT  0.144 45.571 0.558 45.979 ;
     RECT  0.108 45.979 0.558 47.324 ;
     RECT  0.144 47.324 0.558 48.271 ;
     RECT  0.108 48.271 0.558 48.973 ;
     RECT  0.108 48.973 1.134 49.037 ;
     RECT  0.108 49.037 0.558 49.28 ;
     RECT  0.216 49.28 0.558 49.469 ;
     RECT  0.54 49.469 0.558 49.757 ;
     RECT  0.324 50.251 0.342 50.827 ;
     RECT  1.224 50.827 1.242 50.863 ;
     RECT  1.224 50.863 1.314 50.891 ;
     RECT  1.296 50.891 1.314 50.909 ;
     RECT  0.108 50.827 0.342 51.341 ;
     RECT  0.18 51.341 0.342 51.781 ;
     RECT  0.18 51.781 0.558 51.869 ;
     RECT  0.504 51.869 0.558 52.555 ;
     RECT  0.504 52.555 0.63 52.619 ;
     RECT  0.504 52.619 0.558 52.637 ;
     RECT  0.504 52.637 0.522 52.733 ;
     RECT  0.144 53.131 0.342 53.309 ;
     RECT  0.216 53.309 0.342 54.103 ;
     RECT  0.216 54.103 0.558 54.221 ;
     RECT  0.216 54.221 0.378 54.235 ;
     RECT  0.144 54.235 0.378 54.409 ;
     RECT  0.108 54.409 0.378 54.461 ;
     RECT  0.108 54.461 0.234 55.915 ;
     RECT  0.108 55.915 0.378 55.963 ;
     RECT  0.108 55.963 0.45 56.141 ;
     RECT  0.108 56.141 0.342 56.381 ;
     RECT  0.108 56.381 0.234 56.429 ;
     RECT  0.108 56.429 0.198 56.525 ;
     RECT  0.18 56.525 0.198 56.909 ;
     RECT  0.144 57.355 0.162 57.883 ;
     RECT  0.144 57.883 0.342 57.991 ;
     RECT  0.144 57.991 0.558 58.171 ;
     RECT  0.144 58.171 0.666 58.301 ;
     RECT  0.144 58.301 0.558 58.459 ;
     RECT  0.108 58.459 0.558 58.733 ;
     RECT  0.108 58.733 0.522 58.829 ;
     RECT  0.144 58.829 0.522 58.925 ;
     RECT  0.144 58.925 0.486 59.405 ;
     RECT  0.144 59.405 0.198 59.611 ;
     RECT  0.108 59.611 0.198 61.051 ;
     RECT  0.108 61.051 0.342 61.181 ;
     RECT  0.108 61.181 0.234 61.259 ;
     RECT  0.108 61.259 0.198 61.613 ;
     RECT  0.144 61.613 0.198 62.041 ;
     RECT  0.144 62.041 0.558 62.189 ;
     RECT  0.144 62.189 0.234 63.005 ;
     RECT  0.144 63.005 0.162 63.751 ;
     RECT  0.144 63.751 0.558 63.869 ;
     RECT  0.144 63.869 0.198 64.267 ;
     RECT  0.108 64.267 0.198 64.391 ;
     RECT  0.144 64.391 0.162 64.589 ;
     RECT  0.54 66.631 0.558 66.749 ;
     RECT  0.324 67.243 0.342 67.291 ;
     RECT  0.252 67.291 0.342 67.333 ;
     RECT  0.18 67.333 0.342 67.373 ;
     RECT  0.324 67.373 0.342 67.949 ;
     RECT  0.468 68.251 0.522 68.377 ;
     RECT  2.052 28.973 50.346 68.711 ;
     RECT  0.468 68.377 0.558 69.053 ;
     RECT  0.468 69.053 0.522 69.629 ;
     RECT  0.468 69.629 0.486 69.869 ;
     RECT  0.108 70.219 0.342 70.412 ;
     RECT  0.144 70.412 0.342 70.637 ;
     RECT  2.052 68.711 50.094 70.673 ;
     RECT  0.144 70.637 0.162 71.117 ;
     RECT  26.82 70.673 50.094 72.149 ;
     RECT  0.144 72.763 0.162 72.931 ;
     RECT  0.108 72.931 0.162 73.339 ;
     RECT  0.108 73.339 0.198 73.675 ;
     RECT  0.108 73.675 0.342 73.679 ;
     RECT  0.216 73.679 0.342 74.011 ;
     RECT  0.216 74.011 0.558 74.045 ;
     RECT  2.052 70.673 25.866 74.107 ;
     RECT  26.82 72.149 49.95 74.107 ;
     RECT  2.052 74.107 49.95 74.147 ;
     RECT  23.004 74.147 49.95 74.651 ;
     RECT  0.54 74.045 0.558 74.717 ;
     RECT  23.004 74.651 29.754 75.053 ;
     RECT  30.528 74.651 49.95 75.569 ;
     RECT  37.188 75.569 49.95 76.343 ;
     RECT  0.54 76.243 0.558 76.397 ;
     RECT  0.144 76.651 0.162 76.781 ;
     RECT  0.324 77.179 0.342 77.309 ;
     RECT  37.188 76.343 42.714 77.423 ;
     RECT  43.452 76.343 49.95 85.801 ;
     RECT  51.3 9.481 51.498 86.611 ;
     RECT  51.3 86.611 51.534 86.881 ;
     RECT  43.452 85.801 50.166 87.151 ;
     RECT  51.3 86.881 51.57 87.691 ;
     RECT  51.3 87.691 51.678 88.699 ;
     RECT  43.452 87.151 50.526 88.771 ;
     RECT  51.264 88.699 51.678 88.771 ;
     RECT  42.156 77.423 42.714 89.005 ;
     RECT  43.452 88.771 51.678 89.005 ;
     RECT  42.156 89.005 51.678 89.473 ;
     RECT  37.188 77.423 41.346 89.941 ;
     RECT  42.156 89.473 51.858 89.941 ;
     RECT  30.528 75.569 36.414 90.391 ;
     RECT  37.188 89.941 51.858 90.391 ;
     RECT  26.82 75.053 29.754 90.517 ;
     RECT  30.528 90.391 51.858 90.517 ;
     RECT  2.052 74.147 22.194 90.661 ;
     RECT  23.004 75.053 25.866 90.661 ;
     RECT  26.82 90.517 51.858 90.661 ;
     RECT  2.052 90.661 25.866 90.931 ;
     RECT  26.712 90.661 51.858 90.931 ;
     RECT  2.052 90.931 51.858 93.865 ;
     RECT  2.052 93.865 52.398 96.061 ;
     RECT  1.944 96.061 52.398 96.859 ;
     RECT  1.728 96.859 52.398 97.411 ;
     RECT  1.692 97.411 52.398 97.469 ;
     RECT  2.052 97.469 52.398 99.599 ;
     RECT  2.16 99.599 52.398 101.039 ;
     RECT  29.607 101.039 47.538 101.075 ;
     RECT  14.976 101.039 17.586 101.219 ;
     RECT  29.607 101.075 38.646 101.219 ;
     RECT  50.004 101.039 52.398 101.219 ;
     RECT  2.16 101.039 11.79 101.267 ;
     RECT  18.324 101.039 28.854 101.267 ;
     RECT  29.607 101.219 33.39 101.267 ;
     RECT  39.6 101.075 47.538 101.267 ;
     RECT  2.16 101.267 7.29 101.453 ;
     RECT  8.136 101.267 11.79 101.453 ;
     RECT  18.324 101.267 23.67 101.453 ;
     RECT  24.444 101.267 28.854 101.453 ;
     RECT  30.132 101.267 33.39 101.453 ;
     RECT  50.724 101.219 52.398 101.453 ;
     RECT  8.208 101.453 11.79 101.501 ;
     RECT  15.84 101.219 17.586 101.501 ;
     RECT  24.876 101.453 26.73 101.501 ;
     RECT  31.968 101.453 33.39 101.501 ;
     RECT  36.18 101.219 38.646 101.501 ;
     RECT  48.528 101.039 49.266 101.501 ;
     RECT  12.708 101.039 14.202 101.549 ;
     RECT  39.6 101.267 39.798 101.549 ;
     RECT  2.952 101.453 2.97 102.029 ;
     RECT  5.652 101.453 7.29 102.029 ;
     RECT  8.784 101.501 11.79 102.029 ;
     RECT  15.84 101.501 17.262 102.029 ;
     RECT  22.68 101.453 23.67 102.029 ;
     RECT  24.876 101.501 26.658 102.029 ;
     RECT  31.212 101.453 31.23 102.029 ;
     RECT  32.112 101.501 33.39 102.029 ;
     RECT  40.932 101.267 45.378 102.029 ;
     RECT  2.16 101.453 2.178 102.077 ;
     RECT  3.96 101.453 3.978 102.077 ;
     RECT  6.732 102.029 7.29 102.077 ;
     RECT  8.784 102.029 9.63 102.077 ;
     RECT  11.772 102.029 11.79 102.077 ;
     RECT  18.324 101.453 18.594 102.077 ;
     RECT  27.468 101.453 28.854 102.077 ;
     RECT  46.224 101.267 47.538 102.077 ;
     RECT  37.368 101.501 38.646 102.125 ;
     RECT  36.18 101.501 36.558 102.523 ;
     RECT  20.844 101.453 21.006 102.557 ;
     RECT  38.016 102.125 38.646 102.557 ;
     RECT  10.62 102.029 10.638 102.605 ;
     RECT  13.824 101.549 14.202 102.605 ;
     RECT  18.576 102.077 18.594 102.605 ;
     RECT  20.988 102.557 21.006 102.605 ;
     RECT  25.812 102.029 26.658 102.605 ;
     RECT  27.576 102.077 28.854 102.605 ;
     RECT  38.16 102.557 38.646 102.605 ;
     RECT  39.6 101.549 39.618 102.605 ;
     RECT  40.932 102.029 43.434 102.605 ;
     RECT  50.796 101.453 52.398 102.605 ;
     RECT  14.004 102.605 14.202 102.653 ;
     RECT  15.84 102.029 16.038 102.653 ;
     RECT  17.064 102.029 17.262 102.653 ;
     RECT  25.812 102.605 25.974 102.653 ;
     RECT  32.112 102.029 33.318 102.653 ;
     RECT  36.18 102.523 36.702 102.653 ;
     RECT  44.244 102.029 45.378 102.653 ;
     RECT  47.016 102.077 47.538 102.653 ;
     RECT  46.224 102.077 46.242 103.243 ;
     RECT  8.784 102.077 9.594 103.291 ;
     RECT  21.924 101.453 21.942 103.291 ;
     RECT  34.416 101.219 35.154 103.291 ;
     RECT  8.244 103.291 9.594 103.325 ;
     RECT  34.416 103.291 35.334 103.339 ;
     RECT  2.772 103.195 2.79 103.373 ;
     RECT  47.016 102.653 47.034 103.373 ;
     RECT  19.584 101.453 19.998 103.421 ;
     RECT  21.816 103.291 21.942 103.421 ;
     RECT  46.224 103.243 46.278 103.421 ;
     RECT  23.256 102.029 23.67 103.435 ;
     RECT  21.816 103.421 21.834 103.469 ;
     RECT  34.128 103.339 35.334 103.469 ;
     RECT  41.04 102.605 43.002 103.469 ;
     RECT  12.708 101.549 12.942 103.517 ;
     RECT  41.472 103.469 43.002 103.517 ;
     RECT  4.86 101.453 4.878 103.565 ;
     RECT  5.652 102.029 5.67 103.565 ;
     RECT  7.272 102.077 7.29 103.565 ;
     RECT  8.244 103.325 9.522 103.565 ;
     RECT  12.924 103.517 12.942 103.565 ;
     RECT  14.184 102.653 14.202 103.565 ;
     RECT  14.976 101.219 14.994 103.565 ;
     RECT  15.84 102.653 15.858 103.565 ;
     RECT  17.064 102.653 17.082 103.565 ;
     RECT  19.584 103.421 19.602 103.565 ;
     RECT  23.256 103.435 23.994 103.565 ;
     RECT  24.876 102.029 24.894 103.565 ;
     RECT  28.296 102.605 28.314 103.565 ;
     RECT  30.132 101.453 30.33 103.565 ;
     RECT  32.112 102.653 32.13 103.565 ;
     RECT  33.3 102.653 33.318 103.565 ;
     RECT  34.128 103.469 34.434 103.565 ;
     RECT  35.316 103.469 35.334 103.565 ;
     RECT  36.18 102.653 36.522 103.565 ;
     RECT  38.628 102.605 38.646 103.565 ;
     RECT  41.472 103.517 41.598 103.565 ;
     RECT  42.66 103.517 43.002 103.565 ;
     RECT  44.244 102.653 44.262 103.565 ;
     RECT  45 102.653 45.018 103.565 ;
     RECT  46.224 103.421 46.242 103.565 ;
     RECT  48.492 103.435 48.51 103.565 ;
     RECT  50.184 103.435 50.202 103.565 ;
     RECT  51.192 102.605 52.398 103.565 ;
    LAYER M4 ;
     RECT  0.06 26.976 0.133 77.4 ;
     RECT  0.277 100.896 0.469 100.92 ;
     RECT  0.469 100.896 0.661 101.064 ;
     RECT  0.737 2.88 0.821 2.904 ;
     RECT  0.949 3.648 1.045 3.672 ;
     RECT  0.853 4.656 1.045 4.68 ;
     RECT  1.045 3.648 1.141 4.68 ;
     RECT  0.949 99.744 1.189 99.768 ;
     RECT  1.141 3.648 1.421 4.728 ;
     RECT  1.421 3.648 1.493 5.16 ;
     RECT  1.429 97.44 1.525 97.464 ;
     RECT  1.525 96.864 1.621 97.464 ;
     RECT  1.621 96.624 1.717 97.464 ;
     RECT  1.493 3.648 1.813 5.208 ;
     RECT  1.717 95.712 1.813 97.464 ;
     RECT  0.133 26.88 2.113 77.4 ;
     RECT  0.661 100.896 2.149 101.16 ;
     RECT  2.197 93.072 2.285 93.096 ;
     RECT  2.285 93.072 2.293 93.864 ;
     RECT  2.293 93.072 2.329 94.056 ;
     RECT  1.237 1.104 2.389 1.128 ;
     RECT  1.813 3.408 2.408 5.208 ;
     RECT  2.113 26.208 2.408 77.4 ;
     RECT  2.101 91.152 2.408 91.176 ;
     RECT  2.329 93.072 2.408 94.104 ;
     RECT  1.813 95.184 2.408 97.464 ;
     RECT  1.189 99.744 2.408 99.816 ;
     RECT  2.149 100.896 2.408 102.072 ;
     RECT  2.293 103.296 2.483 103.512 ;
     RECT  2.389 0.336 2.501 1.128 ;
     RECT  2.408 2.148 2.501 102.072 ;
     RECT  2.501 0.336 2.531 102.072 ;
     RECT  2.531 0.336 2.677 102.024 ;
     RECT  2.677 0.144 2.704 102.024 ;
     RECT  2.704 25.632 2.729 71.112 ;
     RECT  2.483 103.296 2.732 103.464 ;
     RECT  2.704 92.88 2.765 94.104 ;
     RECT  2.704 95.328 2.765 95.928 ;
     RECT  2.732 103.2 2.819 103.464 ;
     RECT  2.729 66.336 2.837 71.112 ;
     RECT  2.704 72.72 2.839 74.328 ;
     RECT  2.704 0.144 2.867 5.112 ;
     RECT  2.765 92.88 2.867 94.056 ;
     RECT  2.819 103.296 2.867 103.464 ;
     RECT  2.867 1.104 2.873 5.112 ;
     RECT  2.704 99.456 2.915 99.768 ;
     RECT  2.867 92.928 2.945 94.056 ;
     RECT  2.873 1.104 2.981 4.008 ;
     RECT  2.704 100.896 2.981 102.024 ;
     RECT  2.729 25.632 3.133 64.968 ;
     RECT  2.981 1.728 3.251 4.008 ;
     RECT  2.704 75.552 3.683 77.496 ;
     RECT  2.704 96.912 3.685 98.472 ;
     RECT  2.915 99.456 3.685 99.72 ;
     RECT  2.873 4.992 3.731 5.112 ;
     RECT  2.837 66.528 3.737 71.112 ;
     RECT  3.589 103.488 3.779 103.512 ;
     RECT  2.765 95.328 3.877 95.736 ;
     RECT  3.685 96.912 3.877 99.72 ;
     RECT  3.731 5.088 3.923 5.112 ;
     RECT  2.981 100.896 3.949 101.448 ;
     RECT  2.945 92.928 3.953 93.48 ;
     RECT  2.839 72.768 3.973 74.328 ;
     RECT  3.683 75.552 3.973 77.448 ;
     RECT  3.953 92.928 4.025 93.432 ;
     RECT  4.025 92.928 4.061 92.952 ;
     RECT  3.973 72.768 4.133 77.448 ;
     RECT  3.949 100.896 4.307 102.072 ;
     RECT  3.133 25.632 4.309 64.68 ;
     RECT  3.877 95.328 4.345 99.72 ;
     RECT  4.307 100.896 4.345 101.448 ;
     RECT  3.737 68.976 4.357 71.112 ;
     RECT  4.133 72.768 4.357 74.328 ;
     RECT  4.357 68.976 4.385 74.328 ;
     RECT  4.069 91.152 4.417 91.176 ;
     RECT  4.385 71.808 4.444 74.328 ;
     RECT  4.444 71.904 4.499 74.328 ;
     RECT  3.737 66.528 4.501 67.944 ;
     RECT  4.309 25.44 4.525 65.496 ;
     RECT  4.501 66.48 4.525 67.944 ;
     RECT  4.385 68.976 4.529 70.824 ;
     RECT  4.345 95.328 4.549 101.448 ;
     RECT  4.525 25.44 4.561 67.944 ;
     RECT  4.133 75.552 4.565 77.448 ;
     RECT  4.529 68.976 4.588 70.248 ;
     RECT  4.549 94.608 4.637 101.448 ;
     RECT  4.417 91.152 4.709 91.8 ;
     RECT  4.709 91.776 4.739 91.8 ;
     RECT  4.561 25.104 4.817 67.944 ;
     RECT  4.588 68.976 4.817 69.528 ;
     RECT  3.251 1.728 4.885 3.768 ;
     RECT  4.637 94.608 5.141 95.784 ;
     RECT  4.637 96.912 5.141 101.448 ;
     RECT  4.499 72.432 5.213 74.328 ;
     RECT  4.565 76.176 5.213 77.448 ;
     RECT  5.213 76.464 5.389 77.448 ;
     RECT  5.141 96.912 5.459 100.92 ;
     RECT  4.817 25.248 5.465 67.944 ;
     RECT  4.885 1.728 5.573 4.008 ;
     RECT  5.389 76.464 5.573 78.072 ;
     RECT  5.459 100.848 5.609 100.92 ;
     RECT  5.213 73.776 5.645 74.328 ;
     RECT  4.741 103.536 5.681 103.56 ;
     RECT  5.459 96.912 5.749 99.768 ;
     RECT  5.749 96.864 5.843 99.768 ;
     RECT  4.817 69.312 5.857 69.48 ;
     RECT  5.573 76.56 5.861 78.072 ;
     RECT  5.465 25.44 5.933 67.8 ;
     RECT  5.141 94.608 5.941 95.592 ;
     RECT  5.933 25.44 5.987 25.464 ;
     RECT  5.933 26.496 6.028 67.8 ;
     RECT  5.843 99.744 6.035 99.768 ;
     RECT  5.821 70.704 6.037 70.728 ;
     RECT  5.857 68.976 6.041 69.48 ;
     RECT  5.941 22.8 6.083 22.824 ;
     RECT  5.609 100.848 6.113 100.872 ;
     RECT  5.941 94.464 6.133 95.592 ;
     RECT  5.573 1.728 6.149 3.672 ;
     RECT  6.037 5.088 6.179 5.112 ;
     RECT  6.037 70.704 6.181 71.112 ;
     RECT  6.133 94.368 6.257 95.592 ;
     RECT  6.041 69.312 6.329 69.48 ;
     RECT  6.037 91.488 6.329 91.512 ;
     RECT  6.257 95.136 6.421 95.592 ;
     RECT  6.421 95.136 6.517 95.64 ;
     RECT  5.843 96.864 6.517 98.376 ;
     RECT  6.329 69.312 6.545 69.336 ;
     RECT  6.517 95.136 6.545 98.376 ;
     RECT  5.861 76.56 6.577 77.832 ;
     RECT  6.577 75.84 6.581 77.832 ;
     RECT  5.645 74.304 6.685 74.328 ;
     RECT  6.325 102 6.721 102.024 ;
     RECT  6.433 100.176 6.803 100.344 ;
     RECT  6.545 95.376 6.829 98.376 ;
     RECT  6.181 70.704 6.901 71.16 ;
     RECT  6.721 102 7.225 102.072 ;
     RECT  6.685 74.016 7.261 74.328 ;
     RECT  6.149 1.728 7.369 3.528 ;
     RECT  7.369 1.728 7.372 4.008 ;
     RECT  7.073 93.456 7.381 93.48 ;
     RECT  6.803 100.32 7.429 100.344 ;
     RECT  7.225 101.472 7.429 102.072 ;
     RECT  6.997 103.536 7.525 103.56 ;
     RECT  6.829 95.376 7.573 98.568 ;
     RECT  7.573 95.376 7.621 98.712 ;
     RECT  5.213 72.432 7.657 72.456 ;
     RECT  7.429 100.32 7.763 102.072 ;
     RECT  7.372 1.776 7.808 4.008 ;
     RECT  6.028 26.544 7.808 67.8 ;
     RECT  7.009 68.976 7.808 69 ;
     RECT  6.901 70.704 7.808 71.448 ;
     RECT  7.657 72.432 7.808 72.84 ;
     RECT  7.261 73.824 7.808 74.328 ;
     RECT  6.581 75.84 7.808 77.448 ;
     RECT  7.189 91.584 7.808 91.608 ;
     RECT  7.381 92.928 7.808 93.48 ;
     RECT  7.621 95.376 7.808 99.192 ;
     RECT  7.763 100.32 7.808 101.496 ;
     RECT  7.957 0.144 8.053 0.168 ;
     RECT  7.808 1.776 8.104 101.496 ;
     RECT  8.053 0.144 8.149 0.216 ;
     RECT  7.525 103.392 8.204 103.56 ;
     RECT  8.204 103.296 8.291 103.56 ;
     RECT  8.149 0.144 8.339 0.312 ;
     RECT  8.104 1.776 8.341 4.008 ;
     RECT  8.339 0.144 8.435 0.168 ;
     RECT  8.104 100.896 8.435 101.496 ;
     RECT  8.104 92.88 8.461 93.48 ;
     RECT  8.104 95.04 8.561 95.784 ;
     RECT  8.561 95.04 8.633 95.736 ;
     RECT  8.104 26.544 8.669 26.568 ;
     RECT  8.633 95.136 8.669 95.736 ;
     RECT  8.435 100.896 8.677 100.92 ;
     RECT  8.461 93.456 8.705 93.48 ;
     RECT  8.104 5.088 8.771 5.112 ;
     RECT  8.104 27.936 8.957 65.976 ;
     RECT  8.104 72.432 8.957 74.568 ;
     RECT  8.957 28.512 8.993 65.976 ;
     RECT  8.957 72.432 9.125 74.472 ;
     RECT  8.104 76.128 9.133 76.872 ;
     RECT  8.669 95.184 9.148 95.736 ;
     RECT  8.104 67.008 9.205 71.16 ;
     RECT  8.341 1.728 9.217 4.008 ;
     RECT  8.291 103.44 9.253 103.56 ;
     RECT  8.993 29.52 9.353 65.976 ;
     RECT  9.205 67.008 9.385 71.4 ;
     RECT  9.125 72.384 9.385 74.472 ;
     RECT  8.993 28.512 9.389 28.536 ;
     RECT  9.349 91.152 9.397 91.176 ;
     RECT  8.104 96.816 9.421 99.768 ;
     RECT  9.133 76.128 9.529 77.16 ;
     RECT  9.353 29.568 9.533 65.976 ;
     RECT  9.253 103.296 9.533 103.56 ;
     RECT  9.533 29.568 9.569 33.576 ;
     RECT  9.529 76.128 9.601 77.256 ;
     RECT  8.869 102 9.601 102.024 ;
     RECT  9.569 29.568 9.641 30.36 ;
     RECT  9.421 96.816 9.641 100.44 ;
     RECT  9.533 34.992 9.709 65.976 ;
     RECT  9.385 67.008 9.709 74.472 ;
     RECT  9.569 31.392 9.749 33.576 ;
     RECT  9.749 31.392 9.785 33.336 ;
     RECT  9.785 32.16 9.821 33.144 ;
     RECT  9.397 91.152 9.821 91.272 ;
     RECT  9.821 91.248 9.827 91.272 ;
     RECT  9.601 102 9.853 102.072 ;
     RECT  9.709 34.992 9.932 74.472 ;
     RECT  9.641 96.864 9.997 100.44 ;
     RECT  9.853 101.472 9.997 102.072 ;
     RECT  9.932 34.992 10.019 75.048 ;
     RECT  10.019 34.992 10.115 74.568 ;
     RECT  9.148 95.712 10.213 95.736 ;
     RECT  10.213 95.568 10.253 95.736 ;
     RECT  9.641 30.336 10.289 30.36 ;
     RECT  9.217 3.36 10.357 4.008 ;
     RECT  8.104 78.528 10.361 78.552 ;
     RECT  9.821 32.16 10.433 32.808 ;
     RECT  9.997 96.864 10.453 102.072 ;
     RECT  9.533 103.296 10.453 103.512 ;
     RECT  10.115 35.04 10.505 74.568 ;
     RECT  10.253 95.568 10.541 95.592 ;
     RECT  10.505 35.04 10.577 54.792 ;
     RECT  10.453 96.864 10.649 103.512 ;
     RECT  9.541 94.032 10.693 94.056 ;
     RECT  10.577 50.736 10.739 54.792 ;
     RECT  10.649 103.488 10.739 103.512 ;
     RECT  9.601 76.128 10.789 77.544 ;
     RECT  10.357 3.36 10.793 4.248 ;
     RECT  10.433 32.784 10.793 32.808 ;
     RECT  10.577 35.04 10.793 49.224 ;
     RECT  9.217 1.728 10.825 2.28 ;
     RECT  10.793 3.36 10.825 3.48 ;
     RECT  10.649 96.864 10.829 102.024 ;
     RECT  10.693 93.504 10.837 94.056 ;
     RECT  10.261 91.488 10.865 91.512 ;
     RECT  10.793 35.04 10.937 49.176 ;
     RECT  10.837 92.88 10.937 94.056 ;
     RECT  10.937 35.04 10.973 39.144 ;
     RECT  10.505 55.824 10.973 74.568 ;
     RECT  10.789 75.696 11.009 77.544 ;
     RECT  10.937 92.88 11.009 92.952 ;
     RECT  10.829 96.864 11.045 100.584 ;
     RECT  11.045 97.44 11.053 100.584 ;
     RECT  10.973 60.288 11.149 74.568 ;
     RECT  11.009 75.696 11.149 77.256 ;
     RECT  10.829 101.952 11.189 102.024 ;
     RECT  10.973 35.04 11.219 35.064 ;
     RECT  10.937 94.032 11.221 94.056 ;
     RECT  11.053 97.44 11.225 100.344 ;
     RECT  11.189 102 11.297 102.024 ;
     RECT  10.937 40.272 11.369 49.08 ;
     RECT  11.221 94.032 11.405 94.584 ;
     RECT  11.405 94.08 11.413 94.584 ;
     RECT  11.369 44.4 11.441 49.08 ;
     RECT  11.225 97.44 11.441 97.608 ;
     RECT  11.149 60.288 11.513 77.256 ;
     RECT  10.739 50.736 11.621 54.456 ;
     RECT  10.973 55.824 11.621 59.208 ;
     RECT  11.225 100.32 11.621 100.344 ;
     RECT  11.621 51.024 11.693 54.456 ;
     RECT  11.756 102.048 11.843 102.072 ;
     RECT  11.441 44.592 11.941 49.08 ;
     RECT  10.825 1.728 11.945 3.48 ;
     RECT  11.413 94.08 11.945 94.68 ;
     RECT  11.945 94.512 11.953 94.68 ;
     RECT  10.973 36.288 12.013 39.144 ;
     RECT  11.693 51.024 12.053 54.36 ;
     RECT  11.513 60.336 12.085 77.256 ;
     RECT  12.121 100.896 12.205 100.92 ;
     RECT  11.437 90.624 12.227 91.224 ;
     RECT  11.225 98.64 12.229 99.192 ;
     RECT  11.605 96.336 12.257 96.36 ;
     RECT  11.009 92.928 12.373 92.952 ;
     RECT  11.953 94.608 12.469 94.68 ;
     RECT  12.229 98.64 12.613 99.768 ;
     RECT  12.565 103.536 12.653 103.56 ;
     RECT  11.441 97.584 12.689 97.608 ;
     RECT  11.893 7.152 12.901 7.176 ;
     RECT  12.373 92.832 12.901 92.952 ;
     RECT  11.369 40.272 12.913 43.08 ;
     RECT  12.689 97.488 12.949 97.608 ;
     RECT  12.613 98.64 12.949 100.344 ;
     RECT  12.257 96.288 12.997 96.36 ;
     RECT  12.997 96.192 13.021 96.36 ;
     RECT  12.949 97.488 13.021 100.344 ;
     RECT  12.653 103.488 13.093 103.56 ;
     RECT  11.945 1.728 13.208 3.432 ;
     RECT  11.689 5.76 13.208 5.784 ;
     RECT  12.901 6.816 13.208 7.176 ;
     RECT  12.085 21.408 13.208 21.432 ;
     RECT  12.013 36.288 13.208 39.288 ;
     RECT  12.913 40.272 13.208 43.368 ;
     RECT  11.941 44.592 13.208 49.8 ;
     RECT  12.053 51.12 13.208 54.36 ;
     RECT  11.621 55.968 13.208 59.208 ;
     RECT  12.085 60.336 13.208 77.784 ;
     RECT  12.227 90.624 13.208 91.176 ;
     RECT  12.901 92.832 13.208 93.48 ;
     RECT  12.469 94.608 13.208 95.208 ;
     RECT  13.021 96.192 13.208 100.344 ;
     RECT  13.093 102.48 13.331 103.56 ;
     RECT  13.208 1.728 13.4 100.992 ;
     RECT  13.189 0.336 13.429 0.36 ;
     RECT  13.4 1.728 13.429 101.262 ;
     RECT  13.429 1.728 13.504 101.544 ;
     RECT  13.429 0.24 13.58 0.36 ;
     RECT  13.504 3.312 13.601 3.576 ;
     RECT  13.504 95.616 13.601 101.544 ;
     RECT  13.58 0.096 13.619 0.36 ;
     RECT  13.619 0.096 13.667 0.264 ;
     RECT  13.601 95.616 13.673 101.448 ;
     RECT  13.673 95.616 13.853 100.92 ;
     RECT  13.331 102.576 13.853 103.56 ;
     RECT  13.504 91.152 13.933 91.176 ;
     RECT  13.504 92.832 14.069 92.856 ;
     RECT  13.853 102.624 14.099 103.56 ;
     RECT  13.504 1.728 14.213 2.28 ;
     RECT  13.504 5.088 14.243 5.784 ;
     RECT  13.853 95.616 14.249 95.64 ;
     RECT  13.504 37.056 14.401 42.888 ;
     RECT  14.401 37.056 14.531 38.472 ;
     RECT  13.601 3.408 14.581 3.576 ;
     RECT  14.531 37.056 14.609 38.232 ;
     RECT  14.581 2.832 14.669 3.576 ;
     RECT  13.504 61.872 14.749 77.4 ;
     RECT  14.669 2.832 14.753 4.008 ;
     RECT  13.504 44.592 14.821 49.08 ;
     RECT  14.533 94.032 14.933 94.056 ;
     RECT  13.504 7.056 14.965 7.08 ;
     RECT  13.853 96.624 15.005 100.92 ;
     RECT  14.725 91.632 15.077 91.656 ;
     RECT  14.749 61.872 15.185 77.688 ;
     RECT  14.609 37.056 15.293 37.32 ;
     RECT  14.401 40.272 15.397 42.888 ;
     RECT  15.073 94.272 15.401 95.16 ;
     RECT  13.504 60.336 15.577 60.36 ;
     RECT  15.185 61.872 15.577 77.544 ;
     RECT  15.577 60.336 15.761 77.544 ;
     RECT  15.401 94.272 15.923 94.728 ;
     RECT  14.753 2.832 15.965 3.528 ;
     RECT  14.099 103.536 15.98 103.56 ;
     RECT  15.965 2.832 16.049 3.624 ;
     RECT  15.98 102.624 16.067 103.56 ;
     RECT  16.049 2.832 16.121 3.576 ;
     RECT  15.761 61.872 16.121 77.544 ;
     RECT  15.397 40.032 16.259 42.888 ;
     RECT  14.213 1.728 16.264 1.8 ;
     RECT  15.925 92.256 16.301 92.28 ;
     RECT  15.005 96.816 16.309 100.92 ;
     RECT  16.309 96.816 16.405 101.448 ;
     RECT  16.405 96.816 16.445 102.024 ;
     RECT  16.259 40.272 16.451 42.888 ;
     RECT  16.445 99.888 16.481 102.024 ;
     RECT  15.923 94.56 16.549 94.728 ;
     RECT  16.549 94.56 16.645 94.776 ;
     RECT  16.445 96.816 16.693 98.904 ;
     RECT  16.451 41.232 16.787 42.888 ;
     RECT  16.645 94.56 16.787 94.872 ;
     RECT  14.821 44.448 16.873 49.08 ;
     RECT  16.787 41.76 16.877 42.888 ;
     RECT  16.121 61.872 17.093 76.92 ;
     RECT  16.693 96.288 17.129 98.904 ;
     RECT  16.067 103.536 17.157 103.56 ;
     RECT  16.264 1.728 17.189 1.848 ;
     RECT  16.121 2.88 17.189 3.576 ;
     RECT  16.481 102 17.233 102.024 ;
     RECT  17.233 102 17.237 102.648 ;
     RECT  16.729 92.928 17.267 92.952 ;
     RECT  17.189 1.728 17.273 3.576 ;
     RECT  16.877 41.952 17.309 42.888 ;
     RECT  17.273 3.408 17.341 3.576 ;
     RECT  16.741 78.624 17.411 78.648 ;
     RECT  17.129 97.68 17.413 98.904 ;
     RECT  16.481 99.888 17.413 101.016 ;
     RECT  17.413 97.68 17.459 101.016 ;
     RECT  17.459 100.224 17.516 101.016 ;
     RECT  16.981 94.08 17.525 94.104 ;
     RECT  17.309 42.672 17.701 42.888 ;
     RECT  16.873 43.872 17.701 49.08 ;
     RECT  17.093 67.392 17.737 76.92 ;
     RECT  17.737 67.392 17.917 77.016 ;
     RECT  17.797 95.76 17.989 95.784 ;
     RECT  17.653 93.408 18.229 93.48 ;
     RECT  17.237 102.624 18.229 102.648 ;
     RECT  17.093 61.872 18.241 66.36 ;
     RECT  17.917 67.392 18.241 77.064 ;
     RECT  18.229 93.312 18.277 93.48 ;
     RECT  17.273 1.728 18.305 2.28 ;
     RECT  17.341 3.408 18.305 4.008 ;
     RECT  17.459 97.68 18.313 99 ;
     RECT  17.516 100.224 18.313 101.496 ;
     RECT  18.229 102.624 18.313 103.512 ;
     RECT  17.989 95.664 18.325 95.784 ;
     RECT  18.313 96.912 18.325 99 ;
     RECT  18.313 100.224 18.605 103.512 ;
     RECT  18.305 1.728 18.608 4.008 ;
     RECT  14.243 5.76 18.608 5.784 ;
     RECT  14.965 7.056 18.608 7.128 ;
     RECT  17.845 8.448 18.608 8.472 ;
     RECT  15.013 16.272 18.608 16.296 ;
     RECT  13.504 21.408 18.608 21.432 ;
     RECT  15.293 37.152 18.608 37.32 ;
     RECT  17.701 42.672 18.608 49.08 ;
     RECT  13.504 51.648 18.608 54.36 ;
     RECT  13.504 55.968 18.608 59.208 ;
     RECT  15.761 60.336 18.608 60.36 ;
     RECT  18.241 61.872 18.608 77.064 ;
     RECT  18.385 78.576 18.608 78.6 ;
     RECT  18.181 91.152 18.608 91.176 ;
     RECT  18.277 93.216 18.608 93.48 ;
     RECT  17.852 94.608 18.608 94.632 ;
     RECT  18.325 95.664 18.608 99 ;
     RECT  18.605 100.224 18.608 102.072 ;
     RECT  18.608 1.728 18.611 102.072 ;
     RECT  18.421 0.144 18.757 0.168 ;
     RECT  18.611 1.728 18.757 101.448 ;
     RECT  18.757 0.144 18.904 101.448 ;
     RECT  18.904 61.872 19.001 77.064 ;
     RECT  18.904 0.144 19.042 4.008 ;
     RECT  18.904 94.608 19.043 100.344 ;
     RECT  18.904 5.76 19.139 7.128 ;
     RECT  19.139 6.816 19.235 7.128 ;
     RECT  19.042 0.096 19.283 4.008 ;
     RECT  19.283 0.096 19.325 3.48 ;
     RECT  18.904 101.376 19.325 101.448 ;
     RECT  19.325 0.096 19.379 3.432 ;
     RECT  18.904 92.304 19.397 92.328 ;
     RECT  18.904 44.16 19.427 49.176 ;
     RECT  18.605 103.392 19.429 103.512 ;
     RECT  19.379 1.104 19.433 3.432 ;
     RECT  19.379 0.096 19.505 0.12 ;
     RECT  19.429 103.392 19.613 103.56 ;
     RECT  19.427 44.784 19.619 49.176 ;
     RECT  19.001 61.872 19.649 76.44 ;
     RECT  19.619 44.88 19.667 49.176 ;
     RECT  19.649 67.104 19.721 76.44 ;
     RECT  19.667 45.216 19.865 49.176 ;
     RECT  19.649 61.872 19.865 65.976 ;
     RECT  19.721 67.104 19.937 76.344 ;
     RECT  19.043 94.608 19.937 99.768 ;
     RECT  19.937 67.392 19.973 76.344 ;
     RECT  19.973 67.392 20.009 75.288 ;
     RECT  19.613 103.392 20.009 103.416 ;
     RECT  19.973 76.272 20.045 76.344 ;
     RECT  20.045 76.32 20.117 76.344 ;
     RECT  19.937 95.712 20.149 99.768 ;
     RECT  20.009 72.288 20.189 75.288 ;
     RECT  19.865 61.872 20.195 65.592 ;
     RECT  18.904 37.152 20.221 37.32 ;
     RECT  20.009 67.392 20.261 71.112 ;
     RECT  19.865 45.408 20.291 49.176 ;
     RECT  19.937 94.608 20.297 94.632 ;
     RECT  20.329 91.152 20.413 91.176 ;
     RECT  19.325 101.424 20.513 101.448 ;
     RECT  20.149 95.712 20.581 100.344 ;
     RECT  20.581 95.712 20.665 100.92 ;
     RECT  19.433 1.728 20.725 3.432 ;
     RECT  19.235 7.056 20.725 7.128 ;
     RECT  20.629 102.576 20.725 102.6 ;
     RECT  20.291 45.504 20.819 49.176 ;
     RECT  20.725 102.528 20.873 102.6 ;
     RECT  20.725 1.728 20.897 3.528 ;
     RECT  20.819 45.744 20.915 49.176 ;
     RECT  20.725 6.816 20.945 7.128 ;
     RECT  20.897 1.728 20.98 3.624 ;
     RECT  20.261 68.688 20.981 71.112 ;
     RECT  20.915 46.704 21.011 49.176 ;
     RECT  20.873 102.576 21.017 102.6 ;
     RECT  20.665 95.712 21.089 100.344 ;
     RECT  20.98 1.728 21.097 3.672 ;
     RECT  20.761 92.928 21.203 92.952 ;
     RECT  20.189 72.816 21.377 75.288 ;
     RECT  21.205 103.296 21.395 103.512 ;
     RECT  21.011 47.04 21.491 49.176 ;
     RECT  21.089 97.44 21.769 100.344 ;
     RECT  21.581 101.424 21.769 101.448 ;
     RECT  21.349 92.88 21.773 92.904 ;
     RECT  21.395 103.296 21.87 103.464 ;
     RECT  21.87 103.296 21.875 103.416 ;
     RECT  21.553 94.08 21.923 94.104 ;
     RECT  21.875 103.392 21.953 103.416 ;
     RECT  21.097 1.728 22.132 3.432 ;
     RECT  22.157 94.608 22.241 94.632 ;
     RECT  21.769 97.44 22.261 101.448 ;
     RECT  21.829 91.728 22.349 91.752 ;
     RECT  21.377 72.816 22.673 74.136 ;
     RECT  21.491 47.472 22.691 49.176 ;
     RECT  22.261 97.44 22.709 102.024 ;
     RECT  21.089 95.712 22.837 96.456 ;
     RECT  22.709 97.44 22.837 101.448 ;
     RECT  22.132 1.728 22.853 3.48 ;
     RECT  22.837 95.712 22.853 101.448 ;
     RECT  22.691 47.712 22.979 49.176 ;
     RECT  22.979 48.72 23.033 49.176 ;
     RECT  23.033 48.816 23.173 49.176 ;
     RECT  23.173 48.816 23.353 49.608 ;
     RECT  22.853 2.832 23.413 3.48 ;
     RECT  23.137 4.464 23.413 4.488 ;
     RECT  22.853 95.712 23.461 100.344 ;
     RECT  20.945 7.056 23.509 7.128 ;
     RECT  23.029 90.624 23.653 90.648 ;
     RECT  23.077 103.536 23.893 103.56 ;
     RECT  22.853 1.728 24.008 1.848 ;
     RECT  23.413 2.832 24.008 4.488 ;
     RECT  19.139 5.76 24.008 5.784 ;
     RECT  23.509 6.816 24.008 7.128 ;
     RECT  18.904 8.448 24.008 8.472 ;
     RECT  18.904 16.272 24.008 16.296 ;
     RECT  18.904 21.408 24.008 21.432 ;
     RECT  20.221 37.152 24.008 37.416 ;
     RECT  22.979 47.712 24.008 47.736 ;
     RECT  23.353 48.816 24.008 49.8 ;
     RECT  18.904 51.648 24.008 54.36 ;
     RECT  18.904 55.968 24.008 59.208 ;
     RECT  18.904 60.336 24.008 60.36 ;
     RECT  20.195 61.872 24.008 65.496 ;
     RECT  20.261 67.392 24.008 67.608 ;
     RECT  20.981 68.688 24.008 68.712 ;
     RECT  20.981 70.368 24.008 71.112 ;
     RECT  22.673 72.816 24.008 72.84 ;
     RECT  22.673 73.872 24.008 74.136 ;
     RECT  21.377 75.264 24.008 75.288 ;
     RECT  23.653 90.624 24.008 91.512 ;
     RECT  22.837 92.928 24.008 92.952 ;
     RECT  23.821 94.608 24.008 94.632 ;
     RECT  23.461 95.664 24.008 100.344 ;
     RECT  22.853 101.424 24.008 101.448 ;
     RECT  23.893 103.44 24.133 103.56 ;
     RECT  24.037 0.528 24.229 0.552 ;
     RECT  24.133 103.248 24.229 103.56 ;
     RECT  24.008 1.728 24.304 101.448 ;
     RECT  24.229 0.24 24.38 0.552 ;
     RECT  24.38 0.096 24.419 0.552 ;
     RECT  24.419 0.096 24.437 0.456 ;
     RECT  24.437 0.096 24.467 0.36 ;
     RECT  24.229 103.152 24.467 103.56 ;
     RECT  24.467 0.336 24.515 0.36 ;
     RECT  24.304 91.056 24.515 91.08 ;
     RECT  24.467 103.248 24.515 103.56 ;
     RECT  24.304 49.008 24.611 54.36 ;
     RECT  24.304 94.896 24.659 101.448 ;
     RECT  24.659 95.712 24.761 101.448 ;
     RECT  24.304 73.872 24.797 74.136 ;
     RECT  24.515 103.536 24.905 103.56 ;
     RECT  24.761 95.712 25.013 100.92 ;
     RECT  24.304 92.928 25.085 93.144 ;
     RECT  24.611 50.064 25.187 54.36 ;
     RECT  24.304 6.816 25.235 7.128 ;
     RECT  24.304 37.152 25.379 37.416 ;
     RECT  25.285 102 25.409 102.024 ;
     RECT  25.187 50.16 25.553 54.36 ;
     RECT  25.085 92.928 25.621 92.952 ;
     RECT  24.304 61.872 25.697 65.496 ;
     RECT  25.621 92.88 25.705 92.952 ;
     RECT  25.013 95.76 25.729 100.92 ;
     RECT  25.477 94.608 25.733 94.632 ;
     RECT  25.717 102.048 25.909 102.648 ;
     RECT  25.705 92.928 26.003 92.952 ;
     RECT  25.909 102.048 26.099 103.512 ;
     RECT  25.553 50.688 26.195 54.36 ;
     RECT  26.195 51.264 26.243 54.36 ;
     RECT  26.243 51.312 26.273 54.36 ;
     RECT  24.611 49.008 26.291 49.032 ;
     RECT  26.099 102.048 26.435 102.6 ;
     RECT  24.797 74.112 26.444 74.136 ;
     RECT  24.304 75.264 26.444 75.288 ;
     RECT  26.444 74.112 26.453 75.288 ;
     RECT  25.729 95.76 26.657 100.968 ;
     RECT  26.273 51.792 26.723 54.36 ;
     RECT  26.723 52.128 26.771 54.36 ;
     RECT  24.304 1.728 26.777 4.488 ;
     RECT  26.453 75.024 26.777 75.288 ;
     RECT  25.235 7.056 26.821 7.128 ;
     RECT  26.725 91.152 26.885 91.176 ;
     RECT  26.821 6.816 26.963 7.128 ;
     RECT  26.777 4.464 27.097 4.488 ;
     RECT  24.304 5.76 27.097 5.784 ;
     RECT  26.657 95.76 27.109 101.496 ;
     RECT  26.435 102.576 27.109 102.6 ;
     RECT  26.917 92.976 27.251 93 ;
     RECT  27.109 95.568 27.317 101.496 ;
     RECT  26.771 52.32 27.347 54.36 ;
     RECT  27.347 52.416 27.349 54.36 ;
     RECT  24.304 55.968 27.349 59.208 ;
     RECT  27.317 95.568 27.389 100.92 ;
     RECT  27.109 102.576 27.445 103.512 ;
     RECT  27.445 102.528 27.457 103.512 ;
     RECT  27.349 52.416 27.491 59.208 ;
     RECT  27.457 102.048 27.605 103.512 ;
     RECT  24.304 72.816 27.677 72.84 ;
     RECT  27.491 52.464 27.731 59.208 ;
     RECT  27.829 90.912 27.965 90.936 ;
     RECT  27.389 95.712 28.001 100.92 ;
     RECT  27.605 102.048 28.307 102.552 ;
     RECT  27.973 103.536 28.325 103.56 ;
     RECT  26.777 1.728 28.36 3.432 ;
     RECT  28.36 1.728 28.493 3.48 ;
     RECT  27.097 4.464 28.493 5.784 ;
     RECT  28.001 97.344 28.498 100.92 ;
     RECT  28.498 97.344 28.501 100.968 ;
     RECT  28.741 102.576 28.865 103.512 ;
     RECT  27.731 52.464 28.981 54.792 ;
     RECT  27.731 55.824 28.981 59.208 ;
     RECT  28.001 95.712 29.113 96.36 ;
     RECT  29.113 94.752 29.125 96.36 ;
     RECT  28.501 97.344 29.125 101.496 ;
     RECT  29.125 94.752 29.224 101.496 ;
     RECT  29.224 94.704 29.267 101.496 ;
     RECT  28.493 1.728 29.408 5.784 ;
     RECT  26.963 7.056 29.408 7.128 ;
     RECT  24.304 8.448 29.408 8.472 ;
     RECT  24.304 16.272 29.408 16.296 ;
     RECT  24.304 21.408 29.408 21.432 ;
     RECT  25.379 37.152 29.408 37.176 ;
     RECT  28.981 52.464 29.408 59.208 ;
     RECT  24.304 60.336 29.408 60.36 ;
     RECT  25.697 61.872 29.408 65.4 ;
     RECT  24.304 67.392 29.408 67.608 ;
     RECT  24.304 68.688 29.408 68.712 ;
     RECT  24.304 70.368 29.408 71.112 ;
     RECT  26.777 75.264 29.408 75.288 ;
     RECT  28.789 90.624 29.408 90.648 ;
     RECT  28.837 91.728 29.408 91.752 ;
     RECT  29.029 93.456 29.408 93.48 ;
     RECT  29.267 94.704 29.408 101.262 ;
     RECT  29.408 1.728 29.704 101.262 ;
     RECT  28.865 103.248 29.797 103.512 ;
     RECT  29.221 0.144 29.843 0.168 ;
     RECT  29.704 52.464 29.891 54.744 ;
     RECT  29.797 103.248 29.939 103.56 ;
     RECT  29.704 91.728 29.953 92.328 ;
     RECT  29.704 95.76 30.025 101.262 ;
     RECT  29.939 103.44 30.083 103.56 ;
     RECT  29.891 54.672 30.131 54.744 ;
     RECT  30.025 95.76 30.131 99.768 ;
     RECT  29.704 55.776 30.179 59.208 ;
     RECT  30.179 55.872 30.197 59.208 ;
     RECT  30.131 95.76 30.227 98.088 ;
     RECT  29.953 91.728 30.233 91.752 ;
     RECT  30.131 54.72 30.275 54.744 ;
     RECT  30.083 103.536 30.341 103.56 ;
     RECT  30.197 56.304 30.515 59.208 ;
     RECT  30.025 100.752 30.517 101.262 ;
     RECT  29.704 67.392 30.521 67.608 ;
     RECT  30.515 56.352 30.659 59.208 ;
     RECT  30.227 96.144 30.665 98.088 ;
     RECT  30.659 56.736 30.707 59.208 ;
     RECT  29.704 1.728 30.709 5.784 ;
     RECT  29.704 93.936 30.773 94.728 ;
     RECT  30.517 100.752 30.773 101.448 ;
     RECT  30.773 101.424 30.805 101.448 ;
     RECT  29.704 8.448 30.809 8.52 ;
     RECT  30.707 57.072 30.809 59.208 ;
     RECT  30.131 99.408 31.165 99.768 ;
     RECT  30.805 101.424 31.241 102.024 ;
     RECT  30.773 94.032 31.285 94.728 ;
     RECT  30.709 1.728 31.313 1.848 ;
     RECT  31.165 99.408 31.523 100.344 ;
     RECT  30.665 96.192 31.597 98.088 ;
     RECT  31.523 99.408 31.597 99.768 ;
     RECT  31.597 96.192 31.781 99.768 ;
     RECT  31.189 91.152 31.817 91.176 ;
     RECT  31.285 94.032 31.817 95.208 ;
     RECT  31.313 1.728 31.853 1.8 ;
     RECT  30.809 57.072 31.859 59.112 ;
     RECT  31.817 94.032 31.861 94.056 ;
     RECT  31.781 99.072 31.907 99.768 ;
     RECT  31.859 57.36 31.925 59.112 ;
     RECT  31.925 58.128 32.065 59.112 ;
     RECT  29.704 60.336 32.065 60.36 ;
     RECT  31.241 101.424 32.093 101.496 ;
     RECT  29.704 7.056 32.173 7.128 ;
     RECT  29.704 70.368 32.213 71.112 ;
     RECT  31.861 93.504 32.321 94.056 ;
     RECT  31.817 95.184 32.387 95.208 ;
     RECT  32.065 58.128 32.429 60.36 ;
     RECT  31.781 96.192 32.429 98.088 ;
     RECT  32.429 97.44 32.483 98.088 ;
     RECT  31.907 99.168 32.485 99.768 ;
     RECT  32.093 100.896 32.485 101.496 ;
     RECT  32.485 99.168 32.501 101.496 ;
     RECT  32.429 58.224 32.627 60.36 ;
     RECT  32.429 96.192 32.629 96.312 ;
     RECT  32.533 102 32.684 102.024 ;
     RECT  31.957 103.536 32.684 103.56 ;
     RECT  32.627 58.656 32.723 60.36 ;
     RECT  32.723 58.704 32.825 60.36 ;
     RECT  32.321 93.552 32.867 94.056 ;
     RECT  32.501 99.168 32.941 100.872 ;
     RECT  32.684 102 32.969 103.56 ;
     RECT  32.867 94.032 33.005 94.056 ;
     RECT  31.853 1.728 33.157 1.752 ;
     RECT  32.825 58.8 33.257 60.36 ;
     RECT  29.891 52.464 33.301 53.304 ;
     RECT  32.969 102 33.401 102.024 ;
     RECT  32.483 97.44 33.445 97.704 ;
     RECT  32.629 95.712 33.541 96.312 ;
     RECT  33.257 59.232 33.613 60.36 ;
     RECT  33.445 97.44 33.637 98.088 ;
     RECT  32.941 99.168 33.637 99.24 ;
     RECT  30.709 2.88 33.649 5.784 ;
     RECT  33.541 95.136 33.781 96.312 ;
     RECT  33.637 97.44 33.781 99.24 ;
     RECT  33.613 59.232 33.829 60.408 ;
     RECT  29.704 61.872 33.829 65.4 ;
     RECT  33.157 1.728 33.973 1.8 ;
     RECT  33.649 2.832 33.973 5.784 ;
     RECT  33.781 95.136 34.441 99.24 ;
     RECT  33.589 91.152 34.453 91.176 ;
     RECT  34.441 94.608 34.46 99.24 ;
     RECT  32.941 100.272 34.46 100.872 ;
     RECT  34.405 102 34.556 102.024 ;
     RECT  34.556 102 34.661 102.12 ;
     RECT  34.021 92.832 34.729 92.856 ;
     RECT  34.46 94.608 34.765 100.872 ;
     RECT  32.969 103.248 34.789 103.56 ;
     RECT  33.973 1.728 34.808 5.784 ;
     RECT  32.173 7.056 34.808 7.176 ;
     RECT  30.809 8.448 34.808 8.472 ;
     RECT  29.704 16.272 34.808 16.296 ;
     RECT  29.704 21.408 34.808 21.432 ;
     RECT  29.704 37.152 34.808 37.176 ;
     RECT  33.301 52.272 34.808 53.304 ;
     RECT  33.829 59.232 34.808 65.4 ;
     RECT  30.521 67.392 34.808 67.416 ;
     RECT  29.704 68.688 34.808 68.712 ;
     RECT  32.213 71.088 34.808 71.112 ;
     RECT  29.704 75.264 34.808 75.288 ;
     RECT  34.453 90.96 34.808 91.176 ;
     RECT  34.729 92.832 34.808 93 ;
     RECT  34.765 94.608 34.808 101.448 ;
     RECT  34.789 102.576 34.913 103.56 ;
     RECT  34.933 0.432 35.029 0.456 ;
     RECT  34.808 1.728 35.104 101.448 ;
     RECT  35.029 0.432 35.125 0.552 ;
     RECT  35.104 52.272 35.165 52.776 ;
     RECT  35.125 0.336 35.218 0.552 ;
     RECT  35.104 50.256 35.219 51.24 ;
     RECT  35.104 70.704 35.267 71.112 ;
     RECT  35.104 92.832 35.267 94.632 ;
     RECT  35.267 71.088 35.273 71.112 ;
     RECT  34.913 103.248 35.306 103.56 ;
     RECT  35.219 51.12 35.308 51.24 ;
     RECT  35.267 92.832 35.309 93 ;
     RECT  35.267 94.032 35.315 94.632 ;
     RECT  35.309 92.976 35.363 93 ;
     RECT  35.104 101.424 35.363 101.448 ;
     RECT  35.306 103.296 35.389 103.56 ;
     RECT  35.165 52.464 35.459 52.776 ;
     RECT  35.308 51.12 35.5 51.144 ;
     RECT  35.104 49.056 35.555 49.08 ;
     RECT  35.459 52.56 35.555 52.776 ;
     RECT  35.218 0.096 35.677 0.552 ;
     RECT  35.104 61.008 35.843 65.544 ;
     RECT  35.677 0.144 35.845 0.552 ;
     RECT  35.104 1.728 35.845 5.784 ;
     RECT  35.845 0.144 35.849 5.784 ;
     RECT  35.849 0.144 35.891 1.848 ;
     RECT  35.843 61.584 36.029 65.544 ;
     RECT  35.891 1.008 36.035 1.848 ;
     RECT  35.104 95.664 36.277 100.344 ;
     RECT  36.277 95.184 36.289 100.344 ;
     RECT  35.104 90.048 36.371 90.072 ;
     RECT  35.315 94.032 36.457 94.104 ;
     RECT  36.289 95.184 36.497 96.936 ;
     RECT  35.389 103.536 36.524 103.56 ;
     RECT  36.524 102.624 36.533 103.56 ;
     RECT  36.533 102.624 36.613 102.648 ;
     RECT  36.497 95.184 36.713 95.208 ;
     RECT  36.613 102.528 36.748 102.648 ;
     RECT  36.457 93.504 36.755 94.104 ;
     RECT  36.289 98.016 36.757 100.344 ;
     RECT  36.755 93.504 36.803 93.528 ;
     RECT  35.104 6.96 36.853 7.176 ;
     RECT  36.757 98.016 36.853 100.872 ;
     RECT  35.104 67.392 36.857 67.416 ;
     RECT  36.853 98.016 36.908 101.448 ;
     RECT  36.035 1.728 36.949 1.848 ;
     RECT  35.849 2.832 36.949 5.784 ;
     RECT  36.029 62.16 36.965 65.544 ;
     RECT  36.613 91.152 37.037 91.176 ;
     RECT  36.965 62.4 37.043 65.544 ;
     RECT  36.908 98.016 37.141 101.496 ;
     RECT  36.748 102.528 37.141 102.6 ;
     RECT  37.043 62.64 37.235 65.544 ;
     RECT  37.141 98.016 37.261 102.6 ;
     RECT  36.497 96.192 37.277 96.936 ;
     RECT  37.261 98.016 37.277 98.616 ;
     RECT  37.235 63.12 37.285 65.544 ;
     RECT  37.285 63.12 37.397 66.12 ;
     RECT  37.397 63.552 37.427 66.12 ;
     RECT  35.104 68.688 37.433 68.712 ;
     RECT  36.949 1.728 37.537 5.784 ;
     RECT  36.853 6.816 37.537 7.176 ;
     RECT  37.237 95.136 37.864 95.16 ;
     RECT  37.357 92.352 37.907 92.376 ;
     RECT  37.429 72.96 38.051 72.984 ;
     RECT  37.864 95.136 38.053 95.208 ;
     RECT  37.277 96.192 38.053 98.616 ;
     RECT  37.261 99.744 38.117 102.6 ;
     RECT  38.117 100.32 38.153 102.6 ;
     RECT  38.053 95.136 38.243 98.616 ;
     RECT  38.153 102.576 38.245 102.6 ;
     RECT  38.245 102.576 38.405 103.56 ;
     RECT  37.427 63.552 38.483 65.544 ;
     RECT  38.153 100.32 38.483 101.496 ;
     RECT  38.243 95.712 38.521 98.616 ;
     RECT  38.483 63.792 38.585 65.544 ;
     RECT  38.405 103.536 38.657 103.56 ;
     RECT  38.585 64.464 38.725 65.544 ;
     RECT  38.533 92.304 38.725 92.328 ;
     RECT  38.521 95.712 38.729 96.936 ;
     RECT  38.729 95.712 38.837 96.216 ;
     RECT  38.725 64.464 38.867 65.688 ;
     RECT  35.104 16.272 38.905 16.296 ;
     RECT  38.905 16.272 39.049 16.584 ;
     RECT  35.104 37.152 39.059 37.176 ;
     RECT  38.867 64.464 39.059 65.544 ;
     RECT  38.545 94.608 39.077 94.728 ;
     RECT  39.049 15.984 39.133 16.584 ;
     RECT  39.077 94.032 39.161 94.728 ;
     RECT  38.725 92.016 39.197 92.328 ;
     RECT  38.483 100.32 39.197 100.92 ;
     RECT  39.059 65.52 39.203 65.544 ;
     RECT  39.197 100.32 39.397 100.344 ;
     RECT  39.161 94.704 39.445 94.728 ;
     RECT  38.521 97.92 39.589 98.616 ;
     RECT  39.493 102.576 39.629 102.6 ;
     RECT  38.837 96.192 39.733 96.216 ;
     RECT  39.733 101.472 39.769 101.496 ;
     RECT  39.589 97.92 39.805 99.192 ;
     RECT  39.397 100.224 39.805 100.344 ;
     RECT  39.877 0.384 39.925 0.408 ;
     RECT  39.925 0.288 39.973 0.408 ;
     RECT  39.733 96.192 39.973 96.408 ;
     RECT  39.973 0.192 40.018 0.408 ;
     RECT  40.018 0.096 40.019 0.408 ;
     RECT  39.805 97.92 40.021 100.344 ;
     RECT  39.973 96.192 40.069 96.744 ;
     RECT  37.537 1.728 40.093 7.176 ;
     RECT  40.019 0.096 40.097 0.312 ;
     RECT  40.097 0.096 40.115 0.216 ;
     RECT  40.115 0.096 40.141 0.168 ;
     RECT  40.093 1.728 40.208 7.464 ;
     RECT  35.104 8.448 40.208 8.472 ;
     RECT  39.877 10.8 40.208 10.824 ;
     RECT  39.133 16.272 40.208 16.584 ;
     RECT  35.104 21.408 40.208 21.432 ;
     RECT  35.555 52.752 40.208 52.776 ;
     RECT  39.059 64.464 40.208 64.488 ;
     RECT  39.625 91.776 40.208 91.8 ;
     RECT  39.205 92.928 40.208 92.952 ;
     RECT  39.445 94.704 40.208 95.208 ;
     RECT  40.069 96.192 40.208 96.84 ;
     RECT  40.021 97.824 40.208 100.344 ;
     RECT  39.769 101.472 40.208 101.544 ;
     RECT  40.208 1.728 40.307 101.544 ;
     RECT  40.307 1.728 40.504 101.262 ;
     RECT  39.877 103.296 40.597 103.56 ;
     RECT  40.141 0.144 40.643 0.168 ;
     RECT  40.504 93.504 41.033 94.104 ;
     RECT  40.504 1.728 41.123 7.464 ;
     RECT  40.504 95.616 41.321 100.344 ;
     RECT  40.597 102.576 41.389 103.56 ;
     RECT  41.389 102.144 41.497 103.56 ;
     RECT  41.123 2.88 41.573 7.464 ;
     RECT  41.497 102.048 41.749 103.56 ;
     RECT  41.321 95.616 41.825 96.312 ;
     RECT  41.749 101.424 41.891 103.56 ;
     RECT  40.504 72.384 41.939 72.408 ;
     RECT  41.321 97.44 41.965 100.344 ;
     RECT  41.891 101.424 41.965 102.024 ;
     RECT  41.845 94.56 41.989 94.584 ;
     RECT  40.504 76.368 42.035 76.392 ;
     RECT  41.123 1.728 42.092 1.8 ;
     RECT  41.573 3.408 42.149 7.464 ;
     RECT  41.965 97.44 42.149 102.024 ;
     RECT  41.641 9.648 42.293 9.672 ;
     RECT  41.825 95.712 42.293 96.312 ;
     RECT  41.989 94.56 42.325 94.728 ;
     RECT  42.149 97.44 42.419 101.448 ;
     RECT  42.325 94.512 42.515 94.728 ;
     RECT  42.419 100.848 42.545 101.448 ;
     RECT  42.515 94.704 42.617 94.728 ;
     RECT  42.092 1.728 42.757 2.28 ;
     RECT  42.149 3.408 42.757 7.176 ;
     RECT  42.293 95.952 42.805 96.312 ;
     RECT  42.419 97.44 42.805 99.768 ;
     RECT  40.504 21.408 42.833 21.432 ;
     RECT  42.805 95.952 42.941 99.768 ;
     RECT  42.541 91.776 42.965 91.8 ;
     RECT  42.421 90.432 43.013 90.456 ;
     RECT  41.891 103.296 43.013 103.56 ;
     RECT  40.504 64.464 43.085 64.488 ;
     RECT  42.941 95.952 43.085 95.976 ;
     RECT  41.033 93.504 43.121 93.528 ;
     RECT  42.757 1.728 43.333 7.176 ;
     RECT  43.013 103.296 43.333 103.512 ;
     RECT  43.333 102.576 43.445 103.512 ;
     RECT  42.941 97.44 43.541 99.768 ;
     RECT  43.505 102 43.589 102.024 ;
     RECT  42.965 91.728 43.619 91.8 ;
     RECT  42.545 100.848 43.717 100.872 ;
     RECT  43.585 94.752 43.801 94.776 ;
     RECT  43.801 94.656 43.841 94.776 ;
     RECT  43.541 97.44 43.937 99.816 ;
     RECT  43.717 100.848 43.937 100.92 ;
     RECT  43.841 94.656 43.955 94.68 ;
     RECT  43.445 103.488 44.101 103.512 ;
     RECT  43.813 88.896 44.129 88.92 ;
     RECT  43.333 1.728 44.161 7.272 ;
     RECT  43.621 90.048 44.197 90.072 ;
     RECT  43.937 97.44 44.197 100.92 ;
     RECT  43.861 91.152 44.237 91.176 ;
     RECT  44.233 94.032 44.317 94.056 ;
     RECT  44.197 97.44 44.345 101.448 ;
     RECT  44.345 97.44 44.521 100.968 ;
     RECT  44.101 103.488 44.593 103.56 ;
     RECT  44.593 102.624 44.677 103.56 ;
     RECT  44.521 96.72 44.953 100.968 ;
     RECT  44.161 1.728 44.989 7.416 ;
     RECT  40.504 8.448 44.989 8.472 ;
     RECT  44.989 1.728 45.277 8.472 ;
     RECT  45.205 94.608 45.277 94.632 ;
     RECT  44.953 95.904 45.277 100.968 ;
     RECT  45.277 94.608 45.385 100.968 ;
     RECT  44.677 102 45.491 103.56 ;
     RECT  45.277 1.728 45.608 8.568 ;
     RECT  43.909 10.8 45.608 10.824 ;
     RECT  44.737 18.816 45.608 18.84 ;
     RECT  40.504 52.752 45.608 52.776 ;
     RECT  44.197 89.472 45.608 90.072 ;
     RECT  45.385 94.08 45.608 100.968 ;
     RECT  45.637 0.528 45.733 0.552 ;
     RECT  45.608 1.728 45.8 100.992 ;
     RECT  45.733 0.528 45.829 0.648 ;
     RECT  45.829 0.336 45.877 0.648 ;
     RECT  45.8 1.728 45.904 101.736 ;
     RECT  45.904 92.928 45.965 101.736 ;
     RECT  45.877 0.144 46.067 0.648 ;
     RECT  45.965 92.928 46.067 96.936 ;
     RECT  46.067 92.928 46.115 93.816 ;
     RECT  45.491 103.104 46.253 103.56 ;
     RECT  45.904 2.736 46.289 9.816 ;
     RECT  46.115 93.504 46.289 93.816 ;
     RECT  46.289 3.36 46.307 9.816 ;
     RECT  46.067 0.24 46.325 0.6 ;
     RECT  46.253 103.104 46.355 103.512 ;
     RECT  45.965 98.064 46.573 101.736 ;
     RECT  46.067 94.848 46.933 96.936 ;
     RECT  46.573 98.064 46.933 102.072 ;
     RECT  46.325 0.576 46.937 0.6 ;
     RECT  45.904 89.856 46.937 89.88 ;
     RECT  46.307 3.408 47.113 9.816 ;
     RECT  46.933 94.848 47.189 102.072 ;
     RECT  47.113 88.32 47.197 88.344 ;
     RECT  47.189 94.848 47.365 96.12 ;
     RECT  47.189 97.488 47.509 102.072 ;
     RECT  46.355 103.2 47.509 103.512 ;
     RECT  46.289 93.504 47.545 93.528 ;
     RECT  47.365 94.608 47.545 96.12 ;
     RECT  47.509 97.488 47.555 103.512 ;
     RECT  47.555 97.488 47.795 99.768 ;
     RECT  47.113 3.408 47.833 10.296 ;
     RECT  46.981 11.424 47.833 11.448 ;
     RECT  47.833 3.408 47.873 11.448 ;
     RECT  45.904 1.728 47.905 1.752 ;
     RECT  47.873 3.408 47.905 11.4 ;
     RECT  47.795 97.488 48.053 99.72 ;
     RECT  48.053 97.584 48.125 99.72 ;
     RECT  45.904 91.056 48.193 91.08 ;
     RECT  48.037 92.304 48.193 92.328 ;
     RECT  47.905 1.728 48.323 11.4 ;
     RECT  47.555 100.896 48.325 103.512 ;
     RECT  48.193 91.056 48.469 92.328 ;
     RECT  47.545 93.504 48.469 96.12 ;
     RECT  48.469 90.72 48.481 92.328 ;
     RECT  48.469 93.408 48.481 96.12 ;
     RECT  48.481 90.72 48.515 96.12 ;
     RECT  48.515 92.304 48.521 96.12 ;
     RECT  48.325 100.896 48.521 103.56 ;
     RECT  48.521 92.928 48.553 96.12 ;
     RECT  48.515 90.72 48.661 91.08 ;
     RECT  48.323 11.376 48.773 11.4 ;
     RECT  48.323 1.728 48.803 10.296 ;
     RECT  48.125 98.064 48.844 99.72 ;
     RECT  48.844 98.496 48.849 99.72 ;
     RECT  48.521 100.896 48.849 103.512 ;
     RECT  48.849 98.496 48.851 103.512 ;
     RECT  48.803 1.728 48.877 9.72 ;
     RECT  47.473 89.472 48.877 89.496 ;
     RECT  48.661 90.624 48.877 91.08 ;
     RECT  48.877 1.632 48.94 9.72 ;
     RECT  48.553 92.928 48.947 96.408 ;
     RECT  48.947 92.976 48.953 96.408 ;
     RECT  48.953 92.976 48.989 95.928 ;
     RECT  48.989 93.024 48.995 95.928 ;
     RECT  48.995 93.504 49.139 95.928 ;
     RECT  48.877 89.472 49.165 91.08 ;
     RECT  49.121 97.488 49.205 97.512 ;
     RECT  48.94 6.864 49.235 9.72 ;
     RECT  49.235 9.696 49.283 9.72 ;
     RECT  49.093 0.144 49.345 0.168 ;
     RECT  48.94 1.632 49.345 5.16 ;
     RECT  49.139 94.032 49.421 95.928 ;
     RECT  49.421 94.032 49.493 95.88 ;
     RECT  49.165 88.944 49.525 91.08 ;
     RECT  49.235 6.864 49.529 8.568 ;
     RECT  49.493 95.184 49.565 95.88 ;
     RECT  49.345 0.144 49.571 5.16 ;
     RECT  49.525 96.912 49.609 96.936 ;
     RECT  49.565 95.712 49.619 95.88 ;
     RECT  49.525 88.944 49.667 91.752 ;
     RECT  48.851 98.496 49.667 102.6 ;
     RECT  48.985 87.744 49.705 87.768 ;
     RECT  49.529 7.392 49.715 8.568 ;
     RECT  49.667 88.944 49.741 90.648 ;
     RECT  49.571 0.144 49.745 3.432 ;
     RECT  49.741 88.848 49.763 90.648 ;
     RECT  49.571 4.56 49.781 5.16 ;
     RECT  49.781 4.656 49.789 5.16 ;
     RECT  49.763 90.048 49.853 90.648 ;
     RECT  49.715 7.44 49.889 8.568 ;
     RECT  49.493 94.032 49.961 94.056 ;
     RECT  49.667 102.576 50.129 102.6 ;
     RECT  49.745 2.256 50.147 3.432 ;
     RECT  49.889 7.44 50.147 7.464 ;
     RECT  49.745 0.144 50.165 1.128 ;
     RECT  49.705 87.456 50.173 87.768 ;
     RECT  49.763 88.848 50.173 88.968 ;
     RECT  50.147 2.784 50.177 3.432 ;
     RECT  49.853 90.048 50.195 90.072 ;
     RECT  49.667 98.496 50.195 101.448 ;
     RECT  50.173 87.456 50.249 88.968 ;
     RECT  50.249 87.456 50.257 88.344 ;
     RECT  49.667 91.632 50.281 91.752 ;
     RECT  50.177 2.832 50.365 3.432 ;
     RECT  50.281 91.632 50.387 91.8 ;
     RECT  50.257 87.456 50.483 87.768 ;
     RECT  49.789 5.136 50.531 5.16 ;
     RECT  50.195 98.544 50.579 101.448 ;
     RECT  50.165 0.096 50.645 1.128 ;
     RECT  50.365 2.832 50.723 2.856 ;
     RECT  50.483 87.456 50.723 87.48 ;
     RECT  50.579 100.848 50.753 101.448 ;
     RECT  49.889 8.544 50.771 8.568 ;
     RECT  49.619 95.856 50.771 95.88 ;
     RECT  50.753 100.848 50.789 100.872 ;
     RECT  50.645 0.528 50.819 1.128 ;
     RECT  50.129 102.576 50.825 103.56 ;
     RECT  50.579 98.544 50.861 99.768 ;
     RECT  50.861 99.168 50.897 99.768 ;
     RECT  50.819 0.528 50.915 0.552 ;
     RECT  50.387 91.632 50.915 91.704 ;
     RECT  50.897 99.744 51.011 99.768 ;
     RECT  50.915 91.632 51.107 91.656 ;
     RECT  50.825 102.624 51.875 103.56 ;
     RECT  45.904 52.752 52.115 52.776 ;
     RECT  51.875 103.536 52.409 103.56 ;
    LAYER M5 ;
     RECT  0.768 0.016 50.904 0.563 ;
     RECT  0.768 0.563 50.808 1.139 ;
     RECT  0.768 1.139 50.712 2.867 ;
     RECT  0.768 2.867 50.52 2.915 ;
     RECT  0.864 2.915 50.52 3.443 ;
     RECT  0.864 3.443 11.928 3.491 ;
     RECT  13.056 3.443 50.52 3.539 ;
     RECT  13.056 3.539 41.736 3.587 ;
     RECT  17.232 3.587 41.736 3.683 ;
     RECT  42.768 3.539 50.52 3.683 ;
     RECT  31.92 3.683 32.328 4.019 ;
     RECT  47.568 3.683 50.52 4.019 ;
     RECT  47.664 4.019 50.52 4.067 ;
     RECT  33.696 3.683 41.256 4.645 ;
     RECT  42.768 3.683 46.536 4.645 ;
     RECT  0.864 3.491 10.872 4.691 ;
     RECT  1.152 4.691 10.872 4.739 ;
     RECT  33.696 4.645 46.536 5.077 ;
     RECT  48 4.067 50.52 5.077 ;
     RECT  1.44 4.739 10.872 5.171 ;
     RECT  33.696 5.077 50.52 5.171 ;
     RECT  1.536 5.171 10.872 5.219 ;
     RECT  13.056 3.587 16.152 6.805 ;
     RECT  33.696 5.171 50.136 7.475 ;
     RECT  11.904 7.141 11.928 21.397 ;
     RECT  12.912 6.805 16.152 21.397 ;
     RECT  2.4 5.219 10.872 26.197 ;
     RECT  2.304 26.197 10.872 27.109 ;
     RECT  1.152 27.973 1.176 28.259 ;
     RECT  2.256 27.109 10.872 29.795 ;
     RECT  1.152 32.485 1.176 32.819 ;
     RECT  0.144 32.773 0.168 33.059 ;
     RECT  2.304 29.795 10.872 35.029 ;
     RECT  11.904 21.397 16.152 35.029 ;
     RECT  2.304 35.029 16.152 40.021 ;
     RECT  2.304 40.021 16.248 40.261 ;
     RECT  17.232 3.683 30.696 40.261 ;
     RECT  0.192 46.405 0.216 46.595 ;
     RECT  0.144 48.181 0.168 48.467 ;
     RECT  1.152 48.997 1.176 49.235 ;
     RECT  1.152 50.869 1.176 51.011 ;
     RECT  0.144 50.341 0.168 51.683 ;
     RECT  33.696 7.475 49.608 52.261 ;
     RECT  0.144 53.365 0.168 54.131 ;
     RECT  2.304 40.261 30.696 57.205 ;
     RECT  31.824 57.061 31.848 57.205 ;
     RECT  2.304 57.205 31.848 58.117 ;
     RECT  2.304 58.117 32.136 58.213 ;
     RECT  33.312 52.261 49.608 58.213 ;
     RECT  0.144 61.141 0.168 61.379 ;
     RECT  0.144 67.909 0.168 68.099 ;
     RECT  0.192 70.357 0.216 70.643 ;
     RECT  0.144 73.621 0.168 73.811 ;
     RECT  0.144 77.029 0.168 77.315 ;
     RECT  50.736 8.533 50.76 87.445 ;
     RECT  2.304 58.213 49.608 87.733 ;
     RECT  50.688 87.445 50.76 87.733 ;
     RECT  2.304 87.733 50.76 91.141 ;
     RECT  2.112 91.141 50.76 91.621 ;
     RECT  2.112 91.621 51.096 95.173 ;
     RECT  1.824 95.173 51.096 95.701 ;
     RECT  1.728 95.701 51.096 96.613 ;
     RECT  1.632 96.613 51.096 96.853 ;
     RECT  1.536 96.853 51.096 97.429 ;
     RECT  1.44 97.429 51.096 99.733 ;
     RECT  0.96 99.733 51.096 100.885 ;
     RECT  0.288 100.885 51.096 102.613 ;
     RECT  52.08 52.741 52.104 102.613 ;
     RECT  0.288 102.613 52.104 103.525 ;
     RECT  0.288 103.525 52.392 103.632 ;
     RECT  11.928 3.443 13.056 3.491 ;
     RECT  41.736 3.539 42.768 3.683 ;
     RECT  16.152 3.587 17.232 40.021 ;
     RECT  30.696 3.683 31.92 4.019 ;
     RECT  32.328 3.683 33.696 4.019 ;
     RECT  41.256 3.683 42.768 4.645 ;
     RECT  46.536 3.683 47.568 4.019 ;
     RECT  46.536 4.019 47.664 4.067 ;
     RECT  46.536 4.067 48 5.077 ;
     RECT  10.872 7.141 11.904 35.029 ;
     RECT  11.928 7.141 12.912 21.397 ;
     RECT  49.608 7.475 50.136 8.533 ;
     RECT  49.608 8.533 50.736 87.445 ;
     RECT  1.176 27.973 2.256 28.259 ;
     RECT  1.176 32.485 2.304 32.819 ;
     RECT  0.168 32.773 1.152 32.819 ;
     RECT  16.248 40.021 17.232 40.261 ;
     RECT  1.176 48.997 2.304 49.235 ;
     RECT  0.168 50.869 1.152 51.011 ;
     RECT  1.176 50.869 2.304 51.011 ;
     RECT  50.76 52.741 52.08 91.621 ;
     RECT  30.696 57.061 31.824 57.205 ;
     RECT  31.848 57.061 33.312 58.117 ;
     RECT  32.136 58.117 33.312 58.213 ;
     RECT  49.608 87.445 50.688 87.733 ;
     RECT  51.096 91.621 52.08 102.613 ;
  END
END qfd_xcst_n_m5
END LIBRARY
